VERSION 5.8 ;
BUSBITCHARS "[]" ;
DIVIDERCHAR "/" ;
UNITS
    DATABASE MICRONS 1000 ;
END UNITS

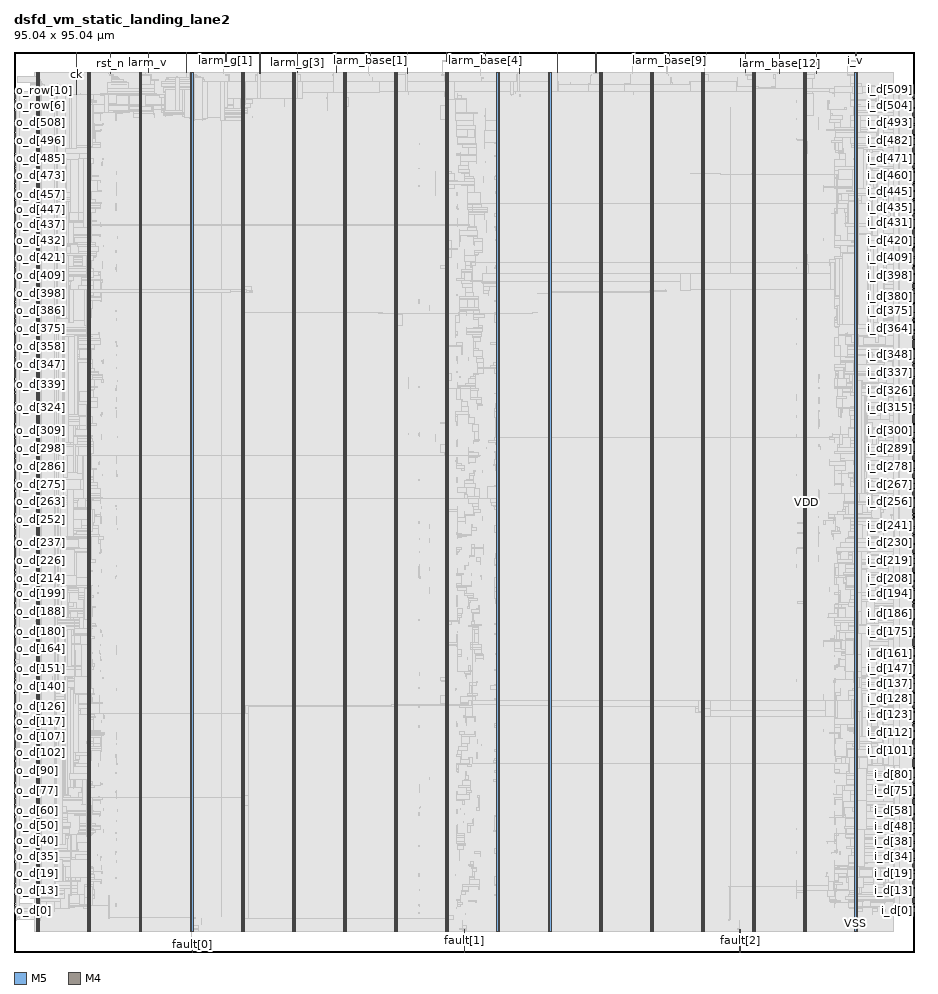
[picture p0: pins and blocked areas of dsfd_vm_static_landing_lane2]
MACRO dsfd_vm_static_landing_lane2
  FOREIGN dsfd_vm_static_landing_lane2 0 0 ;
  CLASS BLOCK ;
  SIZE 95.04 BY 95.04 ;
  PIN ck
    DIRECTION INPUT ;
    USE SIGNAL ;
    PORT
      LAYER M5 ;
        RECT  6.576 94.848 6.6 95.04 ;
    END
    PORT
      LAYER M5 ;
        RECT  6.576 90.563 6.6 94.864 ;
    END
  END ck
  PIN fault[0]
    DIRECTION OUTPUT ;
    USE SIGNAL ;
    PORT
      LAYER M5 ;
        RECT  18.816 0 18.84 0.192 ;
    END
    PORT
      LAYER M5 ;
        RECT  18.816 0.144 18.84 0.227 ;
    END
  END fault[0]
  PIN fault[1]
    DIRECTION OUTPUT ;
    USE SIGNAL ;
    PORT
      LAYER M5 ;
        RECT  47.568 0 47.592 0.192 ;
    END
    PORT
      LAYER M5 ;
        RECT  47.568 0.144 47.592 2.339 ;
    END
  END fault[1]
  PIN fault[2]
    DIRECTION OUTPUT ;
    USE SIGNAL ;
    PORT
      LAYER M5 ;
        RECT  76.656 0 76.68 0.192 ;
    END
    PORT
      LAYER M5 ;
        RECT  76.656 0.144 76.68 2.339 ;
    END
  END fault[2]
  PIN i_d[0]
    DIRECTION INPUT ;
    USE SIGNAL ;
    PORT
      LAYER M4 ;
        RECT  94.848 4.32 95.04 4.344 ;
    END
  END i_d[0]
  PIN i_d[100]
    DIRECTION INPUT ;
    USE SIGNAL ;
    PORT
      LAYER M4 ;
        RECT  94.848 21.168 95.04 21.192 ;
    END
  END i_d[100]
  PIN i_d[101]
    DIRECTION INPUT ;
    USE SIGNAL ;
    PORT
      LAYER M4 ;
        RECT  94.848 21.312 95.04 21.336 ;
    END
  END i_d[101]
  PIN i_d[102]
    DIRECTION INPUT ;
    USE SIGNAL ;
    PORT
      LAYER M4 ;
        RECT  94.848 21.6 95.04 21.624 ;
    END
  END i_d[102]
  PIN i_d[103]
    DIRECTION INPUT ;
    USE SIGNAL ;
    PORT
      LAYER M4 ;
        RECT  94.848 21.744 95.04 21.768 ;
    END
  END i_d[103]
  PIN i_d[104]
    DIRECTION INPUT ;
    USE SIGNAL ;
    PORT
      LAYER M4 ;
        RECT  94.848 21.888 95.04 21.912 ;
    END
  END i_d[104]
  PIN i_d[105]
    DIRECTION INPUT ;
    USE SIGNAL ;
    PORT
      LAYER M4 ;
        RECT  94.848 22.032 95.04 22.056 ;
    END
  END i_d[105]
  PIN i_d[106]
    DIRECTION INPUT ;
    USE SIGNAL ;
    PORT
      LAYER M4 ;
        RECT  94.848 22.176 95.04 22.2 ;
    END
  END i_d[106]
  PIN i_d[107]
    DIRECTION INPUT ;
    USE SIGNAL ;
    PORT
      LAYER M4 ;
        RECT  94.848 22.32 95.04 22.344 ;
    END
  END i_d[107]
  PIN i_d[108]
    DIRECTION INPUT ;
    USE SIGNAL ;
    PORT
      LAYER M4 ;
        RECT  94.848 22.608 95.04 22.632 ;
    END
  END i_d[108]
  PIN i_d[109]
    DIRECTION INPUT ;
    USE SIGNAL ;
    PORT
      LAYER M4 ;
        RECT  94.848 22.752 95.04 22.776 ;
    END
  END i_d[109]
  PIN i_d[10]
    DIRECTION INPUT ;
    USE SIGNAL ;
    PORT
      LAYER M4 ;
        RECT  94.848 6.048 95.04 6.072 ;
    END
  END i_d[10]
  PIN i_d[110]
    DIRECTION INPUT ;
    USE SIGNAL ;
    PORT
      LAYER M4 ;
        RECT  94.848 22.896 95.04 22.92 ;
    END
  END i_d[110]
  PIN i_d[111]
    DIRECTION INPUT ;
    USE SIGNAL ;
    PORT
      LAYER M4 ;
        RECT  94.848 23.04 95.04 23.064 ;
    END
  END i_d[111]
  PIN i_d[112]
    DIRECTION INPUT ;
    USE SIGNAL ;
    PORT
      LAYER M4 ;
        RECT  94.848 23.184 95.04 23.208 ;
    END
  END i_d[112]
  PIN i_d[113]
    DIRECTION INPUT ;
    USE SIGNAL ;
    PORT
      LAYER M4 ;
        RECT  94.848 23.472 95.04 23.496 ;
    END
  END i_d[113]
  PIN i_d[114]
    DIRECTION INPUT ;
    USE SIGNAL ;
    PORT
      LAYER M4 ;
        RECT  94.848 23.616 95.04 23.64 ;
    END
  END i_d[114]
  PIN i_d[115]
    DIRECTION INPUT ;
    USE SIGNAL ;
    PORT
      LAYER M4 ;
        RECT  94.848 23.76 95.04 23.784 ;
    END
  END i_d[115]
  PIN i_d[116]
    DIRECTION INPUT ;
    USE SIGNAL ;
    PORT
      LAYER M4 ;
        RECT  94.848 23.904 95.04 23.928 ;
    END
  END i_d[116]
  PIN i_d[117]
    DIRECTION INPUT ;
    USE SIGNAL ;
    PORT
      LAYER M4 ;
        RECT  94.848 24.048 95.04 24.072 ;
    END
  END i_d[117]
  PIN i_d[118]
    DIRECTION INPUT ;
    USE SIGNAL ;
    PORT
      LAYER M4 ;
        RECT  94.848 24.192 95.04 24.216 ;
    END
  END i_d[118]
  PIN i_d[119]
    DIRECTION INPUT ;
    USE SIGNAL ;
    PORT
      LAYER M4 ;
        RECT  94.848 24.48 95.04 24.504 ;
    END
  END i_d[119]
  PIN i_d[11]
    DIRECTION INPUT ;
    USE SIGNAL ;
    PORT
      LAYER M4 ;
        RECT  94.848 6.192 95.04 6.216 ;
    END
  END i_d[11]
  PIN i_d[120]
    DIRECTION INPUT ;
    USE SIGNAL ;
    PORT
      LAYER M4 ;
        RECT  94.848 24.624 95.04 24.648 ;
    END
  END i_d[120]
  PIN i_d[121]
    DIRECTION INPUT ;
    USE SIGNAL ;
    PORT
      LAYER M4 ;
        RECT  94.848 24.768 95.04 24.792 ;
    END
  END i_d[121]
  PIN i_d[122]
    DIRECTION INPUT ;
    USE SIGNAL ;
    PORT
      LAYER M4 ;
        RECT  94.848 24.912 95.04 24.936 ;
    END
  END i_d[122]
  PIN i_d[123]
    DIRECTION INPUT ;
    USE SIGNAL ;
    PORT
      LAYER M4 ;
        RECT  94.848 25.056 95.04 25.08 ;
    END
  END i_d[123]
  PIN i_d[124]
    DIRECTION INPUT ;
    USE SIGNAL ;
    PORT
      LAYER M4 ;
        RECT  94.848 25.2 95.04 25.224 ;
    END
  END i_d[124]
  PIN i_d[125]
    DIRECTION INPUT ;
    USE SIGNAL ;
    PORT
      LAYER M4 ;
        RECT  94.848 25.488 95.04 25.512 ;
    END
  END i_d[125]
  PIN i_d[126]
    DIRECTION INPUT ;
    USE SIGNAL ;
    PORT
      LAYER M4 ;
        RECT  94.848 25.632 95.04 25.656 ;
    END
  END i_d[126]
  PIN i_d[127]
    DIRECTION INPUT ;
    USE SIGNAL ;
    PORT
      LAYER M4 ;
        RECT  94.848 25.776 95.04 25.8 ;
    END
  END i_d[127]
  PIN i_d[128]
    DIRECTION INPUT ;
    USE SIGNAL ;
    PORT
      LAYER M4 ;
        RECT  94.848 25.92 95.04 25.944 ;
    END
  END i_d[128]
  PIN i_d[129]
    DIRECTION INPUT ;
    USE SIGNAL ;
    PORT
      LAYER M4 ;
        RECT  94.848 26.064 95.04 26.088 ;
    END
  END i_d[129]
  PIN i_d[12]
    DIRECTION INPUT ;
    USE SIGNAL ;
    PORT
      LAYER M4 ;
        RECT  94.848 6.336 95.04 6.36 ;
    END
  END i_d[12]
  PIN i_d[130]
    DIRECTION INPUT ;
    USE SIGNAL ;
    PORT
      LAYER M4 ;
        RECT  94.848 26.208 95.04 26.232 ;
    END
  END i_d[130]
  PIN i_d[131]
    DIRECTION INPUT ;
    USE SIGNAL ;
    PORT
      LAYER M4 ;
        RECT  94.848 26.496 95.04 26.52 ;
    END
  END i_d[131]
  PIN i_d[132]
    DIRECTION INPUT ;
    USE SIGNAL ;
    PORT
      LAYER M4 ;
        RECT  94.848 26.64 95.04 26.664 ;
    END
  END i_d[132]
  PIN i_d[133]
    DIRECTION INPUT ;
    USE SIGNAL ;
    PORT
      LAYER M4 ;
        RECT  94.848 26.784 95.04 26.808 ;
    END
  END i_d[133]
  PIN i_d[134]
    DIRECTION INPUT ;
    USE SIGNAL ;
    PORT
      LAYER M4 ;
        RECT  94.848 26.928 95.04 26.952 ;
    END
  END i_d[134]
  PIN i_d[135]
    DIRECTION INPUT ;
    USE SIGNAL ;
    PORT
      LAYER M4 ;
        RECT  94.848 27.072 95.04 27.096 ;
    END
  END i_d[135]
  PIN i_d[136]
    DIRECTION INPUT ;
    USE SIGNAL ;
    PORT
      LAYER M4 ;
        RECT  94.848 27.216 95.04 27.24 ;
    END
  END i_d[136]
  PIN i_d[137]
    DIRECTION INPUT ;
    USE SIGNAL ;
    PORT
      LAYER M4 ;
        RECT  94.848 27.504 95.04 27.528 ;
    END
  END i_d[137]
  PIN i_d[138]
    DIRECTION INPUT ;
    USE SIGNAL ;
    PORT
      LAYER M4 ;
        RECT  94.848 27.648 95.04 27.672 ;
    END
  END i_d[138]
  PIN i_d[139]
    DIRECTION INPUT ;
    USE SIGNAL ;
    PORT
      LAYER M4 ;
        RECT  94.848 27.792 95.04 27.816 ;
    END
  END i_d[139]
  PIN i_d[13]
    DIRECTION INPUT ;
    USE SIGNAL ;
    PORT
      LAYER M4 ;
        RECT  94.848 6.48 95.04 6.504 ;
    END
  END i_d[13]
  PIN i_d[140]
    DIRECTION INPUT ;
    USE SIGNAL ;
    PORT
      LAYER M4 ;
        RECT  94.848 27.936 95.04 27.96 ;
    END
  END i_d[140]
  PIN i_d[141]
    DIRECTION INPUT ;
    USE SIGNAL ;
    PORT
      LAYER M4 ;
        RECT  94.848 28.08 95.04 28.104 ;
    END
  END i_d[141]
  PIN i_d[142]
    DIRECTION INPUT ;
    USE SIGNAL ;
    PORT
      LAYER M4 ;
        RECT  94.848 28.224 95.04 28.248 ;
    END
  END i_d[142]
  PIN i_d[143]
    DIRECTION INPUT ;
    USE SIGNAL ;
    PORT
      LAYER M4 ;
        RECT  94.848 28.512 95.04 28.536 ;
    END
  END i_d[143]
  PIN i_d[144]
    DIRECTION INPUT ;
    USE SIGNAL ;
    PORT
      LAYER M4 ;
        RECT  94.848 28.656 95.04 28.68 ;
    END
  END i_d[144]
  PIN i_d[145]
    DIRECTION INPUT ;
    USE SIGNAL ;
    PORT
      LAYER M4 ;
        RECT  94.848 28.8 95.04 28.824 ;
    END
  END i_d[145]
  PIN i_d[146]
    DIRECTION INPUT ;
    USE SIGNAL ;
    PORT
      LAYER M4 ;
        RECT  94.848 28.944 95.04 28.968 ;
    END
  END i_d[146]
  PIN i_d[147]
    DIRECTION INPUT ;
    USE SIGNAL ;
    PORT
      LAYER M4 ;
        RECT  94.848 29.088 95.04 29.112 ;
    END
  END i_d[147]
  PIN i_d[148]
    DIRECTION INPUT ;
    USE SIGNAL ;
    PORT
      LAYER M4 ;
        RECT  94.848 29.376 95.04 29.4 ;
    END
  END i_d[148]
  PIN i_d[149]
    DIRECTION INPUT ;
    USE SIGNAL ;
    PORT
      LAYER M4 ;
        RECT  94.848 29.52 95.04 29.544 ;
    END
  END i_d[149]
  PIN i_d[14]
    DIRECTION INPUT ;
    USE SIGNAL ;
    PORT
      LAYER M4 ;
        RECT  94.848 6.624 95.04 6.648 ;
    END
  END i_d[14]
  PIN i_d[150]
    DIRECTION INPUT ;
    USE SIGNAL ;
    PORT
      LAYER M4 ;
        RECT  94.848 29.664 95.04 29.688 ;
    END
  END i_d[150]
  PIN i_d[151]
    DIRECTION INPUT ;
    USE SIGNAL ;
    PORT
      LAYER M4 ;
        RECT  94.848 29.808 95.04 29.832 ;
    END
  END i_d[151]
  PIN i_d[152]
    DIRECTION INPUT ;
    USE SIGNAL ;
    PORT
      LAYER M4 ;
        RECT  94.848 29.952 95.04 29.976 ;
    END
  END i_d[152]
  PIN i_d[153]
    DIRECTION INPUT ;
    USE SIGNAL ;
    PORT
      LAYER M4 ;
        RECT  94.848 30.096 95.04 30.12 ;
    END
  END i_d[153]
  PIN i_d[154]
    DIRECTION INPUT ;
    USE SIGNAL ;
    PORT
      LAYER M4 ;
        RECT  94.848 30.384 95.04 30.408 ;
    END
  END i_d[154]
  PIN i_d[155]
    DIRECTION INPUT ;
    USE SIGNAL ;
    PORT
      LAYER M4 ;
        RECT  94.848 30.528 95.04 30.552 ;
    END
  END i_d[155]
  PIN i_d[156]
    DIRECTION INPUT ;
    USE SIGNAL ;
    PORT
      LAYER M4 ;
        RECT  94.848 30.672 95.04 30.696 ;
    END
  END i_d[156]
  PIN i_d[157]
    DIRECTION INPUT ;
    USE SIGNAL ;
    PORT
      LAYER M4 ;
        RECT  94.848 30.816 95.04 30.84 ;
    END
  END i_d[157]
  PIN i_d[158]
    DIRECTION INPUT ;
    USE SIGNAL ;
    PORT
      LAYER M4 ;
        RECT  94.848 30.96 95.04 30.984 ;
    END
  END i_d[158]
  PIN i_d[159]
    DIRECTION INPUT ;
    USE SIGNAL ;
    PORT
      LAYER M4 ;
        RECT  94.848 31.104 95.04 31.128 ;
    END
  END i_d[159]
  PIN i_d[15]
    DIRECTION INPUT ;
    USE SIGNAL ;
    PORT
      LAYER M4 ;
        RECT  94.848 6.912 95.04 6.936 ;
    END
  END i_d[15]
  PIN i_d[160]
    DIRECTION INPUT ;
    USE SIGNAL ;
    PORT
      LAYER M4 ;
        RECT  94.848 31.392 95.04 31.416 ;
    END
  END i_d[160]
  PIN i_d[161]
    DIRECTION INPUT ;
    USE SIGNAL ;
    PORT
      LAYER M4 ;
        RECT  94.848 31.536 95.04 31.56 ;
    END
  END i_d[161]
  PIN i_d[162]
    DIRECTION INPUT ;
    USE SIGNAL ;
    PORT
      LAYER M4 ;
        RECT  94.848 31.68 95.04 31.704 ;
    END
  END i_d[162]
  PIN i_d[163]
    DIRECTION INPUT ;
    USE SIGNAL ;
    PORT
      LAYER M4 ;
        RECT  94.848 31.824 95.04 31.848 ;
    END
  END i_d[163]
  PIN i_d[164]
    DIRECTION INPUT ;
    USE SIGNAL ;
    PORT
      LAYER M4 ;
        RECT  94.848 31.968 95.04 31.992 ;
    END
  END i_d[164]
  PIN i_d[165]
    DIRECTION INPUT ;
    USE SIGNAL ;
    PORT
      LAYER M4 ;
        RECT  94.848 32.112 95.04 32.136 ;
    END
  END i_d[165]
  PIN i_d[166]
    DIRECTION INPUT ;
    USE SIGNAL ;
    PORT
      LAYER M4 ;
        RECT  94.848 32.4 95.04 32.424 ;
    END
  END i_d[166]
  PIN i_d[167]
    DIRECTION INPUT ;
    USE SIGNAL ;
    PORT
      LAYER M4 ;
        RECT  94.848 32.544 95.04 32.568 ;
    END
  END i_d[167]
  PIN i_d[168]
    DIRECTION INPUT ;
    USE SIGNAL ;
    PORT
      LAYER M4 ;
        RECT  94.848 32.688 95.04 32.712 ;
    END
  END i_d[168]
  PIN i_d[169]
    DIRECTION INPUT ;
    USE SIGNAL ;
    PORT
      LAYER M4 ;
        RECT  94.848 32.832 95.04 32.856 ;
    END
  END i_d[169]
  PIN i_d[16]
    DIRECTION INPUT ;
    USE SIGNAL ;
    PORT
      LAYER M4 ;
        RECT  94.848 7.056 95.04 7.08 ;
    END
  END i_d[16]
  PIN i_d[170]
    DIRECTION INPUT ;
    USE SIGNAL ;
    PORT
      LAYER M4 ;
        RECT  94.848 32.976 95.04 33 ;
    END
  END i_d[170]
  PIN i_d[171]
    DIRECTION INPUT ;
    USE SIGNAL ;
    PORT
      LAYER M4 ;
        RECT  94.848 33.12 95.04 33.144 ;
    END
  END i_d[171]
  PIN i_d[172]
    DIRECTION INPUT ;
    USE SIGNAL ;
    PORT
      LAYER M4 ;
        RECT  94.848 33.408 95.04 33.432 ;
    END
  END i_d[172]
  PIN i_d[173]
    DIRECTION INPUT ;
    USE SIGNAL ;
    PORT
      LAYER M4 ;
        RECT  94.848 33.552 95.04 33.576 ;
    END
  END i_d[173]
  PIN i_d[174]
    DIRECTION INPUT ;
    USE SIGNAL ;
    PORT
      LAYER M4 ;
        RECT  94.848 33.696 95.04 33.72 ;
    END
  END i_d[174]
  PIN i_d[175]
    DIRECTION INPUT ;
    USE SIGNAL ;
    PORT
      LAYER M4 ;
        RECT  94.848 33.84 95.04 33.864 ;
    END
  END i_d[175]
  PIN i_d[176]
    DIRECTION INPUT ;
    USE SIGNAL ;
    PORT
      LAYER M4 ;
        RECT  94.848 33.984 95.04 34.008 ;
    END
  END i_d[176]
  PIN i_d[177]
    DIRECTION INPUT ;
    USE SIGNAL ;
    PORT
      LAYER M4 ;
        RECT  94.848 34.272 95.04 34.296 ;
    END
  END i_d[177]
  PIN i_d[178]
    DIRECTION INPUT ;
    USE SIGNAL ;
    PORT
      LAYER M4 ;
        RECT  94.848 34.416 95.04 34.44 ;
    END
  END i_d[178]
  PIN i_d[179]
    DIRECTION INPUT ;
    USE SIGNAL ;
    PORT
      LAYER M4 ;
        RECT  94.848 34.56 95.04 34.584 ;
    END
  END i_d[179]
  PIN i_d[17]
    DIRECTION INPUT ;
    USE SIGNAL ;
    PORT
      LAYER M4 ;
        RECT  94.848 7.2 95.04 7.224 ;
    END
  END i_d[17]
  PIN i_d[180]
    DIRECTION INPUT ;
    USE SIGNAL ;
    PORT
      LAYER M4 ;
        RECT  94.848 34.704 95.04 34.728 ;
    END
  END i_d[180]
  PIN i_d[181]
    DIRECTION INPUT ;
    USE SIGNAL ;
    PORT
      LAYER M4 ;
        RECT  94.848 34.848 95.04 34.872 ;
    END
  END i_d[181]
  PIN i_d[182]
    DIRECTION INPUT ;
    USE SIGNAL ;
    PORT
      LAYER M4 ;
        RECT  94.848 34.992 95.04 35.016 ;
    END
  END i_d[182]
  PIN i_d[183]
    DIRECTION INPUT ;
    USE SIGNAL ;
    PORT
      LAYER M4 ;
        RECT  94.848 35.28 95.04 35.304 ;
    END
  END i_d[183]
  PIN i_d[184]
    DIRECTION INPUT ;
    USE SIGNAL ;
    PORT
      LAYER M4 ;
        RECT  94.848 35.424 95.04 35.448 ;
    END
  END i_d[184]
  PIN i_d[185]
    DIRECTION INPUT ;
    USE SIGNAL ;
    PORT
      LAYER M4 ;
        RECT  94.848 35.568 95.04 35.592 ;
    END
  END i_d[185]
  PIN i_d[186]
    DIRECTION INPUT ;
    USE SIGNAL ;
    PORT
      LAYER M4 ;
        RECT  94.848 35.712 95.04 35.736 ;
    END
  END i_d[186]
  PIN i_d[187]
    DIRECTION INPUT ;
    USE SIGNAL ;
    PORT
      LAYER M4 ;
        RECT  94.848 35.856 95.04 35.88 ;
    END
  END i_d[187]
  PIN i_d[188]
    DIRECTION INPUT ;
    USE SIGNAL ;
    PORT
      LAYER M4 ;
        RECT  94.848 36 95.04 36.024 ;
    END
  END i_d[188]
  PIN i_d[189]
    DIRECTION INPUT ;
    USE SIGNAL ;
    PORT
      LAYER M4 ;
        RECT  94.848 36.288 95.04 36.312 ;
    END
  END i_d[189]
  PIN i_d[18]
    DIRECTION INPUT ;
    USE SIGNAL ;
    PORT
      LAYER M4 ;
        RECT  94.848 7.344 95.04 7.368 ;
    END
  END i_d[18]
  PIN i_d[190]
    DIRECTION INPUT ;
    USE SIGNAL ;
    PORT
      LAYER M4 ;
        RECT  94.848 36.432 95.04 36.456 ;
    END
  END i_d[190]
  PIN i_d[191]
    DIRECTION INPUT ;
    USE SIGNAL ;
    PORT
      LAYER M4 ;
        RECT  94.848 36.576 95.04 36.6 ;
    END
  END i_d[191]
  PIN i_d[192]
    DIRECTION INPUT ;
    USE SIGNAL ;
    PORT
      LAYER M4 ;
        RECT  94.848 36.72 95.04 36.744 ;
    END
  END i_d[192]
  PIN i_d[193]
    DIRECTION INPUT ;
    USE SIGNAL ;
    PORT
      LAYER M4 ;
        RECT  94.848 36.864 95.04 36.888 ;
    END
  END i_d[193]
  PIN i_d[194]
    DIRECTION INPUT ;
    USE SIGNAL ;
    PORT
      LAYER M4 ;
        RECT  94.848 37.008 95.04 37.032 ;
    END
  END i_d[194]
  PIN i_d[195]
    DIRECTION INPUT ;
    USE SIGNAL ;
    PORT
      LAYER M4 ;
        RECT  94.848 37.296 95.04 37.32 ;
    END
  END i_d[195]
  PIN i_d[196]
    DIRECTION INPUT ;
    USE SIGNAL ;
    PORT
      LAYER M4 ;
        RECT  94.848 37.44 95.04 37.464 ;
    END
  END i_d[196]
  PIN i_d[197]
    DIRECTION INPUT ;
    USE SIGNAL ;
    PORT
      LAYER M4 ;
        RECT  94.848 37.584 95.04 37.608 ;
    END
  END i_d[197]
  PIN i_d[198]
    DIRECTION INPUT ;
    USE SIGNAL ;
    PORT
      LAYER M4 ;
        RECT  94.848 37.728 95.04 37.752 ;
    END
  END i_d[198]
  PIN i_d[199]
    DIRECTION INPUT ;
    USE SIGNAL ;
    PORT
      LAYER M4 ;
        RECT  94.848 37.872 95.04 37.896 ;
    END
  END i_d[199]
  PIN i_d[19]
    DIRECTION INPUT ;
    USE SIGNAL ;
    PORT
      LAYER M4 ;
        RECT  94.848 7.488 95.04 7.512 ;
    END
  END i_d[19]
  PIN i_d[1]
    DIRECTION INPUT ;
    USE SIGNAL ;
    PORT
      LAYER M4 ;
        RECT  94.848 4.464 95.04 4.488 ;
    END
  END i_d[1]
  PIN i_d[200]
    DIRECTION INPUT ;
    USE SIGNAL ;
    PORT
      LAYER M4 ;
        RECT  94.848 38.016 95.04 38.04 ;
    END
  END i_d[200]
  PIN i_d[201]
    DIRECTION INPUT ;
    USE SIGNAL ;
    PORT
      LAYER M4 ;
        RECT  94.848 38.304 95.04 38.328 ;
    END
  END i_d[201]
  PIN i_d[202]
    DIRECTION INPUT ;
    USE SIGNAL ;
    PORT
      LAYER M4 ;
        RECT  94.848 38.448 95.04 38.472 ;
    END
  END i_d[202]
  PIN i_d[203]
    DIRECTION INPUT ;
    USE SIGNAL ;
    PORT
      LAYER M4 ;
        RECT  94.848 38.592 95.04 38.616 ;
    END
  END i_d[203]
  PIN i_d[204]
    DIRECTION INPUT ;
    USE SIGNAL ;
    PORT
      LAYER M4 ;
        RECT  94.848 38.736 95.04 38.76 ;
    END
  END i_d[204]
  PIN i_d[205]
    DIRECTION INPUT ;
    USE SIGNAL ;
    PORT
      LAYER M4 ;
        RECT  94.848 38.88 95.04 38.904 ;
    END
  END i_d[205]
  PIN i_d[206]
    DIRECTION INPUT ;
    USE SIGNAL ;
    PORT
      LAYER M4 ;
        RECT  94.848 39.024 95.04 39.048 ;
    END
  END i_d[206]
  PIN i_d[207]
    DIRECTION INPUT ;
    USE SIGNAL ;
    PORT
      LAYER M4 ;
        RECT  94.848 39.312 95.04 39.336 ;
    END
  END i_d[207]
  PIN i_d[208]
    DIRECTION INPUT ;
    USE SIGNAL ;
    PORT
      LAYER M4 ;
        RECT  94.848 39.456 95.04 39.48 ;
    END
  END i_d[208]
  PIN i_d[209]
    DIRECTION INPUT ;
    USE SIGNAL ;
    PORT
      LAYER M4 ;
        RECT  94.848 39.6 95.04 39.624 ;
    END
  END i_d[209]
  PIN i_d[20]
    DIRECTION INPUT ;
    USE SIGNAL ;
    PORT
      LAYER M4 ;
        RECT  94.848 7.776 95.04 7.8 ;
    END
  END i_d[20]
  PIN i_d[210]
    DIRECTION INPUT ;
    USE SIGNAL ;
    PORT
      LAYER M4 ;
        RECT  94.848 39.744 95.04 39.768 ;
    END
  END i_d[210]
  PIN i_d[211]
    DIRECTION INPUT ;
    USE SIGNAL ;
    PORT
      LAYER M4 ;
        RECT  94.848 39.888 95.04 39.912 ;
    END
  END i_d[211]
  PIN i_d[212]
    DIRECTION INPUT ;
    USE SIGNAL ;
    PORT
      LAYER M4 ;
        RECT  94.848 40.176 95.04 40.2 ;
    END
  END i_d[212]
  PIN i_d[213]
    DIRECTION INPUT ;
    USE SIGNAL ;
    PORT
      LAYER M4 ;
        RECT  94.848 40.32 95.04 40.344 ;
    END
  END i_d[213]
  PIN i_d[214]
    DIRECTION INPUT ;
    USE SIGNAL ;
    PORT
      LAYER M4 ;
        RECT  94.848 40.464 95.04 40.488 ;
    END
  END i_d[214]
  PIN i_d[215]
    DIRECTION INPUT ;
    USE SIGNAL ;
    PORT
      LAYER M4 ;
        RECT  94.848 40.608 95.04 40.632 ;
    END
  END i_d[215]
  PIN i_d[216]
    DIRECTION INPUT ;
    USE SIGNAL ;
    PORT
      LAYER M4 ;
        RECT  94.848 40.752 95.04 40.776 ;
    END
  END i_d[216]
  PIN i_d[217]
    DIRECTION INPUT ;
    USE SIGNAL ;
    PORT
      LAYER M4 ;
        RECT  94.848 40.896 95.04 40.92 ;
    END
  END i_d[217]
  PIN i_d[218]
    DIRECTION INPUT ;
    USE SIGNAL ;
    PORT
      LAYER M4 ;
        RECT  94.848 41.184 95.04 41.208 ;
    END
  END i_d[218]
  PIN i_d[219]
    DIRECTION INPUT ;
    USE SIGNAL ;
    PORT
      LAYER M4 ;
        RECT  94.848 41.328 95.04 41.352 ;
    END
  END i_d[219]
  PIN i_d[21]
    DIRECTION INPUT ;
    USE SIGNAL ;
    PORT
      LAYER M4 ;
        RECT  94.848 7.92 95.04 7.944 ;
    END
  END i_d[21]
  PIN i_d[220]
    DIRECTION INPUT ;
    USE SIGNAL ;
    PORT
      LAYER M4 ;
        RECT  94.848 41.472 95.04 41.496 ;
    END
  END i_d[220]
  PIN i_d[221]
    DIRECTION INPUT ;
    USE SIGNAL ;
    PORT
      LAYER M4 ;
        RECT  94.848 41.616 95.04 41.64 ;
    END
  END i_d[221]
  PIN i_d[222]
    DIRECTION INPUT ;
    USE SIGNAL ;
    PORT
      LAYER M4 ;
        RECT  94.848 41.76 95.04 41.784 ;
    END
  END i_d[222]
  PIN i_d[223]
    DIRECTION INPUT ;
    USE SIGNAL ;
    PORT
      LAYER M4 ;
        RECT  94.848 41.904 95.04 41.928 ;
    END
  END i_d[223]
  PIN i_d[224]
    DIRECTION INPUT ;
    USE SIGNAL ;
    PORT
      LAYER M4 ;
        RECT  94.848 42.192 95.04 42.216 ;
    END
  END i_d[224]
  PIN i_d[225]
    DIRECTION INPUT ;
    USE SIGNAL ;
    PORT
      LAYER M4 ;
        RECT  94.848 42.336 95.04 42.36 ;
    END
  END i_d[225]
  PIN i_d[226]
    DIRECTION INPUT ;
    USE SIGNAL ;
    PORT
      LAYER M4 ;
        RECT  94.848 42.48 95.04 42.504 ;
    END
  END i_d[226]
  PIN i_d[227]
    DIRECTION INPUT ;
    USE SIGNAL ;
    PORT
      LAYER M4 ;
        RECT  94.848 42.624 95.04 42.648 ;
    END
  END i_d[227]
  PIN i_d[228]
    DIRECTION INPUT ;
    USE SIGNAL ;
    PORT
      LAYER M4 ;
        RECT  94.848 42.768 95.04 42.792 ;
    END
  END i_d[228]
  PIN i_d[229]
    DIRECTION INPUT ;
    USE SIGNAL ;
    PORT
      LAYER M4 ;
        RECT  94.848 42.912 95.04 42.936 ;
    END
  END i_d[229]
  PIN i_d[22]
    DIRECTION INPUT ;
    USE SIGNAL ;
    PORT
      LAYER M4 ;
        RECT  94.848 8.064 95.04 8.088 ;
    END
  END i_d[22]
  PIN i_d[230]
    DIRECTION INPUT ;
    USE SIGNAL ;
    PORT
      LAYER M4 ;
        RECT  94.848 43.2 95.04 43.224 ;
    END
  END i_d[230]
  PIN i_d[231]
    DIRECTION INPUT ;
    USE SIGNAL ;
    PORT
      LAYER M4 ;
        RECT  94.848 43.344 95.04 43.368 ;
    END
  END i_d[231]
  PIN i_d[232]
    DIRECTION INPUT ;
    USE SIGNAL ;
    PORT
      LAYER M4 ;
        RECT  94.848 43.488 95.04 43.512 ;
    END
  END i_d[232]
  PIN i_d[233]
    DIRECTION INPUT ;
    USE SIGNAL ;
    PORT
      LAYER M4 ;
        RECT  94.848 43.632 95.04 43.656 ;
    END
  END i_d[233]
  PIN i_d[234]
    DIRECTION INPUT ;
    USE SIGNAL ;
    PORT
      LAYER M4 ;
        RECT  94.848 43.776 95.04 43.8 ;
    END
  END i_d[234]
  PIN i_d[235]
    DIRECTION INPUT ;
    USE SIGNAL ;
    PORT
      LAYER M4 ;
        RECT  94.848 43.92 95.04 43.944 ;
    END
  END i_d[235]
  PIN i_d[236]
    DIRECTION INPUT ;
    USE SIGNAL ;
    PORT
      LAYER M4 ;
        RECT  94.848 44.208 95.04 44.232 ;
    END
  END i_d[236]
  PIN i_d[237]
    DIRECTION INPUT ;
    USE SIGNAL ;
    PORT
      LAYER M4 ;
        RECT  94.848 44.352 95.04 44.376 ;
    END
  END i_d[237]
  PIN i_d[238]
    DIRECTION INPUT ;
    USE SIGNAL ;
    PORT
      LAYER M4 ;
        RECT  94.848 44.496 95.04 44.52 ;
    END
  END i_d[238]
  PIN i_d[239]
    DIRECTION INPUT ;
    USE SIGNAL ;
    PORT
      LAYER M4 ;
        RECT  94.848 44.64 95.04 44.664 ;
    END
  END i_d[239]
  PIN i_d[23]
    DIRECTION INPUT ;
    USE SIGNAL ;
    PORT
      LAYER M4 ;
        RECT  94.848 8.208 95.04 8.232 ;
    END
  END i_d[23]
  PIN i_d[240]
    DIRECTION INPUT ;
    USE SIGNAL ;
    PORT
      LAYER M4 ;
        RECT  94.848 44.784 95.04 44.808 ;
    END
  END i_d[240]
  PIN i_d[241]
    DIRECTION INPUT ;
    USE SIGNAL ;
    PORT
      LAYER M4 ;
        RECT  94.848 45.072 95.04 45.096 ;
    END
  END i_d[241]
  PIN i_d[242]
    DIRECTION INPUT ;
    USE SIGNAL ;
    PORT
      LAYER M4 ;
        RECT  94.848 45.216 95.04 45.24 ;
    END
  END i_d[242]
  PIN i_d[243]
    DIRECTION INPUT ;
    USE SIGNAL ;
    PORT
      LAYER M4 ;
        RECT  94.848 45.36 95.04 45.384 ;
    END
  END i_d[243]
  PIN i_d[244]
    DIRECTION INPUT ;
    USE SIGNAL ;
    PORT
      LAYER M4 ;
        RECT  94.848 45.504 95.04 45.528 ;
    END
  END i_d[244]
  PIN i_d[245]
    DIRECTION INPUT ;
    USE SIGNAL ;
    PORT
      LAYER M4 ;
        RECT  94.848 45.648 95.04 45.672 ;
    END
  END i_d[245]
  PIN i_d[246]
    DIRECTION INPUT ;
    USE SIGNAL ;
    PORT
      LAYER M4 ;
        RECT  94.848 45.792 95.04 45.816 ;
    END
  END i_d[246]
  PIN i_d[247]
    DIRECTION INPUT ;
    USE SIGNAL ;
    PORT
      LAYER M4 ;
        RECT  94.848 46.08 95.04 46.104 ;
    END
  END i_d[247]
  PIN i_d[248]
    DIRECTION INPUT ;
    USE SIGNAL ;
    PORT
      LAYER M4 ;
        RECT  94.848 46.224 95.04 46.248 ;
    END
  END i_d[248]
  PIN i_d[249]
    DIRECTION INPUT ;
    USE SIGNAL ;
    PORT
      LAYER M4 ;
        RECT  94.848 46.368 95.04 46.392 ;
    END
  END i_d[249]
  PIN i_d[24]
    DIRECTION INPUT ;
    USE SIGNAL ;
    PORT
      LAYER M4 ;
        RECT  94.848 8.352 95.04 8.376 ;
    END
  END i_d[24]
  PIN i_d[250]
    DIRECTION INPUT ;
    USE SIGNAL ;
    PORT
      LAYER M4 ;
        RECT  94.848 46.512 95.04 46.536 ;
    END
  END i_d[250]
  PIN i_d[251]
    DIRECTION INPUT ;
    USE SIGNAL ;
    PORT
      LAYER M4 ;
        RECT  94.848 46.656 95.04 46.68 ;
    END
  END i_d[251]
  PIN i_d[252]
    DIRECTION INPUT ;
    USE SIGNAL ;
    PORT
      LAYER M4 ;
        RECT  94.848 46.8 95.04 46.824 ;
    END
  END i_d[252]
  PIN i_d[253]
    DIRECTION INPUT ;
    USE SIGNAL ;
    PORT
      LAYER M4 ;
        RECT  94.848 47.088 95.04 47.112 ;
    END
  END i_d[253]
  PIN i_d[254]
    DIRECTION INPUT ;
    USE SIGNAL ;
    PORT
      LAYER M4 ;
        RECT  94.848 47.232 95.04 47.256 ;
    END
  END i_d[254]
  PIN i_d[255]
    DIRECTION INPUT ;
    USE SIGNAL ;
    PORT
      LAYER M4 ;
        RECT  94.848 47.376 95.04 47.4 ;
    END
  END i_d[255]
  PIN i_d[256]
    DIRECTION INPUT ;
    USE SIGNAL ;
    PORT
      LAYER M4 ;
        RECT  94.848 47.52 95.04 47.544 ;
    END
  END i_d[256]
  PIN i_d[257]
    DIRECTION INPUT ;
    USE SIGNAL ;
    PORT
      LAYER M4 ;
        RECT  94.848 47.664 95.04 47.688 ;
    END
  END i_d[257]
  PIN i_d[258]
    DIRECTION INPUT ;
    USE SIGNAL ;
    PORT
      LAYER M4 ;
        RECT  94.848 47.808 95.04 47.832 ;
    END
  END i_d[258]
  PIN i_d[259]
    DIRECTION INPUT ;
    USE SIGNAL ;
    PORT
      LAYER M4 ;
        RECT  94.848 48.096 95.04 48.12 ;
    END
  END i_d[259]
  PIN i_d[25]
    DIRECTION INPUT ;
    USE SIGNAL ;
    PORT
      LAYER M4 ;
        RECT  94.848 8.496 95.04 8.52 ;
    END
  END i_d[25]
  PIN i_d[260]
    DIRECTION INPUT ;
    USE SIGNAL ;
    PORT
      LAYER M4 ;
        RECT  94.848 48.24 95.04 48.264 ;
    END
  END i_d[260]
  PIN i_d[261]
    DIRECTION INPUT ;
    USE SIGNAL ;
    PORT
      LAYER M4 ;
        RECT  94.848 48.384 95.04 48.408 ;
    END
  END i_d[261]
  PIN i_d[262]
    DIRECTION INPUT ;
    USE SIGNAL ;
    PORT
      LAYER M4 ;
        RECT  94.848 48.528 95.04 48.552 ;
    END
  END i_d[262]
  PIN i_d[263]
    DIRECTION INPUT ;
    USE SIGNAL ;
    PORT
      LAYER M4 ;
        RECT  94.848 48.672 95.04 48.696 ;
    END
  END i_d[263]
  PIN i_d[264]
    DIRECTION INPUT ;
    USE SIGNAL ;
    PORT
      LAYER M4 ;
        RECT  94.848 48.816 95.04 48.84 ;
    END
  END i_d[264]
  PIN i_d[265]
    DIRECTION INPUT ;
    USE SIGNAL ;
    PORT
      LAYER M4 ;
        RECT  94.848 49.104 95.04 49.128 ;
    END
  END i_d[265]
  PIN i_d[266]
    DIRECTION INPUT ;
    USE SIGNAL ;
    PORT
      LAYER M4 ;
        RECT  94.848 49.248 95.04 49.272 ;
    END
  END i_d[266]
  PIN i_d[267]
    DIRECTION INPUT ;
    USE SIGNAL ;
    PORT
      LAYER M4 ;
        RECT  94.848 49.392 95.04 49.416 ;
    END
  END i_d[267]
  PIN i_d[268]
    DIRECTION INPUT ;
    USE SIGNAL ;
    PORT
      LAYER M4 ;
        RECT  94.848 49.536 95.04 49.56 ;
    END
  END i_d[268]
  PIN i_d[269]
    DIRECTION INPUT ;
    USE SIGNAL ;
    PORT
      LAYER M4 ;
        RECT  94.848 49.68 95.04 49.704 ;
    END
  END i_d[269]
  PIN i_d[26]
    DIRECTION INPUT ;
    USE SIGNAL ;
    PORT
      LAYER M4 ;
        RECT  94.848 8.784 95.04 8.808 ;
    END
  END i_d[26]
  PIN i_d[270]
    DIRECTION INPUT ;
    USE SIGNAL ;
    PORT
      LAYER M4 ;
        RECT  94.848 49.824 95.04 49.848 ;
    END
  END i_d[270]
  PIN i_d[271]
    DIRECTION INPUT ;
    USE SIGNAL ;
    PORT
      LAYER M4 ;
        RECT  94.848 50.112 95.04 50.136 ;
    END
  END i_d[271]
  PIN i_d[272]
    DIRECTION INPUT ;
    USE SIGNAL ;
    PORT
      LAYER M4 ;
        RECT  94.848 50.256 95.04 50.28 ;
    END
  END i_d[272]
  PIN i_d[273]
    DIRECTION INPUT ;
    USE SIGNAL ;
    PORT
      LAYER M4 ;
        RECT  94.848 50.4 95.04 50.424 ;
    END
  END i_d[273]
  PIN i_d[274]
    DIRECTION INPUT ;
    USE SIGNAL ;
    PORT
      LAYER M4 ;
        RECT  94.848 50.544 95.04 50.568 ;
    END
  END i_d[274]
  PIN i_d[275]
    DIRECTION INPUT ;
    USE SIGNAL ;
    PORT
      LAYER M4 ;
        RECT  94.848 50.688 95.04 50.712 ;
    END
  END i_d[275]
  PIN i_d[276]
    DIRECTION INPUT ;
    USE SIGNAL ;
    PORT
      LAYER M4 ;
        RECT  94.848 50.976 95.04 51 ;
    END
  END i_d[276]
  PIN i_d[277]
    DIRECTION INPUT ;
    USE SIGNAL ;
    PORT
      LAYER M4 ;
        RECT  94.848 51.12 95.04 51.144 ;
    END
  END i_d[277]
  PIN i_d[278]
    DIRECTION INPUT ;
    USE SIGNAL ;
    PORT
      LAYER M4 ;
        RECT  94.848 51.264 95.04 51.288 ;
    END
  END i_d[278]
  PIN i_d[279]
    DIRECTION INPUT ;
    USE SIGNAL ;
    PORT
      LAYER M4 ;
        RECT  94.848 51.408 95.04 51.432 ;
    END
  END i_d[279]
  PIN i_d[27]
    DIRECTION INPUT ;
    USE SIGNAL ;
    PORT
      LAYER M4 ;
        RECT  94.848 8.928 95.04 8.952 ;
    END
  END i_d[27]
  PIN i_d[280]
    DIRECTION INPUT ;
    USE SIGNAL ;
    PORT
      LAYER M4 ;
        RECT  94.848 51.552 95.04 51.576 ;
    END
  END i_d[280]
  PIN i_d[281]
    DIRECTION INPUT ;
    USE SIGNAL ;
    PORT
      LAYER M4 ;
        RECT  94.848 51.696 95.04 51.72 ;
    END
  END i_d[281]
  PIN i_d[282]
    DIRECTION INPUT ;
    USE SIGNAL ;
    PORT
      LAYER M4 ;
        RECT  94.848 51.984 95.04 52.008 ;
    END
  END i_d[282]
  PIN i_d[283]
    DIRECTION INPUT ;
    USE SIGNAL ;
    PORT
      LAYER M4 ;
        RECT  94.848 52.128 95.04 52.152 ;
    END
  END i_d[283]
  PIN i_d[284]
    DIRECTION INPUT ;
    USE SIGNAL ;
    PORT
      LAYER M4 ;
        RECT  94.848 52.272 95.04 52.296 ;
    END
  END i_d[284]
  PIN i_d[285]
    DIRECTION INPUT ;
    USE SIGNAL ;
    PORT
      LAYER M4 ;
        RECT  94.848 52.416 95.04 52.44 ;
    END
  END i_d[285]
  PIN i_d[286]
    DIRECTION INPUT ;
    USE SIGNAL ;
    PORT
      LAYER M4 ;
        RECT  94.848 52.56 95.04 52.584 ;
    END
  END i_d[286]
  PIN i_d[287]
    DIRECTION INPUT ;
    USE SIGNAL ;
    PORT
      LAYER M4 ;
        RECT  94.848 52.704 95.04 52.728 ;
    END
  END i_d[287]
  PIN i_d[288]
    DIRECTION INPUT ;
    USE SIGNAL ;
    PORT
      LAYER M4 ;
        RECT  94.848 52.992 95.04 53.016 ;
    END
  END i_d[288]
  PIN i_d[289]
    DIRECTION INPUT ;
    USE SIGNAL ;
    PORT
      LAYER M4 ;
        RECT  94.848 53.136 95.04 53.16 ;
    END
  END i_d[289]
  PIN i_d[28]
    DIRECTION INPUT ;
    USE SIGNAL ;
    PORT
      LAYER M4 ;
        RECT  94.848 9.072 95.04 9.096 ;
    END
  END i_d[28]
  PIN i_d[290]
    DIRECTION INPUT ;
    USE SIGNAL ;
    PORT
      LAYER M4 ;
        RECT  94.848 53.28 95.04 53.304 ;
    END
  END i_d[290]
  PIN i_d[291]
    DIRECTION INPUT ;
    USE SIGNAL ;
    PORT
      LAYER M4 ;
        RECT  94.848 53.424 95.04 53.448 ;
    END
  END i_d[291]
  PIN i_d[292]
    DIRECTION INPUT ;
    USE SIGNAL ;
    PORT
      LAYER M4 ;
        RECT  94.848 53.568 95.04 53.592 ;
    END
  END i_d[292]
  PIN i_d[293]
    DIRECTION INPUT ;
    USE SIGNAL ;
    PORT
      LAYER M4 ;
        RECT  94.848 53.712 95.04 53.736 ;
    END
  END i_d[293]
  PIN i_d[294]
    DIRECTION INPUT ;
    USE SIGNAL ;
    PORT
      LAYER M4 ;
        RECT  94.848 54 95.04 54.024 ;
    END
  END i_d[294]
  PIN i_d[295]
    DIRECTION INPUT ;
    USE SIGNAL ;
    PORT
      LAYER M4 ;
        RECT  94.848 54.144 95.04 54.168 ;
    END
  END i_d[295]
  PIN i_d[296]
    DIRECTION INPUT ;
    USE SIGNAL ;
    PORT
      LAYER M4 ;
        RECT  94.848 54.288 95.04 54.312 ;
    END
  END i_d[296]
  PIN i_d[297]
    DIRECTION INPUT ;
    USE SIGNAL ;
    PORT
      LAYER M4 ;
        RECT  94.848 54.432 95.04 54.456 ;
    END
  END i_d[297]
  PIN i_d[298]
    DIRECTION INPUT ;
    USE SIGNAL ;
    PORT
      LAYER M4 ;
        RECT  94.848 54.576 95.04 54.6 ;
    END
  END i_d[298]
  PIN i_d[299]
    DIRECTION INPUT ;
    USE SIGNAL ;
    PORT
      LAYER M4 ;
        RECT  94.848 54.72 95.04 54.744 ;
    END
  END i_d[299]
  PIN i_d[29]
    DIRECTION INPUT ;
    USE SIGNAL ;
    PORT
      LAYER M4 ;
        RECT  94.848 9.216 95.04 9.24 ;
    END
  END i_d[29]
  PIN i_d[2]
    DIRECTION INPUT ;
    USE SIGNAL ;
    PORT
      LAYER M4 ;
        RECT  94.848 4.608 95.04 4.632 ;
    END
  END i_d[2]
  PIN i_d[300]
    DIRECTION INPUT ;
    USE SIGNAL ;
    PORT
      LAYER M4 ;
        RECT  94.848 55.008 95.04 55.032 ;
    END
  END i_d[300]
  PIN i_d[301]
    DIRECTION INPUT ;
    USE SIGNAL ;
    PORT
      LAYER M4 ;
        RECT  94.848 55.152 95.04 55.176 ;
    END
  END i_d[301]
  PIN i_d[302]
    DIRECTION INPUT ;
    USE SIGNAL ;
    PORT
      LAYER M4 ;
        RECT  94.848 55.296 95.04 55.32 ;
    END
  END i_d[302]
  PIN i_d[303]
    DIRECTION INPUT ;
    USE SIGNAL ;
    PORT
      LAYER M4 ;
        RECT  94.848 55.44 95.04 55.464 ;
    END
  END i_d[303]
  PIN i_d[304]
    DIRECTION INPUT ;
    USE SIGNAL ;
    PORT
      LAYER M4 ;
        RECT  94.848 55.584 95.04 55.608 ;
    END
  END i_d[304]
  PIN i_d[305]
    DIRECTION INPUT ;
    USE SIGNAL ;
    PORT
      LAYER M4 ;
        RECT  94.848 55.872 95.04 55.896 ;
    END
  END i_d[305]
  PIN i_d[306]
    DIRECTION INPUT ;
    USE SIGNAL ;
    PORT
      LAYER M4 ;
        RECT  94.848 56.016 95.04 56.04 ;
    END
  END i_d[306]
  PIN i_d[307]
    DIRECTION INPUT ;
    USE SIGNAL ;
    PORT
      LAYER M4 ;
        RECT  94.848 56.16 95.04 56.184 ;
    END
  END i_d[307]
  PIN i_d[308]
    DIRECTION INPUT ;
    USE SIGNAL ;
    PORT
      LAYER M4 ;
        RECT  94.848 56.304 95.04 56.328 ;
    END
  END i_d[308]
  PIN i_d[309]
    DIRECTION INPUT ;
    USE SIGNAL ;
    PORT
      LAYER M4 ;
        RECT  94.848 56.448 95.04 56.472 ;
    END
  END i_d[309]
  PIN i_d[30]
    DIRECTION INPUT ;
    USE SIGNAL ;
    PORT
      LAYER M4 ;
        RECT  94.848 9.36 95.04 9.384 ;
    END
  END i_d[30]
  PIN i_d[310]
    DIRECTION INPUT ;
    USE SIGNAL ;
    PORT
      LAYER M4 ;
        RECT  94.848 56.592 95.04 56.616 ;
    END
  END i_d[310]
  PIN i_d[311]
    DIRECTION INPUT ;
    USE SIGNAL ;
    PORT
      LAYER M4 ;
        RECT  94.848 56.88 95.04 56.904 ;
    END
  END i_d[311]
  PIN i_d[312]
    DIRECTION INPUT ;
    USE SIGNAL ;
    PORT
      LAYER M4 ;
        RECT  94.848 57.024 95.04 57.048 ;
    END
  END i_d[312]
  PIN i_d[313]
    DIRECTION INPUT ;
    USE SIGNAL ;
    PORT
      LAYER M4 ;
        RECT  94.848 57.168 95.04 57.192 ;
    END
  END i_d[313]
  PIN i_d[314]
    DIRECTION INPUT ;
    USE SIGNAL ;
    PORT
      LAYER M4 ;
        RECT  94.848 57.312 95.04 57.336 ;
    END
  END i_d[314]
  PIN i_d[315]
    DIRECTION INPUT ;
    USE SIGNAL ;
    PORT
      LAYER M4 ;
        RECT  94.848 57.456 95.04 57.48 ;
    END
  END i_d[315]
  PIN i_d[316]
    DIRECTION INPUT ;
    USE SIGNAL ;
    PORT
      LAYER M4 ;
        RECT  94.848 57.6 95.04 57.624 ;
    END
  END i_d[316]
  PIN i_d[317]
    DIRECTION INPUT ;
    USE SIGNAL ;
    PORT
      LAYER M4 ;
        RECT  94.848 57.888 95.04 57.912 ;
    END
  END i_d[317]
  PIN i_d[318]
    DIRECTION INPUT ;
    USE SIGNAL ;
    PORT
      LAYER M4 ;
        RECT  94.848 58.032 95.04 58.056 ;
    END
  END i_d[318]
  PIN i_d[319]
    DIRECTION INPUT ;
    USE SIGNAL ;
    PORT
      LAYER M4 ;
        RECT  94.848 58.176 95.04 58.2 ;
    END
  END i_d[319]
  PIN i_d[31]
    DIRECTION INPUT ;
    USE SIGNAL ;
    PORT
      LAYER M4 ;
        RECT  94.848 9.504 95.04 9.528 ;
    END
  END i_d[31]
  PIN i_d[320]
    DIRECTION INPUT ;
    USE SIGNAL ;
    PORT
      LAYER M4 ;
        RECT  94.848 58.32 95.04 58.344 ;
    END
  END i_d[320]
  PIN i_d[321]
    DIRECTION INPUT ;
    USE SIGNAL ;
    PORT
      LAYER M4 ;
        RECT  94.848 58.464 95.04 58.488 ;
    END
  END i_d[321]
  PIN i_d[322]
    DIRECTION INPUT ;
    USE SIGNAL ;
    PORT
      LAYER M4 ;
        RECT  94.848 58.608 95.04 58.632 ;
    END
  END i_d[322]
  PIN i_d[323]
    DIRECTION INPUT ;
    USE SIGNAL ;
    PORT
      LAYER M4 ;
        RECT  94.848 58.896 95.04 58.92 ;
    END
  END i_d[323]
  PIN i_d[324]
    DIRECTION INPUT ;
    USE SIGNAL ;
    PORT
      LAYER M4 ;
        RECT  94.848 59.04 95.04 59.064 ;
    END
  END i_d[324]
  PIN i_d[325]
    DIRECTION INPUT ;
    USE SIGNAL ;
    PORT
      LAYER M4 ;
        RECT  94.848 59.184 95.04 59.208 ;
    END
  END i_d[325]
  PIN i_d[326]
    DIRECTION INPUT ;
    USE SIGNAL ;
    PORT
      LAYER M4 ;
        RECT  94.848 59.328 95.04 59.352 ;
    END
  END i_d[326]
  PIN i_d[327]
    DIRECTION INPUT ;
    USE SIGNAL ;
    PORT
      LAYER M4 ;
        RECT  94.848 59.472 95.04 59.496 ;
    END
  END i_d[327]
  PIN i_d[328]
    DIRECTION INPUT ;
    USE SIGNAL ;
    PORT
      LAYER M4 ;
        RECT  94.848 59.616 95.04 59.64 ;
    END
  END i_d[328]
  PIN i_d[329]
    DIRECTION INPUT ;
    USE SIGNAL ;
    PORT
      LAYER M4 ;
        RECT  94.848 59.904 95.04 59.928 ;
    END
  END i_d[329]
  PIN i_d[32]
    DIRECTION INPUT ;
    USE SIGNAL ;
    PORT
      LAYER M4 ;
        RECT  94.848 9.792 95.04 9.816 ;
    END
  END i_d[32]
  PIN i_d[330]
    DIRECTION INPUT ;
    USE SIGNAL ;
    PORT
      LAYER M4 ;
        RECT  94.848 60.048 95.04 60.072 ;
    END
  END i_d[330]
  PIN i_d[331]
    DIRECTION INPUT ;
    USE SIGNAL ;
    PORT
      LAYER M4 ;
        RECT  94.848 60.192 95.04 60.216 ;
    END
  END i_d[331]
  PIN i_d[332]
    DIRECTION INPUT ;
    USE SIGNAL ;
    PORT
      LAYER M4 ;
        RECT  94.848 60.336 95.04 60.36 ;
    END
  END i_d[332]
  PIN i_d[333]
    DIRECTION INPUT ;
    USE SIGNAL ;
    PORT
      LAYER M4 ;
        RECT  94.848 60.48 95.04 60.504 ;
    END
  END i_d[333]
  PIN i_d[334]
    DIRECTION INPUT ;
    USE SIGNAL ;
    PORT
      LAYER M4 ;
        RECT  94.848 60.624 95.04 60.648 ;
    END
  END i_d[334]
  PIN i_d[335]
    DIRECTION INPUT ;
    USE SIGNAL ;
    PORT
      LAYER M4 ;
        RECT  94.848 60.912 95.04 60.936 ;
    END
  END i_d[335]
  PIN i_d[336]
    DIRECTION INPUT ;
    USE SIGNAL ;
    PORT
      LAYER M4 ;
        RECT  94.848 61.056 95.04 61.08 ;
    END
  END i_d[336]
  PIN i_d[337]
    DIRECTION INPUT ;
    USE SIGNAL ;
    PORT
      LAYER M4 ;
        RECT  94.848 61.2 95.04 61.224 ;
    END
  END i_d[337]
  PIN i_d[338]
    DIRECTION INPUT ;
    USE SIGNAL ;
    PORT
      LAYER M4 ;
        RECT  94.848 61.344 95.04 61.368 ;
    END
  END i_d[338]
  PIN i_d[339]
    DIRECTION INPUT ;
    USE SIGNAL ;
    PORT
      LAYER M4 ;
        RECT  94.848 61.488 95.04 61.512 ;
    END
  END i_d[339]
  PIN i_d[33]
    DIRECTION INPUT ;
    USE SIGNAL ;
    PORT
      LAYER M4 ;
        RECT  94.848 9.936 95.04 9.96 ;
    END
  END i_d[33]
  PIN i_d[340]
    DIRECTION INPUT ;
    USE SIGNAL ;
    PORT
      LAYER M4 ;
        RECT  94.848 61.776 95.04 61.8 ;
    END
  END i_d[340]
  PIN i_d[341]
    DIRECTION INPUT ;
    USE SIGNAL ;
    PORT
      LAYER M4 ;
        RECT  94.848 61.92 95.04 61.944 ;
    END
  END i_d[341]
  PIN i_d[342]
    DIRECTION INPUT ;
    USE SIGNAL ;
    PORT
      LAYER M4 ;
        RECT  94.848 62.064 95.04 62.088 ;
    END
  END i_d[342]
  PIN i_d[343]
    DIRECTION INPUT ;
    USE SIGNAL ;
    PORT
      LAYER M4 ;
        RECT  94.848 62.208 95.04 62.232 ;
    END
  END i_d[343]
  PIN i_d[344]
    DIRECTION INPUT ;
    USE SIGNAL ;
    PORT
      LAYER M4 ;
        RECT  94.848 62.352 95.04 62.376 ;
    END
  END i_d[344]
  PIN i_d[345]
    DIRECTION INPUT ;
    USE SIGNAL ;
    PORT
      LAYER M4 ;
        RECT  94.848 62.496 95.04 62.52 ;
    END
  END i_d[345]
  PIN i_d[346]
    DIRECTION INPUT ;
    USE SIGNAL ;
    PORT
      LAYER M4 ;
        RECT  94.848 62.784 95.04 62.808 ;
    END
  END i_d[346]
  PIN i_d[347]
    DIRECTION INPUT ;
    USE SIGNAL ;
    PORT
      LAYER M4 ;
        RECT  94.848 62.928 95.04 62.952 ;
    END
  END i_d[347]
  PIN i_d[348]
    DIRECTION INPUT ;
    USE SIGNAL ;
    PORT
      LAYER M4 ;
        RECT  94.848 63.072 95.04 63.096 ;
    END
  END i_d[348]
  PIN i_d[349]
    DIRECTION INPUT ;
    USE SIGNAL ;
    PORT
      LAYER M4 ;
        RECT  94.848 63.216 95.04 63.24 ;
    END
  END i_d[349]
  PIN i_d[34]
    DIRECTION INPUT ;
    USE SIGNAL ;
    PORT
      LAYER M4 ;
        RECT  94.848 10.08 95.04 10.104 ;
    END
  END i_d[34]
  PIN i_d[350]
    DIRECTION INPUT ;
    USE SIGNAL ;
    PORT
      LAYER M4 ;
        RECT  94.848 63.36 95.04 63.384 ;
    END
  END i_d[350]
  PIN i_d[351]
    DIRECTION INPUT ;
    USE SIGNAL ;
    PORT
      LAYER M4 ;
        RECT  94.848 63.504 95.04 63.528 ;
    END
  END i_d[351]
  PIN i_d[352]
    DIRECTION INPUT ;
    USE SIGNAL ;
    PORT
      LAYER M4 ;
        RECT  94.848 63.792 95.04 63.816 ;
    END
  END i_d[352]
  PIN i_d[353]
    DIRECTION INPUT ;
    USE SIGNAL ;
    PORT
      LAYER M4 ;
        RECT  94.848 63.936 95.04 63.96 ;
    END
  END i_d[353]
  PIN i_d[354]
    DIRECTION INPUT ;
    USE SIGNAL ;
    PORT
      LAYER M4 ;
        RECT  94.848 64.08 95.04 64.104 ;
    END
  END i_d[354]
  PIN i_d[355]
    DIRECTION INPUT ;
    USE SIGNAL ;
    PORT
      LAYER M4 ;
        RECT  94.848 64.224 95.04 64.248 ;
    END
  END i_d[355]
  PIN i_d[356]
    DIRECTION INPUT ;
    USE SIGNAL ;
    PORT
      LAYER M4 ;
        RECT  94.848 64.368 95.04 64.392 ;
    END
  END i_d[356]
  PIN i_d[357]
    DIRECTION INPUT ;
    USE SIGNAL ;
    PORT
      LAYER M4 ;
        RECT  94.848 64.512 95.04 64.536 ;
    END
  END i_d[357]
  PIN i_d[358]
    DIRECTION INPUT ;
    USE SIGNAL ;
    PORT
      LAYER M4 ;
        RECT  94.848 64.8 95.04 64.824 ;
    END
  END i_d[358]
  PIN i_d[359]
    DIRECTION INPUT ;
    USE SIGNAL ;
    PORT
      LAYER M4 ;
        RECT  94.848 64.944 95.04 64.968 ;
    END
  END i_d[359]
  PIN i_d[35]
    DIRECTION INPUT ;
    USE SIGNAL ;
    PORT
      LAYER M4 ;
        RECT  94.848 10.224 95.04 10.248 ;
    END
  END i_d[35]
  PIN i_d[360]
    DIRECTION INPUT ;
    USE SIGNAL ;
    PORT
      LAYER M4 ;
        RECT  94.848 65.088 95.04 65.112 ;
    END
  END i_d[360]
  PIN i_d[361]
    DIRECTION INPUT ;
    USE SIGNAL ;
    PORT
      LAYER M4 ;
        RECT  94.848 65.232 95.04 65.256 ;
    END
  END i_d[361]
  PIN i_d[362]
    DIRECTION INPUT ;
    USE SIGNAL ;
    PORT
      LAYER M4 ;
        RECT  94.848 65.376 95.04 65.4 ;
    END
  END i_d[362]
  PIN i_d[363]
    DIRECTION INPUT ;
    USE SIGNAL ;
    PORT
      LAYER M4 ;
        RECT  94.848 65.52 95.04 65.544 ;
    END
  END i_d[363]
  PIN i_d[364]
    DIRECTION INPUT ;
    USE SIGNAL ;
    PORT
      LAYER M4 ;
        RECT  94.848 65.808 95.04 65.832 ;
    END
  END i_d[364]
  PIN i_d[365]
    DIRECTION INPUT ;
    USE SIGNAL ;
    PORT
      LAYER M4 ;
        RECT  94.848 65.952 95.04 65.976 ;
    END
  END i_d[365]
  PIN i_d[366]
    DIRECTION INPUT ;
    USE SIGNAL ;
    PORT
      LAYER M4 ;
        RECT  94.848 66.096 95.04 66.12 ;
    END
  END i_d[366]
  PIN i_d[367]
    DIRECTION INPUT ;
    USE SIGNAL ;
    PORT
      LAYER M4 ;
        RECT  94.848 66.24 95.04 66.264 ;
    END
  END i_d[367]
  PIN i_d[368]
    DIRECTION INPUT ;
    USE SIGNAL ;
    PORT
      LAYER M4 ;
        RECT  94.848 66.384 95.04 66.408 ;
    END
  END i_d[368]
  PIN i_d[369]
    DIRECTION INPUT ;
    USE SIGNAL ;
    PORT
      LAYER M4 ;
        RECT  94.848 66.672 95.04 66.696 ;
    END
  END i_d[369]
  PIN i_d[36]
    DIRECTION INPUT ;
    USE SIGNAL ;
    PORT
      LAYER M4 ;
        RECT  94.848 10.368 95.04 10.392 ;
    END
  END i_d[36]
  PIN i_d[370]
    DIRECTION INPUT ;
    USE SIGNAL ;
    PORT
      LAYER M4 ;
        RECT  94.848 66.816 95.04 66.84 ;
    END
  END i_d[370]
  PIN i_d[371]
    DIRECTION INPUT ;
    USE SIGNAL ;
    PORT
      LAYER M4 ;
        RECT  94.848 66.96 95.04 66.984 ;
    END
  END i_d[371]
  PIN i_d[372]
    DIRECTION INPUT ;
    USE SIGNAL ;
    PORT
      LAYER M4 ;
        RECT  94.848 67.104 95.04 67.128 ;
    END
  END i_d[372]
  PIN i_d[373]
    DIRECTION INPUT ;
    USE SIGNAL ;
    PORT
      LAYER M4 ;
        RECT  94.848 67.248 95.04 67.272 ;
    END
  END i_d[373]
  PIN i_d[374]
    DIRECTION INPUT ;
    USE SIGNAL ;
    PORT
      LAYER M4 ;
        RECT  94.848 67.392 95.04 67.416 ;
    END
  END i_d[374]
  PIN i_d[375]
    DIRECTION INPUT ;
    USE SIGNAL ;
    PORT
      LAYER M4 ;
        RECT  94.848 67.68 95.04 67.704 ;
    END
  END i_d[375]
  PIN i_d[376]
    DIRECTION INPUT ;
    USE SIGNAL ;
    PORT
      LAYER M4 ;
        RECT  94.848 67.824 95.04 67.848 ;
    END
  END i_d[376]
  PIN i_d[377]
    DIRECTION INPUT ;
    USE SIGNAL ;
    PORT
      LAYER M4 ;
        RECT  94.848 67.968 95.04 67.992 ;
    END
  END i_d[377]
  PIN i_d[378]
    DIRECTION INPUT ;
    USE SIGNAL ;
    PORT
      LAYER M4 ;
        RECT  94.848 68.112 95.04 68.136 ;
    END
  END i_d[378]
  PIN i_d[379]
    DIRECTION INPUT ;
    USE SIGNAL ;
    PORT
      LAYER M4 ;
        RECT  94.848 68.256 95.04 68.28 ;
    END
  END i_d[379]
  PIN i_d[37]
    DIRECTION INPUT ;
    USE SIGNAL ;
    PORT
      LAYER M4 ;
        RECT  94.848 10.512 95.04 10.536 ;
    END
  END i_d[37]
  PIN i_d[380]
    DIRECTION INPUT ;
    USE SIGNAL ;
    PORT
      LAYER M4 ;
        RECT  94.848 68.4 95.04 68.424 ;
    END
  END i_d[380]
  PIN i_d[381]
    DIRECTION INPUT ;
    USE SIGNAL ;
    PORT
      LAYER M4 ;
        RECT  94.848 68.688 95.04 68.712 ;
    END
  END i_d[381]
  PIN i_d[382]
    DIRECTION INPUT ;
    USE SIGNAL ;
    PORT
      LAYER M4 ;
        RECT  94.848 68.832 95.04 68.856 ;
    END
  END i_d[382]
  PIN i_d[383]
    DIRECTION INPUT ;
    USE SIGNAL ;
    PORT
      LAYER M4 ;
        RECT  94.848 68.976 95.04 69 ;
    END
  END i_d[383]
  PIN i_d[384]
    DIRECTION INPUT ;
    USE SIGNAL ;
    PORT
      LAYER M4 ;
        RECT  94.848 69.12 95.04 69.144 ;
    END
  END i_d[384]
  PIN i_d[385]
    DIRECTION INPUT ;
    USE SIGNAL ;
    PORT
      LAYER M4 ;
        RECT  94.848 69.264 95.04 69.288 ;
    END
  END i_d[385]
  PIN i_d[386]
    DIRECTION INPUT ;
    USE SIGNAL ;
    PORT
      LAYER M4 ;
        RECT  94.848 69.408 95.04 69.432 ;
    END
  END i_d[386]
  PIN i_d[387]
    DIRECTION INPUT ;
    USE SIGNAL ;
    PORT
      LAYER M4 ;
        RECT  94.848 69.696 95.04 69.72 ;
    END
  END i_d[387]
  PIN i_d[388]
    DIRECTION INPUT ;
    USE SIGNAL ;
    PORT
      LAYER M4 ;
        RECT  94.848 69.84 95.04 69.864 ;
    END
  END i_d[388]
  PIN i_d[389]
    DIRECTION INPUT ;
    USE SIGNAL ;
    PORT
      LAYER M4 ;
        RECT  94.848 69.984 95.04 70.008 ;
    END
  END i_d[389]
  PIN i_d[38]
    DIRECTION INPUT ;
    USE SIGNAL ;
    PORT
      LAYER M4 ;
        RECT  94.848 10.8 95.04 10.824 ;
    END
  END i_d[38]
  PIN i_d[390]
    DIRECTION INPUT ;
    USE SIGNAL ;
    PORT
      LAYER M4 ;
        RECT  94.848 70.128 95.04 70.152 ;
    END
  END i_d[390]
  PIN i_d[391]
    DIRECTION INPUT ;
    USE SIGNAL ;
    PORT
      LAYER M4 ;
        RECT  94.848 70.272 95.04 70.296 ;
    END
  END i_d[391]
  PIN i_d[392]
    DIRECTION INPUT ;
    USE SIGNAL ;
    PORT
      LAYER M4 ;
        RECT  94.848 70.416 95.04 70.44 ;
    END
  END i_d[392]
  PIN i_d[393]
    DIRECTION INPUT ;
    USE SIGNAL ;
    PORT
      LAYER M4 ;
        RECT  94.848 70.704 95.04 70.728 ;
    END
  END i_d[393]
  PIN i_d[394]
    DIRECTION INPUT ;
    USE SIGNAL ;
    PORT
      LAYER M4 ;
        RECT  94.848 70.848 95.04 70.872 ;
    END
  END i_d[394]
  PIN i_d[395]
    DIRECTION INPUT ;
    USE SIGNAL ;
    PORT
      LAYER M4 ;
        RECT  94.848 70.992 95.04 71.016 ;
    END
  END i_d[395]
  PIN i_d[396]
    DIRECTION INPUT ;
    USE SIGNAL ;
    PORT
      LAYER M4 ;
        RECT  94.848 71.136 95.04 71.16 ;
    END
  END i_d[396]
  PIN i_d[397]
    DIRECTION INPUT ;
    USE SIGNAL ;
    PORT
      LAYER M4 ;
        RECT  94.848 71.28 95.04 71.304 ;
    END
  END i_d[397]
  PIN i_d[398]
    DIRECTION INPUT ;
    USE SIGNAL ;
    PORT
      LAYER M4 ;
        RECT  94.848 71.424 95.04 71.448 ;
    END
  END i_d[398]
  PIN i_d[399]
    DIRECTION INPUT ;
    USE SIGNAL ;
    PORT
      LAYER M4 ;
        RECT  94.848 71.712 95.04 71.736 ;
    END
  END i_d[399]
  PIN i_d[39]
    DIRECTION INPUT ;
    USE SIGNAL ;
    PORT
      LAYER M4 ;
        RECT  94.848 10.944 95.04 10.968 ;
    END
  END i_d[39]
  PIN i_d[3]
    DIRECTION INPUT ;
    USE SIGNAL ;
    PORT
      LAYER M4 ;
        RECT  94.848 4.896 95.04 4.92 ;
    END
  END i_d[3]
  PIN i_d[400]
    DIRECTION INPUT ;
    USE SIGNAL ;
    PORT
      LAYER M4 ;
        RECT  94.848 71.856 95.04 71.88 ;
    END
  END i_d[400]
  PIN i_d[401]
    DIRECTION INPUT ;
    USE SIGNAL ;
    PORT
      LAYER M4 ;
        RECT  94.848 72 95.04 72.024 ;
    END
  END i_d[401]
  PIN i_d[402]
    DIRECTION INPUT ;
    USE SIGNAL ;
    PORT
      LAYER M4 ;
        RECT  94.848 72.144 95.04 72.168 ;
    END
  END i_d[402]
  PIN i_d[403]
    DIRECTION INPUT ;
    USE SIGNAL ;
    PORT
      LAYER M4 ;
        RECT  94.848 72.288 95.04 72.312 ;
    END
  END i_d[403]
  PIN i_d[404]
    DIRECTION INPUT ;
    USE SIGNAL ;
    PORT
      LAYER M4 ;
        RECT  94.848 72.576 95.04 72.6 ;
    END
  END i_d[404]
  PIN i_d[405]
    DIRECTION INPUT ;
    USE SIGNAL ;
    PORT
      LAYER M4 ;
        RECT  94.848 72.72 95.04 72.744 ;
    END
  END i_d[405]
  PIN i_d[406]
    DIRECTION INPUT ;
    USE SIGNAL ;
    PORT
      LAYER M4 ;
        RECT  94.848 72.864 95.04 72.888 ;
    END
  END i_d[406]
  PIN i_d[407]
    DIRECTION INPUT ;
    USE SIGNAL ;
    PORT
      LAYER M4 ;
        RECT  94.848 73.008 95.04 73.032 ;
    END
  END i_d[407]
  PIN i_d[408]
    DIRECTION INPUT ;
    USE SIGNAL ;
    PORT
      LAYER M4 ;
        RECT  94.848 73.152 95.04 73.176 ;
    END
  END i_d[408]
  PIN i_d[409]
    DIRECTION INPUT ;
    USE SIGNAL ;
    PORT
      LAYER M4 ;
        RECT  94.848 73.296 95.04 73.32 ;
    END
  END i_d[409]
  PIN i_d[40]
    DIRECTION INPUT ;
    USE SIGNAL ;
    PORT
      LAYER M4 ;
        RECT  94.848 11.088 95.04 11.112 ;
    END
  END i_d[40]
  PIN i_d[410]
    DIRECTION INPUT ;
    USE SIGNAL ;
    PORT
      LAYER M4 ;
        RECT  94.848 73.584 95.04 73.608 ;
    END
  END i_d[410]
  PIN i_d[411]
    DIRECTION INPUT ;
    USE SIGNAL ;
    PORT
      LAYER M4 ;
        RECT  94.848 73.728 95.04 73.752 ;
    END
  END i_d[411]
  PIN i_d[412]
    DIRECTION INPUT ;
    USE SIGNAL ;
    PORT
      LAYER M4 ;
        RECT  94.848 73.872 95.04 73.896 ;
    END
  END i_d[412]
  PIN i_d[413]
    DIRECTION INPUT ;
    USE SIGNAL ;
    PORT
      LAYER M4 ;
        RECT  94.848 74.016 95.04 74.04 ;
    END
  END i_d[413]
  PIN i_d[414]
    DIRECTION INPUT ;
    USE SIGNAL ;
    PORT
      LAYER M4 ;
        RECT  94.848 74.16 95.04 74.184 ;
    END
  END i_d[414]
  PIN i_d[415]
    DIRECTION INPUT ;
    USE SIGNAL ;
    PORT
      LAYER M4 ;
        RECT  94.848 74.304 95.04 74.328 ;
    END
  END i_d[415]
  PIN i_d[416]
    DIRECTION INPUT ;
    USE SIGNAL ;
    PORT
      LAYER M4 ;
        RECT  94.848 74.592 95.04 74.616 ;
    END
  END i_d[416]
  PIN i_d[417]
    DIRECTION INPUT ;
    USE SIGNAL ;
    PORT
      LAYER M4 ;
        RECT  94.848 74.736 95.04 74.76 ;
    END
  END i_d[417]
  PIN i_d[418]
    DIRECTION INPUT ;
    USE SIGNAL ;
    PORT
      LAYER M4 ;
        RECT  94.848 74.88 95.04 74.904 ;
    END
  END i_d[418]
  PIN i_d[419]
    DIRECTION INPUT ;
    USE SIGNAL ;
    PORT
      LAYER M4 ;
        RECT  94.848 75.024 95.04 75.048 ;
    END
  END i_d[419]
  PIN i_d[41]
    DIRECTION INPUT ;
    USE SIGNAL ;
    PORT
      LAYER M4 ;
        RECT  94.848 11.232 95.04 11.256 ;
    END
  END i_d[41]
  PIN i_d[420]
    DIRECTION INPUT ;
    USE SIGNAL ;
    PORT
      LAYER M4 ;
        RECT  94.848 75.168 95.04 75.192 ;
    END
  END i_d[420]
  PIN i_d[421]
    DIRECTION INPUT ;
    USE SIGNAL ;
    PORT
      LAYER M4 ;
        RECT  94.848 75.312 95.04 75.336 ;
    END
  END i_d[421]
  PIN i_d[422]
    DIRECTION INPUT ;
    USE SIGNAL ;
    PORT
      LAYER M4 ;
        RECT  94.848 75.6 95.04 75.624 ;
    END
  END i_d[422]
  PIN i_d[423]
    DIRECTION INPUT ;
    USE SIGNAL ;
    PORT
      LAYER M4 ;
        RECT  94.848 75.744 95.04 75.768 ;
    END
  END i_d[423]
  PIN i_d[424]
    DIRECTION INPUT ;
    USE SIGNAL ;
    PORT
      LAYER M4 ;
        RECT  94.848 75.888 95.04 75.912 ;
    END
  END i_d[424]
  PIN i_d[425]
    DIRECTION INPUT ;
    USE SIGNAL ;
    PORT
      LAYER M4 ;
        RECT  94.848 76.032 95.04 76.056 ;
    END
  END i_d[425]
  PIN i_d[426]
    DIRECTION INPUT ;
    USE SIGNAL ;
    PORT
      LAYER M4 ;
        RECT  94.848 76.176 95.04 76.2 ;
    END
  END i_d[426]
  PIN i_d[427]
    DIRECTION INPUT ;
    USE SIGNAL ;
    PORT
      LAYER M4 ;
        RECT  94.848 76.32 95.04 76.344 ;
    END
  END i_d[427]
  PIN i_d[428]
    DIRECTION INPUT ;
    USE SIGNAL ;
    PORT
      LAYER M4 ;
        RECT  94.848 76.608 95.04 76.632 ;
    END
  END i_d[428]
  PIN i_d[429]
    DIRECTION INPUT ;
    USE SIGNAL ;
    PORT
      LAYER M4 ;
        RECT  94.848 76.752 95.04 76.776 ;
    END
  END i_d[429]
  PIN i_d[42]
    DIRECTION INPUT ;
    USE SIGNAL ;
    PORT
      LAYER M4 ;
        RECT  94.848 11.376 95.04 11.4 ;
    END
  END i_d[42]
  PIN i_d[430]
    DIRECTION INPUT ;
    USE SIGNAL ;
    PORT
      LAYER M4 ;
        RECT  94.848 76.896 95.04 76.92 ;
    END
  END i_d[430]
  PIN i_d[431]
    DIRECTION INPUT ;
    USE SIGNAL ;
    PORT
      LAYER M4 ;
        RECT  94.848 77.04 95.04 77.064 ;
    END
  END i_d[431]
  PIN i_d[432]
    DIRECTION INPUT ;
    USE SIGNAL ;
    PORT
      LAYER M4 ;
        RECT  94.848 77.184 95.04 77.208 ;
    END
  END i_d[432]
  PIN i_d[433]
    DIRECTION INPUT ;
    USE SIGNAL ;
    PORT
      LAYER M4 ;
        RECT  94.848 77.472 95.04 77.496 ;
    END
  END i_d[433]
  PIN i_d[434]
    DIRECTION INPUT ;
    USE SIGNAL ;
    PORT
      LAYER M4 ;
        RECT  94.848 77.616 95.04 77.64 ;
    END
  END i_d[434]
  PIN i_d[435]
    DIRECTION INPUT ;
    USE SIGNAL ;
    PORT
      LAYER M4 ;
        RECT  94.848 77.76 95.04 77.784 ;
    END
  END i_d[435]
  PIN i_d[436]
    DIRECTION INPUT ;
    USE SIGNAL ;
    PORT
      LAYER M4 ;
        RECT  94.848 77.904 95.04 77.928 ;
    END
  END i_d[436]
  PIN i_d[437]
    DIRECTION INPUT ;
    USE SIGNAL ;
    PORT
      LAYER M4 ;
        RECT  94.848 78.048 95.04 78.072 ;
    END
  END i_d[437]
  PIN i_d[438]
    DIRECTION INPUT ;
    USE SIGNAL ;
    PORT
      LAYER M4 ;
        RECT  94.848 78.192 95.04 78.216 ;
    END
  END i_d[438]
  PIN i_d[439]
    DIRECTION INPUT ;
    USE SIGNAL ;
    PORT
      LAYER M4 ;
        RECT  94.848 78.48 95.04 78.504 ;
    END
  END i_d[439]
  PIN i_d[43]
    DIRECTION INPUT ;
    USE SIGNAL ;
    PORT
      LAYER M4 ;
        RECT  94.848 11.52 95.04 11.544 ;
    END
  END i_d[43]
  PIN i_d[440]
    DIRECTION INPUT ;
    USE SIGNAL ;
    PORT
      LAYER M4 ;
        RECT  94.848 78.624 95.04 78.648 ;
    END
  END i_d[440]
  PIN i_d[441]
    DIRECTION INPUT ;
    USE SIGNAL ;
    PORT
      LAYER M4 ;
        RECT  94.848 78.768 95.04 78.792 ;
    END
  END i_d[441]
  PIN i_d[442]
    DIRECTION INPUT ;
    USE SIGNAL ;
    PORT
      LAYER M4 ;
        RECT  94.848 78.912 95.04 78.936 ;
    END
  END i_d[442]
  PIN i_d[443]
    DIRECTION INPUT ;
    USE SIGNAL ;
    PORT
      LAYER M4 ;
        RECT  94.848 79.056 95.04 79.08 ;
    END
  END i_d[443]
  PIN i_d[444]
    DIRECTION INPUT ;
    USE SIGNAL ;
    PORT
      LAYER M4 ;
        RECT  94.848 79.2 95.04 79.224 ;
    END
  END i_d[444]
  PIN i_d[445]
    DIRECTION INPUT ;
    USE SIGNAL ;
    PORT
      LAYER M4 ;
        RECT  94.848 79.488 95.04 79.512 ;
    END
  END i_d[445]
  PIN i_d[446]
    DIRECTION INPUT ;
    USE SIGNAL ;
    PORT
      LAYER M4 ;
        RECT  94.848 79.632 95.04 79.656 ;
    END
  END i_d[446]
  PIN i_d[447]
    DIRECTION INPUT ;
    USE SIGNAL ;
    PORT
      LAYER M4 ;
        RECT  94.848 79.776 95.04 79.8 ;
    END
  END i_d[447]
  PIN i_d[448]
    DIRECTION INPUT ;
    USE SIGNAL ;
    PORT
      LAYER M4 ;
        RECT  94.848 79.92 95.04 79.944 ;
    END
  END i_d[448]
  PIN i_d[449]
    DIRECTION INPUT ;
    USE SIGNAL ;
    PORT
      LAYER M4 ;
        RECT  94.848 80.064 95.04 80.088 ;
    END
  END i_d[449]
  PIN i_d[44]
    DIRECTION INPUT ;
    USE SIGNAL ;
    PORT
      LAYER M4 ;
        RECT  94.848 11.808 95.04 11.832 ;
    END
  END i_d[44]
  PIN i_d[450]
    DIRECTION INPUT ;
    USE SIGNAL ;
    PORT
      LAYER M4 ;
        RECT  94.848 80.208 95.04 80.232 ;
    END
  END i_d[450]
  PIN i_d[451]
    DIRECTION INPUT ;
    USE SIGNAL ;
    PORT
      LAYER M4 ;
        RECT  94.848 80.496 95.04 80.52 ;
    END
  END i_d[451]
  PIN i_d[452]
    DIRECTION INPUT ;
    USE SIGNAL ;
    PORT
      LAYER M4 ;
        RECT  94.848 80.64 95.04 80.664 ;
    END
  END i_d[452]
  PIN i_d[453]
    DIRECTION INPUT ;
    USE SIGNAL ;
    PORT
      LAYER M4 ;
        RECT  94.848 80.784 95.04 80.808 ;
    END
  END i_d[453]
  PIN i_d[454]
    DIRECTION INPUT ;
    USE SIGNAL ;
    PORT
      LAYER M4 ;
        RECT  94.848 80.928 95.04 80.952 ;
    END
  END i_d[454]
  PIN i_d[455]
    DIRECTION INPUT ;
    USE SIGNAL ;
    PORT
      LAYER M4 ;
        RECT  94.848 81.072 95.04 81.096 ;
    END
  END i_d[455]
  PIN i_d[456]
    DIRECTION INPUT ;
    USE SIGNAL ;
    PORT
      LAYER M4 ;
        RECT  94.848 81.216 95.04 81.24 ;
    END
  END i_d[456]
  PIN i_d[457]
    DIRECTION INPUT ;
    USE SIGNAL ;
    PORT
      LAYER M4 ;
        RECT  94.848 81.504 95.04 81.528 ;
    END
  END i_d[457]
  PIN i_d[458]
    DIRECTION INPUT ;
    USE SIGNAL ;
    PORT
      LAYER M4 ;
        RECT  94.848 81.648 95.04 81.672 ;
    END
  END i_d[458]
  PIN i_d[459]
    DIRECTION INPUT ;
    USE SIGNAL ;
    PORT
      LAYER M4 ;
        RECT  94.848 81.792 95.04 81.816 ;
    END
  END i_d[459]
  PIN i_d[45]
    DIRECTION INPUT ;
    USE SIGNAL ;
    PORT
      LAYER M4 ;
        RECT  94.848 11.952 95.04 11.976 ;
    END
  END i_d[45]
  PIN i_d[460]
    DIRECTION INPUT ;
    USE SIGNAL ;
    PORT
      LAYER M4 ;
        RECT  94.848 81.936 95.04 81.96 ;
    END
  END i_d[460]
  PIN i_d[461]
    DIRECTION INPUT ;
    USE SIGNAL ;
    PORT
      LAYER M4 ;
        RECT  94.848 82.08 95.04 82.104 ;
    END
  END i_d[461]
  PIN i_d[462]
    DIRECTION INPUT ;
    USE SIGNAL ;
    PORT
      LAYER M4 ;
        RECT  94.848 82.224 95.04 82.248 ;
    END
  END i_d[462]
  PIN i_d[463]
    DIRECTION INPUT ;
    USE SIGNAL ;
    PORT
      LAYER M4 ;
        RECT  94.848 82.512 95.04 82.536 ;
    END
  END i_d[463]
  PIN i_d[464]
    DIRECTION INPUT ;
    USE SIGNAL ;
    PORT
      LAYER M4 ;
        RECT  94.848 82.656 95.04 82.68 ;
    END
  END i_d[464]
  PIN i_d[465]
    DIRECTION INPUT ;
    USE SIGNAL ;
    PORT
      LAYER M4 ;
        RECT  94.848 82.8 95.04 82.824 ;
    END
  END i_d[465]
  PIN i_d[466]
    DIRECTION INPUT ;
    USE SIGNAL ;
    PORT
      LAYER M4 ;
        RECT  94.848 82.944 95.04 82.968 ;
    END
  END i_d[466]
  PIN i_d[467]
    DIRECTION INPUT ;
    USE SIGNAL ;
    PORT
      LAYER M4 ;
        RECT  94.848 83.088 95.04 83.112 ;
    END
  END i_d[467]
  PIN i_d[468]
    DIRECTION INPUT ;
    USE SIGNAL ;
    PORT
      LAYER M4 ;
        RECT  94.848 83.376 95.04 83.4 ;
    END
  END i_d[468]
  PIN i_d[469]
    DIRECTION INPUT ;
    USE SIGNAL ;
    PORT
      LAYER M4 ;
        RECT  94.848 83.52 95.04 83.544 ;
    END
  END i_d[469]
  PIN i_d[46]
    DIRECTION INPUT ;
    USE SIGNAL ;
    PORT
      LAYER M4 ;
        RECT  94.848 12.096 95.04 12.12 ;
    END
  END i_d[46]
  PIN i_d[470]
    DIRECTION INPUT ;
    USE SIGNAL ;
    PORT
      LAYER M4 ;
        RECT  94.848 83.664 95.04 83.688 ;
    END
  END i_d[470]
  PIN i_d[471]
    DIRECTION INPUT ;
    USE SIGNAL ;
    PORT
      LAYER M4 ;
        RECT  94.848 83.808 95.04 83.832 ;
    END
  END i_d[471]
  PIN i_d[472]
    DIRECTION INPUT ;
    USE SIGNAL ;
    PORT
      LAYER M4 ;
        RECT  94.848 83.952 95.04 83.976 ;
    END
  END i_d[472]
  PIN i_d[473]
    DIRECTION INPUT ;
    USE SIGNAL ;
    PORT
      LAYER M4 ;
        RECT  94.848 84.096 95.04 84.12 ;
    END
  END i_d[473]
  PIN i_d[474]
    DIRECTION INPUT ;
    USE SIGNAL ;
    PORT
      LAYER M4 ;
        RECT  94.848 84.384 95.04 84.408 ;
    END
  END i_d[474]
  PIN i_d[475]
    DIRECTION INPUT ;
    USE SIGNAL ;
    PORT
      LAYER M4 ;
        RECT  94.848 84.528 95.04 84.552 ;
    END
  END i_d[475]
  PIN i_d[476]
    DIRECTION INPUT ;
    USE SIGNAL ;
    PORT
      LAYER M4 ;
        RECT  94.848 84.672 95.04 84.696 ;
    END
  END i_d[476]
  PIN i_d[477]
    DIRECTION INPUT ;
    USE SIGNAL ;
    PORT
      LAYER M4 ;
        RECT  94.848 84.816 95.04 84.84 ;
    END
  END i_d[477]
  PIN i_d[478]
    DIRECTION INPUT ;
    USE SIGNAL ;
    PORT
      LAYER M4 ;
        RECT  94.848 84.96 95.04 84.984 ;
    END
  END i_d[478]
  PIN i_d[479]
    DIRECTION INPUT ;
    USE SIGNAL ;
    PORT
      LAYER M4 ;
        RECT  94.848 85.104 95.04 85.128 ;
    END
  END i_d[479]
  PIN i_d[47]
    DIRECTION INPUT ;
    USE SIGNAL ;
    PORT
      LAYER M4 ;
        RECT  94.848 12.24 95.04 12.264 ;
    END
  END i_d[47]
  PIN i_d[480]
    DIRECTION INPUT ;
    USE SIGNAL ;
    PORT
      LAYER M4 ;
        RECT  94.848 85.392 95.04 85.416 ;
    END
  END i_d[480]
  PIN i_d[481]
    DIRECTION INPUT ;
    USE SIGNAL ;
    PORT
      LAYER M4 ;
        RECT  94.848 85.536 95.04 85.56 ;
    END
  END i_d[481]
  PIN i_d[482]
    DIRECTION INPUT ;
    USE SIGNAL ;
    PORT
      LAYER M4 ;
        RECT  94.848 85.68 95.04 85.704 ;
    END
  END i_d[482]
  PIN i_d[483]
    DIRECTION INPUT ;
    USE SIGNAL ;
    PORT
      LAYER M4 ;
        RECT  94.848 85.824 95.04 85.848 ;
    END
  END i_d[483]
  PIN i_d[484]
    DIRECTION INPUT ;
    USE SIGNAL ;
    PORT
      LAYER M4 ;
        RECT  94.848 85.968 95.04 85.992 ;
    END
  END i_d[484]
  PIN i_d[485]
    DIRECTION INPUT ;
    USE SIGNAL ;
    PORT
      LAYER M4 ;
        RECT  94.848 86.112 95.04 86.136 ;
    END
  END i_d[485]
  PIN i_d[486]
    DIRECTION INPUT ;
    USE SIGNAL ;
    PORT
      LAYER M4 ;
        RECT  94.848 86.4 95.04 86.424 ;
    END
  END i_d[486]
  PIN i_d[487]
    DIRECTION INPUT ;
    USE SIGNAL ;
    PORT
      LAYER M4 ;
        RECT  94.848 86.544 95.04 86.568 ;
    END
  END i_d[487]
  PIN i_d[488]
    DIRECTION INPUT ;
    USE SIGNAL ;
    PORT
      LAYER M4 ;
        RECT  94.848 86.688 95.04 86.712 ;
    END
  END i_d[488]
  PIN i_d[489]
    DIRECTION INPUT ;
    USE SIGNAL ;
    PORT
      LAYER M4 ;
        RECT  94.848 86.832 95.04 86.856 ;
    END
  END i_d[489]
  PIN i_d[48]
    DIRECTION INPUT ;
    USE SIGNAL ;
    PORT
      LAYER M4 ;
        RECT  94.848 12.384 95.04 12.408 ;
    END
  END i_d[48]
  PIN i_d[490]
    DIRECTION INPUT ;
    USE SIGNAL ;
    PORT
      LAYER M4 ;
        RECT  94.848 86.976 95.04 87 ;
    END
  END i_d[490]
  PIN i_d[491]
    DIRECTION INPUT ;
    USE SIGNAL ;
    PORT
      LAYER M4 ;
        RECT  94.848 87.12 95.04 87.144 ;
    END
  END i_d[491]
  PIN i_d[492]
    DIRECTION INPUT ;
    USE SIGNAL ;
    PORT
      LAYER M4 ;
        RECT  94.848 87.408 95.04 87.432 ;
    END
  END i_d[492]
  PIN i_d[493]
    DIRECTION INPUT ;
    USE SIGNAL ;
    PORT
      LAYER M4 ;
        RECT  94.848 87.552 95.04 87.576 ;
    END
  END i_d[493]
  PIN i_d[494]
    DIRECTION INPUT ;
    USE SIGNAL ;
    PORT
      LAYER M4 ;
        RECT  94.848 87.696 95.04 87.72 ;
    END
  END i_d[494]
  PIN i_d[495]
    DIRECTION INPUT ;
    USE SIGNAL ;
    PORT
      LAYER M4 ;
        RECT  94.848 87.84 95.04 87.864 ;
    END
  END i_d[495]
  PIN i_d[496]
    DIRECTION INPUT ;
    USE SIGNAL ;
    PORT
      LAYER M4 ;
        RECT  94.848 87.984 95.04 88.008 ;
    END
  END i_d[496]
  PIN i_d[497]
    DIRECTION INPUT ;
    USE SIGNAL ;
    PORT
      LAYER M4 ;
        RECT  94.848 88.272 95.04 88.296 ;
    END
  END i_d[497]
  PIN i_d[498]
    DIRECTION INPUT ;
    USE SIGNAL ;
    PORT
      LAYER M4 ;
        RECT  94.848 88.416 95.04 88.44 ;
    END
  END i_d[498]
  PIN i_d[499]
    DIRECTION INPUT ;
    USE SIGNAL ;
    PORT
      LAYER M4 ;
        RECT  94.848 88.56 95.04 88.584 ;
    END
  END i_d[499]
  PIN i_d[49]
    DIRECTION INPUT ;
    USE SIGNAL ;
    PORT
      LAYER M4 ;
        RECT  94.848 12.672 95.04 12.696 ;
    END
  END i_d[49]
  PIN i_d[4]
    DIRECTION INPUT ;
    USE SIGNAL ;
    PORT
      LAYER M4 ;
        RECT  94.848 5.04 95.04 5.064 ;
    END
  END i_d[4]
  PIN i_d[500]
    DIRECTION INPUT ;
    USE SIGNAL ;
    PORT
      LAYER M4 ;
        RECT  94.848 88.704 95.04 88.728 ;
    END
  END i_d[500]
  PIN i_d[501]
    DIRECTION INPUT ;
    USE SIGNAL ;
    PORT
      LAYER M4 ;
        RECT  94.848 88.848 95.04 88.872 ;
    END
  END i_d[501]
  PIN i_d[502]
    DIRECTION INPUT ;
    USE SIGNAL ;
    PORT
      LAYER M4 ;
        RECT  94.848 88.992 95.04 89.016 ;
    END
  END i_d[502]
  PIN i_d[503]
    DIRECTION INPUT ;
    USE SIGNAL ;
    PORT
      LAYER M4 ;
        RECT  94.848 89.28 95.04 89.304 ;
    END
  END i_d[503]
  PIN i_d[504]
    DIRECTION INPUT ;
    USE SIGNAL ;
    PORT
      LAYER M4 ;
        RECT  94.848 89.424 95.04 89.448 ;
    END
  END i_d[504]
  PIN i_d[505]
    DIRECTION INPUT ;
    USE SIGNAL ;
    PORT
      LAYER M4 ;
        RECT  94.848 89.568 95.04 89.592 ;
    END
  END i_d[505]
  PIN i_d[506]
    DIRECTION INPUT ;
    USE SIGNAL ;
    PORT
      LAYER M4 ;
        RECT  94.848 89.712 95.04 89.736 ;
    END
  END i_d[506]
  PIN i_d[507]
    DIRECTION INPUT ;
    USE SIGNAL ;
    PORT
      LAYER M4 ;
        RECT  94.848 89.856 95.04 89.88 ;
    END
  END i_d[507]
  PIN i_d[508]
    DIRECTION INPUT ;
    USE SIGNAL ;
    PORT
      LAYER M4 ;
        RECT  94.848 90 95.04 90.024 ;
    END
  END i_d[508]
  PIN i_d[509]
    DIRECTION INPUT ;
    USE SIGNAL ;
    PORT
      LAYER M4 ;
        RECT  94.848 90.288 95.04 90.312 ;
    END
  END i_d[509]
  PIN i_d[50]
    DIRECTION INPUT ;
    USE SIGNAL ;
    PORT
      LAYER M4 ;
        RECT  94.848 12.816 95.04 12.84 ;
    END
  END i_d[50]
  PIN i_d[510]
    DIRECTION INPUT ;
    USE SIGNAL ;
    PORT
      LAYER M4 ;
        RECT  94.848 90.432 95.04 90.456 ;
    END
  END i_d[510]
  PIN i_d[511]
    DIRECTION INPUT ;
    USE SIGNAL ;
    PORT
      LAYER M4 ;
        RECT  94.848 90.576 95.04 90.6 ;
    END
  END i_d[511]
  PIN i_d[51]
    DIRECTION INPUT ;
    USE SIGNAL ;
    PORT
      LAYER M4 ;
        RECT  94.848 12.96 95.04 12.984 ;
    END
  END i_d[51]
  PIN i_d[52]
    DIRECTION INPUT ;
    USE SIGNAL ;
    PORT
      LAYER M4 ;
        RECT  94.848 13.104 95.04 13.128 ;
    END
  END i_d[52]
  PIN i_d[53]
    DIRECTION INPUT ;
    USE SIGNAL ;
    PORT
      LAYER M4 ;
        RECT  94.848 13.248 95.04 13.272 ;
    END
  END i_d[53]
  PIN i_d[54]
    DIRECTION INPUT ;
    USE SIGNAL ;
    PORT
      LAYER M4 ;
        RECT  94.848 13.392 95.04 13.416 ;
    END
  END i_d[54]
  PIN i_d[55]
    DIRECTION INPUT ;
    USE SIGNAL ;
    PORT
      LAYER M4 ;
        RECT  94.848 13.68 95.04 13.704 ;
    END
  END i_d[55]
  PIN i_d[56]
    DIRECTION INPUT ;
    USE SIGNAL ;
    PORT
      LAYER M4 ;
        RECT  94.848 13.824 95.04 13.848 ;
    END
  END i_d[56]
  PIN i_d[57]
    DIRECTION INPUT ;
    USE SIGNAL ;
    PORT
      LAYER M4 ;
        RECT  94.848 13.968 95.04 13.992 ;
    END
  END i_d[57]
  PIN i_d[58]
    DIRECTION INPUT ;
    USE SIGNAL ;
    PORT
      LAYER M4 ;
        RECT  94.848 14.112 95.04 14.136 ;
    END
  END i_d[58]
  PIN i_d[59]
    DIRECTION INPUT ;
    USE SIGNAL ;
    PORT
      LAYER M4 ;
        RECT  94.848 14.256 95.04 14.28 ;
    END
  END i_d[59]
  PIN i_d[5]
    DIRECTION INPUT ;
    USE SIGNAL ;
    PORT
      LAYER M4 ;
        RECT  94.848 5.184 95.04 5.208 ;
    END
  END i_d[5]
  PIN i_d[60]
    DIRECTION INPUT ;
    USE SIGNAL ;
    PORT
      LAYER M4 ;
        RECT  94.848 14.4 95.04 14.424 ;
    END
  END i_d[60]
  PIN i_d[61]
    DIRECTION INPUT ;
    USE SIGNAL ;
    PORT
      LAYER M4 ;
        RECT  94.848 14.688 95.04 14.712 ;
    END
  END i_d[61]
  PIN i_d[62]
    DIRECTION INPUT ;
    USE SIGNAL ;
    PORT
      LAYER M4 ;
        RECT  94.848 14.832 95.04 14.856 ;
    END
  END i_d[62]
  PIN i_d[63]
    DIRECTION INPUT ;
    USE SIGNAL ;
    PORT
      LAYER M4 ;
        RECT  94.848 14.976 95.04 15 ;
    END
  END i_d[63]
  PIN i_d[64]
    DIRECTION INPUT ;
    USE SIGNAL ;
    PORT
      LAYER M4 ;
        RECT  94.848 15.12 95.04 15.144 ;
    END
  END i_d[64]
  PIN i_d[65]
    DIRECTION INPUT ;
    USE SIGNAL ;
    PORT
      LAYER M4 ;
        RECT  94.848 15.264 95.04 15.288 ;
    END
  END i_d[65]
  PIN i_d[66]
    DIRECTION INPUT ;
    USE SIGNAL ;
    PORT
      LAYER M4 ;
        RECT  94.848 15.408 95.04 15.432 ;
    END
  END i_d[66]
  PIN i_d[67]
    DIRECTION INPUT ;
    USE SIGNAL ;
    PORT
      LAYER M4 ;
        RECT  94.848 15.696 95.04 15.72 ;
    END
  END i_d[67]
  PIN i_d[68]
    DIRECTION INPUT ;
    USE SIGNAL ;
    PORT
      LAYER M4 ;
        RECT  94.848 15.84 95.04 15.864 ;
    END
  END i_d[68]
  PIN i_d[69]
    DIRECTION INPUT ;
    USE SIGNAL ;
    PORT
      LAYER M4 ;
        RECT  94.848 15.984 95.04 16.008 ;
    END
  END i_d[69]
  PIN i_d[6]
    DIRECTION INPUT ;
    USE SIGNAL ;
    PORT
      LAYER M4 ;
        RECT  94.848 5.328 95.04 5.352 ;
    END
  END i_d[6]
  PIN i_d[70]
    DIRECTION INPUT ;
    USE SIGNAL ;
    PORT
      LAYER M4 ;
        RECT  94.848 16.128 95.04 16.152 ;
    END
  END i_d[70]
  PIN i_d[71]
    DIRECTION INPUT ;
    USE SIGNAL ;
    PORT
      LAYER M4 ;
        RECT  94.848 16.272 95.04 16.296 ;
    END
  END i_d[71]
  PIN i_d[72]
    DIRECTION INPUT ;
    USE SIGNAL ;
    PORT
      LAYER M4 ;
        RECT  94.848 16.416 95.04 16.44 ;
    END
  END i_d[72]
  PIN i_d[73]
    DIRECTION INPUT ;
    USE SIGNAL ;
    PORT
      LAYER M4 ;
        RECT  94.848 16.704 95.04 16.728 ;
    END
  END i_d[73]
  PIN i_d[74]
    DIRECTION INPUT ;
    USE SIGNAL ;
    PORT
      LAYER M4 ;
        RECT  94.848 16.848 95.04 16.872 ;
    END
  END i_d[74]
  PIN i_d[75]
    DIRECTION INPUT ;
    USE SIGNAL ;
    PORT
      LAYER M4 ;
        RECT  94.848 16.992 95.04 17.016 ;
    END
  END i_d[75]
  PIN i_d[76]
    DIRECTION INPUT ;
    USE SIGNAL ;
    PORT
      LAYER M4 ;
        RECT  94.848 17.136 95.04 17.16 ;
    END
  END i_d[76]
  PIN i_d[77]
    DIRECTION INPUT ;
    USE SIGNAL ;
    PORT
      LAYER M4 ;
        RECT  94.848 17.28 95.04 17.304 ;
    END
  END i_d[77]
  PIN i_d[78]
    DIRECTION INPUT ;
    USE SIGNAL ;
    PORT
      LAYER M4 ;
        RECT  94.848 17.424 95.04 17.448 ;
    END
  END i_d[78]
  PIN i_d[79]
    DIRECTION INPUT ;
    USE SIGNAL ;
    PORT
      LAYER M4 ;
        RECT  94.848 17.712 95.04 17.736 ;
    END
  END i_d[79]
  PIN i_d[7]
    DIRECTION INPUT ;
    USE SIGNAL ;
    PORT
      LAYER M4 ;
        RECT  94.848 5.472 95.04 5.496 ;
    END
  END i_d[7]
  PIN i_d[80]
    DIRECTION INPUT ;
    USE SIGNAL ;
    PORT
      LAYER M4 ;
        RECT  94.848 17.856 95.04 17.88 ;
    END
  END i_d[80]
  PIN i_d[81]
    DIRECTION INPUT ;
    USE SIGNAL ;
    PORT
      LAYER M4 ;
        RECT  94.848 18 95.04 18.024 ;
    END
  END i_d[81]
  PIN i_d[82]
    DIRECTION INPUT ;
    USE SIGNAL ;
    PORT
      LAYER M4 ;
        RECT  94.848 18.144 95.04 18.168 ;
    END
  END i_d[82]
  PIN i_d[83]
    DIRECTION INPUT ;
    USE SIGNAL ;
    PORT
      LAYER M4 ;
        RECT  94.848 18.288 95.04 18.312 ;
    END
  END i_d[83]
  PIN i_d[84]
    DIRECTION INPUT ;
    USE SIGNAL ;
    PORT
      LAYER M4 ;
        RECT  94.848 18.576 95.04 18.6 ;
    END
  END i_d[84]
  PIN i_d[85]
    DIRECTION INPUT ;
    USE SIGNAL ;
    PORT
      LAYER M4 ;
        RECT  94.848 18.72 95.04 18.744 ;
    END
  END i_d[85]
  PIN i_d[86]
    DIRECTION INPUT ;
    USE SIGNAL ;
    PORT
      LAYER M4 ;
        RECT  94.848 18.864 95.04 18.888 ;
    END
  END i_d[86]
  PIN i_d[87]
    DIRECTION INPUT ;
    USE SIGNAL ;
    PORT
      LAYER M4 ;
        RECT  94.848 19.008 95.04 19.032 ;
    END
  END i_d[87]
  PIN i_d[88]
    DIRECTION INPUT ;
    USE SIGNAL ;
    PORT
      LAYER M4 ;
        RECT  94.848 19.152 95.04 19.176 ;
    END
  END i_d[88]
  PIN i_d[89]
    DIRECTION INPUT ;
    USE SIGNAL ;
    PORT
      LAYER M4 ;
        RECT  94.848 19.296 95.04 19.32 ;
    END
  END i_d[89]
  PIN i_d[8]
    DIRECTION INPUT ;
    USE SIGNAL ;
    PORT
      LAYER M4 ;
        RECT  94.848 5.616 95.04 5.64 ;
    END
  END i_d[8]
  PIN i_d[90]
    DIRECTION INPUT ;
    USE SIGNAL ;
    PORT
      LAYER M4 ;
        RECT  94.848 19.584 95.04 19.608 ;
    END
  END i_d[90]
  PIN i_d[91]
    DIRECTION INPUT ;
    USE SIGNAL ;
    PORT
      LAYER M4 ;
        RECT  94.848 19.728 95.04 19.752 ;
    END
  END i_d[91]
  PIN i_d[92]
    DIRECTION INPUT ;
    USE SIGNAL ;
    PORT
      LAYER M4 ;
        RECT  94.848 19.872 95.04 19.896 ;
    END
  END i_d[92]
  PIN i_d[93]
    DIRECTION INPUT ;
    USE SIGNAL ;
    PORT
      LAYER M4 ;
        RECT  94.848 20.016 95.04 20.04 ;
    END
  END i_d[93]
  PIN i_d[94]
    DIRECTION INPUT ;
    USE SIGNAL ;
    PORT
      LAYER M4 ;
        RECT  94.848 20.16 95.04 20.184 ;
    END
  END i_d[94]
  PIN i_d[95]
    DIRECTION INPUT ;
    USE SIGNAL ;
    PORT
      LAYER M4 ;
        RECT  94.848 20.304 95.04 20.328 ;
    END
  END i_d[95]
  PIN i_d[96]
    DIRECTION INPUT ;
    USE SIGNAL ;
    PORT
      LAYER M4 ;
        RECT  94.848 20.592 95.04 20.616 ;
    END
  END i_d[96]
  PIN i_d[97]
    DIRECTION INPUT ;
    USE SIGNAL ;
    PORT
      LAYER M4 ;
        RECT  94.848 20.736 95.04 20.76 ;
    END
  END i_d[97]
  PIN i_d[98]
    DIRECTION INPUT ;
    USE SIGNAL ;
    PORT
      LAYER M4 ;
        RECT  94.848 20.88 95.04 20.904 ;
    END
  END i_d[98]
  PIN i_d[99]
    DIRECTION INPUT ;
    USE SIGNAL ;
    PORT
      LAYER M4 ;
        RECT  94.848 21.024 95.04 21.048 ;
    END
  END i_d[99]
  PIN i_d[9]
    DIRECTION INPUT ;
    USE SIGNAL ;
    PORT
      LAYER M4 ;
        RECT  94.848 5.904 95.04 5.928 ;
    END
  END i_d[9]
  PIN i_v
    DIRECTION INPUT ;
    USE SIGNAL ;
    PORT
      LAYER M5 ;
        RECT  88.896 94.848 88.92 95.04 ;
    END
    PORT
      LAYER M5 ;
        RECT  88.896 94.069 88.92 94.864 ;
    END
  END i_v
  PIN larm_base[0]
    DIRECTION INPUT ;
    USE SIGNAL ;
    PORT
      LAYER M5 ;
        RECT  34.032 94.848 34.056 95.04 ;
    END
    PORT
      LAYER M5 ;
        RECT  34.032 92.903 34.056 94.864 ;
    END
  END larm_base[0]
  PIN larm_base[10]
    DIRECTION INPUT ;
    USE SIGNAL ;
    PORT
      LAYER M5 ;
        RECT  73.104 94.848 73.128 95.04 ;
    END
    PORT
      LAYER M5 ;
        RECT  73.104 94.069 73.128 94.864 ;
    END
  END larm_base[10]
  PIN larm_base[11]
    DIRECTION INPUT ;
    USE SIGNAL ;
    PORT
      LAYER M5 ;
        RECT  77.232 94.848 77.256 95.04 ;
    END
    PORT
      LAYER M5 ;
        RECT  77.232 92.903 77.256 94.864 ;
    END
  END larm_base[11]
  PIN larm_base[12]
    DIRECTION INPUT ;
    USE SIGNAL ;
    PORT
      LAYER M5 ;
        RECT  80.832 94.848 80.856 95.04 ;
    END
    PORT
      LAYER M5 ;
        RECT  80.832 92.821 80.856 94.864 ;
    END
  END larm_base[12]
  PIN larm_base[13]
    DIRECTION INPUT ;
    USE SIGNAL ;
    PORT
      LAYER M5 ;
        RECT  84.768 94.848 84.792 95.04 ;
    END
    PORT
      LAYER M5 ;
        RECT  84.768 92.821 84.792 94.864 ;
    END
  END larm_base[13]
  PIN larm_base[1]
    DIRECTION INPUT ;
    USE SIGNAL ;
    PORT
      LAYER M5 ;
        RECT  37.632 94.848 37.656 95.04 ;
    END
    PORT
      LAYER M5 ;
        RECT  37.632 94.069 37.656 94.864 ;
    END
  END larm_base[1]
  PIN larm_base[2]
    DIRECTION INPUT ;
    USE SIGNAL ;
    PORT
      LAYER M5 ;
        RECT  41.568 94.848 41.592 95.04 ;
    END
    PORT
      LAYER M5 ;
        RECT  41.568 92.821 41.592 94.864 ;
    END
  END larm_base[2]
  PIN larm_base[3]
    DIRECTION INPUT ;
    USE SIGNAL ;
    PORT
      LAYER M5 ;
        RECT  45.696 94.848 45.72 95.04 ;
    END
    PORT
      LAYER M5 ;
        RECT  45.696 94.069 45.72 94.864 ;
    END
  END larm_base[3]
  PIN larm_base[4]
    DIRECTION INPUT ;
    USE SIGNAL ;
    PORT
      LAYER M5 ;
        RECT  49.776 94.848 49.8 95.04 ;
    END
    PORT
      LAYER M5 ;
        RECT  49.776 94.069 49.8 94.864 ;
    END
  END larm_base[4]
  PIN larm_base[5]
    DIRECTION INPUT ;
    USE SIGNAL ;
    PORT
      LAYER M5 ;
        RECT  53.376 94.848 53.4 95.04 ;
    END
    PORT
      LAYER M5 ;
        RECT  53.376 92.821 53.4 94.864 ;
    END
  END larm_base[5]
  PIN larm_base[6]
    DIRECTION INPUT ;
    USE SIGNAL ;
    PORT
      LAYER M5 ;
        RECT  57.36 94.848 57.384 95.04 ;
    END
    PORT
      LAYER M5 ;
        RECT  57.36 92.903 57.384 94.864 ;
    END
  END larm_base[6]
  PIN larm_base[7]
    DIRECTION INPUT ;
    USE SIGNAL ;
    PORT
      LAYER M5 ;
        RECT  61.44 94.848 61.464 95.04 ;
    END
    PORT
      LAYER M5 ;
        RECT  61.44 92.903 61.464 94.864 ;
    END
  END larm_base[7]
  PIN larm_base[8]
    DIRECTION INPUT ;
    USE SIGNAL ;
    PORT
      LAYER M5 ;
        RECT  65.568 94.848 65.592 95.04 ;
    END
    PORT
      LAYER M5 ;
        RECT  65.568 94.069 65.592 94.864 ;
    END
  END larm_base[8]
  PIN larm_base[9]
    DIRECTION INPUT ;
    USE SIGNAL ;
    PORT
      LAYER M5 ;
        RECT  69.168 94.848 69.192 95.04 ;
    END
    PORT
      LAYER M5 ;
        RECT  69.168 94.069 69.192 94.864 ;
    END
  END larm_base[9]
  PIN larm_g[0]
    DIRECTION INPUT ;
    USE SIGNAL ;
    PORT
      LAYER M5 ;
        RECT  18.24 94.848 18.264 95.04 ;
    END
    PORT
      LAYER M5 ;
        RECT  18.24 92.903 18.264 94.864 ;
    END
  END larm_g[0]
  PIN larm_g[1]
    DIRECTION INPUT ;
    USE SIGNAL ;
    PORT
      LAYER M5 ;
        RECT  22.368 94.848 22.392 95.04 ;
    END
    PORT
      LAYER M5 ;
        RECT  22.368 94.069 22.392 94.864 ;
    END
  END larm_g[1]
  PIN larm_g[2]
    DIRECTION INPUT ;
    USE SIGNAL ;
    PORT
      LAYER M5 ;
        RECT  25.968 94.848 25.992 95.04 ;
    END
    PORT
      LAYER M5 ;
        RECT  25.968 92.821 25.992 94.864 ;
    END
  END larm_g[2]
  PIN larm_g[3]
    DIRECTION INPUT ;
    USE SIGNAL ;
    PORT
      LAYER M5 ;
        RECT  29.904 94.848 29.928 95.04 ;
    END
    PORT
      LAYER M5 ;
        RECT  29.904 92.903 29.928 94.864 ;
    END
  END larm_g[3]
  PIN larm_v
    DIRECTION INPUT ;
    USE SIGNAL ;
    PORT
      LAYER M5 ;
        RECT  14.16 94.848 14.184 95.04 ;
    END
    PORT
      LAYER M5 ;
        RECT  14.16 92.903 14.184 94.864 ;
    END
  END larm_v
  PIN o_d[0]
    DIRECTION OUTPUT ;
    USE SIGNAL ;
    PORT
      LAYER M4 ;
        RECT  0 4.32 0.192 4.344 ;
    END
  END o_d[0]
  PIN o_d[100]
    DIRECTION OUTPUT ;
    USE SIGNAL ;
    PORT
      LAYER M4 ;
        RECT  0 20.736 0.192 20.76 ;
    END
  END o_d[100]
  PIN o_d[101]
    DIRECTION OUTPUT ;
    USE SIGNAL ;
    PORT
      LAYER M4 ;
        RECT  0 20.88 0.192 20.904 ;
    END
  END o_d[101]
  PIN o_d[102]
    DIRECTION OUTPUT ;
    USE SIGNAL ;
    PORT
      LAYER M4 ;
        RECT  0 21.024 0.192 21.048 ;
    END
  END o_d[102]
  PIN o_d[103]
    DIRECTION OUTPUT ;
    USE SIGNAL ;
    PORT
      LAYER M4 ;
        RECT  0 21.168 0.192 21.192 ;
    END
  END o_d[103]
  PIN o_d[104]
    DIRECTION OUTPUT ;
    USE SIGNAL ;
    PORT
      LAYER M4 ;
        RECT  0 21.312 0.192 21.336 ;
    END
  END o_d[104]
  PIN o_d[105]
    DIRECTION OUTPUT ;
    USE SIGNAL ;
    PORT
      LAYER M4 ;
        RECT  0 21.6 0.192 21.624 ;
    END
  END o_d[105]
  PIN o_d[106]
    DIRECTION OUTPUT ;
    USE SIGNAL ;
    PORT
      LAYER M4 ;
        RECT  0 21.744 0.192 21.768 ;
    END
  END o_d[106]
  PIN o_d[107]
    DIRECTION OUTPUT ;
    USE SIGNAL ;
    PORT
      LAYER M4 ;
        RECT  0 21.888 0.192 21.912 ;
    END
  END o_d[107]
  PIN o_d[108]
    DIRECTION OUTPUT ;
    USE SIGNAL ;
    PORT
      LAYER M4 ;
        RECT  0 22.032 0.192 22.056 ;
    END
  END o_d[108]
  PIN o_d[109]
    DIRECTION OUTPUT ;
    USE SIGNAL ;
    PORT
      LAYER M4 ;
        RECT  0 22.176 0.192 22.2 ;
    END
  END o_d[109]
  PIN o_d[10]
    DIRECTION OUTPUT ;
    USE SIGNAL ;
    PORT
      LAYER M4 ;
        RECT  0 5.904 0.192 5.928 ;
    END
  END o_d[10]
  PIN o_d[110]
    DIRECTION OUTPUT ;
    USE SIGNAL ;
    PORT
      LAYER M4 ;
        RECT  0 22.32 0.192 22.344 ;
    END
  END o_d[110]
  PIN o_d[111]
    DIRECTION OUTPUT ;
    USE SIGNAL ;
    PORT
      LAYER M4 ;
        RECT  0 22.464 0.192 22.488 ;
    END
  END o_d[111]
  PIN o_d[112]
    DIRECTION OUTPUT ;
    USE SIGNAL ;
    PORT
      LAYER M4 ;
        RECT  0 22.752 0.192 22.776 ;
    END
  END o_d[112]
  PIN o_d[113]
    DIRECTION OUTPUT ;
    USE SIGNAL ;
    PORT
      LAYER M4 ;
        RECT  0 22.896 0.192 22.92 ;
    END
  END o_d[113]
  PIN o_d[114]
    DIRECTION OUTPUT ;
    USE SIGNAL ;
    PORT
      LAYER M4 ;
        RECT  0 23.04 0.192 23.064 ;
    END
  END o_d[114]
  PIN o_d[115]
    DIRECTION OUTPUT ;
    USE SIGNAL ;
    PORT
      LAYER M4 ;
        RECT  0 23.184 0.192 23.208 ;
    END
  END o_d[115]
  PIN o_d[116]
    DIRECTION OUTPUT ;
    USE SIGNAL ;
    PORT
      LAYER M4 ;
        RECT  0 23.328 0.192 23.352 ;
    END
  END o_d[116]
  PIN o_d[117]
    DIRECTION OUTPUT ;
    USE SIGNAL ;
    PORT
      LAYER M4 ;
        RECT  0 23.472 0.192 23.496 ;
    END
  END o_d[117]
  PIN o_d[118]
    DIRECTION OUTPUT ;
    USE SIGNAL ;
    PORT
      LAYER M4 ;
        RECT  0 23.616 0.192 23.64 ;
    END
  END o_d[118]
  PIN o_d[119]
    DIRECTION OUTPUT ;
    USE SIGNAL ;
    PORT
      LAYER M4 ;
        RECT  0 23.904 0.192 23.928 ;
    END
  END o_d[119]
  PIN o_d[11]
    DIRECTION OUTPUT ;
    USE SIGNAL ;
    PORT
      LAYER M4 ;
        RECT  0 6.192 0.192 6.216 ;
    END
  END o_d[11]
  PIN o_d[120]
    DIRECTION OUTPUT ;
    USE SIGNAL ;
    PORT
      LAYER M4 ;
        RECT  0 24.048 0.192 24.072 ;
    END
  END o_d[120]
  PIN o_d[121]
    DIRECTION OUTPUT ;
    USE SIGNAL ;
    PORT
      LAYER M4 ;
        RECT  0 24.192 0.192 24.216 ;
    END
  END o_d[121]
  PIN o_d[122]
    DIRECTION OUTPUT ;
    USE SIGNAL ;
    PORT
      LAYER M4 ;
        RECT  0 24.336 0.192 24.36 ;
    END
  END o_d[122]
  PIN o_d[123]
    DIRECTION OUTPUT ;
    USE SIGNAL ;
    PORT
      LAYER M4 ;
        RECT  0 24.48 0.192 24.504 ;
    END
  END o_d[123]
  PIN o_d[124]
    DIRECTION OUTPUT ;
    USE SIGNAL ;
    PORT
      LAYER M4 ;
        RECT  0 24.624 0.192 24.648 ;
    END
  END o_d[124]
  PIN o_d[125]
    DIRECTION OUTPUT ;
    USE SIGNAL ;
    PORT
      LAYER M4 ;
        RECT  0 24.768 0.192 24.792 ;
    END
  END o_d[125]
  PIN o_d[126]
    DIRECTION OUTPUT ;
    USE SIGNAL ;
    PORT
      LAYER M4 ;
        RECT  0 25.056 0.192 25.08 ;
    END
  END o_d[126]
  PIN o_d[127]
    DIRECTION OUTPUT ;
    USE SIGNAL ;
    PORT
      LAYER M4 ;
        RECT  0 25.2 0.192 25.224 ;
    END
  END o_d[127]
  PIN o_d[128]
    DIRECTION OUTPUT ;
    USE SIGNAL ;
    PORT
      LAYER M4 ;
        RECT  0 25.344 0.192 25.368 ;
    END
  END o_d[128]
  PIN o_d[129]
    DIRECTION OUTPUT ;
    USE SIGNAL ;
    PORT
      LAYER M4 ;
        RECT  0 25.488 0.192 25.512 ;
    END
  END o_d[129]
  PIN o_d[12]
    DIRECTION OUTPUT ;
    USE SIGNAL ;
    PORT
      LAYER M4 ;
        RECT  0 6.336 0.192 6.36 ;
    END
  END o_d[12]
  PIN o_d[130]
    DIRECTION OUTPUT ;
    USE SIGNAL ;
    PORT
      LAYER M4 ;
        RECT  0 25.632 0.192 25.656 ;
    END
  END o_d[130]
  PIN o_d[131]
    DIRECTION OUTPUT ;
    USE SIGNAL ;
    PORT
      LAYER M4 ;
        RECT  0 25.776 0.192 25.8 ;
    END
  END o_d[131]
  PIN o_d[132]
    DIRECTION OUTPUT ;
    USE SIGNAL ;
    PORT
      LAYER M4 ;
        RECT  0 25.92 0.192 25.944 ;
    END
  END o_d[132]
  PIN o_d[133]
    DIRECTION OUTPUT ;
    USE SIGNAL ;
    PORT
      LAYER M4 ;
        RECT  0 26.064 0.192 26.088 ;
    END
  END o_d[133]
  PIN o_d[134]
    DIRECTION OUTPUT ;
    USE SIGNAL ;
    PORT
      LAYER M4 ;
        RECT  0 26.352 0.192 26.376 ;
    END
  END o_d[134]
  PIN o_d[135]
    DIRECTION OUTPUT ;
    USE SIGNAL ;
    PORT
      LAYER M4 ;
        RECT  0 26.496 0.192 26.52 ;
    END
  END o_d[135]
  PIN o_d[136]
    DIRECTION OUTPUT ;
    USE SIGNAL ;
    PORT
      LAYER M4 ;
        RECT  0 26.64 0.192 26.664 ;
    END
  END o_d[136]
  PIN o_d[137]
    DIRECTION OUTPUT ;
    USE SIGNAL ;
    PORT
      LAYER M4 ;
        RECT  0 26.784 0.192 26.808 ;
    END
  END o_d[137]
  PIN o_d[138]
    DIRECTION OUTPUT ;
    USE SIGNAL ;
    PORT
      LAYER M4 ;
        RECT  0 26.928 0.192 26.952 ;
    END
  END o_d[138]
  PIN o_d[139]
    DIRECTION OUTPUT ;
    USE SIGNAL ;
    PORT
      LAYER M4 ;
        RECT  0 27.072 0.192 27.096 ;
    END
  END o_d[139]
  PIN o_d[13]
    DIRECTION OUTPUT ;
    USE SIGNAL ;
    PORT
      LAYER M4 ;
        RECT  0 6.48 0.192 6.504 ;
    END
  END o_d[13]
  PIN o_d[140]
    DIRECTION OUTPUT ;
    USE SIGNAL ;
    PORT
      LAYER M4 ;
        RECT  0 27.216 0.192 27.24 ;
    END
  END o_d[140]
  PIN o_d[141]
    DIRECTION OUTPUT ;
    USE SIGNAL ;
    PORT
      LAYER M4 ;
        RECT  0 27.504 0.192 27.528 ;
    END
  END o_d[141]
  PIN o_d[142]
    DIRECTION OUTPUT ;
    USE SIGNAL ;
    PORT
      LAYER M4 ;
        RECT  0 27.648 0.192 27.672 ;
    END
  END o_d[142]
  PIN o_d[143]
    DIRECTION OUTPUT ;
    USE SIGNAL ;
    PORT
      LAYER M4 ;
        RECT  0 27.792 0.192 27.816 ;
    END
  END o_d[143]
  PIN o_d[144]
    DIRECTION OUTPUT ;
    USE SIGNAL ;
    PORT
      LAYER M4 ;
        RECT  0 27.936 0.192 27.96 ;
    END
  END o_d[144]
  PIN o_d[145]
    DIRECTION OUTPUT ;
    USE SIGNAL ;
    PORT
      LAYER M4 ;
        RECT  0 28.08 0.192 28.104 ;
    END
  END o_d[145]
  PIN o_d[146]
    DIRECTION OUTPUT ;
    USE SIGNAL ;
    PORT
      LAYER M4 ;
        RECT  0 28.224 0.192 28.248 ;
    END
  END o_d[146]
  PIN o_d[147]
    DIRECTION OUTPUT ;
    USE SIGNAL ;
    PORT
      LAYER M4 ;
        RECT  0 28.368 0.192 28.392 ;
    END
  END o_d[147]
  PIN o_d[148]
    DIRECTION OUTPUT ;
    USE SIGNAL ;
    PORT
      LAYER M4 ;
        RECT  0 28.656 0.192 28.68 ;
    END
  END o_d[148]
  PIN o_d[149]
    DIRECTION OUTPUT ;
    USE SIGNAL ;
    PORT
      LAYER M4 ;
        RECT  0 28.8 0.192 28.824 ;
    END
  END o_d[149]
  PIN o_d[14]
    DIRECTION OUTPUT ;
    USE SIGNAL ;
    PORT
      LAYER M4 ;
        RECT  0 6.624 0.192 6.648 ;
    END
  END o_d[14]
  PIN o_d[150]
    DIRECTION OUTPUT ;
    USE SIGNAL ;
    PORT
      LAYER M4 ;
        RECT  0 28.944 0.192 28.968 ;
    END
  END o_d[150]
  PIN o_d[151]
    DIRECTION OUTPUT ;
    USE SIGNAL ;
    PORT
      LAYER M4 ;
        RECT  0 29.088 0.192 29.112 ;
    END
  END o_d[151]
  PIN o_d[152]
    DIRECTION OUTPUT ;
    USE SIGNAL ;
    PORT
      LAYER M4 ;
        RECT  0 29.232 0.192 29.256 ;
    END
  END o_d[152]
  PIN o_d[153]
    DIRECTION OUTPUT ;
    USE SIGNAL ;
    PORT
      LAYER M4 ;
        RECT  0 29.376 0.192 29.4 ;
    END
  END o_d[153]
  PIN o_d[154]
    DIRECTION OUTPUT ;
    USE SIGNAL ;
    PORT
      LAYER M4 ;
        RECT  0 29.52 0.192 29.544 ;
    END
  END o_d[154]
  PIN o_d[155]
    DIRECTION OUTPUT ;
    USE SIGNAL ;
    PORT
      LAYER M4 ;
        RECT  0 29.808 0.192 29.832 ;
    END
  END o_d[155]
  PIN o_d[156]
    DIRECTION OUTPUT ;
    USE SIGNAL ;
    PORT
      LAYER M4 ;
        RECT  0 29.952 0.192 29.976 ;
    END
  END o_d[156]
  PIN o_d[157]
    DIRECTION OUTPUT ;
    USE SIGNAL ;
    PORT
      LAYER M4 ;
        RECT  0 30.096 0.192 30.12 ;
    END
  END o_d[157]
  PIN o_d[158]
    DIRECTION OUTPUT ;
    USE SIGNAL ;
    PORT
      LAYER M4 ;
        RECT  0 30.24 0.192 30.264 ;
    END
  END o_d[158]
  PIN o_d[159]
    DIRECTION OUTPUT ;
    USE SIGNAL ;
    PORT
      LAYER M4 ;
        RECT  0 30.384 0.192 30.408 ;
    END
  END o_d[159]
  PIN o_d[15]
    DIRECTION OUTPUT ;
    USE SIGNAL ;
    PORT
      LAYER M4 ;
        RECT  0 6.768 0.192 6.792 ;
    END
  END o_d[15]
  PIN o_d[160]
    DIRECTION OUTPUT ;
    USE SIGNAL ;
    PORT
      LAYER M4 ;
        RECT  0 30.528 0.192 30.552 ;
    END
  END o_d[160]
  PIN o_d[161]
    DIRECTION OUTPUT ;
    USE SIGNAL ;
    PORT
      LAYER M4 ;
        RECT  0 30.672 0.192 30.696 ;
    END
  END o_d[161]
  PIN o_d[162]
    DIRECTION OUTPUT ;
    USE SIGNAL ;
    PORT
      LAYER M4 ;
        RECT  0 30.96 0.192 30.984 ;
    END
  END o_d[162]
  PIN o_d[163]
    DIRECTION OUTPUT ;
    USE SIGNAL ;
    PORT
      LAYER M4 ;
        RECT  0 31.104 0.192 31.128 ;
    END
  END o_d[163]
  PIN o_d[164]
    DIRECTION OUTPUT ;
    USE SIGNAL ;
    PORT
      LAYER M4 ;
        RECT  0 31.248 0.192 31.272 ;
    END
  END o_d[164]
  PIN o_d[165]
    DIRECTION OUTPUT ;
    USE SIGNAL ;
    PORT
      LAYER M4 ;
        RECT  0 31.392 0.192 31.416 ;
    END
  END o_d[165]
  PIN o_d[166]
    DIRECTION OUTPUT ;
    USE SIGNAL ;
    PORT
      LAYER M4 ;
        RECT  0 31.536 0.192 31.56 ;
    END
  END o_d[166]
  PIN o_d[167]
    DIRECTION OUTPUT ;
    USE SIGNAL ;
    PORT
      LAYER M4 ;
        RECT  0 31.68 0.192 31.704 ;
    END
  END o_d[167]
  PIN o_d[168]
    DIRECTION OUTPUT ;
    USE SIGNAL ;
    PORT
      LAYER M4 ;
        RECT  0 31.824 0.192 31.848 ;
    END
  END o_d[168]
  PIN o_d[169]
    DIRECTION OUTPUT ;
    USE SIGNAL ;
    PORT
      LAYER M4 ;
        RECT  0 31.968 0.192 31.992 ;
    END
  END o_d[169]
  PIN o_d[16]
    DIRECTION OUTPUT ;
    USE SIGNAL ;
    PORT
      LAYER M4 ;
        RECT  0 6.912 0.192 6.936 ;
    END
  END o_d[16]
  PIN o_d[170]
    DIRECTION OUTPUT ;
    USE SIGNAL ;
    PORT
      LAYER M4 ;
        RECT  0 32.256 0.192 32.28 ;
    END
  END o_d[170]
  PIN o_d[171]
    DIRECTION OUTPUT ;
    USE SIGNAL ;
    PORT
      LAYER M4 ;
        RECT  0 32.4 0.192 32.424 ;
    END
  END o_d[171]
  PIN o_d[172]
    DIRECTION OUTPUT ;
    USE SIGNAL ;
    PORT
      LAYER M4 ;
        RECT  0 32.544 0.192 32.568 ;
    END
  END o_d[172]
  PIN o_d[173]
    DIRECTION OUTPUT ;
    USE SIGNAL ;
    PORT
      LAYER M4 ;
        RECT  0 32.688 0.192 32.712 ;
    END
  END o_d[173]
  PIN o_d[174]
    DIRECTION OUTPUT ;
    USE SIGNAL ;
    PORT
      LAYER M4 ;
        RECT  0 32.832 0.192 32.856 ;
    END
  END o_d[174]
  PIN o_d[175]
    DIRECTION OUTPUT ;
    USE SIGNAL ;
    PORT
      LAYER M4 ;
        RECT  0 32.976 0.192 33 ;
    END
  END o_d[175]
  PIN o_d[176]
    DIRECTION OUTPUT ;
    USE SIGNAL ;
    PORT
      LAYER M4 ;
        RECT  0 33.12 0.192 33.144 ;
    END
  END o_d[176]
  PIN o_d[177]
    DIRECTION OUTPUT ;
    USE SIGNAL ;
    PORT
      LAYER M4 ;
        RECT  0 33.408 0.192 33.432 ;
    END
  END o_d[177]
  PIN o_d[178]
    DIRECTION OUTPUT ;
    USE SIGNAL ;
    PORT
      LAYER M4 ;
        RECT  0 33.552 0.192 33.576 ;
    END
  END o_d[178]
  PIN o_d[179]
    DIRECTION OUTPUT ;
    USE SIGNAL ;
    PORT
      LAYER M4 ;
        RECT  0 33.696 0.192 33.72 ;
    END
  END o_d[179]
  PIN o_d[17]
    DIRECTION OUTPUT ;
    USE SIGNAL ;
    PORT
      LAYER M4 ;
        RECT  0 7.056 0.192 7.08 ;
    END
  END o_d[17]
  PIN o_d[180]
    DIRECTION OUTPUT ;
    USE SIGNAL ;
    PORT
      LAYER M4 ;
        RECT  0 33.84 0.192 33.864 ;
    END
  END o_d[180]
  PIN o_d[181]
    DIRECTION OUTPUT ;
    USE SIGNAL ;
    PORT
      LAYER M4 ;
        RECT  0 33.984 0.192 34.008 ;
    END
  END o_d[181]
  PIN o_d[182]
    DIRECTION OUTPUT ;
    USE SIGNAL ;
    PORT
      LAYER M4 ;
        RECT  0 34.128 0.192 34.152 ;
    END
  END o_d[182]
  PIN o_d[183]
    DIRECTION OUTPUT ;
    USE SIGNAL ;
    PORT
      LAYER M4 ;
        RECT  0 34.272 0.192 34.296 ;
    END
  END o_d[183]
  PIN o_d[184]
    DIRECTION OUTPUT ;
    USE SIGNAL ;
    PORT
      LAYER M4 ;
        RECT  0 34.56 0.192 34.584 ;
    END
  END o_d[184]
  PIN o_d[185]
    DIRECTION OUTPUT ;
    USE SIGNAL ;
    PORT
      LAYER M4 ;
        RECT  0 34.704 0.192 34.728 ;
    END
  END o_d[185]
  PIN o_d[186]
    DIRECTION OUTPUT ;
    USE SIGNAL ;
    PORT
      LAYER M4 ;
        RECT  0 34.848 0.192 34.872 ;
    END
  END o_d[186]
  PIN o_d[187]
    DIRECTION OUTPUT ;
    USE SIGNAL ;
    PORT
      LAYER M4 ;
        RECT  0 34.992 0.192 35.016 ;
    END
  END o_d[187]
  PIN o_d[188]
    DIRECTION OUTPUT ;
    USE SIGNAL ;
    PORT
      LAYER M4 ;
        RECT  0 35.136 0.192 35.16 ;
    END
  END o_d[188]
  PIN o_d[189]
    DIRECTION OUTPUT ;
    USE SIGNAL ;
    PORT
      LAYER M4 ;
        RECT  0 35.28 0.192 35.304 ;
    END
  END o_d[189]
  PIN o_d[18]
    DIRECTION OUTPUT ;
    USE SIGNAL ;
    PORT
      LAYER M4 ;
        RECT  0 7.344 0.192 7.368 ;
    END
  END o_d[18]
  PIN o_d[190]
    DIRECTION OUTPUT ;
    USE SIGNAL ;
    PORT
      LAYER M4 ;
        RECT  0 35.424 0.192 35.448 ;
    END
  END o_d[190]
  PIN o_d[191]
    DIRECTION OUTPUT ;
    USE SIGNAL ;
    PORT
      LAYER M4 ;
        RECT  0 35.712 0.192 35.736 ;
    END
  END o_d[191]
  PIN o_d[192]
    DIRECTION OUTPUT ;
    USE SIGNAL ;
    PORT
      LAYER M4 ;
        RECT  0 35.856 0.192 35.88 ;
    END
  END o_d[192]
  PIN o_d[193]
    DIRECTION OUTPUT ;
    USE SIGNAL ;
    PORT
      LAYER M4 ;
        RECT  0 36 0.192 36.024 ;
    END
  END o_d[193]
  PIN o_d[194]
    DIRECTION OUTPUT ;
    USE SIGNAL ;
    PORT
      LAYER M4 ;
        RECT  0 36.144 0.192 36.168 ;
    END
  END o_d[194]
  PIN o_d[195]
    DIRECTION OUTPUT ;
    USE SIGNAL ;
    PORT
      LAYER M4 ;
        RECT  0 36.288 0.192 36.312 ;
    END
  END o_d[195]
  PIN o_d[196]
    DIRECTION OUTPUT ;
    USE SIGNAL ;
    PORT
      LAYER M4 ;
        RECT  0 36.432 0.192 36.456 ;
    END
  END o_d[196]
  PIN o_d[197]
    DIRECTION OUTPUT ;
    USE SIGNAL ;
    PORT
      LAYER M4 ;
        RECT  0 36.576 0.192 36.6 ;
    END
  END o_d[197]
  PIN o_d[198]
    DIRECTION OUTPUT ;
    USE SIGNAL ;
    PORT
      LAYER M4 ;
        RECT  0 36.72 0.192 36.744 ;
    END
  END o_d[198]
  PIN o_d[199]
    DIRECTION OUTPUT ;
    USE SIGNAL ;
    PORT
      LAYER M4 ;
        RECT  0 37.008 0.192 37.032 ;
    END
  END o_d[199]
  PIN o_d[19]
    DIRECTION OUTPUT ;
    USE SIGNAL ;
    PORT
      LAYER M4 ;
        RECT  0 7.488 0.192 7.512 ;
    END
  END o_d[19]
  PIN o_d[1]
    DIRECTION OUTPUT ;
    USE SIGNAL ;
    PORT
      LAYER M4 ;
        RECT  0 4.464 0.192 4.488 ;
    END
  END o_d[1]
  PIN o_d[200]
    DIRECTION OUTPUT ;
    USE SIGNAL ;
    PORT
      LAYER M4 ;
        RECT  0 37.152 0.192 37.176 ;
    END
  END o_d[200]
  PIN o_d[201]
    DIRECTION OUTPUT ;
    USE SIGNAL ;
    PORT
      LAYER M4 ;
        RECT  0 37.296 0.192 37.32 ;
    END
  END o_d[201]
  PIN o_d[202]
    DIRECTION OUTPUT ;
    USE SIGNAL ;
    PORT
      LAYER M4 ;
        RECT  0 37.44 0.192 37.464 ;
    END
  END o_d[202]
  PIN o_d[203]
    DIRECTION OUTPUT ;
    USE SIGNAL ;
    PORT
      LAYER M4 ;
        RECT  0 37.584 0.192 37.608 ;
    END
  END o_d[203]
  PIN o_d[204]
    DIRECTION OUTPUT ;
    USE SIGNAL ;
    PORT
      LAYER M4 ;
        RECT  0 37.728 0.192 37.752 ;
    END
  END o_d[204]
  PIN o_d[205]
    DIRECTION OUTPUT ;
    USE SIGNAL ;
    PORT
      LAYER M4 ;
        RECT  0 37.872 0.192 37.896 ;
    END
  END o_d[205]
  PIN o_d[206]
    DIRECTION OUTPUT ;
    USE SIGNAL ;
    PORT
      LAYER M4 ;
        RECT  0 38.16 0.192 38.184 ;
    END
  END o_d[206]
  PIN o_d[207]
    DIRECTION OUTPUT ;
    USE SIGNAL ;
    PORT
      LAYER M4 ;
        RECT  0 38.304 0.192 38.328 ;
    END
  END o_d[207]
  PIN o_d[208]
    DIRECTION OUTPUT ;
    USE SIGNAL ;
    PORT
      LAYER M4 ;
        RECT  0 38.448 0.192 38.472 ;
    END
  END o_d[208]
  PIN o_d[209]
    DIRECTION OUTPUT ;
    USE SIGNAL ;
    PORT
      LAYER M4 ;
        RECT  0 38.592 0.192 38.616 ;
    END
  END o_d[209]
  PIN o_d[20]
    DIRECTION OUTPUT ;
    USE SIGNAL ;
    PORT
      LAYER M4 ;
        RECT  0 7.632 0.192 7.656 ;
    END
  END o_d[20]
  PIN o_d[210]
    DIRECTION OUTPUT ;
    USE SIGNAL ;
    PORT
      LAYER M4 ;
        RECT  0 38.736 0.192 38.76 ;
    END
  END o_d[210]
  PIN o_d[211]
    DIRECTION OUTPUT ;
    USE SIGNAL ;
    PORT
      LAYER M4 ;
        RECT  0 38.88 0.192 38.904 ;
    END
  END o_d[211]
  PIN o_d[212]
    DIRECTION OUTPUT ;
    USE SIGNAL ;
    PORT
      LAYER M4 ;
        RECT  0 39.024 0.192 39.048 ;
    END
  END o_d[212]
  PIN o_d[213]
    DIRECTION OUTPUT ;
    USE SIGNAL ;
    PORT
      LAYER M4 ;
        RECT  0 39.312 0.192 39.336 ;
    END
  END o_d[213]
  PIN o_d[214]
    DIRECTION OUTPUT ;
    USE SIGNAL ;
    PORT
      LAYER M4 ;
        RECT  0 39.456 0.192 39.48 ;
    END
  END o_d[214]
  PIN o_d[215]
    DIRECTION OUTPUT ;
    USE SIGNAL ;
    PORT
      LAYER M4 ;
        RECT  0 39.6 0.192 39.624 ;
    END
  END o_d[215]
  PIN o_d[216]
    DIRECTION OUTPUT ;
    USE SIGNAL ;
    PORT
      LAYER M4 ;
        RECT  0 39.744 0.192 39.768 ;
    END
  END o_d[216]
  PIN o_d[217]
    DIRECTION OUTPUT ;
    USE SIGNAL ;
    PORT
      LAYER M4 ;
        RECT  0 39.888 0.192 39.912 ;
    END
  END o_d[217]
  PIN o_d[218]
    DIRECTION OUTPUT ;
    USE SIGNAL ;
    PORT
      LAYER M4 ;
        RECT  0 40.032 0.192 40.056 ;
    END
  END o_d[218]
  PIN o_d[219]
    DIRECTION OUTPUT ;
    USE SIGNAL ;
    PORT
      LAYER M4 ;
        RECT  0 40.176 0.192 40.2 ;
    END
  END o_d[219]
  PIN o_d[21]
    DIRECTION OUTPUT ;
    USE SIGNAL ;
    PORT
      LAYER M4 ;
        RECT  0 7.776 0.192 7.8 ;
    END
  END o_d[21]
  PIN o_d[220]
    DIRECTION OUTPUT ;
    USE SIGNAL ;
    PORT
      LAYER M4 ;
        RECT  0 40.464 0.192 40.488 ;
    END
  END o_d[220]
  PIN o_d[221]
    DIRECTION OUTPUT ;
    USE SIGNAL ;
    PORT
      LAYER M4 ;
        RECT  0 40.608 0.192 40.632 ;
    END
  END o_d[221]
  PIN o_d[222]
    DIRECTION OUTPUT ;
    USE SIGNAL ;
    PORT
      LAYER M4 ;
        RECT  0 40.752 0.192 40.776 ;
    END
  END o_d[222]
  PIN o_d[223]
    DIRECTION OUTPUT ;
    USE SIGNAL ;
    PORT
      LAYER M4 ;
        RECT  0 40.896 0.192 40.92 ;
    END
  END o_d[223]
  PIN o_d[224]
    DIRECTION OUTPUT ;
    USE SIGNAL ;
    PORT
      LAYER M4 ;
        RECT  0 41.04 0.192 41.064 ;
    END
  END o_d[224]
  PIN o_d[225]
    DIRECTION OUTPUT ;
    USE SIGNAL ;
    PORT
      LAYER M4 ;
        RECT  0 41.184 0.192 41.208 ;
    END
  END o_d[225]
  PIN o_d[226]
    DIRECTION OUTPUT ;
    USE SIGNAL ;
    PORT
      LAYER M4 ;
        RECT  0 41.328 0.192 41.352 ;
    END
  END o_d[226]
  PIN o_d[227]
    DIRECTION OUTPUT ;
    USE SIGNAL ;
    PORT
      LAYER M4 ;
        RECT  0 41.616 0.192 41.64 ;
    END
  END o_d[227]
  PIN o_d[228]
    DIRECTION OUTPUT ;
    USE SIGNAL ;
    PORT
      LAYER M4 ;
        RECT  0 41.76 0.192 41.784 ;
    END
  END o_d[228]
  PIN o_d[229]
    DIRECTION OUTPUT ;
    USE SIGNAL ;
    PORT
      LAYER M4 ;
        RECT  0 41.904 0.192 41.928 ;
    END
  END o_d[229]
  PIN o_d[22]
    DIRECTION OUTPUT ;
    USE SIGNAL ;
    PORT
      LAYER M4 ;
        RECT  0 7.92 0.192 7.944 ;
    END
  END o_d[22]
  PIN o_d[230]
    DIRECTION OUTPUT ;
    USE SIGNAL ;
    PORT
      LAYER M4 ;
        RECT  0 42.048 0.192 42.072 ;
    END
  END o_d[230]
  PIN o_d[231]
    DIRECTION OUTPUT ;
    USE SIGNAL ;
    PORT
      LAYER M4 ;
        RECT  0 42.192 0.192 42.216 ;
    END
  END o_d[231]
  PIN o_d[232]
    DIRECTION OUTPUT ;
    USE SIGNAL ;
    PORT
      LAYER M4 ;
        RECT  0 42.336 0.192 42.36 ;
    END
  END o_d[232]
  PIN o_d[233]
    DIRECTION OUTPUT ;
    USE SIGNAL ;
    PORT
      LAYER M4 ;
        RECT  0 42.48 0.192 42.504 ;
    END
  END o_d[233]
  PIN o_d[234]
    DIRECTION OUTPUT ;
    USE SIGNAL ;
    PORT
      LAYER M4 ;
        RECT  0 42.624 0.192 42.648 ;
    END
  END o_d[234]
  PIN o_d[235]
    DIRECTION OUTPUT ;
    USE SIGNAL ;
    PORT
      LAYER M4 ;
        RECT  0 42.912 0.192 42.936 ;
    END
  END o_d[235]
  PIN o_d[236]
    DIRECTION OUTPUT ;
    USE SIGNAL ;
    PORT
      LAYER M4 ;
        RECT  0 43.056 0.192 43.08 ;
    END
  END o_d[236]
  PIN o_d[237]
    DIRECTION OUTPUT ;
    USE SIGNAL ;
    PORT
      LAYER M4 ;
        RECT  0 43.2 0.192 43.224 ;
    END
  END o_d[237]
  PIN o_d[238]
    DIRECTION OUTPUT ;
    USE SIGNAL ;
    PORT
      LAYER M4 ;
        RECT  0 43.344 0.192 43.368 ;
    END
  END o_d[238]
  PIN o_d[239]
    DIRECTION OUTPUT ;
    USE SIGNAL ;
    PORT
      LAYER M4 ;
        RECT  0 43.488 0.192 43.512 ;
    END
  END o_d[239]
  PIN o_d[23]
    DIRECTION OUTPUT ;
    USE SIGNAL ;
    PORT
      LAYER M4 ;
        RECT  0 8.064 0.192 8.088 ;
    END
  END o_d[23]
  PIN o_d[240]
    DIRECTION OUTPUT ;
    USE SIGNAL ;
    PORT
      LAYER M4 ;
        RECT  0 43.632 0.192 43.656 ;
    END
  END o_d[240]
  PIN o_d[241]
    DIRECTION OUTPUT ;
    USE SIGNAL ;
    PORT
      LAYER M4 ;
        RECT  0 43.776 0.192 43.8 ;
    END
  END o_d[241]
  PIN o_d[242]
    DIRECTION OUTPUT ;
    USE SIGNAL ;
    PORT
      LAYER M4 ;
        RECT  0 44.064 0.192 44.088 ;
    END
  END o_d[242]
  PIN o_d[243]
    DIRECTION OUTPUT ;
    USE SIGNAL ;
    PORT
      LAYER M4 ;
        RECT  0 44.208 0.192 44.232 ;
    END
  END o_d[243]
  PIN o_d[244]
    DIRECTION OUTPUT ;
    USE SIGNAL ;
    PORT
      LAYER M4 ;
        RECT  0 44.352 0.192 44.376 ;
    END
  END o_d[244]
  PIN o_d[245]
    DIRECTION OUTPUT ;
    USE SIGNAL ;
    PORT
      LAYER M4 ;
        RECT  0 44.496 0.192 44.52 ;
    END
  END o_d[245]
  PIN o_d[246]
    DIRECTION OUTPUT ;
    USE SIGNAL ;
    PORT
      LAYER M4 ;
        RECT  0 44.64 0.192 44.664 ;
    END
  END o_d[246]
  PIN o_d[247]
    DIRECTION OUTPUT ;
    USE SIGNAL ;
    PORT
      LAYER M4 ;
        RECT  0 44.784 0.192 44.808 ;
    END
  END o_d[247]
  PIN o_d[248]
    DIRECTION OUTPUT ;
    USE SIGNAL ;
    PORT
      LAYER M4 ;
        RECT  0 44.928 0.192 44.952 ;
    END
  END o_d[248]
  PIN o_d[249]
    DIRECTION OUTPUT ;
    USE SIGNAL ;
    PORT
      LAYER M4 ;
        RECT  0 45.216 0.192 45.24 ;
    END
  END o_d[249]
  PIN o_d[24]
    DIRECTION OUTPUT ;
    USE SIGNAL ;
    PORT
      LAYER M4 ;
        RECT  0 8.208 0.192 8.232 ;
    END
  END o_d[24]
  PIN o_d[250]
    DIRECTION OUTPUT ;
    USE SIGNAL ;
    PORT
      LAYER M4 ;
        RECT  0 45.36 0.192 45.384 ;
    END
  END o_d[250]
  PIN o_d[251]
    DIRECTION OUTPUT ;
    USE SIGNAL ;
    PORT
      LAYER M4 ;
        RECT  0 45.504 0.192 45.528 ;
    END
  END o_d[251]
  PIN o_d[252]
    DIRECTION OUTPUT ;
    USE SIGNAL ;
    PORT
      LAYER M4 ;
        RECT  0 45.648 0.192 45.672 ;
    END
  END o_d[252]
  PIN o_d[253]
    DIRECTION OUTPUT ;
    USE SIGNAL ;
    PORT
      LAYER M4 ;
        RECT  0 45.792 0.192 45.816 ;
    END
  END o_d[253]
  PIN o_d[254]
    DIRECTION OUTPUT ;
    USE SIGNAL ;
    PORT
      LAYER M4 ;
        RECT  0 45.936 0.192 45.96 ;
    END
  END o_d[254]
  PIN o_d[255]
    DIRECTION OUTPUT ;
    USE SIGNAL ;
    PORT
      LAYER M4 ;
        RECT  0 46.08 0.192 46.104 ;
    END
  END o_d[255]
  PIN o_d[256]
    DIRECTION OUTPUT ;
    USE SIGNAL ;
    PORT
      LAYER M4 ;
        RECT  0 46.368 0.192 46.392 ;
    END
  END o_d[256]
  PIN o_d[257]
    DIRECTION OUTPUT ;
    USE SIGNAL ;
    PORT
      LAYER M4 ;
        RECT  0 46.512 0.192 46.536 ;
    END
  END o_d[257]
  PIN o_d[258]
    DIRECTION OUTPUT ;
    USE SIGNAL ;
    PORT
      LAYER M4 ;
        RECT  0 46.656 0.192 46.68 ;
    END
  END o_d[258]
  PIN o_d[259]
    DIRECTION OUTPUT ;
    USE SIGNAL ;
    PORT
      LAYER M4 ;
        RECT  0 46.8 0.192 46.824 ;
    END
  END o_d[259]
  PIN o_d[25]
    DIRECTION OUTPUT ;
    USE SIGNAL ;
    PORT
      LAYER M4 ;
        RECT  0 8.496 0.192 8.52 ;
    END
  END o_d[25]
  PIN o_d[260]
    DIRECTION OUTPUT ;
    USE SIGNAL ;
    PORT
      LAYER M4 ;
        RECT  0 46.944 0.192 46.968 ;
    END
  END o_d[260]
  PIN o_d[261]
    DIRECTION OUTPUT ;
    USE SIGNAL ;
    PORT
      LAYER M4 ;
        RECT  0 47.088 0.192 47.112 ;
    END
  END o_d[261]
  PIN o_d[262]
    DIRECTION OUTPUT ;
    USE SIGNAL ;
    PORT
      LAYER M4 ;
        RECT  0 47.232 0.192 47.256 ;
    END
  END o_d[262]
  PIN o_d[263]
    DIRECTION OUTPUT ;
    USE SIGNAL ;
    PORT
      LAYER M4 ;
        RECT  0 47.52 0.192 47.544 ;
    END
  END o_d[263]
  PIN o_d[264]
    DIRECTION OUTPUT ;
    USE SIGNAL ;
    PORT
      LAYER M4 ;
        RECT  0 47.664 0.192 47.688 ;
    END
  END o_d[264]
  PIN o_d[265]
    DIRECTION OUTPUT ;
    USE SIGNAL ;
    PORT
      LAYER M4 ;
        RECT  0 47.808 0.192 47.832 ;
    END
  END o_d[265]
  PIN o_d[266]
    DIRECTION OUTPUT ;
    USE SIGNAL ;
    PORT
      LAYER M4 ;
        RECT  0 47.952 0.192 47.976 ;
    END
  END o_d[266]
  PIN o_d[267]
    DIRECTION OUTPUT ;
    USE SIGNAL ;
    PORT
      LAYER M4 ;
        RECT  0 48.096 0.192 48.12 ;
    END
  END o_d[267]
  PIN o_d[268]
    DIRECTION OUTPUT ;
    USE SIGNAL ;
    PORT
      LAYER M4 ;
        RECT  0 48.24 0.192 48.264 ;
    END
  END o_d[268]
  PIN o_d[269]
    DIRECTION OUTPUT ;
    USE SIGNAL ;
    PORT
      LAYER M4 ;
        RECT  0 48.384 0.192 48.408 ;
    END
  END o_d[269]
  PIN o_d[26]
    DIRECTION OUTPUT ;
    USE SIGNAL ;
    PORT
      LAYER M4 ;
        RECT  0 8.64 0.192 8.664 ;
    END
  END o_d[26]
  PIN o_d[270]
    DIRECTION OUTPUT ;
    USE SIGNAL ;
    PORT
      LAYER M4 ;
        RECT  0 48.528 0.192 48.552 ;
    END
  END o_d[270]
  PIN o_d[271]
    DIRECTION OUTPUT ;
    USE SIGNAL ;
    PORT
      LAYER M4 ;
        RECT  0 48.816 0.192 48.84 ;
    END
  END o_d[271]
  PIN o_d[272]
    DIRECTION OUTPUT ;
    USE SIGNAL ;
    PORT
      LAYER M4 ;
        RECT  0 48.96 0.192 48.984 ;
    END
  END o_d[272]
  PIN o_d[273]
    DIRECTION OUTPUT ;
    USE SIGNAL ;
    PORT
      LAYER M4 ;
        RECT  0 49.104 0.192 49.128 ;
    END
  END o_d[273]
  PIN o_d[274]
    DIRECTION OUTPUT ;
    USE SIGNAL ;
    PORT
      LAYER M4 ;
        RECT  0 49.248 0.192 49.272 ;
    END
  END o_d[274]
  PIN o_d[275]
    DIRECTION OUTPUT ;
    USE SIGNAL ;
    PORT
      LAYER M4 ;
        RECT  0 49.392 0.192 49.416 ;
    END
  END o_d[275]
  PIN o_d[276]
    DIRECTION OUTPUT ;
    USE SIGNAL ;
    PORT
      LAYER M4 ;
        RECT  0 49.536 0.192 49.56 ;
    END
  END o_d[276]
  PIN o_d[277]
    DIRECTION OUTPUT ;
    USE SIGNAL ;
    PORT
      LAYER M4 ;
        RECT  0 49.68 0.192 49.704 ;
    END
  END o_d[277]
  PIN o_d[278]
    DIRECTION OUTPUT ;
    USE SIGNAL ;
    PORT
      LAYER M4 ;
        RECT  0 49.968 0.192 49.992 ;
    END
  END o_d[278]
  PIN o_d[279]
    DIRECTION OUTPUT ;
    USE SIGNAL ;
    PORT
      LAYER M4 ;
        RECT  0 50.112 0.192 50.136 ;
    END
  END o_d[279]
  PIN o_d[27]
    DIRECTION OUTPUT ;
    USE SIGNAL ;
    PORT
      LAYER M4 ;
        RECT  0 8.784 0.192 8.808 ;
    END
  END o_d[27]
  PIN o_d[280]
    DIRECTION OUTPUT ;
    USE SIGNAL ;
    PORT
      LAYER M4 ;
        RECT  0 50.256 0.192 50.28 ;
    END
  END o_d[280]
  PIN o_d[281]
    DIRECTION OUTPUT ;
    USE SIGNAL ;
    PORT
      LAYER M4 ;
        RECT  0 50.4 0.192 50.424 ;
    END
  END o_d[281]
  PIN o_d[282]
    DIRECTION OUTPUT ;
    USE SIGNAL ;
    PORT
      LAYER M4 ;
        RECT  0 50.544 0.192 50.568 ;
    END
  END o_d[282]
  PIN o_d[283]
    DIRECTION OUTPUT ;
    USE SIGNAL ;
    PORT
      LAYER M4 ;
        RECT  0 50.688 0.192 50.712 ;
    END
  END o_d[283]
  PIN o_d[284]
    DIRECTION OUTPUT ;
    USE SIGNAL ;
    PORT
      LAYER M4 ;
        RECT  0 50.832 0.192 50.856 ;
    END
  END o_d[284]
  PIN o_d[285]
    DIRECTION OUTPUT ;
    USE SIGNAL ;
    PORT
      LAYER M4 ;
        RECT  0 51.12 0.192 51.144 ;
    END
  END o_d[285]
  PIN o_d[286]
    DIRECTION OUTPUT ;
    USE SIGNAL ;
    PORT
      LAYER M4 ;
        RECT  0 51.264 0.192 51.288 ;
    END
  END o_d[286]
  PIN o_d[287]
    DIRECTION OUTPUT ;
    USE SIGNAL ;
    PORT
      LAYER M4 ;
        RECT  0 51.408 0.192 51.432 ;
    END
  END o_d[287]
  PIN o_d[288]
    DIRECTION OUTPUT ;
    USE SIGNAL ;
    PORT
      LAYER M4 ;
        RECT  0 51.552 0.192 51.576 ;
    END
  END o_d[288]
  PIN o_d[289]
    DIRECTION OUTPUT ;
    USE SIGNAL ;
    PORT
      LAYER M4 ;
        RECT  0 51.696 0.192 51.72 ;
    END
  END o_d[289]
  PIN o_d[28]
    DIRECTION OUTPUT ;
    USE SIGNAL ;
    PORT
      LAYER M4 ;
        RECT  0 8.928 0.192 8.952 ;
    END
  END o_d[28]
  PIN o_d[290]
    DIRECTION OUTPUT ;
    USE SIGNAL ;
    PORT
      LAYER M4 ;
        RECT  0 51.84 0.192 51.864 ;
    END
  END o_d[290]
  PIN o_d[291]
    DIRECTION OUTPUT ;
    USE SIGNAL ;
    PORT
      LAYER M4 ;
        RECT  0 51.984 0.192 52.008 ;
    END
  END o_d[291]
  PIN o_d[292]
    DIRECTION OUTPUT ;
    USE SIGNAL ;
    PORT
      LAYER M4 ;
        RECT  0 52.272 0.192 52.296 ;
    END
  END o_d[292]
  PIN o_d[293]
    DIRECTION OUTPUT ;
    USE SIGNAL ;
    PORT
      LAYER M4 ;
        RECT  0 52.416 0.192 52.44 ;
    END
  END o_d[293]
  PIN o_d[294]
    DIRECTION OUTPUT ;
    USE SIGNAL ;
    PORT
      LAYER M4 ;
        RECT  0 52.56 0.192 52.584 ;
    END
  END o_d[294]
  PIN o_d[295]
    DIRECTION OUTPUT ;
    USE SIGNAL ;
    PORT
      LAYER M4 ;
        RECT  0 52.704 0.192 52.728 ;
    END
  END o_d[295]
  PIN o_d[296]
    DIRECTION OUTPUT ;
    USE SIGNAL ;
    PORT
      LAYER M4 ;
        RECT  0 52.848 0.192 52.872 ;
    END
  END o_d[296]
  PIN o_d[297]
    DIRECTION OUTPUT ;
    USE SIGNAL ;
    PORT
      LAYER M4 ;
        RECT  0 52.992 0.192 53.016 ;
    END
  END o_d[297]
  PIN o_d[298]
    DIRECTION OUTPUT ;
    USE SIGNAL ;
    PORT
      LAYER M4 ;
        RECT  0 53.136 0.192 53.16 ;
    END
  END o_d[298]
  PIN o_d[299]
    DIRECTION OUTPUT ;
    USE SIGNAL ;
    PORT
      LAYER M4 ;
        RECT  0 53.28 0.192 53.304 ;
    END
  END o_d[299]
  PIN o_d[29]
    DIRECTION OUTPUT ;
    USE SIGNAL ;
    PORT
      LAYER M4 ;
        RECT  0 9.072 0.192 9.096 ;
    END
  END o_d[29]
  PIN o_d[2]
    DIRECTION OUTPUT ;
    USE SIGNAL ;
    PORT
      LAYER M4 ;
        RECT  0 4.608 0.192 4.632 ;
    END
  END o_d[2]
  PIN o_d[300]
    DIRECTION OUTPUT ;
    USE SIGNAL ;
    PORT
      LAYER M4 ;
        RECT  0 53.568 0.192 53.592 ;
    END
  END o_d[300]
  PIN o_d[301]
    DIRECTION OUTPUT ;
    USE SIGNAL ;
    PORT
      LAYER M4 ;
        RECT  0 53.712 0.192 53.736 ;
    END
  END o_d[301]
  PIN o_d[302]
    DIRECTION OUTPUT ;
    USE SIGNAL ;
    PORT
      LAYER M4 ;
        RECT  0 53.856 0.192 53.88 ;
    END
  END o_d[302]
  PIN o_d[303]
    DIRECTION OUTPUT ;
    USE SIGNAL ;
    PORT
      LAYER M4 ;
        RECT  0 54 0.192 54.024 ;
    END
  END o_d[303]
  PIN o_d[304]
    DIRECTION OUTPUT ;
    USE SIGNAL ;
    PORT
      LAYER M4 ;
        RECT  0 54.144 0.192 54.168 ;
    END
  END o_d[304]
  PIN o_d[305]
    DIRECTION OUTPUT ;
    USE SIGNAL ;
    PORT
      LAYER M4 ;
        RECT  0 54.288 0.192 54.312 ;
    END
  END o_d[305]
  PIN o_d[306]
    DIRECTION OUTPUT ;
    USE SIGNAL ;
    PORT
      LAYER M4 ;
        RECT  0 54.432 0.192 54.456 ;
    END
  END o_d[306]
  PIN o_d[307]
    DIRECTION OUTPUT ;
    USE SIGNAL ;
    PORT
      LAYER M4 ;
        RECT  0 54.72 0.192 54.744 ;
    END
  END o_d[307]
  PIN o_d[308]
    DIRECTION OUTPUT ;
    USE SIGNAL ;
    PORT
      LAYER M4 ;
        RECT  0 54.864 0.192 54.888 ;
    END
  END o_d[308]
  PIN o_d[309]
    DIRECTION OUTPUT ;
    USE SIGNAL ;
    PORT
      LAYER M4 ;
        RECT  0 55.008 0.192 55.032 ;
    END
  END o_d[309]
  PIN o_d[30]
    DIRECTION OUTPUT ;
    USE SIGNAL ;
    PORT
      LAYER M4 ;
        RECT  0 9.216 0.192 9.24 ;
    END
  END o_d[30]
  PIN o_d[310]
    DIRECTION OUTPUT ;
    USE SIGNAL ;
    PORT
      LAYER M4 ;
        RECT  0 55.152 0.192 55.176 ;
    END
  END o_d[310]
  PIN o_d[311]
    DIRECTION OUTPUT ;
    USE SIGNAL ;
    PORT
      LAYER M4 ;
        RECT  0 55.296 0.192 55.32 ;
    END
  END o_d[311]
  PIN o_d[312]
    DIRECTION OUTPUT ;
    USE SIGNAL ;
    PORT
      LAYER M4 ;
        RECT  0 55.44 0.192 55.464 ;
    END
  END o_d[312]
  PIN o_d[313]
    DIRECTION OUTPUT ;
    USE SIGNAL ;
    PORT
      LAYER M4 ;
        RECT  0 55.584 0.192 55.608 ;
    END
  END o_d[313]
  PIN o_d[314]
    DIRECTION OUTPUT ;
    USE SIGNAL ;
    PORT
      LAYER M4 ;
        RECT  0 55.872 0.192 55.896 ;
    END
  END o_d[314]
  PIN o_d[315]
    DIRECTION OUTPUT ;
    USE SIGNAL ;
    PORT
      LAYER M4 ;
        RECT  0 56.016 0.192 56.04 ;
    END
  END o_d[315]
  PIN o_d[316]
    DIRECTION OUTPUT ;
    USE SIGNAL ;
    PORT
      LAYER M4 ;
        RECT  0 56.16 0.192 56.184 ;
    END
  END o_d[316]
  PIN o_d[317]
    DIRECTION OUTPUT ;
    USE SIGNAL ;
    PORT
      LAYER M4 ;
        RECT  0 56.304 0.192 56.328 ;
    END
  END o_d[317]
  PIN o_d[318]
    DIRECTION OUTPUT ;
    USE SIGNAL ;
    PORT
      LAYER M4 ;
        RECT  0 56.448 0.192 56.472 ;
    END
  END o_d[318]
  PIN o_d[319]
    DIRECTION OUTPUT ;
    USE SIGNAL ;
    PORT
      LAYER M4 ;
        RECT  0 56.592 0.192 56.616 ;
    END
  END o_d[319]
  PIN o_d[31]
    DIRECTION OUTPUT ;
    USE SIGNAL ;
    PORT
      LAYER M4 ;
        RECT  0 9.36 0.192 9.384 ;
    END
  END o_d[31]
  PIN o_d[320]
    DIRECTION OUTPUT ;
    USE SIGNAL ;
    PORT
      LAYER M4 ;
        RECT  0 56.736 0.192 56.76 ;
    END
  END o_d[320]
  PIN o_d[321]
    DIRECTION OUTPUT ;
    USE SIGNAL ;
    PORT
      LAYER M4 ;
        RECT  0 57.024 0.192 57.048 ;
    END
  END o_d[321]
  PIN o_d[322]
    DIRECTION OUTPUT ;
    USE SIGNAL ;
    PORT
      LAYER M4 ;
        RECT  0 57.168 0.192 57.192 ;
    END
  END o_d[322]
  PIN o_d[323]
    DIRECTION OUTPUT ;
    USE SIGNAL ;
    PORT
      LAYER M4 ;
        RECT  0 57.312 0.192 57.336 ;
    END
  END o_d[323]
  PIN o_d[324]
    DIRECTION OUTPUT ;
    USE SIGNAL ;
    PORT
      LAYER M4 ;
        RECT  0 57.456 0.192 57.48 ;
    END
  END o_d[324]
  PIN o_d[325]
    DIRECTION OUTPUT ;
    USE SIGNAL ;
    PORT
      LAYER M4 ;
        RECT  0 57.6 0.192 57.624 ;
    END
  END o_d[325]
  PIN o_d[326]
    DIRECTION OUTPUT ;
    USE SIGNAL ;
    PORT
      LAYER M4 ;
        RECT  0 57.744 0.192 57.768 ;
    END
  END o_d[326]
  PIN o_d[327]
    DIRECTION OUTPUT ;
    USE SIGNAL ;
    PORT
      LAYER M4 ;
        RECT  0 57.888 0.192 57.912 ;
    END
  END o_d[327]
  PIN o_d[328]
    DIRECTION OUTPUT ;
    USE SIGNAL ;
    PORT
      LAYER M4 ;
        RECT  0 58.176 0.192 58.2 ;
    END
  END o_d[328]
  PIN o_d[329]
    DIRECTION OUTPUT ;
    USE SIGNAL ;
    PORT
      LAYER M4 ;
        RECT  0 58.32 0.192 58.344 ;
    END
  END o_d[329]
  PIN o_d[32]
    DIRECTION OUTPUT ;
    USE SIGNAL ;
    PORT
      LAYER M4 ;
        RECT  0 9.648 0.192 9.672 ;
    END
  END o_d[32]
  PIN o_d[330]
    DIRECTION OUTPUT ;
    USE SIGNAL ;
    PORT
      LAYER M4 ;
        RECT  0 58.464 0.192 58.488 ;
    END
  END o_d[330]
  PIN o_d[331]
    DIRECTION OUTPUT ;
    USE SIGNAL ;
    PORT
      LAYER M4 ;
        RECT  0 58.608 0.192 58.632 ;
    END
  END o_d[331]
  PIN o_d[332]
    DIRECTION OUTPUT ;
    USE SIGNAL ;
    PORT
      LAYER M4 ;
        RECT  0 58.752 0.192 58.776 ;
    END
  END o_d[332]
  PIN o_d[333]
    DIRECTION OUTPUT ;
    USE SIGNAL ;
    PORT
      LAYER M4 ;
        RECT  0 58.896 0.192 58.92 ;
    END
  END o_d[333]
  PIN o_d[334]
    DIRECTION OUTPUT ;
    USE SIGNAL ;
    PORT
      LAYER M4 ;
        RECT  0 59.04 0.192 59.064 ;
    END
  END o_d[334]
  PIN o_d[335]
    DIRECTION OUTPUT ;
    USE SIGNAL ;
    PORT
      LAYER M4 ;
        RECT  0 59.184 0.192 59.208 ;
    END
  END o_d[335]
  PIN o_d[336]
    DIRECTION OUTPUT ;
    USE SIGNAL ;
    PORT
      LAYER M4 ;
        RECT  0 59.472 0.192 59.496 ;
    END
  END o_d[336]
  PIN o_d[337]
    DIRECTION OUTPUT ;
    USE SIGNAL ;
    PORT
      LAYER M4 ;
        RECT  0 59.616 0.192 59.64 ;
    END
  END o_d[337]
  PIN o_d[338]
    DIRECTION OUTPUT ;
    USE SIGNAL ;
    PORT
      LAYER M4 ;
        RECT  0 59.76 0.192 59.784 ;
    END
  END o_d[338]
  PIN o_d[339]
    DIRECTION OUTPUT ;
    USE SIGNAL ;
    PORT
      LAYER M4 ;
        RECT  0 59.904 0.192 59.928 ;
    END
  END o_d[339]
  PIN o_d[33]
    DIRECTION OUTPUT ;
    USE SIGNAL ;
    PORT
      LAYER M4 ;
        RECT  0 9.792 0.192 9.816 ;
    END
  END o_d[33]
  PIN o_d[340]
    DIRECTION OUTPUT ;
    USE SIGNAL ;
    PORT
      LAYER M4 ;
        RECT  0 60.048 0.192 60.072 ;
    END
  END o_d[340]
  PIN o_d[341]
    DIRECTION OUTPUT ;
    USE SIGNAL ;
    PORT
      LAYER M4 ;
        RECT  0 60.192 0.192 60.216 ;
    END
  END o_d[341]
  PIN o_d[342]
    DIRECTION OUTPUT ;
    USE SIGNAL ;
    PORT
      LAYER M4 ;
        RECT  0 60.336 0.192 60.36 ;
    END
  END o_d[342]
  PIN o_d[343]
    DIRECTION OUTPUT ;
    USE SIGNAL ;
    PORT
      LAYER M4 ;
        RECT  0 60.624 0.192 60.648 ;
    END
  END o_d[343]
  PIN o_d[344]
    DIRECTION OUTPUT ;
    USE SIGNAL ;
    PORT
      LAYER M4 ;
        RECT  0 60.768 0.192 60.792 ;
    END
  END o_d[344]
  PIN o_d[345]
    DIRECTION OUTPUT ;
    USE SIGNAL ;
    PORT
      LAYER M4 ;
        RECT  0 60.912 0.192 60.936 ;
    END
  END o_d[345]
  PIN o_d[346]
    DIRECTION OUTPUT ;
    USE SIGNAL ;
    PORT
      LAYER M4 ;
        RECT  0 61.056 0.192 61.08 ;
    END
  END o_d[346]
  PIN o_d[347]
    DIRECTION OUTPUT ;
    USE SIGNAL ;
    PORT
      LAYER M4 ;
        RECT  0 61.2 0.192 61.224 ;
    END
  END o_d[347]
  PIN o_d[348]
    DIRECTION OUTPUT ;
    USE SIGNAL ;
    PORT
      LAYER M4 ;
        RECT  0 61.344 0.192 61.368 ;
    END
  END o_d[348]
  PIN o_d[349]
    DIRECTION OUTPUT ;
    USE SIGNAL ;
    PORT
      LAYER M4 ;
        RECT  0 61.488 0.192 61.512 ;
    END
  END o_d[349]
  PIN o_d[34]
    DIRECTION OUTPUT ;
    USE SIGNAL ;
    PORT
      LAYER M4 ;
        RECT  0 9.936 0.192 9.96 ;
    END
  END o_d[34]
  PIN o_d[350]
    DIRECTION OUTPUT ;
    USE SIGNAL ;
    PORT
      LAYER M4 ;
        RECT  0 61.776 0.192 61.8 ;
    END
  END o_d[350]
  PIN o_d[351]
    DIRECTION OUTPUT ;
    USE SIGNAL ;
    PORT
      LAYER M4 ;
        RECT  0 61.92 0.192 61.944 ;
    END
  END o_d[351]
  PIN o_d[352]
    DIRECTION OUTPUT ;
    USE SIGNAL ;
    PORT
      LAYER M4 ;
        RECT  0 62.064 0.192 62.088 ;
    END
  END o_d[352]
  PIN o_d[353]
    DIRECTION OUTPUT ;
    USE SIGNAL ;
    PORT
      LAYER M4 ;
        RECT  0 62.208 0.192 62.232 ;
    END
  END o_d[353]
  PIN o_d[354]
    DIRECTION OUTPUT ;
    USE SIGNAL ;
    PORT
      LAYER M4 ;
        RECT  0 62.352 0.192 62.376 ;
    END
  END o_d[354]
  PIN o_d[355]
    DIRECTION OUTPUT ;
    USE SIGNAL ;
    PORT
      LAYER M4 ;
        RECT  0 62.496 0.192 62.52 ;
    END
  END o_d[355]
  PIN o_d[356]
    DIRECTION OUTPUT ;
    USE SIGNAL ;
    PORT
      LAYER M4 ;
        RECT  0 62.64 0.192 62.664 ;
    END
  END o_d[356]
  PIN o_d[357]
    DIRECTION OUTPUT ;
    USE SIGNAL ;
    PORT
      LAYER M4 ;
        RECT  0 62.928 0.192 62.952 ;
    END
  END o_d[357]
  PIN o_d[358]
    DIRECTION OUTPUT ;
    USE SIGNAL ;
    PORT
      LAYER M4 ;
        RECT  0 63.072 0.192 63.096 ;
    END
  END o_d[358]
  PIN o_d[359]
    DIRECTION OUTPUT ;
    USE SIGNAL ;
    PORT
      LAYER M4 ;
        RECT  0 63.216 0.192 63.24 ;
    END
  END o_d[359]
  PIN o_d[35]
    DIRECTION OUTPUT ;
    USE SIGNAL ;
    PORT
      LAYER M4 ;
        RECT  0 10.08 0.192 10.104 ;
    END
  END o_d[35]
  PIN o_d[360]
    DIRECTION OUTPUT ;
    USE SIGNAL ;
    PORT
      LAYER M4 ;
        RECT  0 63.36 0.192 63.384 ;
    END
  END o_d[360]
  PIN o_d[361]
    DIRECTION OUTPUT ;
    USE SIGNAL ;
    PORT
      LAYER M4 ;
        RECT  0 63.504 0.192 63.528 ;
    END
  END o_d[361]
  PIN o_d[362]
    DIRECTION OUTPUT ;
    USE SIGNAL ;
    PORT
      LAYER M4 ;
        RECT  0 63.648 0.192 63.672 ;
    END
  END o_d[362]
  PIN o_d[363]
    DIRECTION OUTPUT ;
    USE SIGNAL ;
    PORT
      LAYER M4 ;
        RECT  0 63.792 0.192 63.816 ;
    END
  END o_d[363]
  PIN o_d[364]
    DIRECTION OUTPUT ;
    USE SIGNAL ;
    PORT
      LAYER M4 ;
        RECT  0 63.936 0.192 63.96 ;
    END
  END o_d[364]
  PIN o_d[365]
    DIRECTION OUTPUT ;
    USE SIGNAL ;
    PORT
      LAYER M4 ;
        RECT  0 64.224 0.192 64.248 ;
    END
  END o_d[365]
  PIN o_d[366]
    DIRECTION OUTPUT ;
    USE SIGNAL ;
    PORT
      LAYER M4 ;
        RECT  0 64.368 0.192 64.392 ;
    END
  END o_d[366]
  PIN o_d[367]
    DIRECTION OUTPUT ;
    USE SIGNAL ;
    PORT
      LAYER M4 ;
        RECT  0 64.512 0.192 64.536 ;
    END
  END o_d[367]
  PIN o_d[368]
    DIRECTION OUTPUT ;
    USE SIGNAL ;
    PORT
      LAYER M4 ;
        RECT  0 64.656 0.192 64.68 ;
    END
  END o_d[368]
  PIN o_d[369]
    DIRECTION OUTPUT ;
    USE SIGNAL ;
    PORT
      LAYER M4 ;
        RECT  0 64.8 0.192 64.824 ;
    END
  END o_d[369]
  PIN o_d[36]
    DIRECTION OUTPUT ;
    USE SIGNAL ;
    PORT
      LAYER M4 ;
        RECT  0 10.224 0.192 10.248 ;
    END
  END o_d[36]
  PIN o_d[370]
    DIRECTION OUTPUT ;
    USE SIGNAL ;
    PORT
      LAYER M4 ;
        RECT  0 64.944 0.192 64.968 ;
    END
  END o_d[370]
  PIN o_d[371]
    DIRECTION OUTPUT ;
    USE SIGNAL ;
    PORT
      LAYER M4 ;
        RECT  0 65.088 0.192 65.112 ;
    END
  END o_d[371]
  PIN o_d[372]
    DIRECTION OUTPUT ;
    USE SIGNAL ;
    PORT
      LAYER M4 ;
        RECT  0 65.376 0.192 65.4 ;
    END
  END o_d[372]
  PIN o_d[373]
    DIRECTION OUTPUT ;
    USE SIGNAL ;
    PORT
      LAYER M4 ;
        RECT  0 65.52 0.192 65.544 ;
    END
  END o_d[373]
  PIN o_d[374]
    DIRECTION OUTPUT ;
    USE SIGNAL ;
    PORT
      LAYER M4 ;
        RECT  0 65.664 0.192 65.688 ;
    END
  END o_d[374]
  PIN o_d[375]
    DIRECTION OUTPUT ;
    USE SIGNAL ;
    PORT
      LAYER M4 ;
        RECT  0 65.808 0.192 65.832 ;
    END
  END o_d[375]
  PIN o_d[376]
    DIRECTION OUTPUT ;
    USE SIGNAL ;
    PORT
      LAYER M4 ;
        RECT  0 65.952 0.192 65.976 ;
    END
  END o_d[376]
  PIN o_d[377]
    DIRECTION OUTPUT ;
    USE SIGNAL ;
    PORT
      LAYER M4 ;
        RECT  0 66.096 0.192 66.12 ;
    END
  END o_d[377]
  PIN o_d[378]
    DIRECTION OUTPUT ;
    USE SIGNAL ;
    PORT
      LAYER M4 ;
        RECT  0 66.24 0.192 66.264 ;
    END
  END o_d[378]
  PIN o_d[379]
    DIRECTION OUTPUT ;
    USE SIGNAL ;
    PORT
      LAYER M4 ;
        RECT  0 66.528 0.192 66.552 ;
    END
  END o_d[379]
  PIN o_d[37]
    DIRECTION OUTPUT ;
    USE SIGNAL ;
    PORT
      LAYER M4 ;
        RECT  0 10.368 0.192 10.392 ;
    END
  END o_d[37]
  PIN o_d[380]
    DIRECTION OUTPUT ;
    USE SIGNAL ;
    PORT
      LAYER M4 ;
        RECT  0 66.672 0.192 66.696 ;
    END
  END o_d[380]
  PIN o_d[381]
    DIRECTION OUTPUT ;
    USE SIGNAL ;
    PORT
      LAYER M4 ;
        RECT  0 66.816 0.192 66.84 ;
    END
  END o_d[381]
  PIN o_d[382]
    DIRECTION OUTPUT ;
    USE SIGNAL ;
    PORT
      LAYER M4 ;
        RECT  0 66.96 0.192 66.984 ;
    END
  END o_d[382]
  PIN o_d[383]
    DIRECTION OUTPUT ;
    USE SIGNAL ;
    PORT
      LAYER M4 ;
        RECT  0 67.104 0.192 67.128 ;
    END
  END o_d[383]
  PIN o_d[384]
    DIRECTION OUTPUT ;
    USE SIGNAL ;
    PORT
      LAYER M4 ;
        RECT  0 67.248 0.192 67.272 ;
    END
  END o_d[384]
  PIN o_d[385]
    DIRECTION OUTPUT ;
    USE SIGNAL ;
    PORT
      LAYER M4 ;
        RECT  0 67.392 0.192 67.416 ;
    END
  END o_d[385]
  PIN o_d[386]
    DIRECTION OUTPUT ;
    USE SIGNAL ;
    PORT
      LAYER M4 ;
        RECT  0 67.68 0.192 67.704 ;
    END
  END o_d[386]
  PIN o_d[387]
    DIRECTION OUTPUT ;
    USE SIGNAL ;
    PORT
      LAYER M4 ;
        RECT  0 67.824 0.192 67.848 ;
    END
  END o_d[387]
  PIN o_d[388]
    DIRECTION OUTPUT ;
    USE SIGNAL ;
    PORT
      LAYER M4 ;
        RECT  0 67.968 0.192 67.992 ;
    END
  END o_d[388]
  PIN o_d[389]
    DIRECTION OUTPUT ;
    USE SIGNAL ;
    PORT
      LAYER M4 ;
        RECT  0 68.112 0.192 68.136 ;
    END
  END o_d[389]
  PIN o_d[38]
    DIRECTION OUTPUT ;
    USE SIGNAL ;
    PORT
      LAYER M4 ;
        RECT  0 10.512 0.192 10.536 ;
    END
  END o_d[38]
  PIN o_d[390]
    DIRECTION OUTPUT ;
    USE SIGNAL ;
    PORT
      LAYER M4 ;
        RECT  0 68.256 0.192 68.28 ;
    END
  END o_d[390]
  PIN o_d[391]
    DIRECTION OUTPUT ;
    USE SIGNAL ;
    PORT
      LAYER M4 ;
        RECT  0 68.4 0.192 68.424 ;
    END
  END o_d[391]
  PIN o_d[392]
    DIRECTION OUTPUT ;
    USE SIGNAL ;
    PORT
      LAYER M4 ;
        RECT  0 68.544 0.192 68.568 ;
    END
  END o_d[392]
  PIN o_d[393]
    DIRECTION OUTPUT ;
    USE SIGNAL ;
    PORT
      LAYER M4 ;
        RECT  0 68.832 0.192 68.856 ;
    END
  END o_d[393]
  PIN o_d[394]
    DIRECTION OUTPUT ;
    USE SIGNAL ;
    PORT
      LAYER M4 ;
        RECT  0 68.976 0.192 69 ;
    END
  END o_d[394]
  PIN o_d[395]
    DIRECTION OUTPUT ;
    USE SIGNAL ;
    PORT
      LAYER M4 ;
        RECT  0 69.12 0.192 69.144 ;
    END
  END o_d[395]
  PIN o_d[396]
    DIRECTION OUTPUT ;
    USE SIGNAL ;
    PORT
      LAYER M4 ;
        RECT  0 69.264 0.192 69.288 ;
    END
  END o_d[396]
  PIN o_d[397]
    DIRECTION OUTPUT ;
    USE SIGNAL ;
    PORT
      LAYER M4 ;
        RECT  0 69.408 0.192 69.432 ;
    END
  END o_d[397]
  PIN o_d[398]
    DIRECTION OUTPUT ;
    USE SIGNAL ;
    PORT
      LAYER M4 ;
        RECT  0 69.552 0.192 69.576 ;
    END
  END o_d[398]
  PIN o_d[399]
    DIRECTION OUTPUT ;
    USE SIGNAL ;
    PORT
      LAYER M4 ;
        RECT  0 69.696 0.192 69.72 ;
    END
  END o_d[399]
  PIN o_d[39]
    DIRECTION OUTPUT ;
    USE SIGNAL ;
    PORT
      LAYER M4 ;
        RECT  0 10.656 0.192 10.68 ;
    END
  END o_d[39]
  PIN o_d[3]
    DIRECTION OUTPUT ;
    USE SIGNAL ;
    PORT
      LAYER M4 ;
        RECT  0 4.752 0.192 4.776 ;
    END
  END o_d[3]
  PIN o_d[400]
    DIRECTION OUTPUT ;
    USE SIGNAL ;
    PORT
      LAYER M4 ;
        RECT  0 69.84 0.192 69.864 ;
    END
  END o_d[400]
  PIN o_d[401]
    DIRECTION OUTPUT ;
    USE SIGNAL ;
    PORT
      LAYER M4 ;
        RECT  0 70.128 0.192 70.152 ;
    END
  END o_d[401]
  PIN o_d[402]
    DIRECTION OUTPUT ;
    USE SIGNAL ;
    PORT
      LAYER M4 ;
        RECT  0 70.272 0.192 70.296 ;
    END
  END o_d[402]
  PIN o_d[403]
    DIRECTION OUTPUT ;
    USE SIGNAL ;
    PORT
      LAYER M4 ;
        RECT  0 70.416 0.192 70.44 ;
    END
  END o_d[403]
  PIN o_d[404]
    DIRECTION OUTPUT ;
    USE SIGNAL ;
    PORT
      LAYER M4 ;
        RECT  0 70.56 0.192 70.584 ;
    END
  END o_d[404]
  PIN o_d[405]
    DIRECTION OUTPUT ;
    USE SIGNAL ;
    PORT
      LAYER M4 ;
        RECT  0 70.704 0.192 70.728 ;
    END
  END o_d[405]
  PIN o_d[406]
    DIRECTION OUTPUT ;
    USE SIGNAL ;
    PORT
      LAYER M4 ;
        RECT  0 70.848 0.192 70.872 ;
    END
  END o_d[406]
  PIN o_d[407]
    DIRECTION OUTPUT ;
    USE SIGNAL ;
    PORT
      LAYER M4 ;
        RECT  0 70.992 0.192 71.016 ;
    END
  END o_d[407]
  PIN o_d[408]
    DIRECTION OUTPUT ;
    USE SIGNAL ;
    PORT
      LAYER M4 ;
        RECT  0 71.28 0.192 71.304 ;
    END
  END o_d[408]
  PIN o_d[409]
    DIRECTION OUTPUT ;
    USE SIGNAL ;
    PORT
      LAYER M4 ;
        RECT  0 71.424 0.192 71.448 ;
    END
  END o_d[409]
  PIN o_d[40]
    DIRECTION OUTPUT ;
    USE SIGNAL ;
    PORT
      LAYER M4 ;
        RECT  0 10.944 0.192 10.968 ;
    END
  END o_d[40]
  PIN o_d[410]
    DIRECTION OUTPUT ;
    USE SIGNAL ;
    PORT
      LAYER M4 ;
        RECT  0 71.568 0.192 71.592 ;
    END
  END o_d[410]
  PIN o_d[411]
    DIRECTION OUTPUT ;
    USE SIGNAL ;
    PORT
      LAYER M4 ;
        RECT  0 71.712 0.192 71.736 ;
    END
  END o_d[411]
  PIN o_d[412]
    DIRECTION OUTPUT ;
    USE SIGNAL ;
    PORT
      LAYER M4 ;
        RECT  0 71.856 0.192 71.88 ;
    END
  END o_d[412]
  PIN o_d[413]
    DIRECTION OUTPUT ;
    USE SIGNAL ;
    PORT
      LAYER M4 ;
        RECT  0 72 0.192 72.024 ;
    END
  END o_d[413]
  PIN o_d[414]
    DIRECTION OUTPUT ;
    USE SIGNAL ;
    PORT
      LAYER M4 ;
        RECT  0 72.144 0.192 72.168 ;
    END
  END o_d[414]
  PIN o_d[415]
    DIRECTION OUTPUT ;
    USE SIGNAL ;
    PORT
      LAYER M4 ;
        RECT  0 72.432 0.192 72.456 ;
    END
  END o_d[415]
  PIN o_d[416]
    DIRECTION OUTPUT ;
    USE SIGNAL ;
    PORT
      LAYER M4 ;
        RECT  0 72.576 0.192 72.6 ;
    END
  END o_d[416]
  PIN o_d[417]
    DIRECTION OUTPUT ;
    USE SIGNAL ;
    PORT
      LAYER M4 ;
        RECT  0 72.72 0.192 72.744 ;
    END
  END o_d[417]
  PIN o_d[418]
    DIRECTION OUTPUT ;
    USE SIGNAL ;
    PORT
      LAYER M4 ;
        RECT  0 72.864 0.192 72.888 ;
    END
  END o_d[418]
  PIN o_d[419]
    DIRECTION OUTPUT ;
    USE SIGNAL ;
    PORT
      LAYER M4 ;
        RECT  0 73.008 0.192 73.032 ;
    END
  END o_d[419]
  PIN o_d[41]
    DIRECTION OUTPUT ;
    USE SIGNAL ;
    PORT
      LAYER M4 ;
        RECT  0 11.088 0.192 11.112 ;
    END
  END o_d[41]
  PIN o_d[420]
    DIRECTION OUTPUT ;
    USE SIGNAL ;
    PORT
      LAYER M4 ;
        RECT  0 73.152 0.192 73.176 ;
    END
  END o_d[420]
  PIN o_d[421]
    DIRECTION OUTPUT ;
    USE SIGNAL ;
    PORT
      LAYER M4 ;
        RECT  0 73.296 0.192 73.32 ;
    END
  END o_d[421]
  PIN o_d[422]
    DIRECTION OUTPUT ;
    USE SIGNAL ;
    PORT
      LAYER M4 ;
        RECT  0 73.584 0.192 73.608 ;
    END
  END o_d[422]
  PIN o_d[423]
    DIRECTION OUTPUT ;
    USE SIGNAL ;
    PORT
      LAYER M4 ;
        RECT  0 73.728 0.192 73.752 ;
    END
  END o_d[423]
  PIN o_d[424]
    DIRECTION OUTPUT ;
    USE SIGNAL ;
    PORT
      LAYER M4 ;
        RECT  0 73.872 0.192 73.896 ;
    END
  END o_d[424]
  PIN o_d[425]
    DIRECTION OUTPUT ;
    USE SIGNAL ;
    PORT
      LAYER M4 ;
        RECT  0 74.016 0.192 74.04 ;
    END
  END o_d[425]
  PIN o_d[426]
    DIRECTION OUTPUT ;
    USE SIGNAL ;
    PORT
      LAYER M4 ;
        RECT  0 74.16 0.192 74.184 ;
    END
  END o_d[426]
  PIN o_d[427]
    DIRECTION OUTPUT ;
    USE SIGNAL ;
    PORT
      LAYER M4 ;
        RECT  0 74.304 0.192 74.328 ;
    END
  END o_d[427]
  PIN o_d[428]
    DIRECTION OUTPUT ;
    USE SIGNAL ;
    PORT
      LAYER M4 ;
        RECT  0 74.448 0.192 74.472 ;
    END
  END o_d[428]
  PIN o_d[429]
    DIRECTION OUTPUT ;
    USE SIGNAL ;
    PORT
      LAYER M4 ;
        RECT  0 74.592 0.192 74.616 ;
    END
  END o_d[429]
  PIN o_d[42]
    DIRECTION OUTPUT ;
    USE SIGNAL ;
    PORT
      LAYER M4 ;
        RECT  0 11.232 0.192 11.256 ;
    END
  END o_d[42]
  PIN o_d[430]
    DIRECTION OUTPUT ;
    USE SIGNAL ;
    PORT
      LAYER M4 ;
        RECT  0 74.88 0.192 74.904 ;
    END
  END o_d[430]
  PIN o_d[431]
    DIRECTION OUTPUT ;
    USE SIGNAL ;
    PORT
      LAYER M4 ;
        RECT  0 75.024 0.192 75.048 ;
    END
  END o_d[431]
  PIN o_d[432]
    DIRECTION OUTPUT ;
    USE SIGNAL ;
    PORT
      LAYER M4 ;
        RECT  0 75.168 0.192 75.192 ;
    END
  END o_d[432]
  PIN o_d[433]
    DIRECTION OUTPUT ;
    USE SIGNAL ;
    PORT
      LAYER M4 ;
        RECT  0 75.312 0.192 75.336 ;
    END
  END o_d[433]
  PIN o_d[434]
    DIRECTION OUTPUT ;
    USE SIGNAL ;
    PORT
      LAYER M4 ;
        RECT  0 75.456 0.192 75.48 ;
    END
  END o_d[434]
  PIN o_d[435]
    DIRECTION OUTPUT ;
    USE SIGNAL ;
    PORT
      LAYER M4 ;
        RECT  0 75.6 0.192 75.624 ;
    END
  END o_d[435]
  PIN o_d[436]
    DIRECTION OUTPUT ;
    USE SIGNAL ;
    PORT
      LAYER M4 ;
        RECT  0 75.744 0.192 75.768 ;
    END
  END o_d[436]
  PIN o_d[437]
    DIRECTION OUTPUT ;
    USE SIGNAL ;
    PORT
      LAYER M4 ;
        RECT  0 76.032 0.192 76.056 ;
    END
  END o_d[437]
  PIN o_d[438]
    DIRECTION OUTPUT ;
    USE SIGNAL ;
    PORT
      LAYER M4 ;
        RECT  0 76.176 0.192 76.2 ;
    END
  END o_d[438]
  PIN o_d[439]
    DIRECTION OUTPUT ;
    USE SIGNAL ;
    PORT
      LAYER M4 ;
        RECT  0 76.32 0.192 76.344 ;
    END
  END o_d[439]
  PIN o_d[43]
    DIRECTION OUTPUT ;
    USE SIGNAL ;
    PORT
      LAYER M4 ;
        RECT  0 11.376 0.192 11.4 ;
    END
  END o_d[43]
  PIN o_d[440]
    DIRECTION OUTPUT ;
    USE SIGNAL ;
    PORT
      LAYER M4 ;
        RECT  0 76.464 0.192 76.488 ;
    END
  END o_d[440]
  PIN o_d[441]
    DIRECTION OUTPUT ;
    USE SIGNAL ;
    PORT
      LAYER M4 ;
        RECT  0 76.608 0.192 76.632 ;
    END
  END o_d[441]
  PIN o_d[442]
    DIRECTION OUTPUT ;
    USE SIGNAL ;
    PORT
      LAYER M4 ;
        RECT  0 76.752 0.192 76.776 ;
    END
  END o_d[442]
  PIN o_d[443]
    DIRECTION OUTPUT ;
    USE SIGNAL ;
    PORT
      LAYER M4 ;
        RECT  0 76.896 0.192 76.92 ;
    END
  END o_d[443]
  PIN o_d[444]
    DIRECTION OUTPUT ;
    USE SIGNAL ;
    PORT
      LAYER M4 ;
        RECT  0 77.184 0.192 77.208 ;
    END
  END o_d[444]
  PIN o_d[445]
    DIRECTION OUTPUT ;
    USE SIGNAL ;
    PORT
      LAYER M4 ;
        RECT  0 77.328 0.192 77.352 ;
    END
  END o_d[445]
  PIN o_d[446]
    DIRECTION OUTPUT ;
    USE SIGNAL ;
    PORT
      LAYER M4 ;
        RECT  0 77.472 0.192 77.496 ;
    END
  END o_d[446]
  PIN o_d[447]
    DIRECTION OUTPUT ;
    USE SIGNAL ;
    PORT
      LAYER M4 ;
        RECT  0 77.616 0.192 77.64 ;
    END
  END o_d[447]
  PIN o_d[448]
    DIRECTION OUTPUT ;
    USE SIGNAL ;
    PORT
      LAYER M4 ;
        RECT  0 77.76 0.192 77.784 ;
    END
  END o_d[448]
  PIN o_d[449]
    DIRECTION OUTPUT ;
    USE SIGNAL ;
    PORT
      LAYER M4 ;
        RECT  0 77.904 0.192 77.928 ;
    END
  END o_d[449]
  PIN o_d[44]
    DIRECTION OUTPUT ;
    USE SIGNAL ;
    PORT
      LAYER M4 ;
        RECT  0 11.52 0.192 11.544 ;
    END
  END o_d[44]
  PIN o_d[450]
    DIRECTION OUTPUT ;
    USE SIGNAL ;
    PORT
      LAYER M4 ;
        RECT  0 78.048 0.192 78.072 ;
    END
  END o_d[450]
  PIN o_d[451]
    DIRECTION OUTPUT ;
    USE SIGNAL ;
    PORT
      LAYER M4 ;
        RECT  0 78.336 0.192 78.36 ;
    END
  END o_d[451]
  PIN o_d[452]
    DIRECTION OUTPUT ;
    USE SIGNAL ;
    PORT
      LAYER M4 ;
        RECT  0 78.48 0.192 78.504 ;
    END
  END o_d[452]
  PIN o_d[453]
    DIRECTION OUTPUT ;
    USE SIGNAL ;
    PORT
      LAYER M4 ;
        RECT  0 78.624 0.192 78.648 ;
    END
  END o_d[453]
  PIN o_d[454]
    DIRECTION OUTPUT ;
    USE SIGNAL ;
    PORT
      LAYER M4 ;
        RECT  0 78.768 0.192 78.792 ;
    END
  END o_d[454]
  PIN o_d[455]
    DIRECTION OUTPUT ;
    USE SIGNAL ;
    PORT
      LAYER M4 ;
        RECT  0 78.912 0.192 78.936 ;
    END
  END o_d[455]
  PIN o_d[456]
    DIRECTION OUTPUT ;
    USE SIGNAL ;
    PORT
      LAYER M4 ;
        RECT  0 79.056 0.192 79.08 ;
    END
  END o_d[456]
  PIN o_d[457]
    DIRECTION OUTPUT ;
    USE SIGNAL ;
    PORT
      LAYER M4 ;
        RECT  0 79.2 0.192 79.224 ;
    END
  END o_d[457]
  PIN o_d[458]
    DIRECTION OUTPUT ;
    USE SIGNAL ;
    PORT
      LAYER M4 ;
        RECT  0 79.488 0.192 79.512 ;
    END
  END o_d[458]
  PIN o_d[459]
    DIRECTION OUTPUT ;
    USE SIGNAL ;
    PORT
      LAYER M4 ;
        RECT  0 79.632 0.192 79.656 ;
    END
  END o_d[459]
  PIN o_d[45]
    DIRECTION OUTPUT ;
    USE SIGNAL ;
    PORT
      LAYER M4 ;
        RECT  0 11.664 0.192 11.688 ;
    END
  END o_d[45]
  PIN o_d[460]
    DIRECTION OUTPUT ;
    USE SIGNAL ;
    PORT
      LAYER M4 ;
        RECT  0 79.776 0.192 79.8 ;
    END
  END o_d[460]
  PIN o_d[461]
    DIRECTION OUTPUT ;
    USE SIGNAL ;
    PORT
      LAYER M4 ;
        RECT  0 79.92 0.192 79.944 ;
    END
  END o_d[461]
  PIN o_d[462]
    DIRECTION OUTPUT ;
    USE SIGNAL ;
    PORT
      LAYER M4 ;
        RECT  0 80.064 0.192 80.088 ;
    END
  END o_d[462]
  PIN o_d[463]
    DIRECTION OUTPUT ;
    USE SIGNAL ;
    PORT
      LAYER M4 ;
        RECT  0 80.208 0.192 80.232 ;
    END
  END o_d[463]
  PIN o_d[464]
    DIRECTION OUTPUT ;
    USE SIGNAL ;
    PORT
      LAYER M4 ;
        RECT  0 80.352 0.192 80.376 ;
    END
  END o_d[464]
  PIN o_d[465]
    DIRECTION OUTPUT ;
    USE SIGNAL ;
    PORT
      LAYER M4 ;
        RECT  0 80.496 0.192 80.52 ;
    END
  END o_d[465]
  PIN o_d[466]
    DIRECTION OUTPUT ;
    USE SIGNAL ;
    PORT
      LAYER M4 ;
        RECT  0 80.784 0.192 80.808 ;
    END
  END o_d[466]
  PIN o_d[467]
    DIRECTION OUTPUT ;
    USE SIGNAL ;
    PORT
      LAYER M4 ;
        RECT  0 80.928 0.192 80.952 ;
    END
  END o_d[467]
  PIN o_d[468]
    DIRECTION OUTPUT ;
    USE SIGNAL ;
    PORT
      LAYER M4 ;
        RECT  0 81.072 0.192 81.096 ;
    END
  END o_d[468]
  PIN o_d[469]
    DIRECTION OUTPUT ;
    USE SIGNAL ;
    PORT
      LAYER M4 ;
        RECT  0 81.216 0.192 81.24 ;
    END
  END o_d[469]
  PIN o_d[46]
    DIRECTION OUTPUT ;
    USE SIGNAL ;
    PORT
      LAYER M4 ;
        RECT  0 11.808 0.192 11.832 ;
    END
  END o_d[46]
  PIN o_d[470]
    DIRECTION OUTPUT ;
    USE SIGNAL ;
    PORT
      LAYER M4 ;
        RECT  0 81.36 0.192 81.384 ;
    END
  END o_d[470]
  PIN o_d[471]
    DIRECTION OUTPUT ;
    USE SIGNAL ;
    PORT
      LAYER M4 ;
        RECT  0 81.504 0.192 81.528 ;
    END
  END o_d[471]
  PIN o_d[472]
    DIRECTION OUTPUT ;
    USE SIGNAL ;
    PORT
      LAYER M4 ;
        RECT  0 81.648 0.192 81.672 ;
    END
  END o_d[472]
  PIN o_d[473]
    DIRECTION OUTPUT ;
    USE SIGNAL ;
    PORT
      LAYER M4 ;
        RECT  0 81.936 0.192 81.96 ;
    END
  END o_d[473]
  PIN o_d[474]
    DIRECTION OUTPUT ;
    USE SIGNAL ;
    PORT
      LAYER M4 ;
        RECT  0 82.08 0.192 82.104 ;
    END
  END o_d[474]
  PIN o_d[475]
    DIRECTION OUTPUT ;
    USE SIGNAL ;
    PORT
      LAYER M4 ;
        RECT  0 82.224 0.192 82.248 ;
    END
  END o_d[475]
  PIN o_d[476]
    DIRECTION OUTPUT ;
    USE SIGNAL ;
    PORT
      LAYER M4 ;
        RECT  0 82.368 0.192 82.392 ;
    END
  END o_d[476]
  PIN o_d[477]
    DIRECTION OUTPUT ;
    USE SIGNAL ;
    PORT
      LAYER M4 ;
        RECT  0 82.512 0.192 82.536 ;
    END
  END o_d[477]
  PIN o_d[478]
    DIRECTION OUTPUT ;
    USE SIGNAL ;
    PORT
      LAYER M4 ;
        RECT  0 82.656 0.192 82.68 ;
    END
  END o_d[478]
  PIN o_d[479]
    DIRECTION OUTPUT ;
    USE SIGNAL ;
    PORT
      LAYER M4 ;
        RECT  0 82.8 0.192 82.824 ;
    END
  END o_d[479]
  PIN o_d[47]
    DIRECTION OUTPUT ;
    USE SIGNAL ;
    PORT
      LAYER M4 ;
        RECT  0 12.096 0.192 12.12 ;
    END
  END o_d[47]
  PIN o_d[480]
    DIRECTION OUTPUT ;
    USE SIGNAL ;
    PORT
      LAYER M4 ;
        RECT  0 83.088 0.192 83.112 ;
    END
  END o_d[480]
  PIN o_d[481]
    DIRECTION OUTPUT ;
    USE SIGNAL ;
    PORT
      LAYER M4 ;
        RECT  0 83.232 0.192 83.256 ;
    END
  END o_d[481]
  PIN o_d[482]
    DIRECTION OUTPUT ;
    USE SIGNAL ;
    PORT
      LAYER M4 ;
        RECT  0 83.376 0.192 83.4 ;
    END
  END o_d[482]
  PIN o_d[483]
    DIRECTION OUTPUT ;
    USE SIGNAL ;
    PORT
      LAYER M4 ;
        RECT  0 83.52 0.192 83.544 ;
    END
  END o_d[483]
  PIN o_d[484]
    DIRECTION OUTPUT ;
    USE SIGNAL ;
    PORT
      LAYER M4 ;
        RECT  0 83.664 0.192 83.688 ;
    END
  END o_d[484]
  PIN o_d[485]
    DIRECTION OUTPUT ;
    USE SIGNAL ;
    PORT
      LAYER M4 ;
        RECT  0 83.808 0.192 83.832 ;
    END
  END o_d[485]
  PIN o_d[486]
    DIRECTION OUTPUT ;
    USE SIGNAL ;
    PORT
      LAYER M4 ;
        RECT  0 83.952 0.192 83.976 ;
    END
  END o_d[486]
  PIN o_d[487]
    DIRECTION OUTPUT ;
    USE SIGNAL ;
    PORT
      LAYER M4 ;
        RECT  0 84.24 0.192 84.264 ;
    END
  END o_d[487]
  PIN o_d[488]
    DIRECTION OUTPUT ;
    USE SIGNAL ;
    PORT
      LAYER M4 ;
        RECT  0 84.384 0.192 84.408 ;
    END
  END o_d[488]
  PIN o_d[489]
    DIRECTION OUTPUT ;
    USE SIGNAL ;
    PORT
      LAYER M4 ;
        RECT  0 84.528 0.192 84.552 ;
    END
  END o_d[489]
  PIN o_d[48]
    DIRECTION OUTPUT ;
    USE SIGNAL ;
    PORT
      LAYER M4 ;
        RECT  0 12.24 0.192 12.264 ;
    END
  END o_d[48]
  PIN o_d[490]
    DIRECTION OUTPUT ;
    USE SIGNAL ;
    PORT
      LAYER M4 ;
        RECT  0 84.672 0.192 84.696 ;
    END
  END o_d[490]
  PIN o_d[491]
    DIRECTION OUTPUT ;
    USE SIGNAL ;
    PORT
      LAYER M4 ;
        RECT  0 84.816 0.192 84.84 ;
    END
  END o_d[491]
  PIN o_d[492]
    DIRECTION OUTPUT ;
    USE SIGNAL ;
    PORT
      LAYER M4 ;
        RECT  0 84.96 0.192 84.984 ;
    END
  END o_d[492]
  PIN o_d[493]
    DIRECTION OUTPUT ;
    USE SIGNAL ;
    PORT
      LAYER M4 ;
        RECT  0 85.104 0.192 85.128 ;
    END
  END o_d[493]
  PIN o_d[494]
    DIRECTION OUTPUT ;
    USE SIGNAL ;
    PORT
      LAYER M4 ;
        RECT  0 85.248 0.192 85.272 ;
    END
  END o_d[494]
  PIN o_d[495]
    DIRECTION OUTPUT ;
    USE SIGNAL ;
    PORT
      LAYER M4 ;
        RECT  0 85.536 0.192 85.56 ;
    END
  END o_d[495]
  PIN o_d[496]
    DIRECTION OUTPUT ;
    USE SIGNAL ;
    PORT
      LAYER M4 ;
        RECT  0 85.68 0.192 85.704 ;
    END
  END o_d[496]
  PIN o_d[497]
    DIRECTION OUTPUT ;
    USE SIGNAL ;
    PORT
      LAYER M4 ;
        RECT  0 85.824 0.192 85.848 ;
    END
  END o_d[497]
  PIN o_d[498]
    DIRECTION OUTPUT ;
    USE SIGNAL ;
    PORT
      LAYER M4 ;
        RECT  0 85.968 0.192 85.992 ;
    END
  END o_d[498]
  PIN o_d[499]
    DIRECTION OUTPUT ;
    USE SIGNAL ;
    PORT
      LAYER M4 ;
        RECT  0 86.112 0.192 86.136 ;
    END
  END o_d[499]
  PIN o_d[49]
    DIRECTION OUTPUT ;
    USE SIGNAL ;
    PORT
      LAYER M4 ;
        RECT  0 12.384 0.192 12.408 ;
    END
  END o_d[49]
  PIN o_d[4]
    DIRECTION OUTPUT ;
    USE SIGNAL ;
    PORT
      LAYER M4 ;
        RECT  0 5.04 0.192 5.064 ;
    END
  END o_d[4]
  PIN o_d[500]
    DIRECTION OUTPUT ;
    USE SIGNAL ;
    PORT
      LAYER M4 ;
        RECT  0 86.256 0.192 86.28 ;
    END
  END o_d[500]
  PIN o_d[501]
    DIRECTION OUTPUT ;
    USE SIGNAL ;
    PORT
      LAYER M4 ;
        RECT  0 86.4 0.192 86.424 ;
    END
  END o_d[501]
  PIN o_d[502]
    DIRECTION OUTPUT ;
    USE SIGNAL ;
    PORT
      LAYER M4 ;
        RECT  0 86.688 0.192 86.712 ;
    END
  END o_d[502]
  PIN o_d[503]
    DIRECTION OUTPUT ;
    USE SIGNAL ;
    PORT
      LAYER M4 ;
        RECT  0 86.832 0.192 86.856 ;
    END
  END o_d[503]
  PIN o_d[504]
    DIRECTION OUTPUT ;
    USE SIGNAL ;
    PORT
      LAYER M4 ;
        RECT  0 86.976 0.192 87 ;
    END
  END o_d[504]
  PIN o_d[505]
    DIRECTION OUTPUT ;
    USE SIGNAL ;
    PORT
      LAYER M4 ;
        RECT  0 87.12 0.192 87.144 ;
    END
  END o_d[505]
  PIN o_d[506]
    DIRECTION OUTPUT ;
    USE SIGNAL ;
    PORT
      LAYER M4 ;
        RECT  0 87.264 0.192 87.288 ;
    END
  END o_d[506]
  PIN o_d[507]
    DIRECTION OUTPUT ;
    USE SIGNAL ;
    PORT
      LAYER M4 ;
        RECT  0 87.408 0.192 87.432 ;
    END
  END o_d[507]
  PIN o_d[508]
    DIRECTION OUTPUT ;
    USE SIGNAL ;
    PORT
      LAYER M4 ;
        RECT  0 87.552 0.192 87.576 ;
    END
  END o_d[508]
  PIN o_d[509]
    DIRECTION OUTPUT ;
    USE SIGNAL ;
    PORT
      LAYER M4 ;
        RECT  0 87.84 0.192 87.864 ;
    END
  END o_d[509]
  PIN o_d[50]
    DIRECTION OUTPUT ;
    USE SIGNAL ;
    PORT
      LAYER M4 ;
        RECT  0 12.528 0.192 12.552 ;
    END
  END o_d[50]
  PIN o_d[510]
    DIRECTION OUTPUT ;
    USE SIGNAL ;
    PORT
      LAYER M4 ;
        RECT  0 87.984 0.192 88.008 ;
    END
  END o_d[510]
  PIN o_d[511]
    DIRECTION OUTPUT ;
    USE SIGNAL ;
    PORT
      LAYER M4 ;
        RECT  0 88.128 0.192 88.152 ;
    END
  END o_d[511]
  PIN o_d[51]
    DIRECTION OUTPUT ;
    USE SIGNAL ;
    PORT
      LAYER M4 ;
        RECT  0 12.672 0.192 12.696 ;
    END
  END o_d[51]
  PIN o_d[52]
    DIRECTION OUTPUT ;
    USE SIGNAL ;
    PORT
      LAYER M4 ;
        RECT  0 12.816 0.192 12.84 ;
    END
  END o_d[52]
  PIN o_d[53]
    DIRECTION OUTPUT ;
    USE SIGNAL ;
    PORT
      LAYER M4 ;
        RECT  0 12.96 0.192 12.984 ;
    END
  END o_d[53]
  PIN o_d[54]
    DIRECTION OUTPUT ;
    USE SIGNAL ;
    PORT
      LAYER M4 ;
        RECT  0 13.248 0.192 13.272 ;
    END
  END o_d[54]
  PIN o_d[55]
    DIRECTION OUTPUT ;
    USE SIGNAL ;
    PORT
      LAYER M4 ;
        RECT  0 13.392 0.192 13.416 ;
    END
  END o_d[55]
  PIN o_d[56]
    DIRECTION OUTPUT ;
    USE SIGNAL ;
    PORT
      LAYER M4 ;
        RECT  0 13.536 0.192 13.56 ;
    END
  END o_d[56]
  PIN o_d[57]
    DIRECTION OUTPUT ;
    USE SIGNAL ;
    PORT
      LAYER M4 ;
        RECT  0 13.68 0.192 13.704 ;
    END
  END o_d[57]
  PIN o_d[58]
    DIRECTION OUTPUT ;
    USE SIGNAL ;
    PORT
      LAYER M4 ;
        RECT  0 13.824 0.192 13.848 ;
    END
  END o_d[58]
  PIN o_d[59]
    DIRECTION OUTPUT ;
    USE SIGNAL ;
    PORT
      LAYER M4 ;
        RECT  0 13.968 0.192 13.992 ;
    END
  END o_d[59]
  PIN o_d[5]
    DIRECTION OUTPUT ;
    USE SIGNAL ;
    PORT
      LAYER M4 ;
        RECT  0 5.184 0.192 5.208 ;
    END
  END o_d[5]
  PIN o_d[60]
    DIRECTION OUTPUT ;
    USE SIGNAL ;
    PORT
      LAYER M4 ;
        RECT  0 14.112 0.192 14.136 ;
    END
  END o_d[60]
  PIN o_d[61]
    DIRECTION OUTPUT ;
    USE SIGNAL ;
    PORT
      LAYER M4 ;
        RECT  0 14.4 0.192 14.424 ;
    END
  END o_d[61]
  PIN o_d[62]
    DIRECTION OUTPUT ;
    USE SIGNAL ;
    PORT
      LAYER M4 ;
        RECT  0 14.544 0.192 14.568 ;
    END
  END o_d[62]
  PIN o_d[63]
    DIRECTION OUTPUT ;
    USE SIGNAL ;
    PORT
      LAYER M4 ;
        RECT  0 14.688 0.192 14.712 ;
    END
  END o_d[63]
  PIN o_d[64]
    DIRECTION OUTPUT ;
    USE SIGNAL ;
    PORT
      LAYER M4 ;
        RECT  0 14.832 0.192 14.856 ;
    END
  END o_d[64]
  PIN o_d[65]
    DIRECTION OUTPUT ;
    USE SIGNAL ;
    PORT
      LAYER M4 ;
        RECT  0 14.976 0.192 15 ;
    END
  END o_d[65]
  PIN o_d[66]
    DIRECTION OUTPUT ;
    USE SIGNAL ;
    PORT
      LAYER M4 ;
        RECT  0 15.12 0.192 15.144 ;
    END
  END o_d[66]
  PIN o_d[67]
    DIRECTION OUTPUT ;
    USE SIGNAL ;
    PORT
      LAYER M4 ;
        RECT  0 15.264 0.192 15.288 ;
    END
  END o_d[67]
  PIN o_d[68]
    DIRECTION OUTPUT ;
    USE SIGNAL ;
    PORT
      LAYER M4 ;
        RECT  0 15.408 0.192 15.432 ;
    END
  END o_d[68]
  PIN o_d[69]
    DIRECTION OUTPUT ;
    USE SIGNAL ;
    PORT
      LAYER M4 ;
        RECT  0 15.696 0.192 15.72 ;
    END
  END o_d[69]
  PIN o_d[6]
    DIRECTION OUTPUT ;
    USE SIGNAL ;
    PORT
      LAYER M4 ;
        RECT  0 5.328 0.192 5.352 ;
    END
  END o_d[6]
  PIN o_d[70]
    DIRECTION OUTPUT ;
    USE SIGNAL ;
    PORT
      LAYER M4 ;
        RECT  0 15.84 0.192 15.864 ;
    END
  END o_d[70]
  PIN o_d[71]
    DIRECTION OUTPUT ;
    USE SIGNAL ;
    PORT
      LAYER M4 ;
        RECT  0 15.984 0.192 16.008 ;
    END
  END o_d[71]
  PIN o_d[72]
    DIRECTION OUTPUT ;
    USE SIGNAL ;
    PORT
      LAYER M4 ;
        RECT  0 16.128 0.192 16.152 ;
    END
  END o_d[72]
  PIN o_d[73]
    DIRECTION OUTPUT ;
    USE SIGNAL ;
    PORT
      LAYER M4 ;
        RECT  0 16.272 0.192 16.296 ;
    END
  END o_d[73]
  PIN o_d[74]
    DIRECTION OUTPUT ;
    USE SIGNAL ;
    PORT
      LAYER M4 ;
        RECT  0 16.416 0.192 16.44 ;
    END
  END o_d[74]
  PIN o_d[75]
    DIRECTION OUTPUT ;
    USE SIGNAL ;
    PORT
      LAYER M4 ;
        RECT  0 16.56 0.192 16.584 ;
    END
  END o_d[75]
  PIN o_d[76]
    DIRECTION OUTPUT ;
    USE SIGNAL ;
    PORT
      LAYER M4 ;
        RECT  0 16.848 0.192 16.872 ;
    END
  END o_d[76]
  PIN o_d[77]
    DIRECTION OUTPUT ;
    USE SIGNAL ;
    PORT
      LAYER M4 ;
        RECT  0 16.992 0.192 17.016 ;
    END
  END o_d[77]
  PIN o_d[78]
    DIRECTION OUTPUT ;
    USE SIGNAL ;
    PORT
      LAYER M4 ;
        RECT  0 17.136 0.192 17.16 ;
    END
  END o_d[78]
  PIN o_d[79]
    DIRECTION OUTPUT ;
    USE SIGNAL ;
    PORT
      LAYER M4 ;
        RECT  0 17.28 0.192 17.304 ;
    END
  END o_d[79]
  PIN o_d[7]
    DIRECTION OUTPUT ;
    USE SIGNAL ;
    PORT
      LAYER M4 ;
        RECT  0 5.472 0.192 5.496 ;
    END
  END o_d[7]
  PIN o_d[80]
    DIRECTION OUTPUT ;
    USE SIGNAL ;
    PORT
      LAYER M4 ;
        RECT  0 17.424 0.192 17.448 ;
    END
  END o_d[80]
  PIN o_d[81]
    DIRECTION OUTPUT ;
    USE SIGNAL ;
    PORT
      LAYER M4 ;
        RECT  0 17.568 0.192 17.592 ;
    END
  END o_d[81]
  PIN o_d[82]
    DIRECTION OUTPUT ;
    USE SIGNAL ;
    PORT
      LAYER M4 ;
        RECT  0 17.712 0.192 17.736 ;
    END
  END o_d[82]
  PIN o_d[83]
    DIRECTION OUTPUT ;
    USE SIGNAL ;
    PORT
      LAYER M4 ;
        RECT  0 18 0.192 18.024 ;
    END
  END o_d[83]
  PIN o_d[84]
    DIRECTION OUTPUT ;
    USE SIGNAL ;
    PORT
      LAYER M4 ;
        RECT  0 18.144 0.192 18.168 ;
    END
  END o_d[84]
  PIN o_d[85]
    DIRECTION OUTPUT ;
    USE SIGNAL ;
    PORT
      LAYER M4 ;
        RECT  0 18.288 0.192 18.312 ;
    END
  END o_d[85]
  PIN o_d[86]
    DIRECTION OUTPUT ;
    USE SIGNAL ;
    PORT
      LAYER M4 ;
        RECT  0 18.432 0.192 18.456 ;
    END
  END o_d[86]
  PIN o_d[87]
    DIRECTION OUTPUT ;
    USE SIGNAL ;
    PORT
      LAYER M4 ;
        RECT  0 18.576 0.192 18.6 ;
    END
  END o_d[87]
  PIN o_d[88]
    DIRECTION OUTPUT ;
    USE SIGNAL ;
    PORT
      LAYER M4 ;
        RECT  0 18.72 0.192 18.744 ;
    END
  END o_d[88]
  PIN o_d[89]
    DIRECTION OUTPUT ;
    USE SIGNAL ;
    PORT
      LAYER M4 ;
        RECT  0 18.864 0.192 18.888 ;
    END
  END o_d[89]
  PIN o_d[8]
    DIRECTION OUTPUT ;
    USE SIGNAL ;
    PORT
      LAYER M4 ;
        RECT  0 5.616 0.192 5.64 ;
    END
  END o_d[8]
  PIN o_d[90]
    DIRECTION OUTPUT ;
    USE SIGNAL ;
    PORT
      LAYER M4 ;
        RECT  0 19.152 0.192 19.176 ;
    END
  END o_d[90]
  PIN o_d[91]
    DIRECTION OUTPUT ;
    USE SIGNAL ;
    PORT
      LAYER M4 ;
        RECT  0 19.296 0.192 19.32 ;
    END
  END o_d[91]
  PIN o_d[92]
    DIRECTION OUTPUT ;
    USE SIGNAL ;
    PORT
      LAYER M4 ;
        RECT  0 19.44 0.192 19.464 ;
    END
  END o_d[92]
  PIN o_d[93]
    DIRECTION OUTPUT ;
    USE SIGNAL ;
    PORT
      LAYER M4 ;
        RECT  0 19.584 0.192 19.608 ;
    END
  END o_d[93]
  PIN o_d[94]
    DIRECTION OUTPUT ;
    USE SIGNAL ;
    PORT
      LAYER M4 ;
        RECT  0 19.728 0.192 19.752 ;
    END
  END o_d[94]
  PIN o_d[95]
    DIRECTION OUTPUT ;
    USE SIGNAL ;
    PORT
      LAYER M4 ;
        RECT  0 19.872 0.192 19.896 ;
    END
  END o_d[95]
  PIN o_d[96]
    DIRECTION OUTPUT ;
    USE SIGNAL ;
    PORT
      LAYER M4 ;
        RECT  0 20.016 0.192 20.04 ;
    END
  END o_d[96]
  PIN o_d[97]
    DIRECTION OUTPUT ;
    USE SIGNAL ;
    PORT
      LAYER M4 ;
        RECT  0 20.304 0.192 20.328 ;
    END
  END o_d[97]
  PIN o_d[98]
    DIRECTION OUTPUT ;
    USE SIGNAL ;
    PORT
      LAYER M4 ;
        RECT  0 20.448 0.192 20.472 ;
    END
  END o_d[98]
  PIN o_d[99]
    DIRECTION OUTPUT ;
    USE SIGNAL ;
    PORT
      LAYER M4 ;
        RECT  0 20.592 0.192 20.616 ;
    END
  END o_d[99]
  PIN o_d[9]
    DIRECTION OUTPUT ;
    USE SIGNAL ;
    PORT
      LAYER M4 ;
        RECT  0 5.76 0.192 5.784 ;
    END
  END o_d[9]
  PIN o_row[0]
    DIRECTION OUTPUT ;
    USE SIGNAL ;
    PORT
      LAYER M4 ;
        RECT  0 88.416 0.192 88.44 ;
    END
  END o_row[0]
  PIN o_row[10]
    DIRECTION OUTPUT ;
    USE SIGNAL ;
    PORT
      LAYER M4 ;
        RECT  0 90.144 0.192 90.168 ;
    END
  END o_row[10]
  PIN o_row[11]
    DIRECTION OUTPUT ;
    USE SIGNAL ;
    PORT
      LAYER M4 ;
        RECT  0 90.288 0.192 90.312 ;
    END
  END o_row[11]
  PIN o_row[12]
    DIRECTION OUTPUT ;
    USE SIGNAL ;
    PORT
      LAYER M4 ;
        RECT  0 90.432 0.192 90.456 ;
    END
  END o_row[12]
  PIN o_row[13]
    DIRECTION OUTPUT ;
    USE SIGNAL ;
    PORT
      LAYER M4 ;
        RECT  0 90.576 0.192 90.6 ;
    END
  END o_row[13]
  PIN o_row[1]
    DIRECTION OUTPUT ;
    USE SIGNAL ;
    PORT
      LAYER M4 ;
        RECT  0 88.56 0.192 88.584 ;
    END
  END o_row[1]
  PIN o_row[2]
    DIRECTION OUTPUT ;
    USE SIGNAL ;
    PORT
      LAYER M4 ;
        RECT  0 88.704 0.192 88.728 ;
    END
  END o_row[2]
  PIN o_row[3]
    DIRECTION OUTPUT ;
    USE SIGNAL ;
    PORT
      LAYER M4 ;
        RECT  0 88.992 0.192 89.016 ;
    END
  END o_row[3]
  PIN o_row[4]
    DIRECTION OUTPUT ;
    USE SIGNAL ;
    PORT
      LAYER M4 ;
        RECT  0 89.136 0.192 89.16 ;
    END
  END o_row[4]
  PIN o_row[5]
    DIRECTION OUTPUT ;
    USE SIGNAL ;
    PORT
      LAYER M4 ;
        RECT  0 89.28 0.192 89.304 ;
    END
  END o_row[5]
  PIN o_row[6]
    DIRECTION OUTPUT ;
    USE SIGNAL ;
    PORT
      LAYER M4 ;
        RECT  0 89.424 0.192 89.448 ;
    END
  END o_row[6]
  PIN o_row[7]
    DIRECTION OUTPUT ;
    USE SIGNAL ;
    PORT
      LAYER M4 ;
        RECT  0 89.568 0.192 89.592 ;
    END
  END o_row[7]
  PIN o_row[8]
    DIRECTION OUTPUT ;
    USE SIGNAL ;
    PORT
      LAYER M4 ;
        RECT  0 89.712 0.192 89.736 ;
    END
  END o_row[8]
  PIN o_row[9]
    DIRECTION OUTPUT ;
    USE SIGNAL ;
    PORT
      LAYER M4 ;
        RECT  0 89.856 0.192 89.88 ;
    END
  END o_row[9]
  PIN o_v
    DIRECTION OUTPUT ;
    USE SIGNAL ;
    PORT
      LAYER M4 ;
        RECT  0 88.272 0.192 88.296 ;
    END
  END o_v
  PIN rst_n
    DIRECTION INPUT ;
    USE SIGNAL ;
    PORT
      LAYER M5 ;
        RECT  10.176 94.848 10.2 95.04 ;
    END
    PORT
      LAYER M5 ;
        RECT  10.176 92.821 10.2 94.864 ;
    END
  END rst_n
  PIN VDD
    DIRECTION INOUT ;
    USE POWER ;
    PORT
      LAYER M5 ;
        RECT  88.992 2.151 89.112 92.889 ;
        RECT  83.592 2.151 83.712 92.889 ;
        RECT  78.192 2.151 78.312 92.889 ;
        RECT  72.792 2.151 72.912 92.889 ;
        RECT  67.392 2.151 67.512 92.889 ;
        RECT  61.992 2.151 62.112 92.889 ;
        RECT  56.592 2.151 56.712 92.889 ;
        RECT  51.192 2.151 51.312 92.889 ;
        RECT  45.792 2.151 45.912 92.889 ;
        RECT  40.392 2.151 40.512 92.889 ;
        RECT  34.992 2.151 35.112 92.889 ;
        RECT  29.592 2.151 29.712 92.889 ;
        RECT  24.192 2.151 24.312 92.889 ;
        RECT  18.792 2.151 18.912 92.889 ;
        RECT  13.392 2.151 13.512 92.889 ;
        RECT  7.992 2.151 8.112 92.889 ;
        RECT  2.592 2.151 2.712 92.889 ;
    END
  END VDD
  PIN VSS
    DIRECTION INOUT ;
    USE GROUND ;
    PORT
      LAYER M5 ;
        RECT  88.8 2.137 88.92 92.903 ;
        RECT  83.4 2.137 83.52 92.903 ;
        RECT  78 2.137 78.12 92.903 ;
        RECT  72.6 2.137 72.72 92.903 ;
        RECT  67.2 2.137 67.32 92.903 ;
        RECT  61.8 2.137 61.92 92.903 ;
        RECT  56.4 2.137 56.52 92.903 ;
        RECT  51 2.137 51.12 92.903 ;
        RECT  45.6 2.137 45.72 92.903 ;
        RECT  40.2 2.137 40.32 92.903 ;
        RECT  34.8 2.137 34.92 92.903 ;
        RECT  29.4 2.137 29.52 92.903 ;
        RECT  24 2.137 24.12 92.903 ;
        RECT  18.6 2.137 18.72 92.903 ;
        RECT  13.2 2.137 13.32 92.903 ;
        RECT  7.8 2.137 7.92 92.903 ;
        RECT  2.4 2.137 2.52 92.903 ;
    END
  END VSS
  # OT_OBS_CLOSED layer=M5 d_um=1.536 added=147
  OBS
    LAYER RVTN ;
     RECT  2.16 2.16 92.88 2.295 ;
     RECT  2.16 2.565 92.88 2.835 ;
     RECT  2.16 3.105 92.88 3.375 ;
     RECT  2.16 3.645 92.88 3.915 ;
     RECT  2.16 4.185 92.88 4.455 ;
     RECT  2.16 4.725 92.88 4.995 ;
     RECT  2.16 5.265 92.88 5.535 ;
     RECT  2.16 5.805 92.88 6.075 ;
     RECT  2.16 6.345 92.88 6.615 ;
     RECT  2.16 6.885 92.88 7.155 ;
     RECT  2.16 7.425 92.88 7.695 ;
     RECT  2.16 7.965 92.88 8.235 ;
     RECT  2.16 8.505 92.88 8.775 ;
     RECT  2.16 9.045 92.88 9.315 ;
     RECT  2.16 9.585 92.88 9.855 ;
     RECT  2.16 10.125 92.88 10.395 ;
     RECT  2.16 10.665 92.88 10.935 ;
     RECT  2.16 11.205 92.88 11.475 ;
     RECT  2.16 11.745 92.88 12.015 ;
     RECT  2.16 12.285 92.88 12.555 ;
     RECT  2.16 12.825 92.88 13.095 ;
     RECT  2.16 13.365 92.88 13.635 ;
     RECT  2.16 13.905 92.88 14.175 ;
     RECT  2.16 14.445 92.88 14.715 ;
     RECT  2.16 14.985 92.88 15.255 ;
     RECT  2.16 15.525 92.88 15.795 ;
     RECT  2.16 16.065 92.88 16.335 ;
     RECT  2.16 16.605 92.88 16.875 ;
     RECT  2.16 17.145 92.88 17.415 ;
     RECT  2.16 17.685 92.88 17.955 ;
     RECT  2.16 18.225 92.88 18.495 ;
     RECT  2.16 18.765 92.88 19.035 ;
     RECT  2.16 19.305 92.88 19.575 ;
     RECT  2.16 19.845 92.88 20.115 ;
     RECT  2.16 20.385 92.88 20.655 ;
     RECT  2.16 20.925 92.88 21.195 ;
     RECT  2.16 21.465 92.88 21.735 ;
     RECT  2.16 22.005 92.88 22.275 ;
     RECT  2.16 22.545 92.88 22.815 ;
     RECT  2.16 23.085 92.88 23.355 ;
     RECT  2.16 23.625 92.88 23.895 ;
     RECT  2.16 24.165 92.88 24.435 ;
     RECT  2.16 24.705 92.88 24.975 ;
     RECT  2.16 25.245 92.88 25.515 ;
     RECT  2.16 25.785 92.88 26.055 ;
     RECT  2.16 26.325 92.88 26.595 ;
     RECT  2.16 26.865 92.88 27.135 ;
     RECT  2.16 27.405 92.88 27.675 ;
     RECT  2.16 27.945 92.88 28.215 ;
     RECT  2.16 28.485 92.88 28.755 ;
     RECT  2.16 29.025 92.88 29.295 ;
     RECT  2.16 29.565 92.88 29.835 ;
     RECT  2.16 30.105 92.88 30.375 ;
     RECT  2.16 30.645 92.88 30.915 ;
     RECT  2.16 31.185 92.88 31.455 ;
     RECT  2.16 31.725 92.88 31.995 ;
     RECT  2.16 32.265 92.88 32.535 ;
     RECT  2.16 32.805 92.88 33.075 ;
     RECT  2.16 33.345 92.88 33.615 ;
     RECT  2.16 33.885 92.88 34.155 ;
     RECT  2.16 34.425 92.88 34.695 ;
     RECT  2.16 34.965 92.88 35.235 ;
     RECT  2.16 35.505 92.88 35.775 ;
     RECT  2.16 36.045 92.88 36.315 ;
     RECT  2.16 36.585 92.88 36.855 ;
     RECT  2.16 37.125 92.88 37.395 ;
     RECT  2.16 37.665 92.88 37.935 ;
     RECT  2.16 38.205 92.88 38.475 ;
     RECT  2.16 38.745 92.88 39.015 ;
     RECT  2.16 39.285 92.88 39.555 ;
     RECT  2.16 39.825 92.88 40.095 ;
     RECT  2.16 40.365 92.88 40.635 ;
     RECT  2.16 40.905 92.88 41.175 ;
     RECT  2.16 41.445 92.88 41.715 ;
     RECT  2.16 41.985 92.88 42.255 ;
     RECT  2.16 42.525 92.88 42.795 ;
     RECT  2.16 43.065 92.88 43.335 ;
     RECT  2.16 43.605 92.88 43.875 ;
     RECT  2.16 44.145 92.88 44.415 ;
     RECT  2.16 44.685 92.88 44.955 ;
     RECT  2.16 45.225 92.88 45.495 ;
     RECT  2.16 45.765 92.88 46.035 ;
     RECT  2.16 46.305 92.88 46.575 ;
     RECT  2.16 46.845 92.88 47.115 ;
     RECT  2.16 47.385 92.88 47.655 ;
     RECT  2.16 47.925 92.88 48.195 ;
     RECT  2.16 48.465 92.88 48.735 ;
     RECT  2.16 49.005 92.88 49.275 ;
     RECT  2.16 49.545 92.88 49.815 ;
     RECT  2.16 50.085 92.88 50.355 ;
     RECT  2.16 50.625 92.88 50.895 ;
     RECT  2.16 51.165 92.88 51.435 ;
     RECT  2.16 51.705 92.88 51.975 ;
     RECT  2.16 52.245 92.88 52.515 ;
     RECT  2.16 52.785 92.88 53.055 ;
     RECT  2.16 53.325 92.88 53.595 ;
     RECT  2.16 53.865 92.88 54.135 ;
     RECT  2.16 54.405 92.88 54.675 ;
     RECT  2.16 54.945 92.88 55.215 ;
     RECT  2.16 55.485 92.88 55.755 ;
     RECT  2.16 56.025 92.88 56.295 ;
     RECT  2.16 56.565 92.88 56.835 ;
     RECT  2.16 57.105 92.88 57.375 ;
     RECT  2.16 57.645 92.88 57.915 ;
     RECT  2.16 58.185 92.88 58.455 ;
     RECT  2.16 58.725 92.88 58.995 ;
     RECT  2.16 59.265 92.88 59.535 ;
     RECT  2.16 59.805 92.88 60.075 ;
     RECT  2.16 60.345 92.88 60.615 ;
     RECT  2.16 60.885 92.88 61.155 ;
     RECT  2.16 61.425 92.88 61.695 ;
     RECT  2.16 61.965 92.88 62.235 ;
     RECT  2.16 62.505 92.88 62.775 ;
     RECT  2.16 63.045 92.88 63.315 ;
     RECT  2.16 63.585 92.88 63.855 ;
     RECT  2.16 64.125 92.88 64.395 ;
     RECT  2.16 64.665 92.88 64.935 ;
     RECT  2.16 65.205 92.88 65.475 ;
     RECT  2.16 65.745 92.88 66.015 ;
     RECT  2.16 66.285 92.88 66.555 ;
     RECT  2.16 66.825 92.88 67.095 ;
     RECT  2.16 67.365 92.88 67.635 ;
     RECT  2.16 67.905 92.88 68.175 ;
     RECT  2.16 68.445 92.88 68.715 ;
     RECT  2.16 68.985 92.88 69.255 ;
     RECT  2.16 69.525 92.88 69.795 ;
     RECT  2.16 70.065 92.88 70.335 ;
     RECT  2.16 70.605 92.88 70.875 ;
     RECT  2.16 71.145 92.88 71.415 ;
     RECT  2.16 71.685 92.88 71.955 ;
     RECT  2.16 72.225 92.88 72.495 ;
     RECT  2.16 72.765 92.88 73.035 ;
     RECT  2.16 73.305 92.88 73.575 ;
     RECT  2.16 73.845 92.88 74.115 ;
     RECT  2.16 74.385 92.88 74.655 ;
     RECT  2.16 74.925 92.88 75.195 ;
     RECT  2.16 75.465 92.88 75.735 ;
     RECT  2.16 76.005 92.88 76.275 ;
     RECT  2.16 76.545 92.88 76.815 ;
     RECT  2.16 77.085 92.88 77.355 ;
     RECT  2.16 77.625 92.88 77.895 ;
     RECT  2.16 78.165 92.88 78.435 ;
     RECT  2.16 78.705 92.88 78.975 ;
     RECT  2.16 79.245 92.88 79.515 ;
     RECT  2.16 79.785 92.88 80.055 ;
     RECT  2.16 80.325 92.88 80.595 ;
     RECT  2.16 80.865 92.88 81.135 ;
     RECT  2.16 81.405 92.88 81.675 ;
     RECT  2.16 81.945 92.88 82.215 ;
     RECT  2.16 82.485 92.88 82.755 ;
     RECT  2.16 83.025 92.88 83.295 ;
     RECT  2.16 83.565 92.88 83.835 ;
     RECT  2.16 84.105 92.88 84.375 ;
     RECT  2.16 84.645 92.88 84.915 ;
     RECT  2.16 85.185 92.88 85.455 ;
     RECT  2.16 85.725 92.88 85.995 ;
     RECT  2.16 86.265 92.88 86.535 ;
     RECT  2.16 86.805 92.88 87.075 ;
     RECT  2.16 87.345 92.88 87.615 ;
     RECT  2.16 87.885 92.88 88.155 ;
     RECT  2.16 88.425 92.88 88.695 ;
     RECT  2.16 88.965 92.88 89.235 ;
     RECT  2.16 89.505 92.88 89.775 ;
     RECT  2.16 90.045 92.88 90.315 ;
     RECT  2.16 90.585 92.88 90.855 ;
     RECT  2.16 91.125 92.88 91.395 ;
     RECT  2.16 91.665 92.88 91.935 ;
     RECT  2.16 92.205 92.88 92.475 ;
     RECT  2.16 92.745 92.88 92.88 ;
    LAYER RVTP ;
     RECT  2.16 2.295 92.88 2.565 ;
     RECT  2.16 2.835 92.88 3.105 ;
     RECT  2.16 3.375 92.88 3.645 ;
     RECT  2.16 3.915 92.88 4.185 ;
     RECT  2.16 4.455 92.88 4.725 ;
     RECT  2.16 4.995 92.88 5.265 ;
     RECT  2.16 5.535 92.88 5.805 ;
     RECT  2.16 6.075 92.88 6.345 ;
     RECT  2.16 6.615 92.88 6.885 ;
     RECT  2.16 7.155 92.88 7.425 ;
     RECT  2.16 7.695 92.88 7.965 ;
     RECT  2.16 8.235 92.88 8.505 ;
     RECT  2.16 8.775 92.88 9.045 ;
     RECT  2.16 9.315 92.88 9.585 ;
     RECT  2.16 9.855 92.88 10.125 ;
     RECT  2.16 10.395 92.88 10.665 ;
     RECT  2.16 10.935 92.88 11.205 ;
     RECT  2.16 11.475 92.88 11.745 ;
     RECT  2.16 12.015 92.88 12.285 ;
     RECT  2.16 12.555 92.88 12.825 ;
     RECT  2.16 13.095 92.88 13.365 ;
     RECT  2.16 13.635 92.88 13.905 ;
     RECT  2.16 14.175 92.88 14.445 ;
     RECT  2.16 14.715 92.88 14.985 ;
     RECT  2.16 15.255 92.88 15.525 ;
     RECT  2.16 15.795 92.88 16.065 ;
     RECT  2.16 16.335 92.88 16.605 ;
     RECT  2.16 16.875 92.88 17.145 ;
     RECT  2.16 17.415 92.88 17.685 ;
     RECT  2.16 17.955 92.88 18.225 ;
     RECT  2.16 18.495 92.88 18.765 ;
     RECT  2.16 19.035 92.88 19.305 ;
     RECT  2.16 19.575 92.88 19.845 ;
     RECT  2.16 20.115 92.88 20.385 ;
     RECT  2.16 20.655 92.88 20.925 ;
     RECT  2.16 21.195 92.88 21.465 ;
     RECT  2.16 21.735 92.88 22.005 ;
     RECT  2.16 22.275 92.88 22.545 ;
     RECT  2.16 22.815 92.88 23.085 ;
     RECT  2.16 23.355 92.88 23.625 ;
     RECT  2.16 23.895 92.88 24.165 ;
     RECT  2.16 24.435 92.88 24.705 ;
     RECT  2.16 24.975 92.88 25.245 ;
     RECT  2.16 25.515 92.88 25.785 ;
     RECT  2.16 26.055 92.88 26.325 ;
     RECT  2.16 26.595 92.88 26.865 ;
     RECT  2.16 27.135 92.88 27.405 ;
     RECT  2.16 27.675 92.88 27.945 ;
     RECT  2.16 28.215 92.88 28.485 ;
     RECT  2.16 28.755 92.88 29.025 ;
     RECT  2.16 29.295 92.88 29.565 ;
     RECT  2.16 29.835 92.88 30.105 ;
     RECT  2.16 30.375 92.88 30.645 ;
     RECT  2.16 30.915 92.88 31.185 ;
     RECT  2.16 31.455 92.88 31.725 ;
     RECT  2.16 31.995 92.88 32.265 ;
     RECT  2.16 32.535 92.88 32.805 ;
     RECT  2.16 33.075 92.88 33.345 ;
     RECT  2.16 33.615 92.88 33.885 ;
     RECT  2.16 34.155 92.88 34.425 ;
     RECT  2.16 34.695 92.88 34.965 ;
     RECT  2.16 35.235 92.88 35.505 ;
     RECT  2.16 35.775 92.88 36.045 ;
     RECT  2.16 36.315 92.88 36.585 ;
     RECT  2.16 36.855 92.88 37.125 ;
     RECT  2.16 37.395 92.88 37.665 ;
     RECT  2.16 37.935 92.88 38.205 ;
     RECT  2.16 38.475 92.88 38.745 ;
     RECT  2.16 39.015 92.88 39.285 ;
     RECT  2.16 39.555 92.88 39.825 ;
     RECT  2.16 40.095 92.88 40.365 ;
     RECT  2.16 40.635 92.88 40.905 ;
     RECT  2.16 41.175 92.88 41.445 ;
     RECT  2.16 41.715 92.88 41.985 ;
     RECT  2.16 42.255 92.88 42.525 ;
     RECT  2.16 42.795 92.88 43.065 ;
     RECT  2.16 43.335 92.88 43.605 ;
     RECT  2.16 43.875 92.88 44.145 ;
     RECT  2.16 44.415 92.88 44.685 ;
     RECT  2.16 44.955 92.88 45.225 ;
     RECT  2.16 45.495 92.88 45.765 ;
     RECT  2.16 46.035 92.88 46.305 ;
     RECT  2.16 46.575 92.88 46.845 ;
     RECT  2.16 47.115 92.88 47.385 ;
     RECT  2.16 47.655 92.88 47.925 ;
     RECT  2.16 48.195 92.88 48.465 ;
     RECT  2.16 48.735 92.88 49.005 ;
     RECT  2.16 49.275 92.88 49.545 ;
     RECT  2.16 49.815 92.88 50.085 ;
     RECT  2.16 50.355 92.88 50.625 ;
     RECT  2.16 50.895 92.88 51.165 ;
     RECT  2.16 51.435 92.88 51.705 ;
     RECT  2.16 51.975 92.88 52.245 ;
     RECT  2.16 52.515 92.88 52.785 ;
     RECT  2.16 53.055 92.88 53.325 ;
     RECT  2.16 53.595 92.88 53.865 ;
     RECT  2.16 54.135 92.88 54.405 ;
     RECT  2.16 54.675 92.88 54.945 ;
     RECT  2.16 55.215 92.88 55.485 ;
     RECT  2.16 55.755 92.88 56.025 ;
     RECT  2.16 56.295 92.88 56.565 ;
     RECT  2.16 56.835 92.88 57.105 ;
     RECT  2.16 57.375 92.88 57.645 ;
     RECT  2.16 57.915 92.88 58.185 ;
     RECT  2.16 58.455 92.88 58.725 ;
     RECT  2.16 58.995 92.88 59.265 ;
     RECT  2.16 59.535 92.88 59.805 ;
     RECT  2.16 60.075 92.88 60.345 ;
     RECT  2.16 60.615 92.88 60.885 ;
     RECT  2.16 61.155 92.88 61.425 ;
     RECT  2.16 61.695 92.88 61.965 ;
     RECT  2.16 62.235 92.88 62.505 ;
     RECT  2.16 62.775 92.88 63.045 ;
     RECT  2.16 63.315 92.88 63.585 ;
     RECT  2.16 63.855 92.88 64.125 ;
     RECT  2.16 64.395 92.88 64.665 ;
     RECT  2.16 64.935 92.88 65.205 ;
     RECT  2.16 65.475 92.88 65.745 ;
     RECT  2.16 66.015 92.88 66.285 ;
     RECT  2.16 66.555 92.88 66.825 ;
     RECT  2.16 67.095 92.88 67.365 ;
     RECT  2.16 67.635 92.88 67.905 ;
     RECT  2.16 68.175 92.88 68.445 ;
     RECT  2.16 68.715 92.88 68.985 ;
     RECT  2.16 69.255 92.88 69.525 ;
     RECT  2.16 69.795 92.88 70.065 ;
     RECT  2.16 70.335 92.88 70.605 ;
     RECT  2.16 70.875 92.88 71.145 ;
     RECT  2.16 71.415 92.88 71.685 ;
     RECT  2.16 71.955 92.88 72.225 ;
     RECT  2.16 72.495 92.88 72.765 ;
     RECT  2.16 73.035 92.88 73.305 ;
     RECT  2.16 73.575 92.88 73.845 ;
     RECT  2.16 74.115 92.88 74.385 ;
     RECT  2.16 74.655 92.88 74.925 ;
     RECT  2.16 75.195 92.88 75.465 ;
     RECT  2.16 75.735 92.88 76.005 ;
     RECT  2.16 76.275 92.88 76.545 ;
     RECT  2.16 76.815 92.88 77.085 ;
     RECT  2.16 77.355 92.88 77.625 ;
     RECT  2.16 77.895 92.88 78.165 ;
     RECT  2.16 78.435 92.88 78.705 ;
     RECT  2.16 78.975 92.88 79.245 ;
     RECT  2.16 79.515 92.88 79.785 ;
     RECT  2.16 80.055 92.88 80.325 ;
     RECT  2.16 80.595 92.88 80.865 ;
     RECT  2.16 81.135 92.88 81.405 ;
     RECT  2.16 81.675 92.88 81.945 ;
     RECT  2.16 82.215 92.88 82.485 ;
     RECT  2.16 82.755 92.88 83.025 ;
     RECT  2.16 83.295 92.88 83.565 ;
     RECT  2.16 83.835 92.88 84.105 ;
     RECT  2.16 84.375 92.88 84.645 ;
     RECT  2.16 84.915 92.88 85.185 ;
     RECT  2.16 85.455 92.88 85.725 ;
     RECT  2.16 85.995 92.88 86.265 ;
     RECT  2.16 86.535 92.88 86.805 ;
     RECT  2.16 87.075 92.88 87.345 ;
     RECT  2.16 87.615 92.88 87.885 ;
     RECT  2.16 88.155 92.88 88.425 ;
     RECT  2.16 88.695 92.88 88.965 ;
     RECT  2.16 89.235 92.88 89.505 ;
     RECT  2.16 89.775 92.88 90.045 ;
     RECT  2.16 90.315 92.88 90.585 ;
     RECT  2.16 90.855 92.88 91.125 ;
     RECT  2.16 91.395 92.88 91.665 ;
     RECT  2.16 91.935 92.88 92.205 ;
     RECT  2.16 92.475 92.88 92.745 ;
    LAYER M1 ;
     RECT  2.16 2.151 92.88 92.889 ;
    LAYER M2 ;
     RECT  0.211 4.194 0.247 4.212 ;
     RECT  0.247 3.924 0.283 4.554 ;
     RECT  0.211 29.376 0.283 29.394 ;
     RECT  0.211 68.256 0.283 68.274 ;
     RECT  0.283 29.268 0.311 29.394 ;
     RECT  0.283 68.148 0.311 68.274 ;
     RECT  0.283 3.384 0.319 4.554 ;
     RECT  0.211 40.176 0.319 40.194 ;
     RECT  0.247 33.966 0.347 33.984 ;
     RECT  0.319 40.068 0.347 40.194 ;
     RECT  0.211 67.374 0.347 67.392 ;
     RECT  0.311 29.268 0.383 29.286 ;
     RECT  0.311 68.148 0.383 68.166 ;
     RECT  0.347 40.068 0.419 40.086 ;
     RECT  0.319 3.384 0.535 4.824 ;
     RECT  0.535 3.384 2.16 5.094 ;
     RECT  0.211 6.786 2.16 6.804 ;
     RECT  0.535 12.528 2.16 12.546 ;
     RECT  0.535 26.604 2.16 26.622 ;
     RECT  0.535 31.806 2.16 31.824 ;
     RECT  2.155 35.244 2.16 35.262 ;
     RECT  0.535 44.226 2.16 44.244 ;
     RECT  0.535 55.224 2.16 55.242 ;
     RECT  0.535 71.694 2.16 71.712 ;
     RECT  1.399 76.356 2.16 76.374 ;
     RECT  2.047 87.858 2.16 87.876 ;
     RECT  1.723 91.674 2.16 91.692 ;
     RECT  2.16 2.151 92.88 92.889 ;
     RECT  92.88 4.23 92.939 90.918 ;
     RECT  92.939 4.698 92.975 8.766 ;
     RECT  92.939 9.558 92.975 27.126 ;
     RECT  92.939 27.918 92.975 50.922 ;
     RECT  92.939 51.678 92.975 61.758 ;
     RECT  92.939 64.638 92.975 68.976 ;
     RECT  92.939 69.768 92.975 77.346 ;
     RECT  92.939 80.91 92.975 88.722 ;
     RECT  92.975 23.058 93.011 27.126 ;
     RECT  92.975 46.278 93.011 50.886 ;
     RECT  92.975 38.178 93.047 43.056 ;
     RECT  92.939 78.174 93.479 80.154 ;
     RECT  92.975 5.238 93.515 8.766 ;
     RECT  92.975 9.558 93.515 22.23 ;
     RECT  93.011 23.598 93.515 27.126 ;
     RECT  92.975 27.918 93.515 29.358 ;
     RECT  92.975 30.42 93.515 34.146 ;
     RECT  92.975 34.938 93.515 35.838 ;
     RECT  92.975 36.63 93.515 37.386 ;
     RECT  93.047 38.178 93.515 39.006 ;
     RECT  93.047 39.87 93.515 43.056 ;
     RECT  92.975 43.848 93.515 45.522 ;
     RECT  93.011 46.548 93.515 50.886 ;
     RECT  92.975 51.678 93.515 61.722 ;
     RECT  92.939 62.748 93.515 63.846 ;
     RECT  92.975 64.638 93.515 66.006 ;
     RECT  92.975 66.798 93.515 68.976 ;
     RECT  92.975 69.768 93.515 71.208 ;
     RECT  92.975 72.27 93.515 77.346 ;
     RECT  93.479 78.21 93.515 80.154 ;
     RECT  92.975 80.91 93.515 87.066 ;
     RECT  92.975 87.858 93.515 88.722 ;
     RECT  92.939 89.478 93.515 90.576 ;
     RECT  93.515 8.748 93.551 8.766 ;
     RECT  93.515 9.828 93.551 9.846 ;
     RECT  93.515 10.944 93.551 11.736 ;
     RECT  93.515 13.608 93.551 13.626 ;
     RECT  93.515 15.3 93.551 15.552 ;
     RECT  93.515 18.54 93.551 20.106 ;
     RECT  93.515 21.978 93.551 22.068 ;
     RECT  93.515 25.02 93.551 25.038 ;
     RECT  93.515 26.1 93.551 26.352 ;
     RECT  93.515 27.108 93.551 27.126 ;
     RECT  93.515 29.34 93.551 29.358 ;
     RECT  93.515 30.654 93.551 32.796 ;
     RECT  93.515 33.858 93.551 33.876 ;
     RECT  93.515 35.208 93.551 35.532 ;
     RECT  93.515 40.14 93.551 40.158 ;
     RECT  93.515 41.148 93.551 41.166 ;
     RECT  93.515 41.958 93.551 41.976 ;
     RECT  93.515 44.658 93.551 45.288 ;
     RECT  93.515 48.168 93.551 48.798 ;
     RECT  93.515 50.058 93.551 50.076 ;
     RECT  93.515 50.868 93.551 50.886 ;
     RECT  93.515 51.948 93.551 52.848 ;
     RECT  93.515 53.874 93.551 54.702 ;
     RECT  93.515 55.8 93.551 56.826 ;
     RECT  93.515 57.618 93.551 58.482 ;
     RECT  93.515 59.778 93.551 61.722 ;
     RECT  93.515 62.748 93.551 63.612 ;
     RECT  93.515 65.988 93.551 66.006 ;
     RECT  93.515 66.87 93.551 68.976 ;
     RECT  93.515 72.468 93.551 72.558 ;
     RECT  93.515 77.328 93.551 77.346 ;
     RECT  93.515 78.408 93.551 78.498 ;
     RECT  93.515 80.91 93.551 82.476 ;
     RECT  93.515 83.268 93.551 83.286 ;
     RECT  93.515 84.15 93.551 85.176 ;
     RECT  93.515 86.508 93.551 86.526 ;
     RECT  93.515 88.128 93.551 88.65 ;
     RECT  93.515 90.36 93.551 90.378 ;
     RECT  93.551 26.334 93.587 26.352 ;
     RECT  93.551 32.31 93.587 32.796 ;
     RECT  93.551 59.778 93.587 59.796 ;
     RECT  93.551 67.878 93.587 68.976 ;
     RECT  93.551 84.15 93.587 84.168 ;
     RECT  93.551 85.158 93.587 85.176 ;
     RECT  93.515 6.588 94.091 6.606 ;
     RECT  93.551 10.944 94.091 11.574 ;
     RECT  93.515 14.49 94.091 14.508 ;
     RECT  93.551 15.534 94.091 15.552 ;
     RECT  93.551 18.54 94.091 18.558 ;
     RECT  93.551 19.548 94.091 19.566 ;
     RECT  93.551 22.05 94.091 22.068 ;
     RECT  93.515 24.21 94.091 24.228 ;
     RECT  93.515 28.458 94.091 28.476 ;
     RECT  93.551 30.654 94.091 31.518 ;
     RECT  93.587 32.778 94.091 32.796 ;
     RECT  93.551 35.514 94.091 35.532 ;
     RECT  93.515 38.718 94.091 38.736 ;
     RECT  93.551 45.234 94.091 45.288 ;
     RECT  93.515 46.62 94.091 47.178 ;
     RECT  93.551 48.168 94.091 48.186 ;
     RECT  93.551 52.02 94.091 52.848 ;
     RECT  93.551 53.874 94.091 53.892 ;
     RECT  93.551 54.684 94.091 54.702 ;
     RECT  93.551 56.34 94.091 56.358 ;
     RECT  93.551 57.618 94.091 58.14 ;
     RECT  93.551 60.624 94.091 60.642 ;
     RECT  93.551 61.704 94.091 61.722 ;
     RECT  93.551 63.126 94.091 63.612 ;
     RECT  93.551 66.87 94.091 66.888 ;
     RECT  93.587 67.878 94.091 68.004 ;
     RECT  93.587 68.958 94.091 68.976 ;
     RECT  93.551 72.54 94.091 72.558 ;
     RECT  93.515 74.97 94.091 74.988 ;
     RECT  93.551 78.408 94.091 78.426 ;
     RECT  93.551 80.91 94.091 81.162 ;
     RECT  93.551 88.632 94.091 88.65 ;
     RECT  94.091 30.96 94.127 30.978 ;
     RECT  94.091 63.594 94.127 63.612 ;
     RECT  94.091 80.91 94.127 80.928 ;
     RECT  94.091 45.234 94.163 45.252 ;
    LAYER M3 ;
     RECT  18.756 0.187 18.774 2.143 ;
     RECT  18.615 2.143 18.774 2.191 ;
     RECT  47.376 2.191 47.394 2.299 ;
     RECT  18.615 2.191 19.494 2.371 ;
     RECT  47.376 2.299 47.79 2.371 ;
     RECT  76.644 2.299 76.662 2.371 ;
     RECT  2.415 2.143 2.505 2.413 ;
     RECT  7.815 2.143 7.905 2.413 ;
     RECT  13.215 2.143 13.305 2.413 ;
     RECT  24.015 2.143 24.105 2.413 ;
     RECT  29.415 2.143 29.505 2.413 ;
     RECT  34.815 2.143 34.905 2.413 ;
     RECT  40.215 2.143 40.305 2.413 ;
     RECT  45.615 2.143 45.705 2.413 ;
     RECT  51.015 2.143 51.105 2.413 ;
     RECT  56.415 2.143 56.505 2.413 ;
     RECT  61.815 2.143 61.905 2.413 ;
     RECT  67.215 2.143 67.305 2.413 ;
     RECT  72.615 2.143 72.705 2.413 ;
     RECT  78.015 2.143 78.105 2.413 ;
     RECT  83.415 2.143 83.505 2.413 ;
     RECT  88.815 2.143 88.905 2.413 ;
     RECT  47.088 2.371 47.79 2.489 ;
     RECT  76.428 2.371 76.662 2.489 ;
     RECT  18.612 2.371 19.494 2.525 ;
     RECT  76.428 2.489 76.626 2.525 ;
     RECT  18.615 2.525 19.494 2.759 ;
     RECT  47.376 2.489 47.79 2.759 ;
     RECT  47.376 2.759 47.682 2.795 ;
     RECT  24.015 2.413 24.297 3.271 ;
     RECT  47.376 2.795 47.394 3.299 ;
     RECT  76.608 2.525 76.626 3.299 ;
     RECT  2.415 2.413 2.697 3.307 ;
     RECT  75.456 3.343 75.474 3.389 ;
     RECT  45.615 2.413 45.897 3.415 ;
     RECT  19.8 2.911 19.818 3.569 ;
     RECT  18.615 2.759 18.897 3.577 ;
     RECT  18.615 3.577 19.17 3.629 ;
     RECT  0.288 3.379 0.306 3.649 ;
     RECT  2.415 3.307 2.754 3.649 ;
     RECT  2.415 3.649 2.862 3.721 ;
     RECT  45.615 3.415 46.422 3.839 ;
     RECT  0.288 3.649 0.522 3.919 ;
     RECT  2.34 3.721 2.862 4.081 ;
     RECT  47.7 3.991 47.718 4.109 ;
     RECT  42.768 4.081 42.786 4.181 ;
     RECT  0.252 3.919 0.522 4.189 ;
     RECT  2.34 4.081 2.898 4.189 ;
     RECT  88.815 2.413 89.097 4.225 ;
     RECT  2.34 4.189 3.33 4.261 ;
     RECT  90.684 3.991 90.702 4.261 ;
     RECT  2.304 4.261 3.33 4.349 ;
     RECT  92.016 4.261 92.034 4.451 ;
     RECT  2.34 4.349 3.33 4.531 ;
     RECT  4.248 4.225 4.266 4.555 ;
     RECT  92.916 4.225 92.934 4.603 ;
     RECT  7.815 2.413 8.097 4.621 ;
     RECT  88.815 4.225 89.55 4.621 ;
     RECT  90.684 4.261 91.17 4.621 ;
     RECT  2.34 4.531 3.438 4.637 ;
     RECT  46.728 4.621 46.746 4.721 ;
     RECT  5.796 4.555 5.814 4.729 ;
     RECT  88.272 4.621 89.55 4.729 ;
     RECT  90.612 4.621 91.17 4.729 ;
     RECT  5.796 4.729 6.39 4.765 ;
     RECT  7.308 4.621 8.097 4.765 ;
     RECT  90.468 4.729 91.17 4.765 ;
     RECT  46.8 4.765 46.818 4.801 ;
     RECT  5.796 4.765 8.097 4.885 ;
     RECT  42.84 4.801 42.858 4.927 ;
     RECT  42.768 4.927 42.858 4.991 ;
     RECT  46.8 4.801 47.178 4.999 ;
     RECT  42.768 4.991 42.786 5.027 ;
     RECT  0.216 4.189 0.522 5.071 ;
     RECT  10.764 4.765 10.782 5.099 ;
     RECT  86.652 4.729 86.67 5.161 ;
     RECT  86.652 5.161 86.778 5.179 ;
     RECT  92.916 4.603 92.97 5.179 ;
     RECT  46.8 4.999 47.322 5.189 ;
     RECT  0.216 5.071 0.558 5.213 ;
     RECT  86.256 5.179 86.778 5.269 ;
     RECT  90.468 4.765 91.926 5.269 ;
     RECT  2.376 4.637 3.438 5.305 ;
     RECT  4.248 4.555 4.914 5.305 ;
     RECT  48.78 5.233 48.798 5.305 ;
     RECT  86.256 5.269 87.282 5.305 ;
     RECT  92.916 5.179 93.51 5.323 ;
     RECT  48.276 5.305 48.798 5.341 ;
     RECT  88.092 4.729 89.55 5.341 ;
     RECT  90.468 5.269 92.07 5.341 ;
     RECT  92.916 5.323 94.086 5.341 ;
     RECT  0.216 5.213 0.522 5.357 ;
     RECT  48.024 5.341 48.798 5.459 ;
     RECT  86.076 5.305 87.282 5.459 ;
     RECT  46.8 5.189 47.178 5.467 ;
     RECT  88.092 5.341 89.73 5.467 ;
     RECT  90.468 5.341 94.086 5.467 ;
     RECT  5.796 4.885 8.226 5.495 ;
     RECT  0.216 5.357 0.342 5.501 ;
     RECT  86.076 5.459 86.814 5.531 ;
     RECT  46.764 5.467 47.178 5.567 ;
     RECT  88.092 5.467 94.086 5.575 ;
     RECT  2.376 5.305 4.914 5.701 ;
     RECT  6.12 5.495 8.226 5.701 ;
     RECT  87.804 5.575 94.086 5.837 ;
     RECT  86.076 5.531 86.742 5.845 ;
     RECT  85.896 5.845 86.742 5.873 ;
     RECT  0.216 5.501 0.234 5.933 ;
     RECT  6.12 5.701 8.55 5.999 ;
     RECT  10.008 5.947 10.026 5.999 ;
     RECT  47.16 5.567 47.178 5.999 ;
     RECT  51.015 2.413 51.297 6.007 ;
     RECT  88.092 5.837 94.086 6.035 ;
     RECT  7.488 5.999 8.55 6.071 ;
     RECT  50.688 6.007 51.297 6.107 ;
     RECT  2.376 5.701 5.31 6.151 ;
     RECT  2.304 6.151 5.31 6.221 ;
     RECT  6.12 5.999 6.75 6.269 ;
     RECT  88.272 6.035 94.086 6.269 ;
     RECT  82.656 5.701 82.674 6.313 ;
     RECT  83.415 2.413 83.697 6.313 ;
     RECT  47.268 6.115 47.718 6.385 ;
     RECT  86.652 5.873 86.742 6.421 ;
     RECT  2.415 6.221 5.31 6.511 ;
     RECT  82.656 6.313 83.697 6.511 ;
     RECT  47.268 6.385 48.042 6.539 ;
     RECT  85.896 5.873 85.914 6.575 ;
     RECT  7.488 6.071 8.478 6.611 ;
     RECT  92.664 6.269 94.086 6.611 ;
     RECT  0.252 6.379 0.27 6.619 ;
     RECT  42.804 6.547 42.822 6.647 ;
     RECT  86.652 6.421 86.814 6.655 ;
     RECT  0.252 6.619 0.306 6.667 ;
     RECT  2.415 6.511 5.346 6.691 ;
     RECT  6.12 6.269 6.678 6.691 ;
     RECT  0.252 6.667 0.378 6.781 ;
     RECT  49.104 6.583 49.122 6.781 ;
     RECT  0.216 6.781 0.378 6.797 ;
     RECT  0.216 6.797 0.306 6.845 ;
     RECT  47.376 6.539 48.042 6.889 ;
     RECT  0.216 6.845 0.27 6.941 ;
     RECT  82.656 6.511 84.402 6.953 ;
     RECT  83.415 6.953 84.402 6.955 ;
     RECT  7.488 6.611 8.406 6.961 ;
     RECT  47.376 6.889 48.078 6.961 ;
     RECT  49.032 6.781 49.122 6.961 ;
     RECT  83.415 6.955 84.51 6.989 ;
     RECT  84.492 6.989 84.51 6.995 ;
     RECT  2.415 6.691 6.678 7.051 ;
     RECT  51.015 6.107 51.297 7.051 ;
     RECT  7.452 6.961 8.406 7.079 ;
     RECT  47.376 6.961 49.122 7.079 ;
     RECT  50.76 7.051 51.297 7.087 ;
     RECT  86.652 6.655 86.886 7.087 ;
     RECT  88.272 6.269 91.89 7.115 ;
     RECT  91.8 7.115 91.89 7.231 ;
     RECT  92.664 6.611 93.51 7.231 ;
     RECT  86.652 7.087 87.462 7.349 ;
     RECT  88.272 7.115 90.774 7.349 ;
     RECT  86.652 7.349 87.102 7.357 ;
     RECT  88.272 7.349 90.738 7.387 ;
     RECT  2.304 7.051 6.678 7.393 ;
     RECT  86.472 7.357 87.102 7.421 ;
     RECT  7.815 7.079 8.406 7.465 ;
     RECT  9.18 7.231 9.198 7.465 ;
     RECT  2.304 7.393 7.002 7.529 ;
     RECT  82.656 6.953 82.674 7.529 ;
     RECT  86.652 7.421 87.102 7.529 ;
     RECT  48.132 7.079 49.122 7.619 ;
     RECT  0.252 6.941 0.27 7.661 ;
     RECT  7.815 7.465 9.198 7.691 ;
     RECT  10.8 7.735 10.818 7.771 ;
     RECT  48.132 7.619 48.654 7.861 ;
     RECT  91.8 7.231 93.51 7.861 ;
     RECT  10.728 7.771 10.818 7.889 ;
     RECT  6.516 7.529 7.002 7.897 ;
     RECT  7.815 7.691 8.514 7.897 ;
     RECT  87.948 7.387 90.738 7.901 ;
     RECT  87.948 7.901 90.702 7.949 ;
     RECT  50.724 7.087 51.297 7.961 ;
     RECT  48.06 7.861 48.654 7.997 ;
     RECT  42.768 7.969 42.786 8.005 ;
     RECT  2.304 7.529 5.742 8.159 ;
     RECT  6.516 7.897 8.514 8.159 ;
     RECT  46.62 8.041 46.638 8.159 ;
     RECT  42.768 8.005 42.822 8.231 ;
     RECT  5.472 8.159 5.742 8.275 ;
     RECT  6.516 8.159 8.37 8.275 ;
     RECT  85.752 7.963 85.77 8.311 ;
     RECT  86.688 7.529 87.102 8.311 ;
     RECT  87.948 7.949 87.966 8.311 ;
     RECT  42.768 8.231 42.786 8.339 ;
     RECT  85.752 8.311 85.914 8.429 ;
     RECT  91.476 7.861 93.51 8.491 ;
     RECT  9.288 8.311 9.306 8.525 ;
     RECT  48.456 7.997 48.654 8.545 ;
     RECT  86.688 8.311 87.966 8.707 ;
     RECT  88.815 7.949 90.702 8.707 ;
     RECT  91.476 8.491 93.546 8.771 ;
     RECT  48.456 8.545 48.798 8.779 ;
     RECT  86.688 8.707 90.702 8.779 ;
     RECT  5.472 8.275 8.37 8.807 ;
     RECT  86.652 8.779 90.702 8.807 ;
     RECT  48.384 8.779 48.798 8.815 ;
     RECT  9.252 8.707 9.27 8.851 ;
     RECT  87.984 8.807 90.702 8.851 ;
     RECT  91.476 8.771 93.51 8.851 ;
     RECT  2.304 8.159 4.698 8.923 ;
     RECT  5.472 8.807 6.858 8.923 ;
     RECT  7.815 8.807 8.37 8.969 ;
     RECT  48.312 8.815 48.798 8.969 ;
     RECT  86.652 8.807 87.21 8.969 ;
     RECT  87.984 8.851 93.51 8.969 ;
     RECT  48.312 8.969 48.51 9.049 ;
     RECT  7.815 8.969 8.334 9.077 ;
     RECT  9.216 8.851 9.27 9.077 ;
     RECT  9.216 9.077 9.234 9.113 ;
     RECT  86.652 8.969 87.138 9.113 ;
     RECT  48.06 9.049 48.51 9.121 ;
     RECT  47.988 9.121 48.51 9.239 ;
     RECT  0.252 8.923 0.27 9.341 ;
     RECT  88.092 8.969 93.51 9.499 ;
     RECT  48.168 9.239 48.51 9.509 ;
     RECT  2.304 8.923 6.858 9.589 ;
     RECT  7.815 9.077 8.097 9.589 ;
     RECT  10.836 9.481 10.854 9.617 ;
     RECT  2.304 9.589 6.894 9.661 ;
     RECT  2.304 9.661 7.002 9.677 ;
     RECT  86.652 9.113 86.67 9.689 ;
     RECT  9.108 9.661 9.126 9.931 ;
     RECT  2.415 9.677 7.002 10.021 ;
     RECT  7.776 9.589 8.097 10.021 ;
     RECT  9.108 9.931 9.198 10.121 ;
     RECT  88.092 9.499 93.546 10.157 ;
     RECT  88.344 10.157 93.546 10.229 ;
     RECT  8.82 10.201 8.838 10.319 ;
     RECT  49.212 10.093 49.23 10.435 ;
     RECT  51.015 7.961 51.297 10.435 ;
     RECT  10.692 10.327 10.71 10.471 ;
     RECT  86.328 10.435 86.346 10.493 ;
     RECT  10.692 10.471 10.782 10.499 ;
     RECT  88.488 10.229 93.546 10.507 ;
     RECT  10.764 10.499 10.782 10.589 ;
     RECT  48.672 10.435 49.23 10.589 ;
     RECT  87.12 10.291 87.282 10.589 ;
     RECT  48.672 10.589 48.69 10.625 ;
     RECT  82.656 10.363 82.674 10.625 ;
     RECT  2.415 10.021 8.097 10.661 ;
     RECT  86.652 10.597 86.886 10.697 ;
     RECT  2.415 10.661 6.822 10.769 ;
     RECT  47.052 9.661 47.07 10.831 ;
     RECT  6.552 10.769 6.822 10.859 ;
     RECT  46.8 10.831 47.07 10.867 ;
     RECT  2.415 10.769 5.598 10.939 ;
     RECT  50.724 10.435 51.297 10.967 ;
     RECT  88.488 10.507 94.086 10.975 ;
     RECT  87.876 10.975 94.086 11.129 ;
     RECT  42.768 11.101 42.786 11.201 ;
     RECT  46.8 10.867 47.43 11.281 ;
     RECT  46.8 11.281 47.718 11.399 ;
     RECT  46.8 11.399 47.646 11.443 ;
     RECT  46.764 11.443 47.646 11.471 ;
     RECT  86.868 10.697 86.886 11.479 ;
     RECT  7.776 10.661 8.097 11.611 ;
     RECT  6.552 10.859 6.75 11.641 ;
     RECT  85.932 11.479 85.95 11.659 ;
     RECT  46.764 11.471 47.61 11.669 ;
     RECT  85.788 11.659 85.95 11.669 ;
     RECT  85.788 11.669 85.806 11.705 ;
     RECT  6.552 11.641 6.93 11.741 ;
     RECT  6.624 11.741 6.93 11.749 ;
     RECT  7.74 11.611 8.097 11.749 ;
     RECT  86.688 11.479 86.886 11.749 ;
     RECT  86.652 11.749 86.886 11.849 ;
     RECT  6.624 11.749 8.097 11.939 ;
     RECT  10.8 11.749 10.818 11.939 ;
     RECT  2.304 10.939 5.598 11.947 ;
     RECT  88.344 11.129 94.086 12.019 ;
     RECT  46.764 11.669 47.538 12.055 ;
     RECT  87.876 12.019 94.086 12.091 ;
     RECT  46.728 12.055 47.538 12.281 ;
     RECT  86.688 11.849 86.886 12.289 ;
     RECT  2.304 11.947 5.742 12.325 ;
     RECT  6.66 11.939 8.097 12.325 ;
     RECT  6.66 12.325 8.226 12.361 ;
     RECT  6.66 12.361 8.298 12.365 ;
     RECT  87.804 12.091 94.086 12.413 ;
     RECT  6.732 12.365 8.298 12.479 ;
     RECT  46.764 12.281 47.538 12.479 ;
     RECT  86.688 12.289 87.03 12.479 ;
     RECT  86.688 12.479 86.886 12.515 ;
     RECT  0.252 11.707 0.27 12.523 ;
     RECT  6.804 12.479 8.298 12.559 ;
     RECT  6.804 12.559 8.442 12.595 ;
     RECT  10.764 12.559 10.782 12.659 ;
     RECT  0.252 12.523 0.558 12.701 ;
     RECT  51.015 10.967 51.297 12.721 ;
     RECT  50.724 12.721 51.297 12.757 ;
     RECT  6.804 12.595 8.586 12.821 ;
     RECT  50.652 12.757 51.297 12.857 ;
     RECT  9.432 12.631 9.45 12.893 ;
     RECT  6.912 12.821 8.586 12.901 ;
     RECT  2.304 12.325 5.814 13.019 ;
     RECT  87.804 12.413 93.51 13.027 ;
     RECT  86.868 12.515 86.886 13.055 ;
     RECT  82.656 12.901 82.674 13.091 ;
     RECT  2.376 13.019 5.814 13.099 ;
     RECT  87.732 13.027 93.51 13.243 ;
     RECT  0.216 12.955 0.234 13.277 ;
     RECT  2.376 13.099 5.994 13.289 ;
     RECT  6.912 12.901 9.126 13.289 ;
     RECT  87.732 13.243 93.546 13.289 ;
     RECT  6.948 13.289 9.126 13.361 ;
     RECT  46.764 12.479 46.818 13.361 ;
     RECT  47.88 12.631 48.258 13.405 ;
     RECT  46.8 13.361 46.818 13.469 ;
     RECT  6.948 13.361 8.658 13.559 ;
     RECT  47.88 13.405 48.474 13.559 ;
     RECT  0.252 13.531 0.27 13.661 ;
     RECT  2.376 13.289 5.922 13.667 ;
     RECT  48.456 13.559 48.474 13.801 ;
     RECT  47.484 13.711 47.502 13.829 ;
     RECT  10.8 13.801 10.818 13.937 ;
     RECT  2.376 13.667 5.634 13.945 ;
     RECT  48.456 13.801 48.51 14.009 ;
     RECT  87.84 13.289 93.546 14.107 ;
     RECT  48.492 14.009 48.51 14.135 ;
     RECT  1.152 13.963 1.17 14.141 ;
     RECT  87.804 14.107 94.086 14.141 ;
     RECT  86.652 13.441 86.706 14.203 ;
     RECT  87.804 14.141 87.858 14.237 ;
     RECT  86.148 14.203 86.706 14.243 ;
     RECT  2.34 13.945 5.634 14.251 ;
     RECT  86.652 14.243 86.706 14.251 ;
     RECT  87.804 14.237 87.822 14.251 ;
     RECT  50.724 12.857 51.297 14.341 ;
     RECT  86.652 14.251 87.822 14.369 ;
     RECT  6.948 13.559 8.097 14.377 ;
     RECT  50.688 14.341 51.297 14.441 ;
     RECT  9.036 14.341 9.054 14.449 ;
     RECT  87.66 14.369 87.822 14.477 ;
     RECT  6.408 14.377 8.097 14.491 ;
     RECT  9.036 14.449 9.09 14.491 ;
     RECT  2.304 14.251 5.634 14.611 ;
     RECT  6.408 14.491 9.09 14.611 ;
     RECT  47.592 14.521 47.61 14.639 ;
     RECT  42.768 14.449 42.786 14.711 ;
     RECT  2.304 14.611 9.09 14.819 ;
     RECT  86.652 14.369 86.67 14.819 ;
     RECT  88.815 14.141 94.086 14.881 ;
     RECT  2.304 14.819 8.406 14.945 ;
     RECT  46.764 14.611 46.782 15.017 ;
     RECT  10.908 14.881 10.926 15.053 ;
     RECT  0.252 14.539 0.27 15.149 ;
     RECT  87.66 14.477 87.678 15.163 ;
     RECT  9.432 14.989 9.45 15.179 ;
     RECT  47.16 15.061 47.178 15.179 ;
     RECT  87.516 15.163 87.678 15.215 ;
     RECT  42.804 15.187 42.822 15.223 ;
     RECT  42.804 15.223 42.894 15.287 ;
     RECT  48.888 14.989 49.122 15.287 ;
     RECT  87.624 15.215 87.678 15.307 ;
     RECT  88.596 14.881 94.086 15.307 ;
     RECT  42.876 15.287 42.894 15.359 ;
     RECT  24.015 3.271 24.354 15.403 ;
     RECT  87.624 15.307 94.086 15.557 ;
     RECT  47.376 15.565 47.394 15.601 ;
     RECT  87.624 15.557 93.51 15.869 ;
     RECT  88.308 15.869 93.51 15.899 ;
     RECT  2.304 14.945 8.226 15.961 ;
     RECT  9.108 15.727 9.126 15.961 ;
     RECT  47.376 15.601 47.574 15.997 ;
     RECT  2.304 15.961 9.126 16.069 ;
     RECT  86.688 15.601 86.706 16.069 ;
     RECT  46.764 15.997 47.574 16.105 ;
     RECT  86.652 16.069 86.706 16.105 ;
     RECT  87.48 15.961 87.498 16.105 ;
     RECT  2.304 16.069 9.342 16.109 ;
     RECT  1.152 15.691 1.17 16.123 ;
     RECT  49.104 15.287 49.122 16.267 ;
     RECT  2.304 16.109 9.306 16.295 ;
     RECT  1.152 16.123 1.278 16.301 ;
     RECT  2.304 16.295 8.154 16.301 ;
     RECT  8.964 16.295 9.306 16.331 ;
     RECT  86.652 16.105 87.498 16.331 ;
     RECT  2.304 16.301 8.097 16.367 ;
     RECT  8.964 16.331 9.234 16.367 ;
     RECT  8.964 16.367 9.054 16.403 ;
     RECT  9.036 16.403 9.054 16.439 ;
     RECT  2.304 16.367 5.994 16.529 ;
     RECT  48.924 16.267 49.122 16.529 ;
     RECT  0.324 16.363 0.342 16.541 ;
     RECT  24.015 15.403 24.75 16.541 ;
     RECT  46.764 16.105 48.078 16.601 ;
     RECT  47.808 16.601 48.078 16.645 ;
     RECT  88.308 15.899 91.854 16.645 ;
     RECT  86.544 16.645 86.562 16.685 ;
     RECT  87.48 16.331 87.498 16.709 ;
     RECT  6.804 16.367 8.097 16.799 ;
     RECT  10.8 16.231 10.818 16.807 ;
     RECT  47.808 16.645 48.15 16.843 ;
     RECT  92.916 15.899 93.51 16.843 ;
     RECT  10.764 16.807 10.818 16.979 ;
     RECT  46.764 16.601 46.782 16.979 ;
     RECT  88.308 16.645 92.106 17.035 ;
     RECT  87.66 17.035 92.106 17.041 ;
     RECT  92.88 16.843 93.51 17.041 ;
     RECT  10.8 16.979 10.818 17.069 ;
     RECT  47.808 16.843 48.294 17.069 ;
     RECT  87.66 17.041 93.51 17.165 ;
     RECT  0.252 17.179 0.27 17.309 ;
     RECT  7.128 16.799 8.097 17.347 ;
     RECT  2.304 16.529 5.706 17.419 ;
     RECT  46.908 17.383 46.926 17.419 ;
     RECT  47.808 17.069 48.258 17.419 ;
     RECT  86.976 17.455 86.994 17.563 ;
     RECT  7.128 17.347 8.478 17.581 ;
     RECT  7.128 17.581 9.126 17.609 ;
     RECT  46.908 17.419 48.258 17.609 ;
     RECT  86.832 17.563 86.994 17.609 ;
     RECT  87.768 17.165 93.51 17.609 ;
     RECT  87.876 17.609 93.51 17.645 ;
     RECT  7.128 17.609 8.298 17.651 ;
     RECT  42.804 16.807 42.822 17.681 ;
     RECT  9.108 17.609 9.126 17.689 ;
     RECT  7.128 17.651 8.262 17.789 ;
     RECT  9.108 17.689 9.306 17.789 ;
     RECT  9.108 17.789 9.126 17.951 ;
     RECT  51.015 14.441 51.297 17.959 ;
     RECT  7.164 17.789 8.262 18.023 ;
     RECT  86.652 17.923 86.67 18.059 ;
     RECT  47.376 17.609 48.258 18.149 ;
     RECT  47.592 18.149 47.97 18.221 ;
     RECT  50.652 17.959 51.297 18.221 ;
     RECT  87.912 17.645 93.51 18.221 ;
     RECT  2.304 17.419 6.318 18.265 ;
     RECT  2.304 18.265 6.426 18.283 ;
     RECT  92.916 18.221 93.51 18.283 ;
     RECT  2.268 18.283 6.426 18.329 ;
     RECT  43.884 18.193 43.902 18.419 ;
     RECT  2.304 18.329 6.426 18.535 ;
     RECT  7.164 18.023 8.097 18.535 ;
     RECT  92.916 18.283 94.086 18.563 ;
     RECT  87.912 18.221 91.962 18.599 ;
     RECT  47.664 18.221 47.97 18.689 ;
     RECT  92.916 18.563 93.546 18.761 ;
     RECT  87.912 18.599 91.89 18.811 ;
     RECT  87.192 18.811 91.89 18.841 ;
     RECT  86.724 18.841 91.89 18.845 ;
     RECT  10.764 18.805 10.782 18.959 ;
     RECT  51.015 18.221 51.297 18.967 ;
     RECT  86.724 18.845 87.21 18.967 ;
     RECT  87.948 18.845 91.89 19.031 ;
     RECT  47.664 18.689 47.826 19.067 ;
     RECT  92.952 18.761 93.546 19.067 ;
     RECT  46.872 18.967 46.89 19.111 ;
     RECT  50.724 18.967 51.297 19.139 ;
     RECT  86.652 18.967 87.21 19.265 ;
     RECT  93.492 19.067 93.546 19.291 ;
     RECT  46.764 19.111 46.89 19.309 ;
     RECT  2.304 18.535 8.097 19.337 ;
     RECT  46.692 19.309 46.89 19.381 ;
     RECT  46.692 19.381 46.962 19.409 ;
     RECT  0.252 19.435 0.27 19.565 ;
     RECT  7.74 19.337 8.097 19.571 ;
     RECT  93.492 19.291 94.086 19.571 ;
     RECT  88.128 19.031 91.89 19.651 ;
     RECT  7.812 19.571 8.097 19.679 ;
     RECT  47.88 19.543 48.294 19.769 ;
     RECT  46.764 19.409 46.962 19.813 ;
     RECT  47.88 19.769 48.078 19.813 ;
     RECT  8.892 19.615 8.91 19.877 ;
     RECT  88.128 19.651 92.394 19.885 ;
     RECT  1.152 19.771 1.17 19.901 ;
     RECT  87.948 19.885 92.394 19.913 ;
     RECT  10.8 19.813 10.89 19.949 ;
     RECT  46.764 19.813 48.078 19.949 ;
     RECT  86.652 19.265 86.67 19.949 ;
     RECT  2.304 19.337 6.858 20.011 ;
     RECT  88.815 19.913 92.394 20.011 ;
     RECT  93.492 19.571 93.546 20.011 ;
     RECT  51.015 19.139 51.297 20.047 ;
     RECT  87.948 19.913 88.038 20.047 ;
     RECT  2.268 20.011 6.858 20.048 ;
     RECT  88.815 20.011 93.546 20.111 ;
     RECT  7.815 19.679 8.097 20.191 ;
     RECT  50.616 20.047 51.297 20.219 ;
     RECT  2.304 20.048 6.858 20.237 ;
     RECT  6.48 20.237 6.858 20.281 ;
     RECT  47.196 19.949 48.078 20.309 ;
     RECT  50.688 20.219 51.297 20.381 ;
     RECT  86.724 20.155 86.814 20.425 ;
     RECT  87.588 20.047 88.038 20.425 ;
     RECT  0.252 20.347 0.27 20.477 ;
     RECT  47.988 20.309 48.078 20.579 ;
     RECT  10.8 19.949 10.854 20.587 ;
     RECT  86.724 20.425 88.038 20.615 ;
     RECT  10.764 20.587 10.854 20.651 ;
     RECT  47.196 20.309 47.214 20.695 ;
     RECT  6.48 20.281 6.93 20.731 ;
     RECT  7.815 20.191 8.226 20.731 ;
     RECT  9.144 20.191 9.162 20.731 ;
     RECT  86.724 20.615 86.742 20.731 ;
     RECT  10.764 20.651 10.782 20.849 ;
     RECT  46.764 20.695 47.214 20.885 ;
     RECT  2.304 20.237 5.598 20.923 ;
     RECT  2.268 20.923 5.598 21.053 ;
     RECT  48.888 20.425 48.906 21.119 ;
     RECT  2.304 21.053 5.598 21.127 ;
     RECT  6.48 20.731 8.226 21.127 ;
     RECT  51.015 20.381 51.297 21.127 ;
     RECT  9.108 20.731 9.162 21.163 ;
     RECT  86.652 20.731 86.742 21.227 ;
     RECT  2.304 21.127 8.226 21.235 ;
     RECT  9.108 21.163 9.198 21.235 ;
     RECT  46.8 20.885 47.214 21.235 ;
     RECT  46.8 21.235 47.898 21.299 ;
     RECT  87.948 20.615 88.038 21.361 ;
     RECT  88.815 20.111 93.51 21.361 ;
     RECT  50.724 21.127 51.297 21.389 ;
     RECT  2.304 21.235 9.198 21.437 ;
     RECT  2.376 21.437 9.198 21.461 ;
     RECT  0.216 21.307 0.234 21.485 ;
     RECT  87.948 21.361 93.51 21.533 ;
     RECT  6.516 21.461 9.198 21.659 ;
     RECT  46.908 21.299 47.898 21.659 ;
     RECT  93.492 21.533 93.51 21.73 ;
     RECT  0.288 21.787 0.306 21.883 ;
     RECT  49.32 21.811 49.338 21.929 ;
     RECT  47.268 21.659 47.898 22.009 ;
     RECT  0.288 21.883 0.378 22.013 ;
     RECT  93.492 21.73 93.546 22.027 ;
     RECT  10.8 21.901 10.818 22.037 ;
     RECT  87.948 21.533 92.358 22.037 ;
     RECT  86.652 21.227 86.67 22.045 ;
     RECT  0.288 22.013 0.306 22.061 ;
     RECT  93.492 22.027 94.086 22.073 ;
     RECT  86.652 22.045 86.742 22.109 ;
     RECT  87.948 22.037 92.034 22.199 ;
     RECT  93.492 22.073 93.51 22.235 ;
     RECT  2.376 21.461 5.778 22.243 ;
     RECT  6.516 21.659 8.406 22.243 ;
     RECT  48.924 22.045 48.942 22.469 ;
     RECT  86.688 22.109 86.742 22.513 ;
     RECT  86.688 22.513 87.138 22.549 ;
     RECT  86.688 22.549 87.462 22.589 ;
     RECT  2.376 22.243 8.406 22.621 ;
     RECT  9.18 21.659 9.198 22.621 ;
     RECT  47.268 22.009 48.078 22.747 ;
     RECT  2.376 22.621 9.198 22.855 ;
     RECT  0.252 22.795 0.27 22.925 ;
     RECT  2.376 22.855 9.486 22.981 ;
     RECT  47.268 22.747 48.69 22.981 ;
     RECT  47.088 22.981 48.69 23.009 ;
     RECT  2.376 22.981 9.522 23.035 ;
     RECT  92.916 22.315 92.97 23.035 ;
     RECT  86.688 22.589 87.246 23.125 ;
     RECT  88.815 22.199 92.034 23.125 ;
     RECT  86.148 23.125 87.246 23.165 ;
     RECT  2.268 23.035 9.522 23.189 ;
     RECT  10.836 22.441 10.854 23.189 ;
     RECT  2.268 23.189 9.126 23.213 ;
     RECT  2.304 23.213 9.126 23.279 ;
     RECT  47.088 23.009 47.538 23.279 ;
     RECT  48.672 23.009 48.69 23.279 ;
     RECT  88.632 23.125 92.034 23.287 ;
     RECT  6.408 23.279 9.126 23.315 ;
     RECT  7.776 23.315 9.126 23.351 ;
     RECT  6.408 23.315 6.858 23.357 ;
     RECT  88.2 23.287 92.034 23.431 ;
     RECT  85.5 23.323 85.518 23.459 ;
     RECT  88.056 23.431 92.034 23.467 ;
     RECT  92.916 23.035 93.006 23.467 ;
     RECT  2.304 23.279 5.634 23.549 ;
     RECT  88.056 23.467 93.006 23.593 ;
     RECT  2.304 23.549 5.49 23.621 ;
     RECT  88.056 23.593 93.51 23.645 ;
     RECT  51.015 21.389 51.297 23.665 ;
     RECT  86.652 23.165 87.246 23.692 ;
     RECT  2.304 23.621 5.382 23.693 ;
     RECT  88.056 23.645 93.006 23.693 ;
     RECT  50.796 23.665 51.297 23.701 ;
     RECT  42.768 23.665 42.786 23.891 ;
     RECT  50.688 23.701 51.297 23.891 ;
     RECT  86.652 23.692 87.282 24.061 ;
     RECT  88.056 23.693 92.97 24.061 ;
     RECT  46.764 23.791 46.782 24.089 ;
     RECT  50.724 23.891 51.297 24.161 ;
     RECT  0.324 24.043 0.342 24.173 ;
     RECT  6.624 23.357 6.858 24.205 ;
     RECT  94.068 23.899 94.086 24.233 ;
     RECT  47.808 23.935 47.826 24.241 ;
     RECT  6.228 24.205 6.858 24.283 ;
     RECT  6.228 24.283 6.894 24.331 ;
     RECT  46.728 24.241 46.746 24.359 ;
     RECT  9.216 24.241 9.234 24.395 ;
     RECT  0.252 24.187 0.27 24.413 ;
     RECT  6.12 24.331 6.894 24.467 ;
     RECT  2.304 23.693 5.13 24.469 ;
     RECT  6.12 24.467 6.246 24.469 ;
     RECT  7.776 23.351 8.442 24.511 ;
     RECT  86.652 24.061 92.97 24.619 ;
     RECT  86.652 24.619 93.546 24.653 ;
     RECT  47.7 24.241 47.826 24.709 ;
     RECT  47.664 24.709 47.826 24.745 ;
     RECT  6.984 24.511 8.442 24.781 ;
     RECT  47.484 24.745 47.826 24.781 ;
     RECT  48.672 24.367 48.69 24.781 ;
     RECT  87.696 24.653 93.546 24.797 ;
     RECT  86.652 24.653 86.958 24.809 ;
     RECT  6.984 24.781 8.586 24.899 ;
     RECT  47.484 24.781 48.69 24.899 ;
     RECT  9.432 24.673 9.522 24.935 ;
     RECT  47.484 24.899 47.646 25.007 ;
     RECT  90.18 24.797 93.546 25.043 ;
     RECT  2.304 24.469 6.246 25.051 ;
     RECT  9.432 24.935 9.45 25.079 ;
     RECT  2.268 25.051 6.246 25.088 ;
     RECT  24.015 16.541 24.354 25.099 ;
     RECT  2.304 25.088 6.246 25.169 ;
     RECT  90.18 25.043 93.51 25.169 ;
     RECT  72.615 2.413 72.897 25.321 ;
     RECT  2.34 25.169 6.246 25.349 ;
     RECT  7.815 24.899 8.514 25.349 ;
     RECT  24.015 25.099 24.75 25.439 ;
     RECT  2.412 25.349 6.246 25.555 ;
     RECT  6.984 24.899 7.002 25.555 ;
     RECT  24.015 25.439 24.39 25.661 ;
     RECT  71.964 25.321 72.897 25.672 ;
     RECT  2.412 25.555 7.002 25.681 ;
     RECT  7.815 25.349 8.097 25.681 ;
     RECT  86.688 24.809 86.958 25.681 ;
     RECT  87.696 24.797 89.262 25.681 ;
     RECT  71.964 25.672 73.494 25.709 ;
     RECT  86.688 25.681 89.262 25.723 ;
     RECT  90.54 25.169 93.51 25.771 ;
     RECT  85.896 25.681 85.914 25.789 ;
     RECT  47.628 25.007 47.646 25.861 ;
     RECT  48.384 24.899 48.402 25.861 ;
     RECT  34.815 2.413 35.097 25.951 ;
     RECT  40.215 2.413 40.497 25.951 ;
     RECT  67.215 2.413 67.497 25.951 ;
     RECT  86.688 25.723 89.55 25.951 ;
     RECT  90.54 25.771 93.546 25.951 ;
     RECT  85.716 25.789 85.914 25.979 ;
     RECT  86.688 25.951 93.546 25.979 ;
     RECT  34.704 25.951 35.097 25.997 ;
     RECT  57.672 25.951 57.69 25.997 ;
     RECT  67.104 25.951 67.497 25.997 ;
     RECT  71.964 25.709 72.897 25.997 ;
     RECT  0.252 25.915 0.27 26.045 ;
     RECT  86.688 25.979 87.354 26.051 ;
     RECT  56.415 2.413 56.697 26.053 ;
     RECT  86.688 26.051 87.21 26.059 ;
     RECT  88.092 25.979 93.546 26.059 ;
     RECT  42.768 25.861 42.786 26.087 ;
     RECT  56.124 26.053 56.697 26.093 ;
     RECT  39.924 25.951 40.497 26.096 ;
     RECT  2.412 25.681 8.097 26.131 ;
     RECT  85.716 25.979 85.734 26.141 ;
     RECT  86.652 26.059 87.21 26.141 ;
     RECT  47.016 25.861 48.402 26.159 ;
     RECT  2.412 26.131 8.154 26.221 ;
     RECT  9 26.203 9.018 26.221 ;
     RECT  47.196 26.159 48.402 26.221 ;
     RECT  86.652 26.141 87.066 26.237 ;
     RECT  2.412 26.221 9.306 26.285 ;
     RECT  45.615 3.839 45.897 26.293 ;
     RECT  47.196 26.221 48.474 26.329 ;
     RECT  9 26.285 9.306 26.333 ;
     RECT  2.412 26.285 8.154 26.347 ;
     RECT  88.092 26.059 93.582 26.357 ;
     RECT  47.196 26.329 48.582 26.365 ;
     RECT  9 26.333 9.234 26.393 ;
     RECT  49.536 26.401 49.554 26.519 ;
     RECT  51.015 24.161 51.297 26.671 ;
     RECT  50.688 26.671 51.297 26.789 ;
     RECT  0.54 26.599 0.558 26.827 ;
     RECT  0.252 26.827 0.558 26.957 ;
     RECT  2.304 26.347 8.154 26.969 ;
     RECT  47.196 26.365 48.69 26.969 ;
     RECT  9 26.393 9.018 27.059 ;
     RECT  45.036 26.293 45.897 27.059 ;
     RECT  88.092 26.357 93.546 27.131 ;
     RECT  47.88 26.969 48.69 27.139 ;
     RECT  86.652 26.237 86.814 27.139 ;
     RECT  7.815 26.969 8.154 27.175 ;
     RECT  85.5 26.671 85.518 27.203 ;
     RECT  2.304 26.969 7.074 27.245 ;
     RECT  7.815 27.175 8.514 27.329 ;
     RECT  47.88 27.139 48.942 27.329 ;
     RECT  86.652 27.139 87.318 27.365 ;
     RECT  87.264 27.365 87.318 27.509 ;
     RECT  0.54 26.957 0.558 27.533 ;
     RECT  88.092 27.131 93.51 27.635 ;
     RECT  51.015 26.789 51.297 27.715 ;
     RECT  46.62 27.643 46.638 27.751 ;
     RECT  2.304 27.245 6.93 27.779 ;
     RECT  87.264 27.509 87.282 27.779 ;
     RECT  88.596 27.635 93.51 27.779 ;
     RECT  7.815 27.329 8.37 27.869 ;
     RECT  10.836 27.607 10.854 27.869 ;
     RECT  46.62 27.751 46.746 27.869 ;
     RECT  2.304 27.779 6.786 27.917 ;
     RECT  42.768 27.841 42.786 27.941 ;
     RECT  0.252 27.979 0.27 28.109 ;
     RECT  50.328 27.715 51.297 28.139 ;
     RECT  48.06 27.329 48.33 28.147 ;
     RECT  48.06 28.147 48.798 28.183 ;
     RECT  50.724 28.139 51.297 28.247 ;
     RECT  88.815 27.779 93.51 28.283 ;
     RECT  48.06 28.183 48.834 28.409 ;
     RECT  92.916 28.283 93.51 28.453 ;
     RECT  86.76 28.417 86.778 28.507 ;
     RECT  88.815 28.283 92.142 28.507 ;
     RECT  2.376 27.917 6.786 28.561 ;
     RECT  45.615 27.059 45.897 28.561 ;
     RECT  48.888 28.417 48.906 28.589 ;
     RECT  2.376 28.561 6.858 28.651 ;
     RECT  86.544 28.507 86.778 28.679 ;
     RECT  92.916 28.453 94.086 28.685 ;
     RECT  45.108 28.561 45.897 28.687 ;
     RECT  86.544 28.679 86.706 28.715 ;
     RECT  82.656 28.561 82.674 28.751 ;
     RECT  2.304 28.651 6.858 28.831 ;
     RECT  86.688 28.715 86.706 28.859 ;
     RECT  88.704 28.507 92.142 28.921 ;
     RECT  9.396 28.831 9.486 28.949 ;
     RECT  45.036 28.687 45.897 28.949 ;
     RECT  88.2 28.921 92.142 28.973 ;
     RECT  9.396 28.949 9.414 29.021 ;
     RECT  2.304 28.831 7.074 29.083 ;
     RECT  7.815 27.869 8.154 29.083 ;
     RECT  47.808 28.831 47.826 29.101 ;
     RECT  88.524 28.973 92.142 29.101 ;
     RECT  92.916 28.685 93.546 29.101 ;
     RECT  2.304 29.083 8.154 29.129 ;
     RECT  88.524 29.101 93.546 29.219 ;
     RECT  0.288 29.227 0.306 29.263 ;
     RECT  47.7 29.101 47.826 29.263 ;
     RECT  0.288 29.263 0.378 29.309 ;
     RECT  90 29.219 93.546 29.363 ;
     RECT  0.288 29.309 0.306 29.371 ;
     RECT  47.7 29.263 48.186 29.371 ;
     RECT  0.216 29.371 0.306 29.399 ;
     RECT  0.216 29.399 0.27 29.408 ;
     RECT  42.804 29.227 42.822 29.561 ;
     RECT  47.592 29.371 48.186 29.569 ;
     RECT  47.304 29.569 48.186 29.641 ;
     RECT  88.524 29.219 89.097 29.645 ;
     RECT  46.8 29.641 48.294 29.669 ;
     RECT  9.144 29.641 9.162 29.759 ;
     RECT  48.024 29.669 48.294 29.759 ;
     RECT  51.015 28.247 51.297 29.767 ;
     RECT  50.724 29.767 51.297 29.867 ;
     RECT  2.34 29.129 8.154 29.875 ;
     RECT  0.252 29.408 0.27 29.981 ;
     RECT  86.688 29.803 86.706 30.001 ;
     RECT  87.696 29.767 87.714 30.029 ;
     RECT  90 29.363 93.51 30.029 ;
     RECT  90 30.029 91.782 30.043 ;
     RECT  92.556 30.029 93.51 30.091 ;
     RECT  86.688 30.001 86.922 30.109 ;
     RECT  88.815 29.645 89.097 30.145 ;
     RECT  89.82 30.043 91.782 30.145 ;
     RECT  2.34 29.875 8.406 30.181 ;
     RECT  86.688 30.109 87.246 30.209 ;
     RECT  46.8 29.669 46.854 30.299 ;
     RECT  48.024 29.759 48.186 30.299 ;
     RECT  92.556 30.091 94.086 30.299 ;
     RECT  86.904 30.209 87.246 30.365 ;
     RECT  2.34 30.181 8.55 30.479 ;
     RECT  92.916 30.299 94.086 30.523 ;
     RECT  2.34 30.479 8.19 30.541 ;
     RECT  2.304 30.541 8.19 30.569 ;
     RECT  2.304 30.569 7.038 30.605 ;
     RECT  9.144 30.811 9.198 30.911 ;
     RECT  87.084 30.365 87.246 30.941 ;
     RECT  92.916 30.523 94.122 30.983 ;
     RECT  48.708 30.649 48.726 30.991 ;
     RECT  49.536 30.847 49.554 30.991 ;
     RECT  88.815 30.145 91.782 30.991 ;
     RECT  88.56 30.991 91.782 31.081 ;
     RECT  47.916 30.883 47.934 31.109 ;
     RECT  88.2 31.081 91.782 31.117 ;
     RECT  2.304 30.605 6.894 31.145 ;
     RECT  9.144 30.911 9.162 31.217 ;
     RECT  46.836 30.299 46.854 31.225 ;
     RECT  0.252 31.099 0.27 31.229 ;
     RECT  48.708 30.991 49.554 31.261 ;
     RECT  2.304 31.145 6.858 31.289 ;
     RECT  86.652 31.189 86.67 31.289 ;
     RECT  88.056 31.117 91.782 31.339 ;
     RECT  87.408 31.339 91.782 31.351 ;
     RECT  92.916 30.983 94.086 31.351 ;
     RECT  48.708 31.261 49.59 31.379 ;
     RECT  46.836 31.225 47.214 31.387 ;
     RECT  51.015 29.867 51.297 31.387 ;
     RECT  48.708 31.379 49.446 31.495 ;
     RECT  87.408 31.351 94.086 31.523 ;
     RECT  7.815 30.569 8.19 31.531 ;
     RECT  9.108 31.387 9.126 31.531 ;
     RECT  9.036 31.531 9.126 31.559 ;
     RECT  48.636 31.495 49.446 31.559 ;
     RECT  50.796 31.387 51.297 31.559 ;
     RECT  7.815 31.531 8.262 31.649 ;
     RECT  87.408 31.523 93.582 31.649 ;
     RECT  87.408 31.649 88.002 31.729 ;
     RECT  0.288 31.387 0.45 31.801 ;
     RECT  9.036 31.559 9.054 31.829 ;
     RECT  46.8 31.387 47.214 31.919 ;
     RECT  7.815 31.649 8.19 31.927 ;
     RECT  2.34 31.289 6.858 31.963 ;
     RECT  7.596 31.927 8.19 31.963 ;
     RECT  48.636 31.559 49.41 31.963 ;
     RECT  86.688 31.729 88.002 32.045 ;
     RECT  86.688 32.045 87.318 32.071 ;
     RECT  88.776 31.649 93.582 32.099 ;
     RECT  48.204 31.963 49.41 32.189 ;
     RECT  46.8 31.919 46.854 32.233 ;
     RECT  0.288 31.801 0.558 32.299 ;
     RECT  45.615 28.949 45.897 32.341 ;
     RECT  46.764 32.233 46.854 32.341 ;
     RECT  10.8 31.387 10.818 32.369 ;
     RECT  89.892 32.099 93.582 32.395 ;
     RECT  0.252 32.299 0.558 32.429 ;
     RECT  2.34 31.963 8.19 32.459 ;
     RECT  9.144 32.341 9.162 32.459 ;
     RECT  48.24 32.189 49.338 32.459 ;
     RECT  45.615 32.341 46.854 32.495 ;
     RECT  2.34 32.459 7.074 32.611 ;
     RECT  88.776 32.099 89.097 32.611 ;
     RECT  0.54 32.429 0.558 32.717 ;
     RECT  45.615 32.495 46.782 32.729 ;
     RECT  48.24 32.459 49.014 32.729 ;
     RECT  85.5 32.233 85.518 32.737 ;
     RECT  86.652 32.071 87.318 32.737 ;
     RECT  89.892 32.395 94.086 32.801 ;
     RECT  85.5 32.737 87.318 32.809 ;
     RECT  88.236 32.611 89.097 32.827 ;
     RECT  89.892 32.801 93.51 32.827 ;
     RECT  85.5 32.809 87.462 32.909 ;
     RECT  86.22 32.909 87.462 32.999 ;
     RECT  88.236 32.827 93.51 33.043 ;
     RECT  86.22 32.999 86.67 33.053 ;
     RECT  87.768 33.043 93.51 33.071 ;
     RECT  7.815 32.459 8.19 33.115 ;
     RECT  7.815 33.115 8.514 33.269 ;
     RECT  2.304 32.611 7.074 33.385 ;
     RECT  7.815 33.269 8.19 33.385 ;
     RECT  0.216 33.307 0.234 33.437 ;
     RECT  86.652 33.053 86.67 33.449 ;
     RECT  89.892 33.071 93.51 33.449 ;
     RECT  51.015 31.559 51.297 33.511 ;
     RECT  2.304 33.385 8.19 33.539 ;
     RECT  9.324 33.349 9.342 33.539 ;
     RECT  46.764 32.729 46.782 33.539 ;
     RECT  90.036 33.449 93.51 33.547 ;
     RECT  50.724 33.511 51.297 33.611 ;
     RECT  48.672 32.729 49.014 33.655 ;
     RECT  87.768 33.071 89.097 33.787 ;
     RECT  46.8 33.781 46.818 33.881 ;
     RECT  90.036 33.547 93.546 33.881 ;
     RECT  9.144 33.691 9.234 33.917 ;
     RECT  0.252 33.691 0.27 33.931 ;
     RECT  0.252 33.931 0.342 33.989 ;
     RECT  86.868 33.787 89.097 33.989 ;
     RECT  0.252 33.989 0.27 34.013 ;
     RECT  9.144 33.917 9.162 34.079 ;
     RECT  48.672 33.655 49.086 34.087 ;
     RECT  48.456 34.087 49.086 34.219 ;
     RECT  2.415 33.539 8.19 34.393 ;
     RECT  48.384 34.219 49.086 34.393 ;
     RECT  88.092 33.989 89.097 34.393 ;
     RECT  86.868 33.989 87.318 34.429 ;
     RECT  48.024 34.393 49.086 34.445 ;
     RECT  48.348 34.445 49.086 34.465 ;
     RECT  88.092 34.393 89.19 34.465 ;
     RECT  90.036 33.881 93.51 34.465 ;
     RECT  2.415 34.393 8.694 34.529 ;
     RECT  0.216 34.459 0.234 34.589 ;
     RECT  48.348 34.465 49.338 34.619 ;
     RECT  45.615 32.729 45.897 34.627 ;
     RECT  51.015 33.611 51.297 34.627 ;
     RECT  2.415 34.529 8.658 34.691 ;
     RECT  50.724 34.627 51.297 34.727 ;
     RECT  2.415 34.691 8.097 34.771 ;
     RECT  86.688 34.429 87.318 34.771 ;
     RECT  88.092 34.465 93.51 34.771 ;
     RECT  2.412 34.771 8.097 34.843 ;
     RECT  45.615 34.627 46.206 34.861 ;
     RECT  46.98 34.663 46.998 34.861 ;
     RECT  48.348 34.619 48.618 34.889 ;
     RECT  45.615 34.861 46.998 34.961 ;
     RECT  48.456 34.889 48.618 34.961 ;
     RECT  2.304 34.843 8.097 34.987 ;
     RECT  86.688 34.771 93.51 34.987 ;
     RECT  86.688 34.987 93.546 35.041 ;
     RECT  2.16 34.987 8.097 35.159 ;
     RECT  42.768 34.969 42.786 35.159 ;
     RECT  86.652 35.041 93.546 35.275 ;
     RECT  46.8 34.961 46.998 35.311 ;
     RECT  86.652 35.275 94.086 35.323 ;
     RECT  85.968 35.323 94.086 35.357 ;
     RECT  88.815 35.357 94.086 35.537 ;
     RECT  46.8 35.311 47.286 35.573 ;
     RECT  85.968 35.357 86.994 35.699 ;
     RECT  46.872 35.573 47.286 35.707 ;
     RECT  6.732 35.159 8.097 35.743 ;
     RECT  48.456 34.961 48.474 35.743 ;
     RECT  2.16 35.159 5.958 35.755 ;
     RECT  48.456 35.743 49.122 35.851 ;
     RECT  2.016 35.755 5.958 35.885 ;
     RECT  2.304 35.885 5.958 35.941 ;
     RECT  6.732 35.743 8.262 35.941 ;
     RECT  2.304 35.941 8.262 36.091 ;
     RECT  48.348 35.851 49.122 36.149 ;
     RECT  88.815 35.537 93.51 36.235 ;
     RECT  46.872 35.707 47.322 36.239 ;
     RECT  48.888 36.149 49.122 36.239 ;
     RECT  86.652 35.699 86.994 36.283 ;
     RECT  87.804 35.357 87.822 36.283 ;
     RECT  2.304 36.091 8.298 36.311 ;
     RECT  7.38 36.311 8.298 36.391 ;
     RECT  86.652 36.283 87.822 36.419 ;
     RECT  7.38 36.391 8.622 36.461 ;
     RECT  49.104 36.239 49.122 36.481 ;
     RECT  88.812 36.235 93.51 36.481 ;
     RECT  47.88 36.283 48.114 36.509 ;
     RECT  49.104 36.481 49.194 36.581 ;
     RECT  88.128 36.481 93.51 36.581 ;
     RECT  86.652 36.419 87.39 36.689 ;
     RECT  86.76 36.689 87.39 36.779 ;
     RECT  51.015 34.727 51.297 36.787 ;
     RECT  83.415 6.989 83.697 36.787 ;
     RECT  86.76 36.779 87.282 36.851 ;
     RECT  88.164 36.581 93.51 36.851 ;
     RECT  2.304 36.311 6.57 36.896 ;
     RECT  0.252 36.619 0.27 36.907 ;
     RECT  48.024 36.509 48.114 36.931 ;
     RECT  0.216 36.907 0.27 37.037 ;
     RECT  82.728 36.787 83.697 37.049 ;
     RECT  48.024 36.931 48.258 37.129 ;
     RECT  7.38 36.461 8.097 37.201 ;
     RECT  88.2 36.851 93.51 37.229 ;
     RECT  50.796 36.787 51.297 37.291 ;
     RECT  48.024 37.129 48.906 37.319 ;
     RECT  0.252 37.037 0.27 37.421 ;
     RECT  6.804 37.201 8.097 37.471 ;
     RECT  48.024 37.319 48.51 37.471 ;
     RECT  6.804 37.471 8.406 37.625 ;
     RECT  46.764 36.481 46.782 37.625 ;
     RECT  88.308 37.229 93.51 37.625 ;
     RECT  47.844 37.471 48.51 37.669 ;
     RECT  87.12 36.851 87.282 37.741 ;
     RECT  47.52 37.669 48.51 37.859 ;
     RECT  8.856 37.831 8.874 37.931 ;
     RECT  86.652 37.741 87.282 37.931 ;
     RECT  2.304 36.896 5.886 38.011 ;
     RECT  6.804 37.625 8.097 38.011 ;
     RECT  50.724 37.291 51.297 38.101 ;
     RECT  87.048 37.931 87.282 38.129 ;
     RECT  2.304 38.011 8.097 38.209 ;
     RECT  47.52 37.859 47.79 38.209 ;
     RECT  88.308 37.625 92.178 38.281 ;
     RECT  2.268 38.209 8.097 38.333 ;
     RECT  87.804 38.281 92.178 38.443 ;
     RECT  92.916 37.625 93.51 38.443 ;
     RECT  43.884 37.867 43.902 38.471 ;
     RECT  50.688 38.101 51.297 38.507 ;
     RECT  2.304 38.333 8.097 38.515 ;
     RECT  46.8 38.209 47.79 38.515 ;
     RECT  86.076 38.101 86.094 38.543 ;
     RECT  87.804 38.443 93.51 38.587 ;
     RECT  46.764 38.515 47.79 38.641 ;
     RECT  2.304 38.515 8.154 38.669 ;
     RECT  8.928 38.551 8.946 38.669 ;
     RECT  46.764 38.641 48.33 38.669 ;
     RECT  87.804 38.587 94.086 38.741 ;
     RECT  87.048 38.129 87.066 38.785 ;
     RECT  86.832 38.785 87.066 38.813 ;
     RECT  86.832 38.813 86.85 38.821 ;
     RECT  0.252 38.779 0.27 38.909 ;
     RECT  46.764 38.669 47.25 38.939 ;
     RECT  87.804 38.741 93.51 38.947 ;
     RECT  87.624 38.947 93.51 39.011 ;
     RECT  48.312 38.669 48.33 39.119 ;
     RECT  42.84 39.451 42.858 39.487 ;
     RECT  42.84 39.487 42.894 39.523 ;
     RECT  86.652 38.821 86.85 39.559 ;
     RECT  87.624 39.011 92.142 39.559 ;
     RECT  50.724 38.507 51.297 39.587 ;
     RECT  92.916 39.011 93.51 39.623 ;
     RECT  10.728 39.451 10.746 39.631 ;
     RECT  49.32 39.325 49.338 39.631 ;
     RECT  10.728 39.631 10.818 39.659 ;
     RECT  42.768 39.523 42.894 39.659 ;
     RECT  93.492 39.623 93.51 39.739 ;
     RECT  10.8 39.659 10.818 39.749 ;
     RECT  49.212 39.631 49.338 39.749 ;
     RECT  86.652 39.559 92.142 39.749 ;
     RECT  47.232 38.939 47.25 39.793 ;
     RECT  46.764 39.793 47.25 39.829 ;
     RECT  87.588 39.749 92.142 39.883 ;
     RECT  2.34 38.669 8.097 39.901 ;
     RECT  2.304 39.901 8.097 40.019 ;
     RECT  46.764 39.829 47.502 40.019 ;
     RECT  48.276 39.721 48.294 40.019 ;
     RECT  0.324 40.027 0.342 40.063 ;
     RECT  0.324 40.063 0.414 40.109 ;
     RECT  87.588 39.883 92.358 40.127 ;
     RECT  0.324 40.109 0.342 40.171 ;
     RECT  0.216 40.171 0.342 40.199 ;
     RECT  86.652 39.749 86.778 40.199 ;
     RECT  0.216 40.199 0.27 40.208 ;
     RECT  2.34 40.019 8.097 40.219 ;
     RECT  2.34 40.219 8.226 40.289 ;
     RECT  9.216 40.063 9.234 40.433 ;
     RECT  87.804 40.127 92.358 40.459 ;
     RECT  46.8 40.019 46.818 40.469 ;
     RECT  86.688 40.199 86.778 40.555 ;
     RECT  43.884 40.333 43.902 40.559 ;
     RECT  2.376 40.289 8.097 40.631 ;
     RECT  42.768 39.659 42.858 40.667 ;
     RECT  2.376 40.631 5.994 40.781 ;
     RECT  47.592 40.405 47.682 40.801 ;
     RECT  10.8 40.711 10.818 40.829 ;
     RECT  42.804 40.667 42.858 40.829 ;
     RECT  47.592 40.801 48.042 40.829 ;
     RECT  51.015 39.587 51.297 40.837 ;
     RECT  87.804 40.459 92.394 40.891 ;
     RECT  93.492 39.739 93.546 40.891 ;
     RECT  82.656 40.603 82.674 40.901 ;
     RECT  42.804 40.829 42.822 40.937 ;
     RECT  50.688 40.837 51.297 40.937 ;
     RECT  86.688 40.555 87.03 40.973 ;
     RECT  2.376 40.781 5.814 41.035 ;
     RECT  87.012 40.973 87.03 41.035 ;
     RECT  87.804 40.891 93.546 41.035 ;
     RECT  48.024 40.829 48.042 41.099 ;
     RECT  6.84 40.631 8.097 41.143 ;
     RECT  87.012 41.035 93.546 41.171 ;
     RECT  49.212 40.945 49.23 41.251 ;
     RECT  0.252 40.208 0.27 41.323 ;
     RECT  0.216 41.323 0.27 41.453 ;
     RECT  6.84 41.143 8.586 41.477 ;
     RECT  87.012 41.171 93.51 41.477 ;
     RECT  50.724 40.937 51.297 41.549 ;
     RECT  48.888 41.251 49.23 41.639 ;
     RECT  2.304 41.035 5.814 41.647 ;
     RECT  6.84 41.477 8.154 41.683 ;
     RECT  0.252 41.453 0.27 41.741 ;
     RECT  6.768 41.683 8.154 41.755 ;
     RECT  48.06 41.611 48.078 41.755 ;
     RECT  2.304 41.647 5.886 41.791 ;
     RECT  6.66 41.755 8.154 41.791 ;
     RECT  84.924 41.251 84.942 41.819 ;
     RECT  88.092 41.477 93.51 41.899 ;
     RECT  48.06 41.755 48.582 41.909 ;
     RECT  88.092 41.899 93.546 41.981 ;
     RECT  87.012 41.477 87.246 41.989 ;
     RECT  86.94 41.989 87.246 42.061 ;
     RECT  50.796 41.549 51.297 42.089 ;
     RECT  9.072 42.061 9.09 42.151 ;
     RECT  9.072 42.151 9.162 42.179 ;
     RECT  9.144 42.179 9.162 42.187 ;
     RECT  46.764 41.953 46.782 42.223 ;
     RECT  86.868 42.061 87.246 42.223 ;
     RECT  46.764 42.223 46.926 42.295 ;
     RECT  42.804 42.223 42.822 42.323 ;
     RECT  2.304 41.791 8.154 42.331 ;
     RECT  86.868 42.223 87.354 42.331 ;
     RECT  88.092 41.981 93.51 42.331 ;
     RECT  9.144 42.187 9.234 42.521 ;
     RECT  46.764 42.295 46.998 42.529 ;
     RECT  48.348 41.909 48.582 42.565 ;
     RECT  49.536 41.953 49.554 42.565 ;
     RECT  2.304 42.331 8.226 42.593 ;
     RECT  82.656 42.061 82.674 42.601 ;
     RECT  83.415 37.049 83.697 42.601 ;
     RECT  82.656 42.601 83.697 42.629 ;
     RECT  2.304 42.593 6.93 42.719 ;
     RECT  46.764 42.529 47.214 42.719 ;
     RECT  48.348 42.565 49.554 42.719 ;
     RECT  86.868 42.331 93.51 42.719 ;
     RECT  0.216 42.619 0.234 42.749 ;
     RECT  46.764 42.719 46.782 42.755 ;
     RECT  82.728 42.629 83.697 42.755 ;
     RECT  48.348 42.719 48.654 42.989 ;
     RECT  49.536 42.719 49.554 42.989 ;
     RECT  84.96 42.871 84.978 43.069 ;
     RECT  9.144 42.521 9.162 43.141 ;
     RECT  0.252 43.099 0.27 43.229 ;
     RECT  87.228 42.719 93.51 43.259 ;
     RECT  84.924 43.069 84.978 43.331 ;
     RECT  2.304 42.719 6.822 43.573 ;
     RECT  8.964 43.141 9.162 43.573 ;
     RECT  42.804 43.537 42.822 43.637 ;
     RECT  87.804 43.259 93.51 43.673 ;
     RECT  2.304 43.573 6.858 43.681 ;
     RECT  7.776 42.593 8.226 43.681 ;
     RECT  43.884 43.231 43.902 43.709 ;
     RECT  88.056 43.673 93.51 43.709 ;
     RECT  2.304 43.681 8.226 43.771 ;
     RECT  88.056 43.709 92.322 43.799 ;
     RECT  46.836 43.645 46.854 43.807 ;
     RECT  2.268 43.771 8.226 43.808 ;
     RECT  88.164 43.799 92.07 43.835 ;
     RECT  2.304 43.808 8.226 43.843 ;
     RECT  8.964 43.573 9.45 43.843 ;
     RECT  46.836 43.807 47.286 43.843 ;
     RECT  2.304 43.843 9.45 43.871 ;
     RECT  88.164 43.835 91.998 43.871 ;
     RECT  86.544 43.537 86.562 43.879 ;
     RECT  46.836 43.843 47.826 43.951 ;
     RECT  2.304 43.871 8.982 44.069 ;
     RECT  46.836 43.951 48.33 44.069 ;
     RECT  46.836 44.069 47.286 44.077 ;
     RECT  86.472 43.879 86.562 44.077 ;
     RECT  46.764 44.077 47.286 44.141 ;
     RECT  83.415 42.755 83.697 44.149 ;
     RECT  86.328 44.077 86.562 44.185 ;
     RECT  87.3 44.149 87.318 44.185 ;
     RECT  0.396 44.203 0.414 44.221 ;
     RECT  84.924 43.331 84.942 44.221 ;
     RECT  82.728 44.149 83.697 44.249 ;
     RECT  51.015 42.089 51.297 44.311 ;
     RECT  46.764 44.141 46.854 44.339 ;
     RECT  84.924 44.221 85.014 44.339 ;
     RECT  0.396 44.221 0.558 44.347 ;
     RECT  93.492 43.709 93.51 44.347 ;
     RECT  88.164 43.871 91.782 44.375 ;
     RECT  86.328 44.185 87.318 44.411 ;
     RECT  0.288 44.347 0.558 44.477 ;
     RECT  86.328 44.411 87.174 44.477 ;
     RECT  48.312 44.069 48.33 44.491 ;
     RECT  93.492 44.347 93.546 44.491 ;
     RECT  2.304 44.069 8.946 44.753 ;
     RECT  10.908 44.581 10.926 44.753 ;
     RECT  88.344 44.375 91.782 44.761 ;
     RECT  93.492 44.491 94.086 44.779 ;
     RECT  0.54 44.477 0.558 44.813 ;
     RECT  48.312 44.491 48.798 44.879 ;
     RECT  86.904 44.477 87.174 44.879 ;
     RECT  84.924 44.339 84.978 44.915 ;
     RECT  86.904 44.879 86.922 44.957 ;
     RECT  7.092 44.753 8.946 44.987 ;
     RECT  50.724 44.311 51.297 44.987 ;
     RECT  88.344 44.761 92.142 45.023 ;
     RECT  7.092 44.987 8.37 45.059 ;
     RECT  93.492 44.779 94.158 45.067 ;
     RECT  43.884 44.725 43.902 45.149 ;
     RECT  48.312 44.879 48.366 45.149 ;
     RECT  92.916 45.067 94.158 45.157 ;
     RECT  83.415 44.249 83.697 45.229 ;
     RECT  92.664 45.157 94.158 45.257 ;
     RECT  92.664 45.257 94.086 45.293 ;
     RECT  82.728 45.229 83.697 45.329 ;
     RECT  88.344 45.023 91.926 45.419 ;
     RECT  46.836 44.339 46.854 45.463 ;
     RECT  47.628 45.265 47.646 45.463 ;
     RECT  42.768 45.265 42.786 45.491 ;
     RECT  0.288 45.259 0.414 45.533 ;
     RECT  2.304 44.753 5.922 45.571 ;
     RECT  85.5 45.121 85.698 45.581 ;
     RECT  88.344 45.419 91.602 45.725 ;
     RECT  86.508 45.229 86.526 45.733 ;
     RECT  87.552 45.697 87.57 45.769 ;
     RECT  88.344 45.725 90.63 45.769 ;
     RECT  46.836 45.463 47.646 45.833 ;
     RECT  46.836 45.833 46.854 45.841 ;
     RECT  87.552 45.769 90.63 45.869 ;
     RECT  86.04 45.733 86.526 45.883 ;
     RECT  49.428 45.571 49.446 45.959 ;
     RECT  2.304 45.571 5.994 45.995 ;
     RECT  9.144 45.301 9.234 45.995 ;
     RECT  10.8 45.121 10.818 45.995 ;
     RECT  7.128 45.059 8.37 46.003 ;
     RECT  7.128 46.003 9.126 46.027 ;
     RECT  84.924 45.841 84.942 46.031 ;
     RECT  47.592 45.833 47.646 46.075 ;
     RECT  46.8 45.841 46.854 46.103 ;
     RECT  47.592 46.075 48.186 46.111 ;
     RECT  92.664 45.293 93.51 46.111 ;
     RECT  6.588 46.027 9.126 46.157 ;
     RECT  86.04 45.883 86.634 46.171 ;
     RECT  87.552 45.869 90.558 46.171 ;
     RECT  86.04 46.171 90.558 46.205 ;
     RECT  47.592 46.111 48.582 46.229 ;
     RECT  86.04 46.205 87.822 46.229 ;
     RECT  92.52 46.111 93.51 46.229 ;
     RECT  92.916 46.229 93.51 46.363 ;
     RECT  86.04 46.229 86.058 46.373 ;
     RECT  48.564 46.229 48.582 46.381 ;
     RECT  91.476 45.725 91.602 46.381 ;
     RECT  9.108 46.157 9.126 46.409 ;
     RECT  47.592 46.229 47.61 46.499 ;
     RECT  86.94 46.229 87.822 46.499 ;
     RECT  46.8 46.103 46.818 46.507 ;
     RECT  45.615 34.961 45.897 46.543 ;
     RECT  46.764 46.507 46.818 46.543 ;
     RECT  88.56 46.205 90.558 46.651 ;
     RECT  0.252 46.555 0.27 46.685 ;
     RECT  2.304 45.995 5.67 46.741 ;
     RECT  45.615 46.543 46.818 46.769 ;
     RECT  48.564 46.381 49.266 46.769 ;
     RECT  87.444 46.499 87.822 46.769 ;
     RECT  51.015 44.987 51.297 46.777 ;
     RECT  91.476 46.381 91.782 46.777 ;
     RECT  2.304 46.741 5.778 46.795 ;
     RECT  6.588 46.157 8.226 46.795 ;
     RECT  88.56 46.651 90.63 46.795 ;
     RECT  10.836 46.741 10.854 46.877 ;
     RECT  88.56 46.795 90.666 46.921 ;
     RECT  91.476 46.777 92.07 46.921 ;
     RECT  2.304 46.795 8.226 46.949 ;
     RECT  50.724 46.777 51.297 47.011 ;
     RECT  87.588 46.769 87.822 47.035 ;
     RECT  88.56 46.921 92.07 47.035 ;
     RECT  46.8 46.769 46.818 47.039 ;
     RECT  48.564 46.769 49.05 47.047 ;
     RECT  9.216 46.885 9.234 47.075 ;
     RECT  10.764 47.047 10.782 47.147 ;
     RECT  50.616 47.011 51.297 47.155 ;
     RECT  48.456 47.047 49.05 47.317 ;
     RECT  50.436 47.155 51.297 47.425 ;
     RECT  92.916 46.363 94.086 47.453 ;
     RECT  2.304 46.949 6.75 47.515 ;
     RECT  87.588 47.035 92.07 47.515 ;
     RECT  87.588 47.515 92.754 47.579 ;
     RECT  84.924 47.461 84.942 47.587 ;
     RECT  7.524 46.949 8.226 47.695 ;
     RECT  9.108 47.317 9.126 47.695 ;
     RECT  2.268 47.515 6.75 47.707 ;
     RECT  2.052 47.707 6.75 47.731 ;
     RECT  2.052 47.731 6.786 47.837 ;
     RECT  47.952 47.317 49.05 47.848 ;
     RECT  47.88 47.848 49.05 47.851 ;
     RECT  50.364 47.425 51.297 47.851 ;
     RECT  47.88 47.851 51.297 47.891 ;
     RECT  7.524 47.695 9.126 47.929 ;
     RECT  47.88 47.891 49.122 47.929 ;
     RECT  2.268 47.837 6.786 48.001 ;
     RECT  7.524 47.929 9.306 48.001 ;
     RECT  2.268 48.001 9.306 48.029 ;
     RECT  47.7 47.929 49.122 48.119 ;
     RECT  47.7 48.119 47.826 48.163 ;
     RECT  2.268 48.029 9.126 48.191 ;
     RECT  93.492 47.453 94.086 48.191 ;
     RECT  47.664 48.163 47.826 48.199 ;
     RECT  90.108 47.579 92.754 48.235 ;
     RECT  93.492 48.191 93.546 48.235 ;
     RECT  47.592 48.199 47.826 48.299 ;
     RECT  87.66 47.579 89.298 48.379 ;
     RECT  90.108 48.235 93.546 48.389 ;
     RECT  87.228 48.379 89.298 48.425 ;
     RECT  2.304 48.191 9.126 48.461 ;
     RECT  87.408 48.425 89.298 48.461 ;
     RECT  47.592 48.299 47.754 48.469 ;
     RECT  47.52 48.469 47.754 48.505 ;
     RECT  88.815 48.461 89.298 48.505 ;
     RECT  90.108 48.389 92.106 48.505 ;
     RECT  84.924 47.587 85.014 48.731 ;
     RECT  92.916 48.389 93.546 48.803 ;
     RECT  0.216 48.715 0.234 48.811 ;
     RECT  84.924 48.731 84.942 48.839 ;
     RECT  7.815 48.461 9.126 48.929 ;
     RECT  48.6 48.119 49.122 48.929 ;
     RECT  0.216 48.811 0.414 48.989 ;
     RECT  46.8 48.505 47.754 49.001 ;
     RECT  47.52 49.001 47.754 49.081 ;
     RECT  48.6 48.929 48.69 49.081 ;
     RECT  88.815 48.505 92.106 49.171 ;
     RECT  92.916 48.803 93.51 49.171 ;
     RECT  50.004 47.891 51.297 49.199 ;
     RECT  88.815 49.171 93.51 49.207 ;
     RECT  0.252 48.989 0.27 49.229 ;
     RECT  50.724 49.199 51.297 49.307 ;
     RECT  7.815 48.929 8.766 49.315 ;
     RECT  87.408 48.461 87.426 49.315 ;
     RECT  86.652 49.279 86.67 49.351 ;
     RECT  87.408 49.315 87.57 49.351 ;
     RECT  47.52 49.081 48.69 49.469 ;
     RECT  86.652 49.351 87.57 49.469 ;
     RECT  7.812 49.315 8.766 49.541 ;
     RECT  88.344 49.207 93.51 49.675 ;
     RECT  47.52 49.469 48.546 49.739 ;
     RECT  42.768 49.747 42.786 49.847 ;
     RECT  47.772 49.739 48.546 49.847 ;
     RECT  2.304 48.461 7.074 49.855 ;
     RECT  7.812 49.541 8.37 49.855 ;
     RECT  88.344 49.675 93.546 50.009 ;
     RECT  46.764 49.585 46.782 50.081 ;
     RECT  88.344 50.009 89.262 50.155 ;
     RECT  48.06 49.847 48.546 50.323 ;
     RECT  10.8 50.161 10.89 50.351 ;
     RECT  0.252 50.251 0.27 50.381 ;
     RECT  9.36 50.287 9.378 50.459 ;
     RECT  10.836 50.351 10.89 50.459 ;
     RECT  82.656 50.359 82.674 50.459 ;
     RECT  48.06 50.323 48.582 50.549 ;
     RECT  88.164 50.155 89.262 50.585 ;
     RECT  48.564 50.549 48.582 50.701 ;
     RECT  88.815 50.585 89.262 50.729 ;
     RECT  48.564 50.701 48.726 50.819 ;
     RECT  49.464 50.665 49.482 50.819 ;
     RECT  51.015 49.307 51.297 50.827 ;
     RECT  86.652 49.469 87.426 50.827 ;
     RECT  90.036 50.009 93.546 50.827 ;
     RECT  47.52 50.827 47.538 50.863 ;
     RECT  10.836 50.459 10.854 50.891 ;
     RECT  2.304 49.855 8.37 50.971 ;
     RECT  47.232 50.863 47.538 51.061 ;
     RECT  2.304 50.971 8.694 51.089 ;
     RECT  46.764 51.061 47.538 51.359 ;
     RECT  50.796 50.827 51.297 51.367 ;
     RECT  86.652 50.827 87.786 51.367 ;
     RECT  90 50.827 93.546 51.403 ;
     RECT  50.652 51.367 51.297 51.467 ;
     RECT  8.964 51.439 8.982 51.475 ;
     RECT  88.815 50.729 89.226 51.511 ;
     RECT  90 51.403 94.086 51.511 ;
     RECT  46.764 51.359 47.25 51.539 ;
     RECT  48.024 51.601 48.15 51.709 ;
     RECT  8.964 51.475 9.018 51.737 ;
     RECT  86.076 51.367 87.786 51.773 ;
     RECT  46.764 51.539 46.818 51.781 ;
     RECT  9 51.737 9.018 51.809 ;
     RECT  46.656 51.781 46.818 51.899 ;
     RECT  87.228 51.773 87.786 51.943 ;
     RECT  88.704 51.511 94.086 51.943 ;
     RECT  50.724 51.467 51.297 51.971 ;
     RECT  86.076 51.773 86.094 52.007 ;
     RECT  46.764 51.899 46.818 52.043 ;
     RECT  48.024 51.709 48.69 52.213 ;
     RECT  46.764 52.043 46.782 52.241 ;
     RECT  2.304 51.089 7.074 52.249 ;
     RECT  7.815 51.089 8.226 52.249 ;
     RECT  48.024 52.213 48.942 52.321 ;
     RECT  10.8 51.601 10.818 52.349 ;
     RECT  13.215 2.413 13.497 52.411 ;
     RECT  24.015 25.661 24.354 52.411 ;
     RECT  34.815 25.997 35.097 52.411 ;
     RECT  45.615 46.769 45.897 52.411 ;
     RECT  48.024 52.321 49.194 52.411 ;
     RECT  2.304 52.249 8.226 52.439 ;
     RECT  48.024 52.411 49.266 52.448 ;
     RECT  13.104 52.411 13.497 52.475 ;
     RECT  23.904 52.411 24.354 52.475 ;
     RECT  34.704 52.411 35.097 52.475 ;
     RECT  87.228 51.943 94.086 52.591 ;
     RECT  7.815 52.439 8.226 52.681 ;
     RECT  48.024 52.448 49.014 52.709 ;
     RECT  50.796 51.971 51.297 52.717 ;
     RECT  45.504 52.411 45.897 52.789 ;
     RECT  50.724 52.717 51.297 52.817 ;
     RECT  86.652 52.591 94.086 52.853 ;
     RECT  0.252 51.739 0.27 52.877 ;
     RECT  48.024 52.709 48.474 52.889 ;
     RECT  86.976 52.853 94.086 52.889 ;
     RECT  48.024 52.889 48.042 53.249 ;
     RECT  49.86 53.131 49.878 53.249 ;
     RECT  86.976 52.889 92.682 53.249 ;
     RECT  85.14 53.023 85.158 53.329 ;
     RECT  2.304 52.439 6.858 53.365 ;
     RECT  7.815 52.681 8.37 53.365 ;
     RECT  85.068 53.329 85.158 53.393 ;
     RECT  85.068 53.393 85.086 53.401 ;
     RECT  84.924 53.401 85.086 53.519 ;
     RECT  84.924 53.519 85.014 53.555 ;
     RECT  45.036 52.789 45.897 53.591 ;
     RECT  84.924 53.555 84.942 53.591 ;
     RECT  86.976 53.249 87.21 53.597 ;
     RECT  2.304 53.365 8.37 53.627 ;
     RECT  51.015 52.817 51.297 53.635 ;
     RECT  88.344 53.249 92.682 53.707 ;
     RECT  93.492 52.889 94.086 53.707 ;
     RECT  50.832 53.635 51.297 53.833 ;
     RECT  48.492 53.671 48.51 53.905 ;
     RECT  6.696 53.627 8.37 53.933 ;
     RECT  46.764 53.365 46.782 53.941 ;
     RECT  48.492 53.905 49.05 53.969 ;
     RECT  0.252 53.899 0.27 54.029 ;
     RECT  48.6 53.969 49.05 54.031 ;
     RECT  46.764 53.941 46.818 54.059 ;
     RECT  50.076 53.833 51.297 54.059 ;
     RECT  88.344 53.707 94.086 54.059 ;
     RECT  86.652 53.761 86.67 54.103 ;
     RECT  46.8 54.059 46.818 54.131 ;
     RECT  48.6 54.031 49.122 54.131 ;
     RECT  6.696 53.933 8.298 54.239 ;
     RECT  87.444 54.067 87.462 54.337 ;
     RECT  88.344 54.059 91.998 54.337 ;
     RECT  50.724 54.059 51.297 54.365 ;
     RECT  86.076 54.103 86.67 54.401 ;
     RECT  2.304 53.627 5.922 54.409 ;
     RECT  6.696 54.239 8.19 54.409 ;
     RECT  10.908 54.301 10.926 54.437 ;
     RECT  87.444 54.337 91.998 54.445 ;
     RECT  9.216 54.139 9.234 54.472 ;
     RECT  9.216 54.472 9.27 54.473 ;
     RECT  86.076 54.401 86.454 54.473 ;
     RECT  2.304 54.409 8.19 54.509 ;
     RECT  42.84 54.409 42.858 54.571 ;
     RECT  9.252 54.473 9.27 54.599 ;
     RECT  42.768 54.571 42.858 54.599 ;
     RECT  44.46 53.869 44.478 54.599 ;
     RECT  87.228 54.445 91.998 54.635 ;
     RECT  82.656 54.481 82.674 54.671 ;
     RECT  86.436 54.473 86.454 54.701 ;
     RECT  42.768 54.599 42.822 54.752 ;
     RECT  41.616 54.643 41.634 54.779 ;
     RECT  42.804 54.752 42.822 54.869 ;
     RECT  87.228 54.635 87.318 54.869 ;
     RECT  48.6 54.131 49.05 54.949 ;
     RECT  2.304 54.509 8.097 55.211 ;
     RECT  88.128 54.635 91.998 55.291 ;
     RECT  92.88 54.059 94.086 55.291 ;
     RECT  88.128 55.291 94.086 55.409 ;
     RECT  84.924 55.291 84.942 55.489 ;
     RECT  87.228 54.869 87.246 55.517 ;
     RECT  84.924 55.489 85.014 55.525 ;
     RECT  0.54 55.219 0.558 55.613 ;
     RECT  7.704 55.211 8.097 55.651 ;
     RECT  48.456 54.949 49.05 55.679 ;
     RECT  84.924 55.525 85.086 55.751 ;
     RECT  7.704 55.651 8.73 55.823 ;
     RECT  45.615 53.591 45.897 55.831 ;
     RECT  48.456 55.679 48.582 55.831 ;
     RECT  7.815 55.823 8.73 55.859 ;
     RECT  45.036 55.831 45.897 55.949 ;
     RECT  2.304 55.211 6.93 56.029 ;
     RECT  46.764 55.561 46.782 56.029 ;
     RECT  88.308 55.409 94.086 56.219 ;
     RECT  2.304 56.029 6.966 56.255 ;
     RECT  84.924 55.751 85.014 56.255 ;
     RECT  0.252 55.867 0.414 56.333 ;
     RECT  92.412 56.219 94.086 56.363 ;
     RECT  50.796 54.365 51.297 56.461 ;
     RECT  48.024 55.831 48.582 56.489 ;
     RECT  2.34 56.255 6.966 56.497 ;
     RECT  46.656 56.029 46.782 56.497 ;
     RECT  87.336 56.491 87.354 56.497 ;
     RECT  2.34 56.497 7.074 56.569 ;
     RECT  7.815 55.859 8.154 56.569 ;
     RECT  0.252 56.333 0.378 56.573 ;
     RECT  2.34 56.569 8.154 56.573 ;
     RECT  48.024 56.489 48.15 56.605 ;
     RECT  88.308 56.219 91.458 56.605 ;
     RECT  82.656 56.461 82.674 56.633 ;
     RECT  9.216 56.569 9.234 56.641 ;
     RECT  9.18 56.641 9.234 56.731 ;
     RECT  46.656 56.497 46.818 56.731 ;
     RECT  47.952 56.605 48.15 56.731 ;
     RECT  9.18 56.731 9.27 56.759 ;
     RECT  46.656 56.731 48.15 56.759 ;
     RECT  9.216 56.759 9.27 56.803 ;
     RECT  0.216 56.731 0.234 56.861 ;
     RECT  9.216 56.803 9.342 56.939 ;
     RECT  46.656 56.759 48.042 57.029 ;
     RECT  84.924 56.255 84.942 57.037 ;
     RECT  50.724 56.461 51.297 57.109 ;
     RECT  84.924 57.037 85.014 57.137 ;
     RECT  2.34 56.573 8.097 57.163 ;
     RECT  10.8 56.461 10.818 57.173 ;
     RECT  88.2 56.605 91.458 57.181 ;
     RECT  92.412 56.363 93.546 57.181 ;
     RECT  2.304 57.163 8.097 57.209 ;
     RECT  87.048 56.497 87.354 57.343 ;
     RECT  88.2 57.181 93.546 57.343 ;
     RECT  50.688 57.109 51.297 57.407 ;
     RECT  87.048 57.343 93.546 57.451 ;
     RECT  10.764 57.343 10.782 57.479 ;
     RECT  0.252 57.355 0.27 57.485 ;
     RECT  86.868 57.451 94.086 57.485 ;
     RECT  2.34 57.209 8.097 57.541 ;
     RECT  47.304 57.029 48.042 57.569 ;
     RECT  88.308 57.485 94.086 57.605 ;
     RECT  48.924 57.271 48.942 57.721 ;
     RECT  48.924 57.721 49.482 57.839 ;
     RECT  0.288 57.739 0.306 57.869 ;
     RECT  48.924 57.839 49.41 57.919 ;
     RECT  84.996 57.883 85.014 57.919 ;
     RECT  50.796 57.407 51.297 57.947 ;
     RECT  88.815 57.605 94.086 58.061 ;
     RECT  2.34 57.541 8.802 58.109 ;
     RECT  47.304 57.569 47.862 58.109 ;
     RECT  2.34 58.109 8.766 58.181 ;
     RECT  93.492 58.061 94.086 58.205 ;
     RECT  2.34 58.181 6.966 58.315 ;
     RECT  48.852 57.919 49.41 58.351 ;
     RECT  47.304 58.109 47.322 58.379 ;
     RECT  86.868 57.485 87.498 58.423 ;
     RECT  93.492 58.205 93.546 58.493 ;
     RECT  7.74 58.181 8.766 58.559 ;
     RECT  10.8 58.153 10.818 58.559 ;
     RECT  48.204 58.351 49.41 58.559 ;
     RECT  84.924 57.919 85.014 58.559 ;
     RECT  2.304 58.315 6.966 58.649 ;
     RECT  86.868 58.423 87.894 58.649 ;
     RECT  86.868 58.649 87.462 58.685 ;
     RECT  88.815 58.061 92.394 58.765 ;
     RECT  82.656 58.261 82.674 58.829 ;
     RECT  51.015 57.947 51.297 58.927 ;
     RECT  50.724 58.927 51.297 59.027 ;
     RECT  88.344 58.765 92.394 59.035 ;
     RECT  93.492 58.493 93.51 59.035 ;
     RECT  2.34 58.649 6.966 59.305 ;
     RECT  7.74 58.559 8.406 59.305 ;
     RECT  48.204 58.559 48.906 59.341 ;
     RECT  2.34 59.305 8.406 59.431 ;
     RECT  10.728 59.305 10.818 59.431 ;
     RECT  10.728 59.431 10.854 59.459 ;
     RECT  48.204 59.341 49.014 59.459 ;
     RECT  46.764 58.387 47.178 59.467 ;
     RECT  86.94 58.685 87.462 59.467 ;
     RECT  88.344 59.035 93.51 59.467 ;
     RECT  46.62 59.467 47.178 59.504 ;
     RECT  86.94 59.467 93.546 59.539 ;
     RECT  84.996 59.503 85.014 59.603 ;
     RECT  2.34 59.431 8.55 59.611 ;
     RECT  86.652 59.539 93.546 59.611 ;
     RECT  46.8 59.504 47.178 59.701 ;
     RECT  48.204 59.459 48.69 59.701 ;
     RECT  2.34 59.611 8.766 59.729 ;
     RECT  42.768 59.611 42.786 59.729 ;
     RECT  86.652 59.611 93.582 59.729 ;
     RECT  10.8 59.459 10.854 59.837 ;
     RECT  46.8 59.701 48.69 59.837 ;
     RECT  47.664 59.837 48.69 59.999 ;
     RECT  87.948 59.729 93.582 60.071 ;
     RECT  46.8 59.837 46.818 60.107 ;
     RECT  87.948 60.071 92.106 60.143 ;
     RECT  92.844 60.071 93.582 60.187 ;
     RECT  45.615 55.949 45.897 60.349 ;
     RECT  10.908 60.241 10.926 60.377 ;
     RECT  9.288 60.151 9.414 60.422 ;
     RECT  2.415 59.729 8.55 60.475 ;
     RECT  9.288 60.422 9.378 60.475 ;
     RECT  47.952 59.999 48.69 60.539 ;
     RECT  86.652 59.729 86.958 60.575 ;
     RECT  84.924 60.151 84.942 60.583 ;
     RECT  2.415 60.475 9.378 60.715 ;
     RECT  41.616 59.503 41.634 60.719 ;
     RECT  0.252 59.899 0.27 60.749 ;
     RECT  47.088 60.691 47.106 60.809 ;
     RECT  48.24 60.539 48.69 60.809 ;
     RECT  86.724 60.575 86.958 60.853 ;
     RECT  87.948 60.143 91.314 60.853 ;
     RECT  86.724 60.853 91.314 60.889 ;
     RECT  92.088 60.143 92.106 60.889 ;
     RECT  2.412 60.715 9.378 60.925 ;
     RECT  84.924 60.583 85.014 60.953 ;
     RECT  48.564 60.809 48.69 60.961 ;
     RECT  86.724 60.889 92.106 60.961 ;
     RECT  92.844 60.187 94.086 60.961 ;
     RECT  2.376 60.925 9.378 60.989 ;
     RECT  45.615 60.349 46.206 61.079 ;
     RECT  48.564 60.961 49.014 61.079 ;
     RECT  86.724 60.961 94.086 61.079 ;
     RECT  51.015 59.027 51.297 61.087 ;
     RECT  48.924 61.079 49.014 61.123 ;
     RECT  2.376 60.989 8.91 61.195 ;
     RECT  2.34 61.195 8.91 61.231 ;
     RECT  2.304 61.231 8.91 61.259 ;
     RECT  2.304 61.259 3.69 61.349 ;
     RECT  4.428 61.259 8.91 61.349 ;
     RECT  46.764 61.231 46.782 61.349 ;
     RECT  86.724 61.079 91.854 61.349 ;
     RECT  86.724 61.349 87.786 61.429 ;
     RECT  48.924 61.123 49.554 61.627 ;
     RECT  50.724 61.087 51.297 61.627 ;
     RECT  4.428 61.349 8.55 61.655 ;
     RECT  10.8 61.591 10.818 61.691 ;
     RECT  92.736 61.079 94.086 61.727 ;
     RECT  48.924 61.627 51.297 61.763 ;
     RECT  86.688 61.429 87.786 61.771 ;
     RECT  50.292 61.763 51.297 61.925 ;
     RECT  86.652 61.771 87.786 61.997 ;
     RECT  88.632 61.349 91.854 62.005 ;
     RECT  2.34 61.349 3.69 62.167 ;
     RECT  4.428 61.655 8.262 62.167 ;
     RECT  9.396 62.131 9.486 62.203 ;
     RECT  87.228 61.997 87.786 62.239 ;
     RECT  88.632 62.005 91.89 62.239 ;
     RECT  50.652 61.925 51.297 62.267 ;
     RECT  48.924 61.763 49.554 62.275 ;
     RECT  9.324 62.203 9.486 62.311 ;
     RECT  87.228 62.239 91.89 62.311 ;
     RECT  92.736 61.727 93.51 62.311 ;
     RECT  87.228 62.311 93.51 62.491 ;
     RECT  9.288 62.311 9.486 62.501 ;
     RECT  46.836 62.131 46.854 62.509 ;
     RECT  48.024 62.437 48.042 62.545 ;
     RECT  2.34 62.167 8.262 62.573 ;
     RECT  9.468 62.501 9.486 62.573 ;
     RECT  2.34 62.573 8.226 62.581 ;
     RECT  0.252 62.539 0.27 62.669 ;
     RECT  2.304 62.581 8.226 62.699 ;
     RECT  48.852 62.275 49.554 62.699 ;
     RECT  47.988 62.545 48.042 62.807 ;
     RECT  48.852 62.699 49.518 62.851 ;
     RECT  87.228 62.491 93.546 62.851 ;
     RECT  46.764 62.509 46.854 62.879 ;
     RECT  86.652 62.851 93.546 62.879 ;
     RECT  2.304 62.699 6.966 62.923 ;
     RECT  88.02 62.879 93.546 62.923 ;
     RECT  2.232 62.923 6.966 63.053 ;
     RECT  88.02 62.923 94.086 63.067 ;
     RECT  10.836 62.941 10.854 63.077 ;
     RECT  48.492 62.851 49.518 63.509 ;
     RECT  88.02 63.067 94.122 63.617 ;
     RECT  2.304 63.053 6.966 63.643 ;
     RECT  7.815 62.699 8.226 63.643 ;
     RECT  2.304 63.643 8.226 63.661 ;
     RECT  2.304 63.661 8.478 63.689 ;
     RECT  48.492 63.509 49.05 63.689 ;
     RECT  0.252 63.595 0.27 63.821 ;
     RECT  45.615 61.079 45.897 63.931 ;
     RECT  47.268 63.049 47.322 63.931 ;
     RECT  88.02 63.617 94.086 63.965 ;
     RECT  10.8 63.931 10.89 64.049 ;
     RECT  45.615 63.931 47.322 64.049 ;
     RECT  86.652 62.879 87.246 64.049 ;
     RECT  88.02 63.965 93.51 64.049 ;
     RECT  88.02 64.049 92.034 64.165 ;
     RECT  2.34 63.689 8.478 64.201 ;
     RECT  51.015 62.267 51.297 64.201 ;
     RECT  10.8 64.049 10.818 64.229 ;
     RECT  82.656 64.129 82.674 64.229 ;
     RECT  46.764 64.049 47.322 64.319 ;
     RECT  50.292 64.201 51.297 64.319 ;
     RECT  46.764 64.319 46.782 64.355 ;
     RECT  48.492 63.689 48.69 64.435 ;
     RECT  48.492 64.435 49.158 64.471 ;
     RECT  10.764 64.399 10.782 64.499 ;
     RECT  2.34 64.201 9.126 64.589 ;
     RECT  2.376 64.589 9.126 64.769 ;
     RECT  48.492 64.471 49.23 64.903 ;
     RECT  86.652 64.049 87.066 64.931 ;
     RECT  87.804 64.165 92.034 65.003 ;
     RECT  48.42 64.903 49.23 65.011 ;
     RECT  88.815 65.003 92.034 65.101 ;
     RECT  92.844 64.049 93.51 65.101 ;
     RECT  46.656 64.903 46.674 65.137 ;
     RECT  2.376 64.769 9.054 65.237 ;
     RECT  46.656 65.137 46.818 65.237 ;
     RECT  48.42 65.011 49.338 65.245 ;
     RECT  87.804 65.003 88.038 65.273 ;
     RECT  8.964 65.237 9.054 65.309 ;
     RECT  8.964 65.309 8.982 65.399 ;
     RECT  47.808 65.245 49.338 65.443 ;
     RECT  88.02 65.273 88.038 65.471 ;
     RECT  47.736 65.443 49.338 65.479 ;
     RECT  46.656 65.237 46.782 65.507 ;
     RECT  2.376 65.237 8.097 65.515 ;
     RECT  2.34 65.515 8.097 65.659 ;
     RECT  2.304 65.659 8.097 65.777 ;
     RECT  88.815 65.101 93.51 65.803 ;
     RECT  0.252 65.707 0.27 65.837 ;
     RECT  47.736 65.479 49.446 65.849 ;
     RECT  2.34 65.777 8.097 65.939 ;
     RECT  47.736 65.849 47.826 65.939 ;
     RECT  48.564 65.849 49.446 65.939 ;
     RECT  87.048 64.931 87.066 65.947 ;
     RECT  86.796 65.947 87.066 65.983 ;
     RECT  86.724 65.983 87.066 66.019 ;
     RECT  86.724 66.019 87.21 66.091 ;
     RECT  40.215 26.096 40.497 66.181 ;
     RECT  49.068 65.939 49.446 66.209 ;
     RECT  86.652 66.091 87.21 66.451 ;
     RECT  46.656 65.507 46.674 66.487 ;
     RECT  51.015 64.319 51.297 66.487 ;
     RECT  86.652 66.451 87.93 66.487 ;
     RECT  86.652 66.487 87.966 66.523 ;
     RECT  88.815 65.803 93.546 66.523 ;
     RECT  86.652 66.523 93.546 66.667 ;
     RECT  86.652 66.667 94.086 66.749 ;
     RECT  49.068 66.209 49.086 66.829 ;
     RECT  10.8 66.721 10.818 66.857 ;
     RECT  2.376 65.939 8.097 66.865 ;
     RECT  87.624 66.749 94.086 66.893 ;
     RECT  82.656 66.829 82.674 66.929 ;
     RECT  2.34 66.865 8.097 66.991 ;
     RECT  48.564 66.829 49.086 66.991 ;
     RECT  86.652 66.749 86.886 67.019 ;
     RECT  86.76 67.019 86.886 67.091 ;
     RECT  2.34 66.991 8.154 67.147 ;
     RECT  46.656 66.487 46.998 67.199 ;
     RECT  0.252 66.859 0.27 67.243 ;
     RECT  48.564 66.991 49.698 67.289 ;
     RECT  50.724 66.487 51.297 67.297 ;
     RECT  40.215 66.181 41.058 67.361 ;
     RECT  0.252 67.243 0.414 67.369 ;
     RECT  0.216 67.369 0.414 67.421 ;
     RECT  2.34 67.147 8.19 67.441 ;
     RECT  34.815 52.475 35.097 67.525 ;
     RECT  54.72 67.387 54.738 67.525 ;
     RECT  38.52 67.387 38.538 67.531 ;
     RECT  38.52 67.531 38.862 67.559 ;
     RECT  46.908 67.199 46.998 67.559 ;
     RECT  50.688 67.297 51.297 67.559 ;
     RECT  54.72 67.525 55.278 67.559 ;
     RECT  34.704 67.525 35.097 67.565 ;
     RECT  55.26 67.559 55.278 67.565 ;
     RECT  38.844 67.559 38.862 67.568 ;
     RECT  86.868 67.091 86.886 67.627 ;
     RECT  87.624 66.893 93.546 67.627 ;
     RECT  47.808 67.261 47.826 67.675 ;
     RECT  86.868 67.627 93.546 67.675 ;
     RECT  47.052 67.675 47.826 67.711 ;
     RECT  48.564 67.289 49.122 67.711 ;
     RECT  10.764 67.639 10.782 67.739 ;
     RECT  47.052 67.711 49.122 67.829 ;
     RECT  86.868 67.675 94.086 67.829 ;
     RECT  2.304 67.441 8.19 67.909 ;
     RECT  86.868 67.829 87.426 67.981 ;
     RECT  88.488 67.829 94.086 68.009 ;
     RECT  47.052 67.829 49.014 68.099 ;
     RECT  86.688 67.981 87.426 68.141 ;
     RECT  0.288 67.421 0.306 68.143 ;
     RECT  0.288 68.143 0.378 68.189 ;
     RECT  88.488 68.009 93.582 68.243 ;
     RECT  0.288 68.189 0.306 68.251 ;
     RECT  0.216 68.251 0.306 68.279 ;
     RECT  43.884 67.711 43.902 68.279 ;
     RECT  42.768 68.521 42.786 68.647 ;
     RECT  51.015 67.559 51.297 68.647 ;
     RECT  0.216 68.279 0.234 68.669 ;
     RECT  42.768 68.647 42.822 68.747 ;
     RECT  50.724 68.647 51.297 68.747 ;
     RECT  2.304 67.909 8.298 68.791 ;
     RECT  9.18 68.683 9.198 68.791 ;
     RECT  88.488 68.243 92.358 68.791 ;
     RECT  42.768 68.747 42.786 68.909 ;
     RECT  47.052 68.099 47.862 68.917 ;
     RECT  48.6 68.099 49.014 68.917 ;
     RECT  93.492 68.243 93.582 68.953 ;
     RECT  47.052 68.917 49.014 68.989 ;
     RECT  93.492 68.953 94.086 69.005 ;
     RECT  88.344 68.791 92.358 69.019 ;
     RECT  88.344 69.019 92.574 69.025 ;
     RECT  86.688 68.141 87.246 69.061 ;
     RECT  0.252 69.019 0.27 69.149 ;
     RECT  2.304 68.791 9.198 69.151 ;
     RECT  47.052 68.989 49.05 69.179 ;
     RECT  2.304 69.151 9.27 69.251 ;
     RECT  47.628 69.179 49.05 69.251 ;
     RECT  86.652 69.061 87.246 69.251 ;
     RECT  88.02 69.025 92.574 69.259 ;
     RECT  93.492 69.005 93.51 69.259 ;
     RECT  2.304 69.251 8.406 69.287 ;
     RECT  6.804 69.287 8.406 69.323 ;
     RECT  9.144 69.251 9.27 69.323 ;
     RECT  87.084 69.251 87.246 69.341 ;
     RECT  88.02 69.259 93.51 69.421 ;
     RECT  46.764 69.295 46.782 69.449 ;
     RECT  87.768 69.421 93.51 69.485 ;
     RECT  2.304 69.287 6.03 69.557 ;
     RECT  50.076 69.295 50.094 69.565 ;
     RECT  47.628 69.251 48.546 69.629 ;
     RECT  24.015 52.475 24.354 69.643 ;
     RECT  2.304 69.557 5.994 69.691 ;
     RECT  13.215 52.475 13.497 69.691 ;
     RECT  24.015 69.643 24.822 69.691 ;
     RECT  13.104 69.691 13.497 69.728 ;
     RECT  2.268 69.691 5.994 69.791 ;
     RECT  22.824 69.691 22.842 69.821 ;
     RECT  24.015 69.691 25.146 69.821 ;
     RECT  2.268 69.791 5.958 69.827 ;
     RECT  49.536 69.565 50.094 69.871 ;
     RECT  68.832 69.787 68.85 69.989 ;
     RECT  70.38 69.871 70.398 70.025 ;
     RECT  87.876 69.485 93.51 70.025 ;
     RECT  88.056 70.025 93.51 70.061 ;
     RECT  47.628 69.629 48.366 70.141 ;
     RECT  24.015 69.821 25.11 70.259 ;
     RECT  49.536 69.871 50.202 70.267 ;
     RECT  51.015 68.747 51.297 70.267 ;
     RECT  86.652 70.141 86.67 70.267 ;
     RECT  6.84 69.323 8.406 70.331 ;
     RECT  0.252 70.123 0.27 70.411 ;
     RECT  88.2 70.061 93.51 70.529 ;
     RECT  0.252 70.411 0.342 70.637 ;
     RECT  47.376 70.141 48.366 70.645 ;
     RECT  49.536 70.267 51.297 70.645 ;
     RECT  9.144 69.323 9.234 70.681 ;
     RECT  49.428 70.645 51.297 70.685 ;
     RECT  2.304 69.827 5.958 70.843 ;
     RECT  47.268 70.645 48.366 70.907 ;
     RECT  2.304 70.843 6.102 70.951 ;
     RECT  7.128 70.331 8.406 70.951 ;
     RECT  9.144 70.681 9.378 70.951 ;
     RECT  47.268 70.907 47.574 70.951 ;
     RECT  7.128 70.951 9.378 70.979 ;
     RECT  86.22 70.267 86.67 71.041 ;
     RECT  46.764 70.951 47.574 71.069 ;
     RECT  49.824 70.685 51.297 71.069 ;
     RECT  83.415 45.329 83.697 71.077 ;
     RECT  88.416 70.529 93.51 71.177 ;
     RECT  85.896 71.041 86.67 71.185 ;
     RECT  50.616 71.069 51.297 71.249 ;
     RECT  85.716 71.185 86.67 71.261 ;
     RECT  88.416 71.177 89.154 71.371 ;
     RECT  88.164 71.371 89.154 71.405 ;
     RECT  2.304 70.951 6.318 71.419 ;
     RECT  7.128 70.979 9.09 71.419 ;
     RECT  86.184 71.261 86.67 71.519 ;
     RECT  2.304 71.419 9.09 71.549 ;
     RECT  0.252 70.637 0.27 71.563 ;
     RECT  89.892 71.177 93.51 71.681 ;
     RECT  0.252 71.563 0.342 71.689 ;
     RECT  47.268 71.069 47.574 71.725 ;
     RECT  48.348 70.907 48.366 71.725 ;
     RECT  88.164 71.405 89.097 71.761 ;
     RECT  2.415 71.549 9.09 71.837 ;
     RECT  2.415 71.837 8.406 71.879 ;
     RECT  47.268 71.725 48.366 71.887 ;
     RECT  47.268 71.887 48.438 72.059 ;
     RECT  10.8 71.887 10.818 72.121 ;
     RECT  92.916 71.681 93.51 72.139 ;
     RECT  51.015 71.249 51.297 72.157 ;
     RECT  0.252 71.689 0.558 72.173 ;
     RECT  2.415 71.879 8.37 72.185 ;
     RECT  45.615 64.049 45.897 72.229 ;
     RECT  10.764 72.121 10.818 72.257 ;
     RECT  50.688 72.157 51.297 72.257 ;
     RECT  87.804 71.761 89.097 72.301 ;
     RECT  89.892 71.681 92.106 72.301 ;
     RECT  50.76 72.257 51.297 72.329 ;
     RECT  82.656 72.229 82.674 72.329 ;
     RECT  49.86 71.069 49.878 72.419 ;
     RECT  47.7 72.059 48.438 72.463 ;
     RECT  86.184 71.519 86.418 72.463 ;
     RECT  45.036 72.229 45.897 72.527 ;
     RECT  50.796 72.329 51.297 72.527 ;
     RECT  10.8 72.257 10.818 72.563 ;
     RECT  92.916 72.139 94.086 72.563 ;
     RECT  87.804 72.301 92.106 72.571 ;
     RECT  83.415 71.077 83.862 72.599 ;
     RECT  0.252 72.173 0.27 72.605 ;
     RECT  87.804 72.571 92.178 72.619 ;
     RECT  87.264 72.619 92.178 72.667 ;
     RECT  92.916 72.563 93.51 72.667 ;
     RECT  46.8 72.229 46.818 72.689 ;
     RECT  86.076 72.463 86.418 72.769 ;
     RECT  87.264 72.667 93.51 72.769 ;
     RECT  2.415 72.185 8.19 72.805 ;
     RECT  9.324 72.229 9.342 72.805 ;
     RECT  2.376 72.805 8.19 72.931 ;
     RECT  47.7 72.463 48.726 72.931 ;
     RECT  9.324 72.805 9.378 72.959 ;
     RECT  86.076 72.769 93.51 73.103 ;
     RECT  2.34 72.931 8.19 73.111 ;
     RECT  45.615 72.527 45.897 73.309 ;
     RECT  2.304 73.111 8.19 73.381 ;
     RECT  86.652 73.103 93.51 73.409 ;
     RECT  2.304 73.381 8.586 73.471 ;
     RECT  2.304 73.471 8.73 73.499 ;
     RECT  47.592 72.931 48.726 73.535 ;
     RECT  48.636 73.535 48.726 73.543 ;
     RECT  48.636 73.543 48.906 73.651 ;
     RECT  83.415 72.599 83.826 73.679 ;
     RECT  2.34 73.499 8.73 73.769 ;
     RECT  48.636 73.651 49.014 73.885 ;
     RECT  87.228 73.409 93.51 73.913 ;
     RECT  10.764 73.849 10.782 73.921 ;
     RECT  6.768 73.769 8.73 74.011 ;
     RECT  10.692 73.921 10.782 74.011 ;
     RECT  10.692 74.011 10.854 74.039 ;
     RECT  48.636 73.885 49.446 74.039 ;
     RECT  10.836 74.039 10.854 74.111 ;
     RECT  47.592 73.535 47.61 74.183 ;
     RECT  45.615 73.309 46.206 74.191 ;
     RECT  87.228 73.913 87.246 74.281 ;
     RECT  45.615 74.191 46.782 74.309 ;
     RECT  87.192 74.281 87.246 74.389 ;
     RECT  6.768 74.011 8.946 74.453 ;
     RECT  87.984 73.913 93.51 74.453 ;
     RECT  2.34 73.769 5.922 74.461 ;
     RECT  6.768 74.453 8.658 74.551 ;
     RECT  2.304 74.461 5.922 74.579 ;
     RECT  87.984 74.453 92.61 74.621 ;
     RECT  9.432 74.461 9.45 74.651 ;
     RECT  86.652 74.389 87.246 74.659 ;
     RECT  87.984 74.621 92.502 74.659 ;
     RECT  2.34 74.579 5.922 74.695 ;
     RECT  6.732 74.551 8.658 74.695 ;
     RECT  48.6 74.623 48.618 74.731 ;
     RECT  2.34 74.695 8.658 74.921 ;
     RECT  93.492 74.453 93.51 74.965 ;
     RECT  47.016 74.551 47.034 75.001 ;
     RECT  48.492 74.731 48.618 75.001 ;
     RECT  49.428 74.039 49.446 75.001 ;
     RECT  93.492 74.965 94.086 75.053 ;
     RECT  45.615 74.309 46.206 75.119 ;
     RECT  86.652 74.659 92.502 75.119 ;
     RECT  51.015 72.527 51.297 75.127 ;
     RECT  50.796 75.127 51.297 75.227 ;
     RECT  85.5 75.163 85.518 75.299 ;
     RECT  48.492 75.001 49.446 75.389 ;
     RECT  2.34 74.921 8.226 75.451 ;
     RECT  48.492 75.389 48.906 75.505 ;
     RECT  10.908 75.361 10.926 75.533 ;
     RECT  0.252 73.627 0.27 75.629 ;
     RECT  47.016 75.001 47.178 75.631 ;
     RECT  47.916 75.505 48.906 75.631 ;
     RECT  86.652 75.119 87.318 75.659 ;
     RECT  2.304 75.451 8.226 75.667 ;
     RECT  9.072 75.541 9.09 75.667 ;
     RECT  2.304 75.667 9.09 75.731 ;
     RECT  2.304 75.731 8.442 75.773 ;
     RECT  88.056 75.119 92.502 75.883 ;
     RECT  93.492 75.053 93.51 75.883 ;
     RECT  47.016 75.631 48.906 76.199 ;
     RECT  51.015 75.227 51.297 76.207 ;
     RECT  47.016 76.199 47.034 76.307 ;
     RECT  1.404 74.011 1.422 76.379 ;
     RECT  47.916 76.199 48.87 76.469 ;
     RECT  50.796 76.207 51.297 76.477 ;
     RECT  50.688 76.477 51.297 76.577 ;
     RECT  2.304 75.773 8.154 76.585 ;
     RECT  88.056 75.883 93.51 76.621 ;
     RECT  2.304 76.585 8.19 76.649 ;
     RECT  48.024 76.469 48.87 76.649 ;
     RECT  9.108 76.621 9.234 76.811 ;
     RECT  87.804 76.621 93.51 76.885 ;
     RECT  87.696 76.885 93.51 76.925 ;
     RECT  87.804 76.925 93.51 77.035 ;
     RECT  9.108 76.811 9.126 77.081 ;
     RECT  2.34 76.649 8.19 77.161 ;
     RECT  2.34 77.161 8.73 77.279 ;
     RECT  49.86 76.009 49.878 77.279 ;
     RECT  46.8 76.585 46.818 77.459 ;
     RECT  87.804 77.035 93.546 77.621 ;
     RECT  51.015 76.577 51.297 77.701 ;
     RECT  2.34 77.279 5.85 77.755 ;
     RECT  48.024 76.649 48.654 77.899 ;
     RECT  49.644 77.323 49.662 77.899 ;
     RECT  93.456 77.621 93.546 77.899 ;
     RECT  86.652 75.659 86.778 77.935 ;
     RECT  86.364 77.935 86.778 77.981 ;
     RECT  50.724 77.701 51.297 77.999 ;
     RECT  2.304 77.755 5.85 78.061 ;
     RECT  6.768 77.279 8.19 78.061 ;
     RECT  2.304 78.061 8.586 78.089 ;
     RECT  48.024 77.899 49.662 78.097 ;
     RECT  87.804 77.621 92.574 78.133 ;
     RECT  48.024 78.097 49.95 78.205 ;
     RECT  86.652 77.981 86.778 78.241 ;
     RECT  10.764 78.331 10.782 78.367 ;
     RECT  46.908 78.367 46.926 78.403 ;
     RECT  48.024 78.205 50.022 78.403 ;
     RECT  93.456 77.899 94.086 78.431 ;
     RECT  46.836 78.403 46.926 78.475 ;
     RECT  86.652 78.241 86.85 78.475 ;
     RECT  87.732 78.133 92.574 78.475 ;
     RECT  46.764 78.475 46.926 78.503 ;
     RECT  93.456 78.431 93.546 78.503 ;
     RECT  2.376 78.089 8.586 78.511 ;
     RECT  10.764 78.367 10.854 78.539 ;
     RECT  86.652 78.475 92.574 78.539 ;
     RECT  87.084 78.539 92.574 78.557 ;
     RECT  90.396 78.557 92.574 78.619 ;
     RECT  93.456 78.503 93.51 78.619 ;
     RECT  10.764 78.539 10.818 78.629 ;
     RECT  47.916 78.403 50.022 78.629 ;
     RECT  87.084 78.557 89.658 78.629 ;
     RECT  46.764 78.503 46.854 78.701 ;
     RECT  0.252 77.179 0.27 78.797 ;
     RECT  2.376 78.511 9.162 78.871 ;
     RECT  46.836 78.701 46.854 78.899 ;
     RECT  47.916 78.629 49.374 78.899 ;
     RECT  47.916 78.899 49.266 79.015 ;
     RECT  2.304 78.871 9.162 79.051 ;
     RECT  10.764 78.629 10.782 79.079 ;
     RECT  2.304 79.051 9.198 79.169 ;
     RECT  90.396 78.619 93.51 79.285 ;
     RECT  87.084 78.629 89.514 79.349 ;
     RECT  2.304 79.169 8.586 79.439 ;
     RECT  0.324 79.531 0.342 79.627 ;
     RECT  2.34 79.439 8.226 79.709 ;
     RECT  0.252 79.627 0.342 79.805 ;
     RECT  90.36 79.285 93.51 79.825 ;
     RECT  88.164 79.349 89.514 79.861 ;
     RECT  90.288 79.825 93.51 79.861 ;
     RECT  46.764 79.861 46.782 79.951 ;
     RECT  87.084 79.349 87.39 79.963 ;
     RECT  0.252 79.805 0.27 80.045 ;
     RECT  46.764 79.951 46.854 80.051 ;
     RECT  86.868 79.963 87.39 80.095 ;
     RECT  88.164 79.861 93.51 80.095 ;
     RECT  51.015 77.999 51.297 80.131 ;
     RECT  46.764 80.051 46.782 80.249 ;
     RECT  47.88 79.015 49.266 80.249 ;
     RECT  50.796 80.131 51.297 80.285 ;
     RECT  44.496 79.861 44.514 80.329 ;
     RECT  9.18 80.329 9.198 80.381 ;
     RECT  2.415 79.709 8.226 80.485 ;
     RECT  2.415 80.485 8.838 80.491 ;
     RECT  2.304 80.491 8.838 80.519 ;
     RECT  86.868 80.095 93.51 80.599 ;
     RECT  7.815 80.519 8.838 80.627 ;
     RECT  86.652 80.599 93.51 80.635 ;
     RECT  45.615 75.119 45.897 80.671 ;
     RECT  85.5 80.293 85.518 80.731 ;
     RECT  86.652 80.635 94.086 80.731 ;
     RECT  44.46 80.329 44.514 80.789 ;
     RECT  85.5 80.731 94.086 80.789 ;
     RECT  86.652 80.789 94.086 80.861 ;
     RECT  47.88 80.249 48.582 80.905 ;
     RECT  90.432 80.861 94.086 80.905 ;
     RECT  42.768 80.833 42.786 80.933 ;
     RECT  85.5 80.789 85.518 80.933 ;
     RECT  47.592 80.905 48.582 80.941 ;
     RECT  90.432 80.905 94.122 80.957 ;
     RECT  1.116 80.923 1.134 81.053 ;
     RECT  10.8 79.861 10.818 81.067 ;
     RECT  45.615 80.671 46.494 81.067 ;
     RECT  47.268 80.941 48.582 81.067 ;
     RECT  90.432 80.957 94.086 81.167 ;
     RECT  10.8 81.067 10.854 81.239 ;
     RECT  45.615 81.067 48.582 81.329 ;
     RECT  2.304 80.519 7.002 81.437 ;
     RECT  9.144 81.211 9.162 81.485 ;
     RECT  0.252 80.923 0.27 81.499 ;
     RECT  45.615 81.329 46.818 81.509 ;
     RECT  51.015 80.285 51.297 81.607 ;
     RECT  0.252 81.499 0.342 81.629 ;
     RECT  47.592 81.329 48.582 81.707 ;
     RECT  86.652 80.861 89.622 81.715 ;
     RECT  90.432 81.167 93.546 81.715 ;
     RECT  86.652 81.715 93.546 81.743 ;
     RECT  7.815 80.627 8.226 81.841 ;
     RECT  47.592 81.707 48.474 81.869 ;
     RECT  49.608 81.211 49.626 81.869 ;
     RECT  7.815 81.841 8.874 81.877 ;
     RECT  50.688 81.607 51.297 81.941 ;
     RECT  7.812 81.877 8.874 81.979 ;
     RECT  7.272 81.979 8.874 82.013 ;
     RECT  50.796 81.941 51.297 82.013 ;
     RECT  78.015 2.413 78.297 82.111 ;
     RECT  77.904 82.111 78.297 82.157 ;
     RECT  47.592 81.869 48.15 82.219 ;
     RECT  45.615 81.509 46.494 82.247 ;
     RECT  74.628 82.123 74.646 82.253 ;
     RECT  2.304 81.437 6.39 82.255 ;
     RECT  7.272 82.013 8.154 82.255 ;
     RECT  47.232 82.219 48.15 82.291 ;
     RECT  10.8 82.147 10.818 82.409 ;
     RECT  44.496 80.789 44.514 82.409 ;
     RECT  45.615 82.247 46.17 82.409 ;
     RECT  86.652 81.743 92.682 82.525 ;
     RECT  93.492 81.743 93.546 82.525 ;
     RECT  46.944 82.291 48.15 82.679 ;
     RECT  42.768 82.687 42.786 82.787 ;
     RECT  2.304 82.255 8.154 82.831 ;
     RECT  86.652 82.525 93.546 82.949 ;
     RECT  0.252 81.629 0.27 82.987 ;
     RECT  46.944 82.679 48.042 83.057 ;
     RECT  0.216 82.987 0.27 83.117 ;
     RECT  2.304 82.831 8.226 83.219 ;
     RECT  88.776 82.949 93.546 83.219 ;
     RECT  7.815 83.219 8.226 83.221 ;
     RECT  9.288 83.101 9.306 83.263 ;
     RECT  0.252 83.117 0.27 83.371 ;
     RECT  9.288 83.263 9.342 83.399 ;
     RECT  47.16 83.057 48.042 83.461 ;
     RECT  48.816 83.263 48.834 83.461 ;
     RECT  49.752 83.371 49.77 83.489 ;
     RECT  2.304 83.219 7.038 83.525 ;
     RECT  9.324 83.399 9.342 83.525 ;
     RECT  0.252 83.371 0.342 83.549 ;
     RECT  86.652 82.949 87.822 83.669 ;
     RECT  88.776 83.219 92.106 83.731 ;
     RECT  9.396 83.641 9.414 83.759 ;
     RECT  88.668 83.731 92.106 83.789 ;
     RECT  7.815 83.221 8.37 83.795 ;
     RECT  92.916 83.219 93.546 83.803 ;
     RECT  88.815 83.789 92.106 83.947 ;
     RECT  92.916 83.803 93.582 83.947 ;
     RECT  51.015 82.013 51.297 84.001 ;
     RECT  50.688 84.001 51.297 84.101 ;
     RECT  47.16 83.461 48.834 84.109 ;
     RECT  46.764 84.109 48.834 84.209 ;
     RECT  2.304 83.525 6.966 84.271 ;
     RECT  7.815 83.795 8.097 84.271 ;
     RECT  46.764 84.209 47.178 84.299 ;
     RECT  87.12 83.669 87.822 84.299 ;
     RECT  83.415 73.679 83.697 84.307 ;
     RECT  87.12 84.299 87.57 84.451 ;
     RECT  47.16 84.299 47.178 84.479 ;
     RECT  86.724 84.451 87.57 84.677 ;
     RECT  86.724 84.677 86.742 84.721 ;
     RECT  87.48 84.677 87.57 84.875 ;
     RECT  9.108 84.919 9.126 84.955 ;
     RECT  2.304 84.271 8.097 84.991 ;
     RECT  9.072 84.955 9.126 84.991 ;
     RECT  48.024 84.209 48.834 84.991 ;
     RECT  88.815 83.947 93.582 84.991 ;
     RECT  88.416 84.991 93.582 85.181 ;
     RECT  2.304 84.991 9.126 85.225 ;
     RECT  47.376 84.991 48.834 85.261 ;
     RECT  0.252 83.549 0.27 85.277 ;
     RECT  42.804 85.261 42.822 85.379 ;
     RECT  46.8 85.261 48.834 85.379 ;
     RECT  51.015 84.101 51.297 85.387 ;
     RECT  88.416 85.181 93.546 85.423 ;
     RECT  2.304 85.225 9.162 85.451 ;
     RECT  86.652 84.721 86.742 85.483 ;
     RECT  49.68 84.847 49.698 85.531 ;
     RECT  50.688 85.387 51.297 85.531 ;
     RECT  86.292 85.483 86.742 85.531 ;
     RECT  87.48 84.875 87.498 85.531 ;
     RECT  83.415 84.307 83.826 85.559 ;
     RECT  86.292 85.531 87.498 85.649 ;
     RECT  0.396 85.531 0.414 85.709 ;
     RECT  83.415 85.559 83.697 85.729 ;
     RECT  82.728 85.729 83.697 85.801 ;
     RECT  82.656 85.801 83.697 85.829 ;
     RECT  82.656 85.829 82.674 85.919 ;
     RECT  86.652 85.649 87.498 85.963 ;
     RECT  88.344 85.423 93.546 85.963 ;
     RECT  86.652 85.963 93.546 85.991 ;
     RECT  2.304 85.451 8.622 86.027 ;
     RECT  46.8 85.379 48.69 86.063 ;
     RECT  46.8 86.063 47.862 86.071 ;
     RECT  2.34 86.027 8.622 86.195 ;
     RECT  6.372 86.195 8.622 86.369 ;
     RECT  86.724 85.991 93.546 86.531 ;
     RECT  6.768 86.369 8.622 86.611 ;
     RECT  0.216 86.107 0.27 86.621 ;
     RECT  2.34 86.195 5.562 86.639 ;
     RECT  49.68 85.531 51.297 86.729 ;
     RECT  6.768 86.611 9.126 86.773 ;
     RECT  6.768 86.773 9.198 86.801 ;
     RECT  46.764 86.071 47.862 86.809 ;
     RECT  48.672 86.063 48.69 86.809 ;
     RECT  85.788 86.737 85.806 86.813 ;
     RECT  9.18 86.801 9.198 86.873 ;
     RECT  86.724 86.531 93.51 86.881 ;
     RECT  2.34 86.639 4.518 86.971 ;
     RECT  86.652 86.881 93.51 87.035 ;
     RECT  86.652 87.035 87.318 87.071 ;
     RECT  6.768 86.801 8.442 87.151 ;
     RECT  6.624 87.151 8.442 87.211 ;
     RECT  6.444 87.211 8.442 87.241 ;
     RECT  46.764 86.809 48.69 87.269 ;
     RECT  9.36 87.241 9.378 87.34 ;
     RECT  2.304 86.971 4.518 87.421 ;
     RECT  5.436 86.639 5.562 87.421 ;
     RECT  6.336 87.241 8.442 87.485 ;
     RECT  9.36 87.34 9.414 87.539 ;
     RECT  2.304 87.421 5.562 87.547 ;
     RECT  6.336 87.485 8.37 87.547 ;
     RECT  86.652 87.071 87.246 87.547 ;
     RECT  18.615 3.629 18.897 87.781 ;
     RECT  21.924 3.721 21.942 87.781 ;
     RECT  46.764 87.269 48.474 87.781 ;
     RECT  49.752 86.729 51.297 87.809 ;
     RECT  24.015 70.259 24.354 87.817 ;
     RECT  88.344 87.035 93.51 87.835 ;
     RECT  2.304 87.547 8.37 87.853 ;
     RECT  23.292 87.817 24.354 87.88 ;
     RECT  45.615 82.409 45.897 87.889 ;
     RECT  86.076 87.547 87.246 87.925 ;
     RECT  10.692 87.781 10.818 87.953 ;
     RECT  86.076 87.925 87.498 87.953 ;
     RECT  18.615 87.781 19.062 87.961 ;
     RECT  19.908 87.853 19.926 87.961 ;
     RECT  21.852 87.781 22.338 87.961 ;
     RECT  23.22 87.88 24.354 87.961 ;
     RECT  18.615 87.961 20.178 87.979 ;
     RECT  82.656 87.889 82.674 87.989 ;
     RECT  18.615 87.979 20.466 88.051 ;
     RECT  84.924 86.845 84.942 88.115 ;
     RECT  13.215 69.728 13.497 88.123 ;
     RECT  18.54 88.051 20.466 88.123 ;
     RECT  18.108 88.123 21.114 88.171 ;
     RECT  17.964 88.171 21.114 88.195 ;
     RECT  21.852 87.961 24.354 88.195 ;
     RECT  17.964 88.195 24.354 88.231 ;
     RECT  49.752 87.809 49.77 88.231 ;
     RECT  25.2 88.087 25.218 88.259 ;
     RECT  0.252 86.621 0.27 88.301 ;
     RECT  16.02 88.195 16.038 88.315 ;
     RECT  15.876 88.315 16.038 88.321 ;
     RECT  83.415 85.829 83.697 88.321 ;
     RECT  86.22 87.953 87.498 88.349 ;
     RECT  88.344 87.835 93.546 88.349 ;
     RECT  49.644 88.231 49.77 88.385 ;
     RECT  10.728 87.953 10.818 88.393 ;
     RECT  14.832 88.159 14.85 88.393 ;
     RECT  2.052 87.853 8.37 88.411 ;
     RECT  15.876 88.321 16.722 88.429 ;
     RECT  17.784 88.231 24.354 88.429 ;
     RECT  86.22 88.349 86.454 88.493 ;
     RECT  9.108 87.817 9.126 88.501 ;
     RECT  10.728 88.393 10.854 88.501 ;
     RECT  12.636 88.123 13.497 88.501 ;
     RECT  14.76 88.393 14.85 88.501 ;
     RECT  15.876 88.429 24.354 88.501 ;
     RECT  46.62 87.781 48.474 88.501 ;
     RECT  12.636 88.501 14.85 88.529 ;
     RECT  1.728 88.411 8.37 88.591 ;
     RECT  9.108 88.501 9.306 88.591 ;
     RECT  46.62 88.501 48.906 88.619 ;
     RECT  88.668 88.349 93.546 88.627 ;
     RECT  15.876 88.501 24.606 88.663 ;
     RECT  1.728 88.591 9.306 88.685 ;
     RECT  46.62 88.619 48.474 88.691 ;
     RECT  10.728 88.501 11.466 88.699 ;
     RECT  10.476 88.699 11.466 88.771 ;
     RECT  12.636 88.529 14.778 88.771 ;
     RECT  15.624 88.663 24.606 88.861 ;
     RECT  88.668 88.627 94.086 88.877 ;
     RECT  9.288 88.685 9.306 88.891 ;
     RECT  10.476 88.771 14.778 88.891 ;
     RECT  1.728 88.685 8.262 88.925 ;
     RECT  86.22 88.493 86.238 88.973 ;
     RECT  15.552 88.861 24.606 89.069 ;
     RECT  49.752 88.385 49.77 89.069 ;
     RECT  87.732 88.933 87.894 89.195 ;
     RECT  23.904 89.069 24.606 89.203 ;
     RECT  6.264 88.925 8.262 89.231 ;
     RECT  75.636 3.451 75.654 89.231 ;
     RECT  29.415 2.413 29.697 89.239 ;
     RECT  34.815 67.565 35.097 89.311 ;
     RECT  88.668 88.877 93.51 89.311 ;
     RECT  9.288 88.891 14.778 89.401 ;
     RECT  15.552 89.069 23.166 89.401 ;
     RECT  9.288 89.401 23.166 89.419 ;
     RECT  45.036 87.889 45.897 89.429 ;
     RECT  9.18 89.419 23.166 89.465 ;
     RECT  6.336 89.231 8.262 89.501 ;
     RECT  9.612 89.465 23.166 89.501 ;
     RECT  23.904 89.203 24.93 89.581 ;
     RECT  6.696 89.501 8.262 89.671 ;
     RECT  0.252 89.563 0.27 89.707 ;
     RECT  6.696 89.671 8.694 89.771 ;
     RECT  86.112 89.581 86.13 89.815 ;
     RECT  1.728 88.925 5.418 89.851 ;
     RECT  82.656 89.707 82.674 89.879 ;
     RECT  85.932 89.815 86.13 89.885 ;
     RECT  7.56 89.771 8.694 89.969 ;
     RECT  88.38 89.311 93.51 89.969 ;
     RECT  92.916 89.969 93.51 89.995 ;
     RECT  88.38 89.969 92.106 90.005 ;
     RECT  45.615 89.429 45.897 90.013 ;
     RECT  46.62 88.691 47.826 90.013 ;
     RECT  0.216 89.707 0.27 90.029 ;
     RECT  7.56 89.969 8.406 90.029 ;
     RECT  1.728 89.851 5.598 90.043 ;
     RECT  23.904 89.581 25.146 90.049 ;
     RECT  88.38 90.005 92.034 90.049 ;
     RECT  45.615 90.013 47.826 90.077 ;
     RECT  29.415 89.239 29.754 90.091 ;
     RECT  33.084 88.861 33.102 90.121 ;
     RECT  23.904 90.049 25.218 90.149 ;
     RECT  28.512 89.275 28.53 90.149 ;
     RECT  46.8 90.077 47.826 90.149 ;
     RECT  16.272 89.501 23.166 90.235 ;
     RECT  23.904 90.149 25.11 90.235 ;
     RECT  6.696 89.771 6.786 90.239 ;
     RECT  29.415 90.091 30.474 90.239 ;
     RECT  32.976 90.121 33.102 90.239 ;
     RECT  34.815 89.311 35.37 90.239 ;
     RECT  45.615 90.077 45.897 90.355 ;
     RECT  92.916 89.995 93.546 90.383 ;
     RECT  46.8 90.149 47.25 90.419 ;
     RECT  9.612 89.501 15.534 90.481 ;
     RECT  1.728 90.043 5.886 90.509 ;
     RECT  7.815 90.029 8.406 90.509 ;
     RECT  9.18 90.481 15.534 90.509 ;
     RECT  53.424 90.319 53.442 90.509 ;
     RECT  6.768 90.239 6.786 90.523 ;
     RECT  7.815 90.509 8.262 90.545 ;
     RECT  0.252 90.029 0.27 90.557 ;
     RECT  6.768 90.523 6.822 90.571 ;
     RECT  6.768 90.571 7.002 90.581 ;
     RECT  92.916 90.383 93.51 90.581 ;
     RECT  9.18 90.509 15.066 90.605 ;
     RECT  52.488 90.481 52.506 90.605 ;
     RECT  6.984 90.581 7.002 90.617 ;
     RECT  46.8 90.419 46.818 90.653 ;
     RECT  5.76 90.509 5.886 90.661 ;
     RECT  86.652 90.391 86.67 90.661 ;
     RECT  83.415 88.321 84.402 90.689 ;
     RECT  34.815 90.239 35.097 90.751 ;
     RECT  88.344 90.049 92.034 90.751 ;
     RECT  86.4 90.661 86.67 90.763 ;
     RECT  16.272 90.235 25.11 90.787 ;
     RECT  38.556 90.751 38.574 90.823 ;
     RECT  37.944 90.823 38.574 90.845 ;
     RECT  9.864 90.605 14.886 90.851 ;
     RECT  15.84 90.787 25.11 90.851 ;
     RECT  37.944 90.845 37.962 90.895 ;
     RECT  92.916 90.581 92.934 90.923 ;
     RECT  86.148 90.763 86.67 90.941 ;
     RECT  5.76 90.661 6.03 91.048 ;
     RECT  77.22 90.859 77.238 91.049 ;
     RECT  85.068 90.931 85.086 91.049 ;
     RECT  88.344 90.751 92.142 91.049 ;
     RECT  5.76 91.048 6.102 91.085 ;
     RECT  70.092 91.021 70.11 91.085 ;
     RECT  34.704 90.751 35.097 91.165 ;
     RECT  76.284 91.147 76.302 91.165 ;
     RECT  37.62 90.895 37.962 91.181 ;
     RECT  56.415 26.093 56.697 91.192 ;
     RECT  67.215 25.997 67.497 91.192 ;
     RECT  78.015 82.157 78.297 91.192 ;
     RECT  1.728 90.509 4.698 91.193 ;
     RECT  5.76 91.085 5.85 91.193 ;
     RECT  9.864 90.851 14.85 91.193 ;
     RECT  76.284 91.165 76.446 91.193 ;
     RECT  34.596 91.165 35.097 91.201 ;
     RECT  5.832 91.193 5.85 91.229 ;
     RECT  33.084 90.239 33.102 91.229 ;
     RECT  56.304 91.192 56.697 91.229 ;
     RECT  67.104 91.192 67.497 91.229 ;
     RECT  77.904 91.192 78.297 91.229 ;
     RECT  47.772 91.285 47.79 91.291 ;
     RECT  65.412 90.589 65.43 91.291 ;
     RECT  78.015 91.229 78.297 91.291 ;
     RECT  88.344 91.049 89.514 91.291 ;
     RECT  4.068 91.193 4.698 91.319 ;
     RECT  15.84 90.851 21.798 91.319 ;
     RECT  34.344 91.201 35.097 91.319 ;
     RECT  65.052 91.291 65.43 91.319 ;
     RECT  90.324 91.049 92.142 91.319 ;
     RECT  48.636 91.291 48.654 91.327 ;
     RECT  49.572 91.291 49.59 91.327 ;
     RECT  29.415 90.239 30.33 91.339 ;
     RECT  79.992 91.291 80.406 91.355 ;
     RECT  87.948 91.291 89.514 91.355 ;
     RECT  90.324 91.319 91.962 91.355 ;
     RECT  15.84 91.319 21.006 91.363 ;
     RECT  22.68 90.851 25.11 91.363 ;
     RECT  26.028 91.201 26.046 91.363 ;
     RECT  22.68 91.363 26.082 91.373 ;
     RECT  34.596 91.319 35.097 91.373 ;
     RECT  48.636 91.327 49.59 91.373 ;
     RECT  86.652 90.941 86.67 91.373 ;
     RECT  90.36 91.355 91.278 91.373 ;
     RECT  65.052 91.319 65.07 91.387 ;
     RECT  69.156 91.165 69.498 91.421 ;
     RECT  78.015 91.291 78.642 91.421 ;
     RECT  45.468 90.355 45.897 91.435 ;
     RECT  4.572 91.319 4.698 91.471 ;
     RECT  90.36 91.373 90.882 91.499 ;
     RECT  40.215 67.361 40.497 91.561 ;
     RECT  71.28 91.291 71.298 91.579 ;
     RECT  4.572 91.471 4.806 91.589 ;
     RECT  13.215 91.193 14.85 91.589 ;
     RECT  22.68 91.373 24.498 91.589 ;
     RECT  25.524 91.373 26.082 91.589 ;
     RECT  41.652 90.517 41.67 91.589 ;
     RECT  33.408 91.363 33.75 91.613 ;
     RECT  45.216 91.435 45.897 91.613 ;
     RECT  47.664 91.291 47.79 91.613 ;
     RECT  1.728 91.193 3.222 91.625 ;
     RECT  14.256 91.589 14.85 91.625 ;
     RECT  29.34 91.339 30.33 91.625 ;
     RECT  90.36 91.499 90.378 91.625 ;
     RECT  48.636 91.373 49.374 91.661 ;
     RECT  60.696 91.561 60.858 91.661 ;
     RECT  64.44 91.387 65.07 91.661 ;
     RECT  49.32 91.661 49.374 91.667 ;
     RECT  29.415 91.625 30.33 91.669 ;
     RECT  1.728 91.625 3.006 91.697 ;
     RECT  21.78 91.319 21.798 91.697 ;
     RECT  88.344 91.355 89.514 91.697 ;
     RECT  2.304 91.697 3.006 91.733 ;
     RECT  4.572 91.589 4.59 91.733 ;
     RECT  40.215 91.561 40.734 91.741 ;
     RECT  72.615 25.997 72.897 91.741 ;
     RECT  15.588 91.363 21.006 91.757 ;
     RECT  9.864 91.193 12.042 91.769 ;
     RECT  20.988 91.757 21.006 91.769 ;
     RECT  26.784 91.669 26.802 91.769 ;
     RECT  29.415 91.669 30.366 91.769 ;
     RECT  58.716 91.669 58.734 91.769 ;
     RECT  10.26 91.769 12.042 91.859 ;
     RECT  37.944 91.181 37.962 91.859 ;
     RECT  52.92 90.661 52.938 91.859 ;
     RECT  69.372 91.421 69.498 91.859 ;
     RECT  38.7 91.831 38.718 91.867 ;
     RECT  10.26 91.859 11.862 91.895 ;
     RECT  71.28 91.579 71.478 91.895 ;
     RECT  2.304 91.733 2.934 91.901 ;
     RECT  38.592 91.867 38.718 91.901 ;
     RECT  71.46 91.895 71.478 91.901 ;
     RECT  56.376 91.229 56.697 91.903 ;
     RECT  57.456 91.831 57.474 91.903 ;
     RECT  72.615 91.741 72.954 91.903 ;
     RECT  56.376 91.903 57.474 91.931 ;
     RECT  38.592 91.901 38.61 91.949 ;
     RECT  56.415 91.931 57.474 91.949 ;
     RECT  15.588 91.757 20.07 91.967 ;
     RECT  14.4 91.625 14.85 92.011 ;
     RECT  10.26 91.895 11.538 92.129 ;
     RECT  14.4 92.011 15.21 92.129 ;
     RECT  16.02 91.967 20.07 92.129 ;
     RECT  78.015 91.421 78.297 92.137 ;
     RECT  2.304 91.901 2.826 92.165 ;
     RECT  14.4 92.129 14.742 92.165 ;
     RECT  10.26 92.129 11.106 92.237 ;
     RECT  33.732 91.613 33.75 92.245 ;
     RECT  49.356 91.667 49.374 92.245 ;
     RECT  80.388 91.355 80.406 92.245 ;
     RECT  83.415 90.689 84.294 92.245 ;
     RECT  16.128 92.129 16.326 92.273 ;
     RECT  2.304 92.165 2.697 92.309 ;
     RECT  76.428 91.193 76.446 92.309 ;
     RECT  16.128 92.273 16.146 92.333 ;
     RECT  10.26 92.237 11.034 92.399 ;
     RECT  17.208 92.129 19.962 92.399 ;
     RECT  33.732 92.245 33.822 92.399 ;
     RECT  37.836 91.975 37.854 92.399 ;
     RECT  49.356 92.245 49.626 92.399 ;
     RECT  69.372 91.859 69.39 92.399 ;
     RECT  2.376 92.309 2.697 92.435 ;
     RECT  10.26 92.399 10.89 92.435 ;
     RECT  17.208 92.399 17.226 92.435 ;
     RECT  18.504 92.399 19.71 92.435 ;
     RECT  60.84 91.661 60.858 92.507 ;
     RECT  25.524 91.589 25.686 92.515 ;
     RECT  33.732 92.399 33.786 92.515 ;
     RECT  40.215 91.741 40.878 92.515 ;
     RECT  18.504 92.435 19.422 92.543 ;
     RECT  10.26 92.435 10.494 92.551 ;
     RECT  13.215 91.589 13.497 92.551 ;
     RECT  14.4 92.165 14.49 92.551 ;
     RECT  22.68 91.589 22.734 92.551 ;
     RECT  45.432 91.613 45.897 92.551 ;
     RECT  77.472 92.137 78.297 92.551 ;
     RECT  88.344 91.697 89.097 92.551 ;
     RECT  2.415 92.435 2.697 92.627 ;
     RECT  7.815 90.545 8.097 92.627 ;
     RECT  24.015 91.589 24.297 92.627 ;
     RECT  34.815 91.373 35.097 92.627 ;
     RECT  40.215 92.515 41.094 92.627 ;
     RECT  45.18 92.551 45.897 92.627 ;
     RECT  51.015 87.809 51.297 92.627 ;
     RECT  61.815 2.413 62.097 92.627 ;
     RECT  67.215 91.229 67.497 92.627 ;
     RECT  77.292 92.551 78.297 92.627 ;
     RECT  83.415 92.245 84.51 92.627 ;
     RECT  88.056 92.551 89.097 92.627 ;
     RECT  10.116 92.551 10.494 92.669 ;
     RECT  13.215 92.551 14.49 92.669 ;
     RECT  18.504 92.543 19.278 92.669 ;
     RECT  22.284 92.551 22.734 92.669 ;
     RECT  25.452 92.515 25.686 92.669 ;
     RECT  29.415 91.769 30.222 92.669 ;
     RECT  33.66 92.515 33.786 92.669 ;
     RECT  37.548 92.551 37.566 92.669 ;
     RECT  41.076 92.627 41.094 92.669 ;
     RECT  45.18 92.627 45.705 92.669 ;
     RECT  53.028 91.975 53.046 92.669 ;
     RECT  60.984 92.515 61.002 92.669 ;
     RECT  65.052 91.661 65.07 92.669 ;
     RECT  69.084 92.551 69.102 92.669 ;
     RECT  72.615 91.903 73.386 92.669 ;
     RECT  77.292 92.627 78.105 92.669 ;
     RECT  80.208 92.245 80.406 92.669 ;
     RECT  84.384 92.627 84.51 92.669 ;
     RECT  10.116 92.669 10.35 92.705 ;
     RECT  13.215 92.669 14.418 92.705 ;
     RECT  22.284 92.669 22.626 92.705 ;
     RECT  29.415 92.669 30.042 92.705 ;
     RECT  72.615 92.669 73.278 92.705 ;
     RECT  88.056 92.627 88.905 92.705 ;
     RECT  56.415 91.949 56.97 92.785 ;
     RECT  61.815 92.627 61.905 92.785 ;
     RECT  9.972 92.785 9.99 92.861 ;
     RECT  13.215 92.705 13.914 92.861 ;
     RECT  18.504 92.669 18.705 92.861 ;
     RECT  25.74 92.785 25.758 92.861 ;
     RECT  29.415 92.705 29.682 92.861 ;
     RECT  33.768 92.669 33.786 92.861 ;
     RECT  41.328 92.785 41.346 92.861 ;
     RECT  53.172 92.785 53.19 92.861 ;
     RECT  56.415 92.785 57.114 92.861 ;
     RECT  61.2 92.785 61.905 92.861 ;
     RECT  77.256 92.785 77.274 92.861 ;
     RECT  80.604 92.785 80.622 92.861 ;
     RECT  84.528 92.785 84.546 92.861 ;
     RECT  2.415 92.627 2.505 92.897 ;
     RECT  7.815 92.627 7.905 92.897 ;
     RECT  13.215 92.861 13.305 92.897 ;
     RECT  18.615 92.861 18.705 92.897 ;
     RECT  24.015 92.627 24.105 92.897 ;
     RECT  29.415 92.861 29.505 92.897 ;
     RECT  34.815 92.627 34.905 92.897 ;
     RECT  40.215 92.627 40.305 92.897 ;
     RECT  45.216 92.669 45.705 92.897 ;
     RECT  51.015 92.627 51.105 92.897 ;
     RECT  56.415 92.861 56.505 92.897 ;
     RECT  61.815 92.861 61.905 92.897 ;
     RECT  67.215 92.627 67.305 92.897 ;
     RECT  72.615 92.705 72.882 92.897 ;
     RECT  78.015 92.669 78.105 92.897 ;
     RECT  83.415 92.627 83.505 92.897 ;
     RECT  88.815 92.705 88.905 92.897 ;
     RECT  22.104 92.785 22.122 94.109 ;
     RECT  37.404 92.785 37.422 94.109 ;
     RECT  45.216 92.897 45.234 94.109 ;
     RECT  49.284 92.551 49.302 94.109 ;
     RECT  65.304 92.785 65.322 94.109 ;
     RECT  68.94 92.785 68.958 94.109 ;
     RECT  72.864 92.897 72.882 94.109 ;
     RECT  87.984 92.785 88.002 94.109 ;
    LAYER M4 ;
     RECT  0.156 4.32 0.229 90.6 ;
     RECT  0.325 91.968 0.373 91.992 ;
     RECT  0.373 91.872 0.421 91.992 ;
     RECT  0.229 4.32 0.569 90.84 ;
     RECT  0.569 4.32 2.408 4.632 ;
     RECT  0.569 5.616 2.408 90.84 ;
     RECT  0.421 91.872 2.408 92.424 ;
     RECT  2.408 2.148 2.512 92.892 ;
     RECT  2.512 2.418 2.704 92.622 ;
     RECT  2.704 3.696 2.819 3.72 ;
     RECT  2.704 5.472 2.819 91.896 ;
     RECT  2.819 5.712 2.945 91.896 ;
     RECT  2.945 5.712 4.241 91.08 ;
     RECT  4.241 5.712 4.349 47.208 ;
     RECT  4.349 6.048 4.385 47.208 ;
     RECT  4.385 7.44 4.457 26.664 ;
     RECT  4.457 7.44 4.529 10.392 ;
     RECT  4.241 48.24 4.529 91.08 ;
     RECT  4.529 7.44 4.565 9.864 ;
     RECT  4.385 27.648 4.565 47.208 ;
     RECT  4.529 67.248 4.565 91.08 ;
     RECT  4.565 80.256 4.633 91.08 ;
     RECT  4.565 27.648 4.673 34.2 ;
     RECT  4.565 35.28 4.673 47.208 ;
     RECT  4.529 48.24 4.673 65.832 ;
     RECT  4.673 39.792 4.925 47.208 ;
     RECT  4.673 35.28 5.033 38.76 ;
     RECT  4.385 6.048 5.069 6.072 ;
     RECT  4.673 53.472 5.069 65.832 ;
     RECT  4.565 7.44 5.105 9.72 ;
     RECT  4.457 11.376 5.105 26.664 ;
     RECT  5.105 16.368 5.177 26.664 ;
     RECT  5.105 7.44 5.213 9.24 ;
     RECT  4.673 48.24 5.249 52.44 ;
     RECT  5.069 53.664 5.249 65.832 ;
     RECT  5.249 53.76 5.321 65.832 ;
     RECT  5.177 16.656 5.353 26.664 ;
     RECT  4.673 27.648 5.353 33.96 ;
     RECT  5.213 7.44 5.429 9 ;
     RECT  5.353 16.656 5.429 33.96 ;
     RECT  5.105 11.376 5.465 12.504 ;
     RECT  4.633 80.256 5.465 91.224 ;
     RECT  4.565 67.248 5.497 79.224 ;
     RECT  5.105 14.784 5.501 15.384 ;
     RECT  5.465 80.256 5.501 83.784 ;
     RECT  5.497 66.912 5.573 79.224 ;
     RECT  5.501 14.784 5.609 14.856 ;
     RECT  5.429 30.192 5.641 33.96 ;
     RECT  4.925 43.872 5.641 47.208 ;
     RECT  5.249 48.24 5.641 48.792 ;
     RECT  5.429 16.656 5.645 29.064 ;
     RECT  5.249 50.064 5.645 52.44 ;
     RECT  5.645 16.656 5.681 27.912 ;
     RECT  5.033 35.28 5.681 38.664 ;
     RECT  5.321 53.76 5.753 65.016 ;
     RECT  4.237 4.56 5.785 4.584 ;
     RECT  5.573 66.912 5.785 73.512 ;
     RECT  5.681 35.28 5.789 36.888 ;
     RECT  5.681 38.256 5.789 38.664 ;
     RECT  5.785 66.48 5.789 73.512 ;
     RECT  5.573 74.832 5.789 79.224 ;
     RECT  5.785 4.56 5.825 6.024 ;
     RECT  5.465 12.384 5.825 12.504 ;
     RECT  5.105 13.632 5.825 13.656 ;
     RECT  5.465 84.816 5.861 91.224 ;
     RECT  5.789 66.48 5.897 70.344 ;
     RECT  5.789 78.048 5.965 79.224 ;
     RECT  5.501 80.256 5.965 83.64 ;
     RECT  5.681 17.328 6.005 27.912 ;
     RECT  5.429 7.824 6.035 9 ;
     RECT  5.948 10.56 6.035 10.584 ;
     RECT  5.641 30.192 6.041 34.104 ;
     RECT  6.041 30.192 6.077 32.424 ;
     RECT  5.861 84.816 6.113 91.08 ;
     RECT  5.645 29.04 6.149 29.064 ;
     RECT  6.005 17.328 6.275 27.768 ;
     RECT  5.789 72.384 6.275 73.512 ;
     RECT  5.789 74.832 6.275 77.064 ;
     RECT  5.645 50.688 6.277 52.44 ;
     RECT  5.753 53.76 6.277 55.608 ;
     RECT  5.789 35.28 6.287 35.352 ;
     RECT  5.897 66.48 6.293 70.008 ;
     RECT  5.641 43.872 6.323 48.792 ;
     RECT  6.277 50.688 6.323 55.608 ;
     RECT  6.041 33.408 6.329 34.104 ;
     RECT  5.789 36.528 6.329 36.888 ;
     RECT  6.323 43.872 6.329 44.616 ;
     RECT  6.275 17.328 6.365 19.944 ;
     RECT  5.753 56.784 6.38 65.016 ;
     RECT  4.925 39.792 6.401 42.504 ;
     RECT  6.275 74.832 6.437 75.384 ;
     RECT  6.035 7.92 6.469 9 ;
     RECT  6.323 50.688 6.473 53.592 ;
     RECT  6.365 17.328 6.545 19.896 ;
     RECT  6.323 54.576 6.545 55.608 ;
     RECT  5.789 38.64 6.577 38.664 ;
     RECT  6.401 39.792 6.577 42.168 ;
     RECT  6.329 36.864 6.581 36.888 ;
     RECT  6.113 84.816 6.581 90.6 ;
     RECT  6.577 38.64 6.617 42.168 ;
     RECT  6.329 44.16 6.617 44.472 ;
     RECT  6.581 84.912 6.617 90.6 ;
     RECT  5.825 12.384 6.649 12.408 ;
     RECT  6.545 55.248 6.653 55.608 ;
     RECT  6.38 56.784 6.653 65.112 ;
     RECT  6.437 74.832 6.689 74.856 ;
     RECT  6.473 50.688 6.721 52.44 ;
     RECT  6.653 63.648 6.761 65.112 ;
     RECT  6.275 21.072 6.797 27.768 ;
     RECT  6.653 56.784 6.829 62.232 ;
     RECT  5.609 14.832 6.833 14.856 ;
     RECT  6.829 56.688 6.833 62.232 ;
     RECT  5.965 78.048 6.853 83.64 ;
     RECT  5.825 5.136 6.865 6.024 ;
     RECT  6.329 33.6 6.937 34.104 ;
     RECT  6.287 35.088 6.937 35.352 ;
     RECT  5.789 71.328 7.117 71.352 ;
     RECT  7.037 29.088 7.153 29.112 ;
     RECT  6.077 30.288 7.153 32.424 ;
     RECT  7.081 15.552 7.189 15.576 ;
     RECT  6.545 17.328 7.189 18.216 ;
     RECT  6.721 50.544 7.189 52.44 ;
     RECT  6.275 72.384 7.261 72.456 ;
     RECT  6.275 73.488 7.261 73.512 ;
     RECT  6.275 76.56 7.333 77.064 ;
     RECT  6.853 78.048 7.333 83.832 ;
     RECT  6.937 33.6 7.381 35.352 ;
     RECT  6.323 47.856 7.381 48.792 ;
     RECT  7.189 49.872 7.381 52.44 ;
     RECT  6.293 66.72 7.405 70.008 ;
     RECT  6.865 5.04 7.477 6.024 ;
     RECT  6.761 64.992 7.669 65.112 ;
     RECT  7.405 66.192 7.669 70.008 ;
     RECT  6.653 55.584 7.693 55.608 ;
     RECT  6.833 56.688 7.693 57.864 ;
     RECT  7.117 71.184 7.693 71.352 ;
     RECT  7.261 72.384 7.693 73.512 ;
     RECT  7.477 5.04 7.808 6.888 ;
     RECT  6.469 7.92 7.808 10.344 ;
     RECT  6.649 11.616 7.808 12.408 ;
     RECT  6.937 13.584 7.808 13.608 ;
     RECT  7.189 15.552 7.808 18.216 ;
     RECT  6.545 19.248 7.808 19.896 ;
     RECT  6.797 21.072 7.808 25.128 ;
     RECT  6.797 26.208 7.808 27.768 ;
     RECT  7.153 29.088 7.808 32.424 ;
     RECT  7.381 33.6 7.808 36.12 ;
     RECT  6.829 38.016 7.808 38.472 ;
     RECT  6.617 39.6 7.808 42.168 ;
     RECT  6.617 44.448 7.808 44.472 ;
     RECT  6.323 45.696 7.808 46.776 ;
     RECT  7.381 47.856 7.808 52.44 ;
     RECT  6.473 53.568 7.808 53.592 ;
     RECT  7.693 55.584 7.808 57.864 ;
     RECT  6.833 59.232 7.808 62.232 ;
     RECT  6.761 63.648 7.808 63.672 ;
     RECT  7.669 64.992 7.808 70.008 ;
     RECT  7.693 71.184 7.808 73.512 ;
     RECT  7.333 76.56 7.808 83.832 ;
     RECT  6.617 85.2 7.808 90.6 ;
     RECT  7.808 2.148 7.912 92.892 ;
     RECT  7.912 2.418 8.104 92.622 ;
     RECT  8.104 21.984 8.129 22.056 ;
     RECT  8.104 60.48 8.129 61.464 ;
     RECT  8.104 71.184 8.129 73.512 ;
     RECT  8.104 29.76 8.165 30.84 ;
     RECT  8.104 32.304 8.201 32.328 ;
     RECT  8.104 67.152 8.201 67.176 ;
     RECT  8.104 76.752 8.201 77.064 ;
     RECT  8.104 4.896 8.237 6.888 ;
     RECT  8.104 44.448 8.237 46.776 ;
     RECT  8.104 62.592 8.237 62.616 ;
     RECT  8.104 26.208 8.243 26.856 ;
     RECT  8.165 30.192 8.243 30.84 ;
     RECT  8.104 34.128 8.243 34.152 ;
     RECT  8.104 35.472 8.243 36.456 ;
     RECT  8.104 38.688 8.243 38.712 ;
     RECT  8.104 54.48 8.243 54.504 ;
     RECT  8.104 55.776 8.243 56.568 ;
     RECT  8.129 60.48 8.243 60.936 ;
     RECT  8.104 85.104 8.243 89.544 ;
     RECT  8.243 30.816 8.245 30.84 ;
     RECT  8.237 6 8.273 6.888 ;
     RECT  8.104 14.496 8.281 16.296 ;
     RECT  8.104 40.224 8.281 40.248 ;
     RECT  8.104 59.424 8.284 59.448 ;
     RECT  8.104 17.616 8.309 17.64 ;
     RECT  8.243 36.096 8.309 36.456 ;
     RECT  8.104 64.992 8.309 65.016 ;
     RECT  8.129 71.184 8.381 71.832 ;
     RECT  8.104 83.232 8.381 83.784 ;
     RECT  8.243 85.92 8.381 89.544 ;
     RECT  8.104 47.76 8.387 47.88 ;
     RECT  8.129 73.056 8.387 73.512 ;
     RECT  8.381 83.232 8.387 83.256 ;
     RECT  8.104 13.056 8.417 13.08 ;
     RECT  8.281 14.496 8.417 14.52 ;
     RECT  8.104 50.16 8.425 50.184 ;
     RECT  8.104 75.744 8.453 75.768 ;
     RECT  8.104 25.056 8.483 25.176 ;
     RECT  8.381 85.92 8.483 87.48 ;
     RECT  8.273 6 8.489 6.024 ;
     RECT  8.483 85.92 8.525 87.336 ;
     RECT  8.237 45.312 8.531 46.776 ;
     RECT  8.309 36.432 8.633 36.456 ;
     RECT  8.525 85.92 8.633 85.944 ;
     RECT  8.531 46.128 8.669 46.152 ;
     RECT  8.387 73.488 8.669 73.512 ;
     RECT  8.243 60.48 8.777 60.504 ;
     RECT  8.104 80.352 8.849 81.48 ;
     RECT  8.381 71.424 8.877 71.832 ;
     RECT  8.243 26.208 9.059 26.328 ;
     RECT  8.877 71.808 9.101 71.832 ;
     RECT  8.104 78.624 9.173 78.648 ;
     RECT  8.849 81.456 9.173 81.48 ;
     RECT  8.129 22.032 9.209 22.056 ;
     RECT  8.849 80.352 9.209 80.376 ;
     RECT  8.104 90.528 9.209 90.6 ;
     RECT  8.104 8.496 9.317 8.52 ;
     RECT  9.059 26.304 9.317 26.328 ;
     RECT  8.281 16.08 9.353 16.296 ;
     RECT  8.525 87.312 9.389 87.336 ;
     RECT  8.381 88.608 9.601 89.544 ;
     RECT  9.209 90.528 9.601 90.552 ;
     RECT  9.601 88.608 10.019 90.552 ;
     RECT  8.237 4.896 10.067 4.92 ;
     RECT  9.98 5.952 10.067 5.976 ;
     RECT  9.961 92.832 10.211 92.856 ;
     RECT  10.019 89.616 10.829 90.552 ;
     RECT  10.249 91.584 11.873 91.608 ;
     RECT  10.019 88.608 12.133 88.632 ;
     RECT  10.829 90.432 12.133 90.552 ;
     RECT  12.133 88.608 12.179 90.552 ;
     RECT  12.179 88.944 12.22 90.552 ;
     RECT  10.021 3.6 13.208 3.624 ;
     RECT  9.353 16.272 13.208 16.296 ;
     RECT  8.483 25.152 13.208 25.176 ;
     RECT  8.387 47.856 13.208 47.88 ;
     RECT  8.104 52.416 13.208 52.44 ;
     RECT  8.104 69.696 13.208 70.008 ;
     RECT  8.201 76.752 13.208 76.776 ;
     RECT  12.22 88.944 13.208 89.304 ;
     RECT  12.22 90.432 13.208 90.552 ;
     RECT  13.208 2.148 13.312 92.892 ;
     RECT  13.312 2.418 13.504 92.856 ;
     RECT  13.504 89.28 13.925 90.6 ;
     RECT  13.504 92.832 14.195 92.856 ;
     RECT  13.925 89.28 14.497 89.304 ;
     RECT  14.497 88.944 14.581 89.304 ;
     RECT  14.581 88.896 14.627 89.304 ;
     RECT  14.627 88.896 14.668 88.968 ;
     RECT  13.925 90.48 15.359 90.6 ;
     RECT  14.668 88.944 15.836 88.968 ;
     RECT  15.836 88.32 15.877 88.968 ;
     RECT  15.359 90.24 15.877 90.6 ;
     RECT  15.877 88.32 15.923 90.6 ;
     RECT  15.923 88.896 16.009 90.6 ;
     RECT  16.009 88.896 17.089 91.08 ;
     RECT  16.117 92.304 17.089 92.328 ;
     RECT  17.089 88.896 17.525 92.328 ;
     RECT  17.525 88.896 17.809 91.08 ;
     RECT  17.809 88.704 17.953 91.08 ;
     RECT  17.525 92.304 18.229 92.328 ;
     RECT  18.229 92.304 18.565 92.856 ;
     RECT  13.504 3.6 18.608 3.624 ;
     RECT  13.504 16.272 18.608 16.296 ;
     RECT  13.504 25.152 18.608 25.176 ;
     RECT  13.504 47.856 18.608 47.88 ;
     RECT  13.504 52.416 18.608 52.44 ;
     RECT  13.504 69.696 18.608 70.008 ;
     RECT  13.504 76.752 18.608 76.776 ;
     RECT  17.953 88.176 18.608 91.08 ;
     RECT  18.565 92.208 18.608 92.856 ;
     RECT  18.608 2.148 18.712 92.892 ;
     RECT  18.745 0.192 18.851 0.216 ;
     RECT  18.712 2.418 18.904 92.622 ;
     RECT  18.904 87.84 19.073 92.376 ;
     RECT  18.904 3.6 19.181 3.624 ;
     RECT  19.073 87.888 19.937 92.376 ;
     RECT  19.937 87.984 19.955 92.376 ;
     RECT  19.955 87.984 20.477 91.896 ;
     RECT  20.477 88.128 21.841 91.896 ;
     RECT  21.841 87.792 22.277 91.896 ;
     RECT  22.277 87.792 22.349 88.152 ;
     RECT  22.093 94.08 22.403 94.104 ;
     RECT  22.277 89.232 22.529 91.896 ;
     RECT  18.904 69.696 22.853 70.008 ;
     RECT  18.904 16.272 24.008 16.296 ;
     RECT  18.904 25.152 24.008 25.176 ;
     RECT  18.904 47.856 24.008 47.88 ;
     RECT  18.904 52.416 24.008 52.44 ;
     RECT  22.853 69.792 24.008 70.008 ;
     RECT  18.904 76.752 24.008 76.776 ;
     RECT  22.349 87.84 24.008 88.152 ;
     RECT  22.529 90.096 24.008 91.896 ;
     RECT  24.008 2.148 24.112 92.892 ;
     RECT  24.112 2.418 24.304 92.622 ;
     RECT  24.304 89.472 24.419 91.896 ;
     RECT  24.304 69.648 24.545 70.008 ;
     RECT  24.304 15.408 24.761 16.536 ;
     RECT  24.304 25.104 24.761 25.992 ;
     RECT  24.761 15.408 24.803 15.432 ;
     RECT  24.545 69.648 24.851 69.816 ;
     RECT  24.851 69.792 25.157 69.816 ;
     RECT  24.419 90.096 25.729 91.896 ;
     RECT  25.729 90.096 26.003 92.856 ;
     RECT  24.304 3.552 29.408 3.576 ;
     RECT  24.761 25.968 29.408 25.992 ;
     RECT  24.304 47.856 29.408 47.88 ;
     RECT  24.304 52.416 29.408 52.44 ;
     RECT  24.304 67.536 29.408 67.56 ;
     RECT  24.304 76.752 29.408 76.776 ;
     RECT  26.003 90.096 29.408 91.896 ;
     RECT  29.408 2.148 29.512 92.892 ;
     RECT  29.512 2.418 29.704 92.856 ;
     RECT  29.704 90.096 29.939 92.856 ;
     RECT  29.939 90.096 30.485 91.896 ;
     RECT  30.485 90.768 33.757 91.896 ;
     RECT  29.704 3.552 34.808 3.576 ;
     RECT  29.704 25.968 34.808 25.992 ;
     RECT  29.704 47.856 34.808 47.88 ;
     RECT  29.704 52.416 34.808 52.44 ;
     RECT  29.704 67.536 34.808 67.56 ;
     RECT  29.704 76.752 34.808 76.776 ;
     RECT  33.757 90.768 34.808 92.856 ;
     RECT  34.808 2.148 34.912 92.892 ;
     RECT  34.912 2.418 35.104 92.622 ;
     RECT  37.393 94.08 37.667 94.104 ;
     RECT  35.104 67.536 38.509 67.56 ;
     RECT  35.104 90.816 38.581 91.896 ;
     RECT  38.581 90.816 38.585 91.944 ;
     RECT  38.509 67.392 38.873 67.56 ;
     RECT  35.104 25.968 39.913 25.992 ;
     RECT  35.104 3.552 40.208 3.576 ;
     RECT  39.913 25.968 40.208 26.088 ;
     RECT  35.104 47.856 40.208 47.88 ;
     RECT  35.104 52.416 40.208 52.44 ;
     RECT  38.873 67.392 40.208 67.416 ;
     RECT  35.104 76.752 40.208 76.776 ;
     RECT  38.585 90.864 40.208 91.944 ;
     RECT  40.208 2.148 40.312 92.892 ;
     RECT  40.312 2.418 40.504 92.622 ;
     RECT  40.504 90.864 41.317 92.622 ;
     RECT  41.317 90.864 41.603 92.856 ;
     RECT  40.504 3.552 45.608 3.576 ;
     RECT  40.504 26.064 45.608 26.088 ;
     RECT  40.504 47.856 45.608 47.88 ;
     RECT  40.504 52.416 45.608 52.44 ;
     RECT  40.504 67.392 45.608 67.416 ;
     RECT  40.504 76.752 45.608 76.776 ;
     RECT  41.603 90.864 45.608 91.944 ;
     RECT  45.608 2.148 45.712 92.892 ;
     RECT  45.205 94.08 45.731 94.104 ;
     RECT  45.712 2.418 45.904 92.622 ;
     RECT  45.904 90.048 46.547 91.944 ;
     RECT  45.904 59.472 46.933 59.496 ;
     RECT  46.933 59.472 47.017 59.832 ;
     RECT  45.904 47.856 47.581 47.88 ;
     RECT  47.557 2.304 47.801 2.328 ;
     RECT  47.581 47.856 47.837 48.264 ;
     RECT  45.904 26.064 48.013 26.088 ;
     RECT  45.904 76.752 48.053 76.776 ;
     RECT  47.996 34.416 48.083 34.44 ;
     RECT  47.017 59.472 48.179 59.496 ;
     RECT  48.188 72.336 48.229 72.36 ;
     RECT  48.229 72.336 48.275 72.84 ;
     RECT  48.013 26.064 48.305 26.568 ;
     RECT  47.977 20.544 48.421 20.568 ;
     RECT  48.193 78.048 48.421 78.072 ;
     RECT  48.373 34.224 48.457 34.248 ;
     RECT  48.421 19.872 48.467 20.568 ;
     RECT  48.421 78.048 48.467 79.032 ;
     RECT  45.904 52.416 49.277 52.44 ;
     RECT  48.229 70.848 49.388 70.872 ;
     RECT  49.388 70.656 49.429 70.872 ;
     RECT  49.429 70.656 49.475 71.64 ;
     RECT  47.837 47.856 49.673 47.88 ;
     RECT  49.273 94.08 49.811 94.104 ;
     RECT  48.467 19.872 51.008 19.896 ;
     RECT  48.305 26.16 51.008 26.568 ;
     RECT  50.713 54.336 51.008 54.36 ;
     RECT  45.904 67.392 51.008 67.416 ;
     RECT  49.475 70.848 51.008 71.64 ;
     RECT  48.275 72.816 51.008 72.84 ;
     RECT  48.467 79.008 51.008 79.032 ;
     RECT  46.547 90.864 51.008 91.944 ;
     RECT  51.008 2.148 51.112 92.892 ;
     RECT  51.112 2.418 51.304 92.622 ;
     RECT  51.304 90.864 52.477 91.944 ;
     RECT  52.477 90.576 52.739 91.944 ;
     RECT  52.739 90.864 53.161 91.944 ;
     RECT  53.161 90.864 53.411 92.856 ;
     RECT  51.304 67.392 54.749 67.416 ;
     RECT  55.237 67.536 55.324 67.56 ;
     RECT  51.304 19.872 56.408 19.896 ;
     RECT  51.304 26.064 56.408 26.568 ;
     RECT  51.304 54.336 56.408 54.36 ;
     RECT  55.237 69.552 56.408 69.576 ;
     RECT  51.304 70.848 56.408 71.64 ;
     RECT  51.304 72.816 56.408 72.84 ;
     RECT  51.304 79.008 56.408 79.032 ;
     RECT  53.411 90.864 56.408 91.944 ;
     RECT  56.408 2.148 56.512 92.892 ;
     RECT  56.512 2.418 56.704 92.856 ;
     RECT  56.704 90.864 57.395 92.856 ;
     RECT  57.395 90.864 57.485 91.944 ;
     RECT  57.485 90.864 60.685 91.608 ;
     RECT  56.704 19.872 61.808 19.896 ;
     RECT  56.704 25.968 61.808 26.568 ;
     RECT  56.704 54.336 61.808 54.36 ;
     RECT  56.704 69.696 61.808 69.72 ;
     RECT  56.704 70.848 61.808 71.64 ;
     RECT  56.704 72.816 61.808 72.84 ;
     RECT  56.704 79.008 61.808 79.032 ;
     RECT  60.685 90.864 61.808 91.656 ;
     RECT  61.189 92.832 61.808 92.856 ;
     RECT  61.808 2.148 61.912 92.892 ;
     RECT  61.912 2.418 62.104 92.622 ;
     RECT  62.104 90.864 64.469 91.656 ;
     RECT  65.293 94.08 65.603 94.104 ;
     RECT  62.104 69.696 67.093 69.72 ;
     RECT  62.104 19.872 67.208 19.896 ;
     RECT  62.104 25.968 67.208 26.568 ;
     RECT  62.104 54.336 67.208 54.36 ;
     RECT  67.093 69.696 67.208 69.816 ;
     RECT  62.104 70.848 67.208 71.64 ;
     RECT  62.104 72.816 67.208 72.84 ;
     RECT  62.104 79.008 67.208 79.032 ;
     RECT  64.469 90.864 67.208 91.608 ;
     RECT  67.208 2.148 67.312 92.892 ;
     RECT  67.312 2.418 67.504 92.622 ;
     RECT  67.504 69.792 68.861 69.816 ;
     RECT  68.929 94.08 69.203 94.104 ;
     RECT  67.504 70.848 70.369 71.64 ;
     RECT  67.504 90.864 71.449 91.608 ;
     RECT  70.369 69.888 71.459 71.64 ;
     RECT  67.504 25.968 72.241 26.568 ;
     RECT  67.504 19.872 72.608 19.896 ;
     RECT  72.241 25.44 72.608 26.568 ;
     RECT  67.504 54.336 72.608 54.36 ;
     RECT  71.459 69.984 72.608 71.64 ;
     RECT  67.504 72.816 72.608 72.84 ;
     RECT  67.504 79.008 72.608 79.032 ;
     RECT  71.413 82.224 72.608 82.248 ;
     RECT  71.449 90.864 72.608 91.896 ;
     RECT  72.608 2.148 72.712 92.892 ;
     RECT  72.712 2.418 72.904 92.622 ;
     RECT  72.853 94.08 73.139 94.104 ;
     RECT  72.904 24.912 73.549 26.568 ;
     RECT  72.904 82.224 74.617 82.248 ;
     RECT  74.617 82.128 74.657 82.248 ;
     RECT  75.445 3.36 75.539 3.384 ;
     RECT  72.904 90.864 76.307 91.896 ;
     RECT  76.633 2.304 76.717 2.328 ;
     RECT  75.493 6.912 78.008 6.936 ;
     RECT  72.904 19.872 78.008 19.896 ;
     RECT  73.549 24.912 78.008 25.464 ;
     RECT  73.549 26.544 78.008 26.568 ;
     RECT  72.904 54.336 78.008 54.36 ;
     RECT  72.904 69.984 78.008 71.64 ;
     RECT  72.904 72.816 78.008 72.84 ;
     RECT  72.904 79.008 78.008 79.032 ;
     RECT  74.657 82.128 78.008 82.152 ;
     RECT  76.307 90.864 78.008 91.416 ;
     RECT  77.221 92.832 78.008 92.856 ;
     RECT  78.008 2.148 78.112 92.892 ;
     RECT  78.112 2.418 78.304 92.622 ;
     RECT  78.304 91.2 78.653 91.416 ;
     RECT  78.653 91.2 80.021 91.32 ;
     RECT  80.593 92.832 80.867 92.856 ;
     RECT  78.304 6.912 83.408 6.936 ;
     RECT  78.304 19.872 83.408 19.896 ;
     RECT  78.304 24.912 83.408 25.464 ;
     RECT  78.304 26.544 83.408 26.568 ;
     RECT  78.304 54.336 83.408 54.36 ;
     RECT  78.304 69.984 83.408 71.64 ;
     RECT  78.304 72.816 83.408 72.84 ;
     RECT  78.304 79.008 83.408 79.032 ;
     RECT  78.304 82.128 83.408 82.152 ;
     RECT  80.021 91.2 83.408 91.224 ;
     RECT  83.408 2.148 83.512 92.892 ;
     RECT  83.512 2.418 83.704 92.622 ;
     RECT  84.517 92.832 84.803 92.856 ;
     RECT  83.704 24.912 85.705 25.464 ;
     RECT  83.704 26.544 85.705 26.568 ;
     RECT  85.916 89.856 85.957 89.88 ;
     RECT  85.957 88.944 86.003 89.88 ;
     RECT  83.704 6.528 86.005 6.984 ;
     RECT  85.741 7.968 86.005 7.992 ;
     RECT  86.005 6.528 86.051 7.992 ;
     RECT  83.704 90.912 86.137 91.224 ;
     RECT  83.704 69.984 86.173 71.64 ;
     RECT  83.704 72.816 86.173 72.84 ;
     RECT  83.704 54.336 86.425 54.36 ;
     RECT  86.051 6.528 86.501 7.416 ;
     RECT  85.489 45.552 86.605 45.576 ;
     RECT  85.705 24.912 86.629 26.568 ;
     RECT  86.173 69.984 86.629 72.84 ;
     RECT  86.501 6.528 86.641 6.552 ;
     RECT  86.137 90.768 86.641 91.224 ;
     RECT  86.533 28.512 86.675 28.536 ;
     RECT  86.629 24.912 86.677 27.336 ;
     RECT  86.677 24.768 86.716 27.336 ;
     RECT  86.716 24.768 86.725 26.808 ;
     RECT  86.317 44.448 86.725 44.472 ;
     RECT  86.605 45.552 86.725 45.912 ;
     RECT  86.725 44.448 86.771 45.912 ;
     RECT  86.629 69.312 86.785 72.84 ;
     RECT  86.533 16.656 86.821 16.68 ;
     RECT  86.209 33.024 86.821 33.048 ;
     RECT  86.641 6.48 86.825 6.552 ;
     RECT  83.704 79.008 86.828 79.032 ;
     RECT  86.173 80.736 86.828 80.76 ;
     RECT  86.317 10.464 86.857 10.488 ;
     RECT  85.777 11.664 86.857 11.688 ;
     RECT  86.353 77.952 86.869 77.976 ;
     RECT  86.828 79.008 86.869 80.76 ;
     RECT  83.704 82.128 86.869 82.152 ;
     RECT  86.857 10.464 86.897 12.552 ;
     RECT  86.897 10.464 86.915 10.872 ;
     RECT  86.869 77.952 86.915 82.152 ;
     RECT  86.771 44.448 86.933 44.952 ;
     RECT  86.915 10.848 86.941 10.872 ;
     RECT  86.857 67.152 86.965 67.176 ;
     RECT  86.725 24.768 87.001 26.568 ;
     RECT  86.965 66.24 87.001 67.176 ;
     RECT  86.857 68.256 87.001 68.28 ;
     RECT  86.857 40.56 87.02 40.584 ;
     RECT  86.857 60.576 87.037 60.6 ;
     RECT  86.915 81.552 87.037 82.152 ;
     RECT  86.281 85.488 87.061 85.512 ;
     RECT  86.893 30.336 87.073 30.36 ;
     RECT  87.02 39.696 87.107 40.584 ;
     RECT  87.061 84.336 87.107 85.512 ;
     RECT  86.137 23.136 87.109 23.16 ;
     RECT  87.061 36.672 87.109 36.696 ;
     RECT  87.107 84.336 87.149 84.6 ;
     RECT  87.109 22.56 87.155 23.16 ;
     RECT  86.425 54.336 87.181 54.696 ;
     RECT  86.821 33.024 87.185 33.816 ;
     RECT  87.073 30.192 87.217 30.36 ;
     RECT  87.001 66.24 87.217 68.28 ;
     RECT  86.785 69.312 87.217 73.272 ;
     RECT  86.857 57.456 87.301 57.48 ;
     RECT  87.301 56.496 87.388 57.48 ;
     RECT  83.704 19.872 87.397 19.896 ;
     RECT  87.397 31.968 87.433 31.992 ;
     RECT  86.005 48.384 87.437 48.408 ;
     RECT  87.149 84.576 87.437 84.6 ;
     RECT  87.155 22.56 87.473 22.584 ;
     RECT  86.137 14.208 87.493 14.232 ;
     RECT  87.217 66.24 87.505 73.272 ;
     RECT  86.821 16.656 87.539 17.592 ;
     RECT  87.181 53.568 87.539 54.696 ;
     RECT  87.388 56.976 87.539 57.48 ;
     RECT  87.493 14.208 87.58 15.192 ;
     RECT  87.037 60.576 87.589 61.368 ;
     RECT  87.589 60.576 87.676 61.608 ;
     RECT  87.539 17.04 87.689 17.592 ;
     RECT  87.253 52.128 87.725 52.152 ;
     RECT  87.217 30.192 87.757 30.936 ;
     RECT  87.433 31.968 87.757 32.856 ;
     RECT  86.003 88.944 87.761 88.968 ;
     RECT  86.677 28.8 87.829 28.824 ;
     RECT  87.757 30.192 87.829 32.856 ;
     RECT  87.857 39.36 87.873 39.624 ;
     RECT  86.897 12.528 87.937 12.552 ;
     RECT  87.685 76.896 88.045 76.92 ;
     RECT  86.915 78.48 88.045 79.032 ;
     RECT  86.245 5.184 88.081 5.208 ;
     RECT  87.001 9.072 88.081 9.096 ;
     RECT  88.045 76.896 88.081 79.032 ;
     RECT  87.109 36.672 88.117 36.936 ;
     RECT  87.539 54.336 88.117 54.696 ;
     RECT  86.929 46.176 88.124 46.2 ;
     RECT  87.577 47.328 88.124 47.352 ;
     RECT  86.825 6.528 88.153 6.552 ;
     RECT  87.073 7.92 88.153 7.944 ;
     RECT  87.073 50.544 88.153 50.568 ;
     RECT  87.181 18.816 88.189 18.84 ;
     RECT  87.397 19.872 88.189 20.568 ;
     RECT  87.676 60.576 88.189 60.936 ;
     RECT  87.58 14.208 88.261 14.232 ;
     RECT  88.081 42.24 88.261 42.264 ;
     RECT  87.493 59.136 88.405 59.16 ;
     RECT  87.037 65.136 88.405 65.16 ;
     RECT  87.001 24.624 88.477 26.568 ;
     RECT  88.333 22.032 88.513 22.056 ;
     RECT  88.405 59.136 88.513 59.208 ;
     RECT  88.189 60.288 88.513 60.936 ;
     RECT  86.641 90.768 88.513 91.368 ;
     RECT  87.577 41.04 88.549 41.064 ;
     RECT  88.261 42.192 88.549 42.264 ;
     RECT  87.937 80.352 88.549 80.376 ;
     RECT  87.037 81.552 88.549 82.584 ;
     RECT  88.477 24.624 88.621 26.616 ;
     RECT  87.829 28.8 88.693 32.856 ;
     RECT  88.153 50.16 88.693 50.568 ;
     RECT  88.081 76.896 88.729 79.224 ;
     RECT  88.549 80.352 88.729 82.584 ;
     RECT  87.937 12.528 88.765 13.08 ;
     RECT  85.957 35.328 88.801 35.352 ;
     RECT  88.117 36.528 88.801 36.936 ;
     RECT  88.081 4.752 88.808 5.208 ;
     RECT  88.153 6.528 88.808 7.944 ;
     RECT  88.081 9.072 88.808 9.384 ;
     RECT  88.765 11.952 88.808 13.08 ;
     RECT  88.261 14.112 88.808 14.232 ;
     RECT  87.613 15.312 88.808 15.864 ;
     RECT  87.689 17.088 88.808 17.592 ;
     RECT  88.189 18.816 88.808 20.568 ;
     RECT  88.513 21.696 88.808 22.056 ;
     RECT  88.621 24.624 88.808 26.664 ;
     RECT  88.693 28.512 88.808 32.856 ;
     RECT  88.801 35.328 88.808 36.936 ;
     RECT  87.873 38.688 88.808 39.624 ;
     RECT  88.549 41.04 88.808 42.264 ;
     RECT  87.865 43.632 88.808 43.656 ;
     RECT  88.477 45.168 88.808 45.192 ;
     RECT  88.124 46.176 88.808 47.352 ;
     RECT  87.937 48.432 88.808 48.456 ;
     RECT  88.693 49.536 88.808 50.568 ;
     RECT  88.117 54.336 88.808 55.272 ;
     RECT  87.539 57.456 88.808 57.48 ;
     RECT  88.513 59.136 88.808 60.936 ;
     RECT  87.829 62.736 88.808 62.76 ;
     RECT  88.405 64.368 88.808 65.16 ;
     RECT  87.505 66.24 88.808 73.8 ;
     RECT  88.477 74.976 88.808 75 ;
     RECT  88.729 76.896 88.808 82.584 ;
     RECT  88.657 83.76 88.808 83.784 ;
     RECT  85.777 86.784 88.808 86.808 ;
     RECT  88.513 90.624 88.808 91.368 ;
     RECT  88.808 2.148 88.912 92.892 ;
     RECT  87.973 94.08 88.931 94.104 ;
     RECT  88.912 2.418 89.104 92.622 ;
     RECT  89.104 64.032 89.165 65.16 ;
     RECT  89.104 6.144 89.201 7.992 ;
     RECT  89.104 66.24 89.219 79.56 ;
     RECT  89.104 18.816 89.273 29.064 ;
     RECT  89.104 89.52 89.363 89.544 ;
     RECT  89.104 12.96 89.381 17.64 ;
     RECT  89.104 86.592 89.404 88.344 ;
     RECT  89.104 48.432 89.453 60.312 ;
     RECT  89.273 22.752 89.459 29.064 ;
     RECT  89.104 34.608 89.459 42.264 ;
     RECT  89.459 22.752 89.507 29.016 ;
     RECT  89.459 38.016 89.507 42.264 ;
     RECT  89.201 6.144 89.525 6.84 ;
     RECT  89.104 8.976 89.525 9.384 ;
     RECT  89.104 11.376 89.555 11.976 ;
     RECT  89.507 22.752 89.561 27.336 ;
     RECT  89.555 11.424 89.597 11.976 ;
     RECT  89.104 43.632 89.597 45.192 ;
     RECT  89.104 46.32 89.597 47.304 ;
     RECT  89.453 59.76 89.597 60.312 ;
     RECT  89.104 90.624 89.597 91.368 ;
     RECT  89.201 7.824 89.669 7.992 ;
     RECT  89.104 80.64 89.669 84.84 ;
     RECT  89.525 6.816 89.699 6.84 ;
     RECT  89.669 7.824 89.699 7.896 ;
     RECT  89.165 64.032 89.747 64.968 ;
     RECT  89.525 9.072 89.795 9.384 ;
     RECT  89.453 48.432 89.813 58.728 ;
     RECT  89.813 48.432 89.891 49.752 ;
     RECT  89.813 50.784 89.891 58.728 ;
     RECT  89.597 59.76 89.891 59.88 ;
     RECT  89.891 50.784 89.932 52.536 ;
     RECT  89.507 38.016 89.987 40.44 ;
     RECT  89.459 34.608 89.993 36.984 ;
     RECT  89.381 14.112 90.029 17.64 ;
     RECT  89.891 53.568 90.029 57.048 ;
     RECT  89.891 58.128 90.029 58.728 ;
     RECT  90.029 14.112 90.035 16.008 ;
     RECT  89.987 38.016 90.035 40.008 ;
     RECT  89.104 62.064 90.065 63 ;
     RECT  89.669 80.64 90.065 84.792 ;
     RECT  90.035 14.88 90.073 16.008 ;
     RECT  89.404 86.592 90.076 86.616 ;
     RECT  89.597 46.464 90.097 47.304 ;
     RECT  89.891 48.432 90.097 48.456 ;
     RECT  89.795 9.36 90.101 9.384 ;
     RECT  89.273 18.816 90.101 21.72 ;
     RECT  90.035 38.16 90.101 40.008 ;
     RECT  89.597 43.632 90.101 45.048 ;
     RECT  89.219 66.24 90.109 75.768 ;
     RECT  89.561 22.752 90.137 24.792 ;
     RECT  90.101 43.632 90.137 44.28 ;
     RECT  89.381 12.96 90.169 13.08 ;
     RECT  89.507 41.472 90.173 42.264 ;
     RECT  90.029 53.568 90.173 56.52 ;
     RECT  90.065 84.288 90.173 84.792 ;
     RECT  90.109 66.24 90.205 74.568 ;
     RECT  90.181 60.96 90.268 61.08 ;
     RECT  90.029 58.704 90.281 58.728 ;
     RECT  90.173 42.24 90.313 42.264 ;
     RECT  89.104 30.048 90.317 33.624 ;
     RECT  90.065 80.64 90.332 81.672 ;
     RECT  89.891 59.76 90.353 59.784 ;
     RECT  90.317 32.928 90.389 33.624 ;
     RECT  90.173 84.288 90.389 84.744 ;
     RECT  90.332 80.304 90.419 81.672 ;
     RECT  90.073 14.88 90.425 15.48 ;
     RECT  90.313 42.24 90.425 42.744 ;
     RECT  90.065 62.688 90.457 63 ;
     RECT  89.747 64.944 90.457 64.968 ;
     RECT  90.205 66.096 90.457 74.568 ;
     RECT  89.219 76.944 90.469 79.032 ;
     RECT  89.932 52.176 90.497 52.536 ;
     RECT  90.065 82.656 90.497 83.208 ;
     RECT  90.109 75.648 90.517 75.768 ;
     RECT  90.469 76.944 90.517 79.128 ;
     RECT  89.932 50.784 90.533 51 ;
     RECT  90.137 22.752 90.565 22.824 ;
     RECT  89.597 90.768 90.565 91.368 ;
     RECT  90.097 46.464 90.569 48.456 ;
     RECT  90.497 52.32 90.569 52.536 ;
     RECT  90.569 46.8 90.605 48.456 ;
     RECT  90.101 19.824 90.611 21.72 ;
     RECT  90.169 12.912 90.641 13.08 ;
     RECT  90.389 32.928 90.641 33.048 ;
     RECT  90.497 82.656 90.641 82.728 ;
     RECT  90.517 75.648 90.673 79.128 ;
     RECT  90.029 17.04 90.677 17.64 ;
     RECT  89.507 28.896 90.677 29.016 ;
     RECT  90.605 46.8 90.677 46.824 ;
     RECT  89.891 49.728 90.677 49.752 ;
     RECT  90.173 53.568 90.677 55.896 ;
     RECT  90.457 62.688 90.677 63.288 ;
     RECT  90.389 84.384 90.677 84.744 ;
     RECT  90.268 60.96 90.713 60.984 ;
     RECT  90.419 80.64 90.713 81.672 ;
     RECT  89.699 7.872 90.749 7.896 ;
     RECT  90.457 64.944 90.749 74.568 ;
     RECT  90.641 13.056 90.785 13.08 ;
     RECT  89.104 4.752 90.821 4.776 ;
     RECT  90.637 9.744 90.821 9.768 ;
     RECT  89.597 11.424 90.821 11.88 ;
     RECT  89.993 34.704 90.821 36.984 ;
     RECT  90.749 64.944 90.925 65.352 ;
     RECT  89.561 25.968 90.965 27.336 ;
     RECT  90.565 90.24 90.997 91.368 ;
     RECT  90.425 15.312 91.001 15.48 ;
     RECT  90.101 38.16 91.001 38.712 ;
     RECT  90.533 50.976 91.037 51 ;
     RECT  90.677 53.568 91.037 55.176 ;
     RECT  90.284 85.92 91.045 85.944 ;
     RECT  90.965 25.968 91.073 26.808 ;
     RECT  90.997 89.808 91.093 91.368 ;
     RECT  90.677 17.616 91.109 17.64 ;
     RECT  90.317 30.048 91.109 31.896 ;
     RECT  90.713 80.784 91.109 81.672 ;
     RECT  90.611 19.872 91.141 21.72 ;
     RECT  90.565 22.704 91.141 22.824 ;
     RECT  90.749 66.48 91.141 74.568 ;
     RECT  90.673 75.648 91.141 79.656 ;
     RECT  91.045 85.92 91.141 86.472 ;
     RECT  89.404 87.792 91.141 88.344 ;
     RECT  90.821 11.856 91.145 11.88 ;
     RECT  90.677 62.688 91.181 63 ;
     RECT  91.109 80.784 91.181 81.624 ;
     RECT  91.141 19.872 91.187 22.824 ;
     RECT  91.141 85.92 91.213 88.344 ;
     RECT  90.889 59.184 91.217 59.208 ;
     RECT  90.641 32.976 91.253 33.048 ;
     RECT  90.821 34.704 91.253 36.264 ;
     RECT  90.925 64.416 91.253 65.352 ;
     RECT  91.093 89.472 91.253 91.368 ;
     RECT  90.101 18.816 91.289 18.84 ;
     RECT  90.677 28.896 91.289 28.92 ;
     RECT  91.253 34.704 91.289 34.728 ;
     RECT  91.213 85.776 91.289 88.344 ;
     RECT  91.253 89.568 91.289 91.368 ;
     RECT  91.253 32.976 91.325 33 ;
     RECT  91.037 53.568 91.325 54.36 ;
     RECT  90.137 44.256 91.361 44.28 ;
     RECT  91.073 25.968 91.433 26.76 ;
     RECT  91.253 36.24 91.541 36.264 ;
     RECT  91.253 65.328 91.541 65.352 ;
     RECT  90.641 82.704 91.645 82.728 ;
     RECT  91.187 19.872 91.717 22.776 ;
     RECT  90.137 23.808 91.757 24.792 ;
     RECT  91.109 31.344 91.757 31.896 ;
     RECT  91.001 38.16 91.757 38.184 ;
     RECT  90.677 84.576 91.757 84.744 ;
     RECT  91.321 6.816 91.789 6.84 ;
     RECT  91.717 19.824 91.793 22.776 ;
     RECT  91.289 85.776 91.793 87.24 ;
     RECT  91.141 66.48 91.829 79.656 ;
     RECT  91.757 84.576 91.829 84.6 ;
     RECT  91.793 85.776 91.829 85.8 ;
     RECT  91.789 6.816 91.865 7.368 ;
     RECT  91.757 23.808 91.865 24.36 ;
     RECT  91.829 66.48 91.865 75.672 ;
     RECT  91.865 66.48 91.901 71.448 ;
     RECT  91.865 7.344 92.005 7.368 ;
     RECT  91.289 89.568 92.017 91.224 ;
     RECT  91.829 76.896 92.117 79.656 ;
     RECT  91.757 31.872 92.293 31.896 ;
     RECT  92.005 7.344 92.329 7.944 ;
     RECT  91.793 19.824 92.329 20.904 ;
     RECT  91.793 21.888 92.329 22.776 ;
     RECT  91.865 23.808 92.329 24.072 ;
     RECT  91.433 26.016 92.329 26.76 ;
     RECT  92.293 31.872 92.329 32.136 ;
     RECT  90.569 52.32 92.329 52.344 ;
     RECT  92.117 78.624 92.329 79.656 ;
     RECT  91.181 80.784 92.329 81.48 ;
     RECT  91.645 82.656 92.329 82.728 ;
     RECT  91.793 86.832 92.329 87.24 ;
     RECT  91.289 88.32 92.329 88.344 ;
     RECT  92.329 17.136 92.365 17.16 ;
     RECT  92.401 56.592 92.437 56.616 ;
     RECT  92.365 58.608 92.833 58.632 ;
     RECT  92.329 65.376 92.833 65.976 ;
     RECT  92.365 17.136 92.869 17.448 ;
     RECT  92.221 37.584 92.869 37.608 ;
     RECT  90.425 42.72 92.869 42.744 ;
     RECT  91.429 43.728 92.869 43.8 ;
     RECT  91.325 54.336 92.869 54.36 ;
     RECT  92.833 58.608 92.869 59.064 ;
     RECT  91.181 62.688 92.869 62.712 ;
     RECT  92.329 7.344 92.905 8.808 ;
     RECT  92.869 9.792 92.905 9.816 ;
     RECT  92.869 11.808 92.905 11.832 ;
     RECT  92.869 16.848 92.905 17.448 ;
     RECT  92.329 19.728 92.905 20.904 ;
     RECT  92.329 21.888 92.905 24.072 ;
     RECT  92.329 26.016 92.905 27.96 ;
     RECT  91.109 30.048 92.905 30.072 ;
     RECT  92.329 31.872 92.905 33 ;
     RECT  92.329 34.272 92.905 34.296 ;
     RECT  92.869 36.576 92.905 36.6 ;
     RECT  92.869 37.584 92.905 38.472 ;
     RECT  92.329 39.888 92.905 41.208 ;
     RECT  92.869 42.48 92.905 43.8 ;
     RECT  92.329 47.52 92.905 47.544 ;
     RECT  92.329 52.32 92.905 53.16 ;
     RECT  92.869 54.336 92.905 54.6 ;
     RECT  92.437 56.016 92.905 56.616 ;
     RECT  92.869 58.032 92.905 59.064 ;
     RECT  92.833 60.48 92.905 60.504 ;
     RECT  92.869 61.92 92.905 62.712 ;
     RECT  92.833 64.512 92.905 65.976 ;
     RECT  91.901 67.008 92.905 69.72 ;
     RECT  91.901 70.8 92.905 71.448 ;
     RECT  91.865 72.624 92.905 75.672 ;
     RECT  92.117 76.896 92.905 77.64 ;
     RECT  92.329 78.624 92.905 82.728 ;
     RECT  92.329 83.952 92.905 83.976 ;
     RECT  92.869 85.104 92.905 85.128 ;
     RECT  92.329 86.832 92.905 88.344 ;
     RECT  92.017 89.568 92.905 90.6 ;
     RECT  92.905 4.32 92.941 18.6 ;
     RECT  92.905 45.072 93.445 77.64 ;
     RECT  92.905 78.624 93.445 90.6 ;
     RECT  92.941 4.32 93.481 18.744 ;
     RECT  92.905 19.728 93.481 43.8 ;
     RECT  93.445 45.072 93.481 90.6 ;
     RECT  93.481 4.32 94.86 90.6 ;
    LAYER M5 ;
     RECT  2.4 2.137 2.52 2.151 ;
     RECT  7.8 2.137 7.92 2.151 ;
     RECT  13.2 2.137 13.32 2.151 ;
     RECT  18.6 2.137 18.72 2.151 ;
     RECT  24 2.137 24.12 2.151 ;
     RECT  29.4 2.137 29.52 2.151 ;
     RECT  34.8 2.137 34.92 2.151 ;
     RECT  40.2 2.137 40.32 2.151 ;
     RECT  45.6 2.137 45.72 2.151 ;
     RECT  51 2.137 51.12 2.151 ;
     RECT  56.4 2.137 56.52 2.151 ;
     RECT  61.8 2.137 61.92 2.151 ;
     RECT  67.2 2.137 67.32 2.151 ;
     RECT  72.6 2.137 72.72 2.151 ;
     RECT  78 2.137 78.12 2.151 ;
     RECT  83.4 2.137 83.52 2.151 ;
     RECT  88.8 2.137 88.92 2.151 ;
     RECT  24 2.151 24.312 3.541 ;
     RECT  2.4 2.151 2.712 3.685 ;
     RECT  7.8 2.151 8.112 5.029 ;
     RECT  2.4 3.685 2.808 5.507 ;
     RECT  7.392 5.029 8.112 5.747 ;
     RECT  10.032 3.589 10.056 5.987 ;
     RECT  88.8 2.151 89.112 6.133 ;
     RECT  2.4 5.507 2.712 6.661 ;
     RECT  88.8 6.133 89.304 6.805 ;
     RECT  2.4 6.661 2.856 6.851 ;
     RECT  75.504 3.349 75.528 6.947 ;
     RECT  88.8 6.805 89.688 7.859 ;
     RECT  6 5.989 6.024 7.909 ;
     RECT  7.8 5.747 8.112 7.909 ;
     RECT  86.016 6.949 86.04 8.003 ;
     RECT  88.8 7.859 89.304 9.061 ;
     RECT  4.56 9.061 4.584 9.731 ;
     RECT  6 7.909 8.112 9.779 ;
     RECT  2.4 6.851 2.712 10.117 ;
     RECT  2.064 10.117 2.712 10.259 ;
     RECT  86.88 10.453 86.904 10.883 ;
     RECT  2.256 10.259 2.712 11.219 ;
     RECT  7.8 9.779 8.112 12.181 ;
     RECT  6 9.779 6.024 12.419 ;
     RECT  88.8 9.061 89.784 12.949 ;
     RECT  7.68 12.181 8.112 13.045 ;
     RECT  4.512 12.325 4.536 13.139 ;
     RECT  7.68 13.045 8.232 15.443 ;
     RECT  24 3.541 24.792 15.443 ;
     RECT  88.8 12.949 90.024 16.019 ;
     RECT  24 15.443 24.312 16.501 ;
     RECT  0.288 14.101 0.312 16.547 ;
     RECT  87.504 14.197 87.528 17.075 ;
     RECT  0.192 16.981 0.216 17.557 ;
     RECT  0.192 17.557 0.264 17.843 ;
     RECT  0.192 17.843 0.216 17.939 ;
     RECT  6.24 17.317 6.264 18.181 ;
     RECT  7.68 15.443 8.112 18.181 ;
     RECT  5.856 18.181 8.112 18.851 ;
     RECT  2.4 11.219 2.712 18.853 ;
     RECT  2.304 18.853 2.712 18.995 ;
     RECT  88.8 16.019 89.976 19.379 ;
     RECT  6.24 18.851 8.112 19.571 ;
     RECT  88.8 19.379 89.304 20.533 ;
     RECT  90.576 19.813 90.6 20.533 ;
     RECT  48.432 19.861 48.456 20.579 ;
     RECT  87.792 19.909 87.816 20.579 ;
     RECT  91.728 19.813 91.752 20.579 ;
     RECT  88.8 20.533 90.6 20.627 ;
     RECT  0.288 19.717 0.312 21.155 ;
     RECT  88.8 20.627 90.072 21.395 ;
     RECT  7.8 19.571 8.112 22.021 ;
     RECT  90.576 21.637 90.6 22.117 ;
     RECT  91.68 21.973 91.704 22.117 ;
     RECT  7.68 22.021 8.112 22.211 ;
     RECT  0.336 21.589 0.456 22.549 ;
     RECT  2.4 18.995 2.712 22.645 ;
     RECT  90.576 22.117 91.704 22.739 ;
     RECT  2.4 22.645 3.432 22.741 ;
     RECT  4.656 21.781 4.68 22.741 ;
     RECT  91.152 22.739 91.704 22.787 ;
     RECT  2.4 22.741 4.68 22.835 ;
     RECT  91.152 22.787 91.176 22.835 ;
     RECT  87.12 22.549 87.144 23.171 ;
     RECT  2.4 22.835 3.96 23.315 ;
     RECT  6.24 19.571 6.264 23.411 ;
     RECT  2.4 23.315 3.432 23.459 ;
     RECT  0.192 22.549 0.456 23.507 ;
     RECT  0.288 23.507 0.456 23.605 ;
     RECT  0.288 23.605 0.504 24.227 ;
     RECT  90.576 23.797 91.176 24.611 ;
     RECT  72.6 2.151 72.912 24.901 ;
     RECT  7.8 22.211 8.112 25.045 ;
     RECT  24 16.501 24.744 25.139 ;
     RECT  7.8 25.045 8.472 25.141 ;
     RECT  88.8 21.395 89.304 25.429 ;
     RECT  0.288 24.227 0.408 25.715 ;
     RECT  72.6 24.901 73.512 25.715 ;
     RECT  0.336 25.715 0.408 25.763 ;
     RECT  0.336 25.763 0.36 25.859 ;
     RECT  24 25.139 24.408 26.003 ;
     RECT  7.8 25.141 9.048 26.243 ;
     RECT  2.4 23.459 2.712 26.293 ;
     RECT  7.8 26.243 8.472 26.339 ;
     RECT  2.304 26.293 2.712 26.531 ;
     RECT  86.688 24.757 86.712 26.819 ;
     RECT  7.8 26.339 8.232 26.867 ;
     RECT  6.48 26.245 6.504 27.205 ;
     RECT  7.8 26.867 8.112 27.205 ;
     RECT  6.48 27.205 8.112 27.301 ;
     RECT  2.4 26.531 2.712 27.781 ;
     RECT  2.4 27.781 2.808 27.877 ;
     RECT  88.8 25.429 89.496 27.971 ;
     RECT  2.4 27.877 2.856 28.163 ;
     RECT  0.288 27.781 0.312 28.451 ;
     RECT  2.4 28.163 2.808 28.547 ;
     RECT  86.64 27.301 86.664 28.547 ;
     RECT  88.8 27.971 89.112 29.029 ;
     RECT  4.08 27.877 4.104 29.123 ;
     RECT  6.432 27.301 8.112 29.123 ;
     RECT  88.8 29.029 89.448 29.605 ;
     RECT  0.288 29.509 0.312 30.133 ;
     RECT  2.4 28.547 2.712 30.181 ;
     RECT  7.8 29.123 8.112 30.181 ;
     RECT  0.288 30.133 0.36 30.373 ;
     RECT  0.288 30.373 0.552 30.517 ;
     RECT  2.4 30.181 2.808 30.563 ;
     RECT  7.8 30.181 8.232 30.851 ;
     RECT  0.192 30.517 0.552 30.899 ;
     RECT  87.84 29.605 89.448 31.379 ;
     RECT  0.528 30.899 0.552 31.427 ;
     RECT  6.432 29.123 6.456 31.813 ;
     RECT  6.336 31.813 6.456 31.859 ;
     RECT  6.336 31.859 6.36 33.589 ;
     RECT  7.8 30.851 8.112 33.589 ;
     RECT  88.8 31.379 89.448 33.635 ;
     RECT  86.832 33.013 86.856 33.827 ;
     RECT  6.336 33.589 8.112 34.115 ;
     RECT  7.8 34.115 8.112 34.117 ;
     RECT  48.384 26.149 48.408 34.259 ;
     RECT  2.4 30.563 2.712 34.885 ;
     RECT  2.304 34.885 2.712 35.027 ;
     RECT  7.8 34.117 8.232 35.077 ;
     RECT  6.336 34.115 6.36 35.123 ;
     RECT  88.8 33.635 89.208 35.989 ;
     RECT  0.288 36.277 0.312 36.515 ;
     RECT  0.288 37.477 0.312 37.763 ;
     RECT  88.8 35.989 89.448 38.005 ;
     RECT  2.4 35.027 2.712 38.149 ;
     RECT  7.392 35.077 8.232 38.437 ;
     RECT  87.072 35.317 87.096 38.677 ;
     RECT  88.8 38.005 90.024 38.677 ;
     RECT  2.4 38.149 2.856 38.963 ;
     RECT  87.072 38.677 90.024 39.203 ;
     RECT  87.072 39.203 89.496 39.395 ;
     RECT  0.432 39.445 0.456 39.877 ;
     RECT  4.512 37.429 4.536 40.019 ;
     RECT  0.336 39.877 0.456 40.067 ;
     RECT  6.912 38.437 8.232 40.259 ;
     RECT  88.8 39.395 89.496 40.405 ;
     RECT  0.336 40.067 0.36 40.595 ;
     RECT  87.072 39.395 87.096 40.595 ;
     RECT  6.912 40.259 8.112 40.741 ;
     RECT  6 40.741 8.112 40.787 ;
     RECT  88.8 40.405 89.976 44.483 ;
     RECT  6 40.787 6.024 45.013 ;
     RECT  7.8 40.787 8.112 45.301 ;
     RECT  86.736 44.917 86.76 45.541 ;
     RECT  6 45.013 6.312 45.731 ;
     RECT  86.016 45.541 86.76 45.923 ;
     RECT  88.8 44.483 89.688 46.165 ;
     RECT  2.4 38.963 2.712 46.549 ;
     RECT  2.4 46.549 2.808 46.691 ;
     RECT  3.936 46.597 3.96 46.787 ;
     RECT  7.8 45.301 8.52 46.787 ;
     RECT  88.176 46.165 89.688 46.787 ;
     RECT  88.176 46.787 89.112 47.363 ;
     RECT  6.288 45.731 6.312 47.555 ;
     RECT  7.8 46.787 8.112 47.749 ;
     RECT  48.048 34.405 48.072 47.845 ;
     RECT  48.048 47.845 48.168 47.891 ;
     RECT  86.016 45.923 86.04 48.419 ;
     RECT  6.576 47.845 6.6 48.421 ;
     RECT  7.8 47.749 8.376 48.421 ;
     RECT  88.8 47.363 89.112 49.333 ;
     RECT  6.576 48.421 8.376 50.195 ;
     RECT  5.088 48.997 5.112 50.291 ;
     RECT  6.576 50.195 8.112 50.677 ;
     RECT  5.904 50.677 8.112 50.867 ;
     RECT  2.4 46.691 2.712 51.205 ;
     RECT  2.304 51.205 2.712 51.395 ;
     RECT  7.8 50.867 8.112 54.469 ;
     RECT  5.904 50.867 6.6 54.565 ;
     RECT  87.504 53.557 87.528 54.611 ;
     RECT  5.856 54.565 6.6 55.237 ;
     RECT  5.568 55.237 6.6 55.573 ;
     RECT  7.8 54.469 8.232 55.573 ;
     RECT  5.568 55.573 8.232 55.619 ;
     RECT  5.568 55.619 5.592 55.955 ;
     RECT  87.312 54.661 87.336 56.531 ;
     RECT  4.512 55.237 4.536 58.739 ;
     RECT  2.4 51.395 2.712 58.885 ;
     RECT  2.304 58.885 2.712 59.027 ;
     RECT  87.504 56.965 87.528 59.171 ;
     RECT  6.576 55.619 8.232 59.459 ;
     RECT  0.192 59.269 0.216 59.461 ;
     RECT  48.144 47.891 48.168 59.507 ;
     RECT  88.8 49.333 89.88 59.749 ;
     RECT  6.576 59.459 8.112 60.469 ;
     RECT  6.576 60.469 8.232 60.517 ;
     RECT  6.432 60.517 8.232 60.563 ;
     RECT  7.8 60.563 8.232 60.947 ;
     RECT  5.232 59.701 5.256 61.091 ;
     RECT  88.8 59.749 90.216 61.091 ;
     RECT  87.6 60.901 87.624 61.619 ;
     RECT  0.192 59.461 0.312 61.667 ;
     RECT  88.8 61.091 89.88 62.099 ;
     RECT  0.288 61.667 0.312 62.195 ;
     RECT  6.432 60.563 6.6 63.253 ;
     RECT  0.192 63.493 0.216 63.541 ;
     RECT  0.192 63.541 0.312 64.115 ;
     RECT  2.4 59.027 2.712 64.117 ;
     RECT  2.304 64.117 2.712 64.259 ;
     RECT  5.664 63.253 6.6 64.307 ;
     RECT  7.8 60.947 8.112 65.509 ;
     RECT  0.288 64.115 0.312 65.795 ;
     RECT  2.4 64.259 2.712 66.565 ;
     RECT  6.432 64.307 6.6 66.709 ;
     RECT  7.68 65.509 8.112 66.709 ;
     RECT  0.192 66.661 0.216 66.805 ;
     RECT  6.432 66.709 8.112 67.187 ;
     RECT  0.192 66.805 0.312 67.379 ;
     RECT  2.4 66.565 2.856 67.379 ;
     RECT  46.944 59.797 46.968 67.427 ;
     RECT  24 26.003 24.312 67.525 ;
     RECT  0.192 67.379 0.216 67.619 ;
     RECT  88.8 62.099 89.736 68.725 ;
     RECT  0.288 68.341 0.312 68.867 ;
     RECT  88.224 68.725 89.736 68.915 ;
     RECT  3.936 68.245 3.96 69.107 ;
     RECT  90.816 67.717 90.84 69.203 ;
     RECT  2.4 67.379 2.712 69.205 ;
     RECT  87.168 68.245 87.192 69.301 ;
     RECT  86.64 69.301 87.192 69.347 ;
     RECT  88.224 68.915 89.112 69.445 ;
     RECT  55.248 67.525 55.272 69.587 ;
     RECT  24 67.525 24.84 69.683 ;
     RECT  7.8 67.187 8.112 69.685 ;
     RECT  67.2 2.151 67.512 69.685 ;
     RECT  67.104 69.685 67.512 69.827 ;
     RECT  6.432 67.187 6.6 70.019 ;
     RECT  87.744 69.445 89.112 70.307 ;
     RECT  0.288 69.829 0.312 70.355 ;
     RECT  88.08 70.307 89.112 70.355 ;
     RECT  88.224 70.355 89.112 70.499 ;
     RECT  2.304 69.205 2.712 70.739 ;
     RECT  5.376 70.981 5.4 71.317 ;
     RECT  6.576 70.019 6.6 71.317 ;
     RECT  88.704 70.499 89.112 71.411 ;
     RECT  7.8 69.685 8.808 71.459 ;
     RECT  49.44 70.645 49.464 71.651 ;
     RECT  5.376 71.317 6.6 71.843 ;
     RECT  86.64 69.347 86.664 71.843 ;
     RECT  2.4 70.739 2.712 72.469 ;
     RECT  2.4 72.469 2.808 72.611 ;
     RECT  87.264 71.845 87.288 72.659 ;
     RECT  2.4 72.611 2.712 72.757 ;
     RECT  90.576 72.709 90.6 72.757 ;
     RECT  48.24 72.325 48.264 72.851 ;
     RECT  90.48 72.757 90.6 72.853 ;
     RECT  2.304 72.757 2.712 72.899 ;
     RECT  88.8 71.411 89.112 72.901 ;
     RECT  7.8 71.459 8.376 73.091 ;
     RECT  88.8 72.901 89.208 73.429 ;
     RECT  90.48 72.853 91.176 73.429 ;
     RECT  88.8 73.429 91.176 73.477 ;
     RECT  3.936 72.565 3.96 73.571 ;
     RECT  88.8 73.477 91.752 73.571 ;
     RECT  91.728 73.571 91.752 74.771 ;
     RECT  4.368 74.389 4.392 75.395 ;
     RECT  92.304 74.869 92.328 75.683 ;
     RECT  88.8 73.571 90.072 76.213 ;
     RECT  88.8 76.213 90.552 76.309 ;
     RECT  0.288 76.309 0.312 76.595 ;
     RECT  88.8 76.309 90.6 77.125 ;
     RECT  6.24 71.843 6.6 78.037 ;
     RECT  88.8 77.125 91.176 78.131 ;
     RECT  90.48 78.131 91.176 78.229 ;
     RECT  48.432 78.037 48.456 79.043 ;
     RECT  90.48 78.229 91.464 79.139 ;
     RECT  2.4 72.899 2.712 79.141 ;
     RECT  91.44 79.139 91.464 79.283 ;
     RECT  6 78.037 6.6 79.621 ;
     RECT  2.4 79.141 3.432 79.859 ;
     RECT  6 79.621 6.792 79.859 ;
     RECT  6.24 79.859 6.792 80.341 ;
     RECT  7.8 73.091 8.112 80.341 ;
     RECT  6.24 80.341 8.112 80.531 ;
     RECT  90.384 80.293 90.408 80.819 ;
     RECT  2.4 79.859 3 80.963 ;
     RECT  6.576 80.531 8.112 81.205 ;
     RECT  86.88 77.941 86.904 81.587 ;
     RECT  6.576 81.205 8.376 81.733 ;
     RECT  2.4 80.963 2.712 82.021 ;
     RECT  5.856 81.733 8.376 82.213 ;
     RECT  2.4 82.021 2.808 82.691 ;
     RECT  4.512 82.549 4.536 82.691 ;
     RECT  5.664 82.213 8.376 82.691 ;
     RECT  91.728 81.445 91.752 82.691 ;
     RECT  6.576 82.691 8.376 83.267 ;
     RECT  0.192 83.509 0.216 84.179 ;
     RECT  6.576 83.267 8.232 85.139 ;
     RECT  87.072 84.325 87.096 85.523 ;
     RECT  2.4 82.691 2.712 85.717 ;
     RECT  90.336 84.373 90.36 85.955 ;
     RECT  0.288 85.669 0.312 85.957 ;
     RECT  2.304 85.717 2.712 85.957 ;
     RECT  4.512 85.381 4.536 86.099 ;
     RECT  0.288 85.957 0.36 86.245 ;
     RECT  0.192 86.245 0.36 86.291 ;
     RECT  0.192 86.291 0.312 86.579 ;
     RECT  6.576 85.139 8.112 86.581 ;
     RECT  88.8 78.131 89.208 86.581 ;
     RECT  2.304 85.957 2.856 86.821 ;
     RECT  91.056 86.293 91.176 87.251 ;
     RECT  0.288 86.579 0.312 87.347 ;
     RECT  2.304 86.821 3.432 87.827 ;
     RECT  88.8 86.581 90.024 87.827 ;
     RECT  91.056 87.251 91.08 87.875 ;
     RECT  0.192 87.829 0.216 88.549 ;
     RECT  6.576 86.581 8.472 88.643 ;
     RECT  2.304 87.827 2.808 88.885 ;
     RECT  14.592 88.885 14.616 89.315 ;
     RECT  21.648 88.213 21.672 89.461 ;
     RECT  24 69.683 24.312 89.461 ;
     RECT  18.6 2.151 18.912 89.509 ;
     RECT  15.888 88.309 15.912 89.555 ;
     RECT  88.8 87.827 89.352 89.555 ;
     RECT  91.104 89.461 91.128 89.557 ;
     RECT  2.304 88.885 2.856 89.651 ;
     RECT  12.144 88.597 12.168 89.699 ;
     RECT  21.648 89.461 22.2 89.699 ;
     RECT  91.104 89.557 91.176 89.845 ;
     RECT  45.6 2.151 45.912 90.037 ;
     RECT  0.192 88.549 0.504 90.083 ;
     RECT  9.984 88.885 10.008 90.083 ;
     RECT  22.176 89.699 22.2 90.131 ;
     RECT  91.104 89.845 91.752 90.229 ;
     RECT  90.576 90.229 91.752 90.421 ;
     RECT  6.576 88.643 8.112 90.563 ;
     RECT  15.408 90.229 15.432 90.563 ;
     RECT  18.192 89.509 18.912 90.565 ;
     RECT  90.576 90.421 91.992 90.755 ;
     RECT  88.8 89.555 89.112 90.757 ;
     RECT  90.576 90.755 90.6 90.757 ;
     RECT  0.24 90.083 0.504 90.851 ;
     RECT  85.968 88.933 85.992 90.947 ;
     RECT  22.8 90.901 22.824 91.139 ;
     RECT  45.6 90.037 46.536 91.235 ;
     RECT  90.528 90.757 90.6 91.235 ;
     RECT  91.728 90.755 91.992 91.235 ;
     RECT  87.936 90.757 89.112 91.331 ;
     RECT  90.528 91.235 90.552 91.331 ;
     RECT  24 89.461 24.408 91.379 ;
     RECT  38.16 91.141 38.184 91.619 ;
     RECT  71.424 69.877 71.448 91.619 ;
     RECT  18.192 90.565 19.704 91.717 ;
     RECT  18.192 91.717 19.944 91.763 ;
     RECT  2.304 89.651 2.808 91.811 ;
     RECT  52.704 90.565 52.728 91.907 ;
     RECT  76.272 91.141 76.296 91.907 ;
     RECT  0.336 90.851 0.504 91.955 ;
     RECT  0.336 91.955 0.456 92.003 ;
     RECT  2.304 91.811 2.712 92.051 ;
     RECT  18.192 91.763 18.912 92.339 ;
     RECT  19.92 91.763 19.944 92.387 ;
     RECT  0.432 92.003 0.456 92.435 ;
     RECT  13.2 2.151 13.512 92.821 ;
     RECT  29.4 2.151 29.712 92.821 ;
     RECT  34.8 2.151 35.112 92.821 ;
     RECT  56.4 2.151 56.712 92.821 ;
     RECT  61.8 2.151 62.112 92.821 ;
     RECT  78 2.151 78.312 92.821 ;
     RECT  2.4 92.051 2.712 92.889 ;
     RECT  7.8 90.563 8.112 92.889 ;
     RECT  18.24 92.339 18.912 92.889 ;
     RECT  24 91.379 24.312 92.889 ;
     RECT  34.032 92.821 35.112 92.889 ;
     RECT  40.2 2.151 40.512 92.889 ;
     RECT  45.6 91.235 45.912 92.889 ;
     RECT  51 2.151 51.312 92.889 ;
     RECT  61.44 92.821 62.112 92.889 ;
     RECT  67.2 69.827 67.512 92.889 ;
     RECT  72.6 25.715 72.912 92.889 ;
     RECT  77.232 92.821 78.312 92.889 ;
     RECT  83.4 2.151 83.712 92.889 ;
     RECT  88.8 91.331 89.112 92.889 ;
     RECT  2.4 92.889 2.52 92.903 ;
     RECT  7.8 92.889 7.92 92.903 ;
     RECT  13.2 92.821 14.184 92.903 ;
     RECT  18.24 92.889 18.72 92.903 ;
     RECT  24 92.889 24.12 92.903 ;
     RECT  29.4 92.821 29.928 92.903 ;
     RECT  34.032 92.889 34.92 92.903 ;
     RECT  40.2 92.889 40.32 92.903 ;
     RECT  45.6 92.889 45.72 92.903 ;
     RECT  51 92.889 51.12 92.903 ;
     RECT  56.4 92.821 57.384 92.903 ;
     RECT  61.44 92.889 61.92 92.903 ;
     RECT  67.2 92.889 67.32 92.903 ;
     RECT  72.6 92.889 72.72 92.903 ;
     RECT  77.232 92.889 78.12 92.903 ;
     RECT  83.4 92.889 83.52 92.903 ;
     RECT  88.8 92.889 88.92 92.903 ;
     RECT  2.712 5.507 2.808 6.661 ;
     RECT  89.304 7.859 89.688 9.061 ;
     RECT  4.584 9.061 6 9.731 ;
     RECT  4.536 12.325 6 12.419 ;
     RECT  87.528 14.197 88.8 17.075 ;
     RECT  24.312 15.443 24.744 16.501 ;
     RECT  6.264 17.317 7.68 18.181 ;
     RECT  89.304 19.379 89.976 19.813 ;
     RECT  89.304 19.813 90.576 20.533 ;
     RECT  90.6 19.813 91.728 20.579 ;
     RECT  87.816 19.909 88.8 20.579 ;
     RECT  90.6 20.579 91.704 20.627 ;
     RECT  90.072 20.627 91.704 21.395 ;
     RECT  0.288 21.155 0.312 21.589 ;
     RECT  89.304 21.395 91.704 21.637 ;
     RECT  0.288 21.589 0.336 22.549 ;
     RECT  89.304 21.637 90.576 22.739 ;
     RECT  90.6 21.637 91.704 21.973 ;
     RECT  90.6 21.973 91.68 22.117 ;
     RECT  6.264 22.021 7.68 22.211 ;
     RECT  3.432 22.645 4.656 22.741 ;
     RECT  89.304 22.739 91.152 22.835 ;
     RECT  89.304 22.835 91.176 23.797 ;
     RECT  89.304 23.797 90.576 24.611 ;
     RECT  89.304 24.611 89.496 25.429 ;
     RECT  6.504 26.245 7.8 27.205 ;
     RECT  2.856 27.877 4.08 28.163 ;
     RECT  89.112 27.971 89.448 29.029 ;
     RECT  2.808 28.163 4.08 28.547 ;
     RECT  0.288 28.451 0.312 29.509 ;
     RECT  2.712 28.547 4.08 29.123 ;
     RECT  2.712 29.123 2.808 30.181 ;
     RECT  6.456 29.123 7.8 31.859 ;
     RECT  6.36 31.859 7.8 33.589 ;
     RECT  6.36 34.115 7.8 35.077 ;
     RECT  6.36 35.077 7.392 35.123 ;
     RECT  0.288 36.515 0.312 37.477 ;
     RECT  89.496 39.203 89.976 40.405 ;
     RECT  6.312 45.013 7.8 47.555 ;
     RECT  2.808 46.597 3.936 46.691 ;
     RECT  2.712 46.691 3.936 46.787 ;
     RECT  8.112 46.787 8.376 47.749 ;
     RECT  6.288 47.555 7.8 47.845 ;
     RECT  6.288 47.845 6.576 48.997 ;
     RECT  6.6 47.845 7.8 48.421 ;
     RECT  5.112 48.997 6.576 50.291 ;
     RECT  5.904 50.291 6.576 50.677 ;
     RECT  6.6 50.867 7.8 55.573 ;
     RECT  87.528 53.557 88.8 54.611 ;
     RECT  87.504 54.611 88.8 54.661 ;
     RECT  87.336 54.661 88.8 56.531 ;
     RECT  4.536 55.237 5.568 55.955 ;
     RECT  5.592 55.619 6.576 55.955 ;
     RECT  87.504 56.531 88.8 56.965 ;
     RECT  87.528 56.965 88.8 59.171 ;
     RECT  8.112 59.459 8.232 60.469 ;
     RECT  5.256 59.701 6.576 60.517 ;
     RECT  45.912 59.797 46.944 67.427 ;
     RECT  5.256 60.517 6.432 61.091 ;
     RECT  6.6 60.563 7.8 65.509 ;
     RECT  87.624 60.901 88.8 61.619 ;
     RECT  0.288 62.195 0.312 63.493 ;
     RECT  0.24 63.493 0.312 63.541 ;
     RECT  6.6 65.509 7.68 66.709 ;
     RECT  0.288 65.795 0.312 66.661 ;
     RECT  0.24 66.661 0.312 66.744 ;
     RECT  0.216 66.744 0.312 66.768 ;
     RECT  0.24 66.768 0.312 66.805 ;
     RECT  6.6 67.187 7.8 79.621 ;
     RECT  0.24 67.379 0.312 67.464 ;
     RECT  2.712 67.379 2.856 68.245 ;
     RECT  0.216 67.464 0.312 67.619 ;
     RECT  55.272 67.525 56.4 69.587 ;
     RECT  0.288 67.619 0.312 68.341 ;
     RECT  89.736 67.717 90.816 68.915 ;
     RECT  2.712 68.245 3.936 69.107 ;
     RECT  87.192 68.725 88.224 69.347 ;
     RECT  0.288 68.867 0.312 69.829 ;
     RECT  86.664 69.347 88.224 69.445 ;
     RECT  86.664 69.445 87.744 70.307 ;
     RECT  71.448 69.877 72.6 91.619 ;
     RECT  6.432 70.019 6.576 70.981 ;
     RECT  86.664 70.307 88.08 70.355 ;
     RECT  86.664 70.355 88.224 70.499 ;
     RECT  86.664 70.499 88.704 71.411 ;
     RECT  5.4 70.981 6.576 71.317 ;
     RECT  86.664 71.411 88.8 71.843 ;
     RECT  87.264 71.843 88.8 71.845 ;
     RECT  87.288 71.845 88.8 72.659 ;
     RECT  2.808 72.565 3.936 72.611 ;
     RECT  2.712 72.611 3.936 73.571 ;
     RECT  89.112 72.709 90.576 72.757 ;
     RECT  89.112 72.757 90.48 72.901 ;
     RECT  89.208 72.901 90.48 73.429 ;
     RECT  89.208 78.131 90.48 79.139 ;
     RECT  89.208 79.139 91.44 79.283 ;
     RECT  89.208 79.283 90.408 80.293 ;
     RECT  6.792 79.621 7.8 80.341 ;
     RECT  89.208 80.293 90.384 80.819 ;
     RECT  6.24 80.531 6.576 81.733 ;
     RECT  2.712 80.963 2.808 82.021 ;
     RECT  4.536 82.549 5.664 82.691 ;
     RECT  89.208 84.373 90.336 85.955 ;
     RECT  8.112 85.139 8.232 86.581 ;
     RECT  89.208 85.955 90.36 86.293 ;
     RECT  89.208 86.293 91.056 86.581 ;
     RECT  0.192 86.579 0.288 86.64 ;
     RECT  90.024 86.581 91.056 87.827 ;
     RECT  0.24 86.64 0.288 86.76 ;
     RECT  0.192 86.76 0.288 86.784 ;
     RECT  0.24 86.784 0.288 86.904 ;
     RECT  0.192 86.904 0.288 86.928 ;
     RECT  0.24 86.928 0.288 87.048 ;
     RECT  0.192 87.048 0.288 87.072 ;
     RECT  0.24 87.072 0.288 87.192 ;
     RECT  0.192 87.192 0.288 87.216 ;
     RECT  0.24 87.216 0.288 87.336 ;
     RECT  0.192 87.336 0.288 87.347 ;
     RECT  0.192 87.347 0.312 87.36 ;
     RECT  0.24 87.36 0.312 87.48 ;
     RECT  0.192 87.48 0.312 87.504 ;
     RECT  0.24 87.504 0.312 87.624 ;
     RECT  0.192 87.624 0.312 87.792 ;
     RECT  0.24 87.792 0.312 87.912 ;
     RECT  2.808 87.827 2.856 88.885 ;
     RECT  0.216 87.912 0.312 87.936 ;
     RECT  0.24 87.936 0.312 88.056 ;
     RECT  0.216 88.056 0.312 88.08 ;
     RECT  0.24 88.08 0.312 88.2 ;
     RECT  0.216 88.2 0.312 88.224 ;
     RECT  0.24 88.224 0.312 88.344 ;
     RECT  0.216 88.344 0.312 88.368 ;
     RECT  0.24 88.368 0.312 88.488 ;
     RECT  0.216 88.488 0.312 88.512 ;
     RECT  0.24 88.512 0.312 88.549 ;
     RECT  12.168 88.597 13.2 89.699 ;
     RECT  13.512 88.885 14.592 89.315 ;
     RECT  14.616 88.885 15.888 89.315 ;
     RECT  15.408 89.315 15.888 89.555 ;
     RECT  15.408 89.555 15.432 90.229 ;
     RECT  89.112 89.555 89.352 90.229 ;
     RECT  89.112 90.229 90.576 90.757 ;
     RECT  51.312 90.565 52.704 91.907 ;
     RECT  90.6 90.755 91.728 91.235 ;
     RECT  89.112 90.757 90.528 91.331 ;
     RECT  22.824 90.901 24 91.139 ;
     RECT  18.912 91.763 19.92 92.387 ;
  END
END dsfd_vm_static_landing_lane2
END LIBRARY
